<?xml version="1.0" encoding="utf-8" standalone="no"?>
<device schemaVersion="1.1">
  <name>STM32L152VBT6</name>
  <version>1.0</version>
  <description>STM32L152C6T6,STM32L152C6T6A,STM32L152C6U6,STM32L152C6U6A,STM32L152C8T6,STM32L152C8T6A,STM32L152C8U6,STM32L152C8U6A,STM32L152CBT6,STM32L152CBU6,STM32L152R6H6,STM32L152R6H6A,STM32L152R6T6,STM32L152R6T6A,STM32L152R8H6,STM32L152R8H6A,STM32L152R8T6,STM32L152R8T6A,STM32L152RBH6,STM32L152RBT6,STM32L152V8H6,STM32L152V8H6A,STM32L152V8T6,STM32L152V8T6A,STM32L152VBH6,STM32L152VBT6</description>
  <addressUnitBits>8</addressUnitBits>
  <width>32</width>
  <size>0x20</size>
  <resetValue>0</resetValue>
  <resetMask>0xFFFFFFFF</resetMask>
  <peripherals>
    <peripheral>
      <name>OB</name>
      <baseAddress>0x1ff80000</baseAddress>
      <registers>
        <register>
          <name>RDP</name>
          <addressOffset>0x0</addressOffset>
          <size>0x20</size>
        </register>
        <register>
          <name>USER</name>
          <addressOffset>0x4</addressOffset>
          <size>0x20</size>
        </register>
        <register>
          <name>WRP01</name>
          <addressOffset>0x8</addressOffset>
          <size>0x20</size>
        </register>
        <register>
          <name>WRP23</name>
          <addressOffset>0xc</addressOffset>
          <size>0x20</size>
        </register>
      </registers>
    </peripheral>
    <peripheral>
      <name>TIM2</name>
      <baseAddress>0x40000000</baseAddress>
      <registers>
        <register>
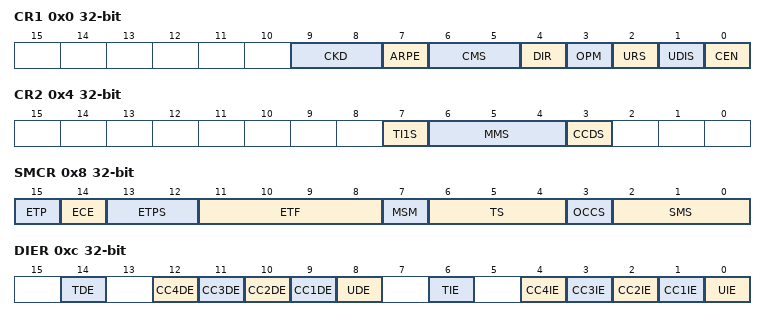
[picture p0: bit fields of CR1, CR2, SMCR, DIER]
          <name>CR1</name>
          <addressOffset>0x0</addressOffset>
          <size>0x20</size>
          <fields>
            <field>
              <name>CEN</name>
              <bitOffset>0</bitOffset>
              <bitWidth>1</bitWidth>
            </field>
            <field>
              <name>UDIS</name>
              <bitOffset>1</bitOffset>
              <bitWidth>1</bitWidth>
            </field>
            <field>
              <name>URS</name>
              <bitOffset>2</bitOffset>
              <bitWidth>1</bitWidth>
            </field>
            <field>
              <name>OPM</name>
              <bitOffset>3</bitOffset>
              <bitWidth>1</bitWidth>
            </field>
            <field>
              <name>DIR</name>
              <bitOffset>4</bitOffset>
              <bitWidth>1</bitWidth>
            </field>
            <field>
              <name>CMS</name>
              <bitOffset>5</bitOffset>
              <bitWidth>2</bitWidth>
            </field>
            <field>
              <name>ARPE</name>
              <bitOffset>7</bitOffset>
              <bitWidth>1</bitWidth>
            </field>
            <field>
              <name>CKD</name>
              <bitOffset>8</bitOffset>
              <bitWidth>2</bitWidth>
            </field>
          </fields>
        </register>
        <register>
          <name>CR2</name>
          <addressOffset>0x4</addressOffset>
          <size>0x20</size>
          <fields>
            <field>
              <name>CCDS</name>
              <bitOffset>3</bitOffset>
              <bitWidth>1</bitWidth>
            </field>
            <field>
              <name>MMS</name>
              <bitOffset>4</bitOffset>
              <bitWidth>3</bitWidth>
            </field>
            <field>
              <name>TI1S</name>
              <bitOffset>7</bitOffset>
              <bitWidth>1</bitWidth>
            </field>
          </fields>
        </register>
        <register>
          <name>SMCR</name>
          <addressOffset>0x8</addressOffset>
          <size>0x20</size>
          <fields>
            <field>
              <name>SMS</name>
              <bitOffset>0</bitOffset>
              <bitWidth>3</bitWidth>
            </field>
            <field>
              <name>OCCS</name>
              <bitOffset>3</bitOffset>
              <bitWidth>1</bitWidth>
            </field>
            <field>
              <name>TS</name>
              <bitOffset>4</bitOffset>
              <bitWidth>3</bitWidth>
            </field>
            <field>
              <name>MSM</name>
              <bitOffset>7</bitOffset>
              <bitWidth>1</bitWidth>
            </field>
            <field>
              <name>ETF</name>
              <bitOffset>8</bitOffset>
              <bitWidth>4</bitWidth>
            </field>
            <field>
              <name>ETPS</name>
              <bitOffset>12</bitOffset>
              <bitWidth>2</bitWidth>
            </field>
            <field>
              <name>ECE</name>
              <bitOffset>14</bitOffset>
              <bitWidth>1</bitWidth>
            </field>
            <field>
              <name>ETP</name>
              <bitOffset>15</bitOffset>
              <bitWidth>1</bitWidth>
            </field>
          </fields>
        </register>
        <register>
          <name>DIER</name>
          <addressOffset>0xc</addressOffset>
          <size>0x20</size>
          <fields>
            <field>
              <name>UIE</name>
              <bitOffset>0</bitOffset>
              <bitWidth>1</bitWidth>
            </field>
            <field>
              <name>CC1IE</name>
              <bitOffset>1</bitOffset>
              <bitWidth>1</bitWidth>
            </field>
            <field>
              <name>CC2IE</name>
              <bitOffset>2</bitOffset>
              <bitWidth>1</bitWidth>
            </field>
            <field>
              <name>CC3IE</name>
              <bitOffset>3</bitOffset>
              <bitWidth>1</bitWidth>
            </field>
            <field>
              <name>CC4IE</name>
              <bitOffset>4</bitOffset>
              <bitWidth>1</bitWidth>
            </field>
            <field>
              <name>TIE</name>
              <bitOffset>6</bitOffset>
              <bitWidth>1</bitWidth>
            </field>
            <field>
              <name>UDE</name>
              <bitOffset>8</bitOffset>
              <bitWidth>1</bitWidth>
            </field>
            <field>
              <name>CC1DE</name>
              <bitOffset>9</bitOffset>
              <bitWidth>1</bitWidth>
            </field>
            <field>
              <name>CC2DE</name>
              <bitOffset>10</bitOffset>
              <bitWidth>1</bitWidth>
            </field>
            <field>
              <name>CC3DE</name>
              <bitOffset>11</bitOffset>
              <bitWidth>1</bitWidth>
            </field>
            <field>
              <name>CC4DE</name>
              <bitOffset>12</bitOffset>
              <bitWidth>1</bitWidth>
            </field>
            <field>
              <name>TDE</name>
              <bitOffset>14</bitOffset>
              <bitWidth>1</bitWidth>
            </field>
          </fields>
        </register>
        <register>
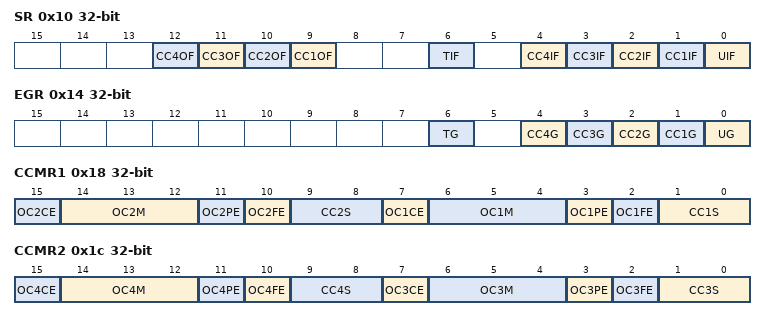
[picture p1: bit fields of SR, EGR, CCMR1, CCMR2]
          <name>SR</name>
          <addressOffset>0x10</addressOffset>
          <size>0x20</size>
          <fields>
            <field>
              <name>UIF</name>
              <bitOffset>0</bitOffset>
              <bitWidth>1</bitWidth>
            </field>
            <field>
              <name>CC1IF</name>
              <bitOffset>1</bitOffset>
              <bitWidth>1</bitWidth>
            </field>
            <field>
              <name>CC2IF</name>
              <bitOffset>2</bitOffset>
              <bitWidth>1</bitWidth>
            </field>
            <field>
              <name>CC3IF</name>
              <bitOffset>3</bitOffset>
              <bitWidth>1</bitWidth>
            </field>
            <field>
              <name>CC4IF</name>
              <bitOffset>4</bitOffset>
              <bitWidth>1</bitWidth>
            </field>
            <field>
              <name>TIF</name>
              <bitOffset>6</bitOffset>
              <bitWidth>1</bitWidth>
            </field>
            <field>
              <name>CC1OF</name>
              <bitOffset>9</bitOffset>
              <bitWidth>1</bitWidth>
            </field>
            <field>
              <name>CC2OF</name>
              <bitOffset>10</bitOffset>
              <bitWidth>1</bitWidth>
            </field>
            <field>
              <name>CC3OF</name>
              <bitOffset>11</bitOffset>
              <bitWidth>1</bitWidth>
            </field>
            <field>
              <name>CC4OF</name>
              <bitOffset>12</bitOffset>
              <bitWidth>1</bitWidth>
            </field>
          </fields>
        </register>
        <register>
          <name>EGR</name>
          <addressOffset>0x14</addressOffset>
          <size>0x20</size>
          <fields>
            <field>
              <name>UG</name>
              <bitOffset>0</bitOffset>
              <bitWidth>1</bitWidth>
            </field>
            <field>
              <name>CC1G</name>
              <bitOffset>1</bitOffset>
              <bitWidth>1</bitWidth>
            </field>
            <field>
              <name>CC2G</name>
              <bitOffset>2</bitOffset>
              <bitWidth>1</bitWidth>
            </field>
            <field>
              <name>CC3G</name>
              <bitOffset>3</bitOffset>
              <bitWidth>1</bitWidth>
            </field>
            <field>
              <name>CC4G</name>
              <bitOffset>4</bitOffset>
              <bitWidth>1</bitWidth>
            </field>
            <field>
              <name>TG</name>
              <bitOffset>6</bitOffset>
              <bitWidth>1</bitWidth>
            </field>
          </fields>
        </register>
        <register>
          <name>CCMR1</name>
          <addressOffset>0x18</addressOffset>
          <size>0x20</size>
          <fields>
            <field>
              <name>CC1S</name>
              <bitOffset>0</bitOffset>
              <bitWidth>2</bitWidth>
            </field>
            <field>
              <name>OC1FE</name>
              <bitOffset>2</bitOffset>
              <bitWidth>1</bitWidth>
            </field>
            <field>
              <name>OC1PE</name>
              <bitOffset>3</bitOffset>
              <bitWidth>1</bitWidth>
            </field>
            <field>
              <name>OC1M</name>
              <bitOffset>4</bitOffset>
              <bitWidth>3</bitWidth>
            </field>
            <field>
              <name>OC1CE</name>
              <bitOffset>7</bitOffset>
              <bitWidth>1</bitWidth>
            </field>
            <field>
              <name>CC2S</name>
              <bitOffset>8</bitOffset>
              <bitWidth>2</bitWidth>
            </field>
            <field>
              <name>OC2FE</name>
              <bitOffset>10</bitOffset>
              <bitWidth>1</bitWidth>
            </field>
            <field>
              <name>OC2PE</name>
              <bitOffset>11</bitOffset>
              <bitWidth>1</bitWidth>
            </field>
            <field>
              <name>OC2M</name>
              <bitOffset>12</bitOffset>
              <bitWidth>3</bitWidth>
            </field>
            <field>
              <name>OC2CE</name>
              <bitOffset>15</bitOffset>
              <bitWidth>1</bitWidth>
            </field>
          </fields>
        </register>
        <register>
          <name>CCMR2</name>
          <addressOffset>0x1c</addressOffset>
          <size>0x20</size>
          <fields>
            <field>
              <name>CC3S</name>
              <bitOffset>0</bitOffset>
              <bitWidth>2</bitWidth>
            </field>
            <field>
              <name>OC3FE</name>
              <bitOffset>2</bitOffset>
              <bitWidth>1</bitWidth>
            </field>
            <field>
              <name>OC3PE</name>
              <bitOffset>3</bitOffset>
              <bitWidth>1</bitWidth>
            </field>
            <field>
              <name>OC3M</name>
              <bitOffset>4</bitOffset>
              <bitWidth>3</bitWidth>
            </field>
            <field>
              <name>OC3CE</name>
              <bitOffset>7</bitOffset>
              <bitWidth>1</bitWidth>
            </field>
            <field>
              <name>CC4S</name>
              <bitOffset>8</bitOffset>
              <bitWidth>2</bitWidth>
            </field>
            <field>
              <name>OC4FE</name>
              <bitOffset>10</bitOffset>
              <bitWidth>1</bitWidth>
            </field>
            <field>
              <name>OC4PE</name>
              <bitOffset>11</bitOffset>
              <bitWidth>1</bitWidth>
            </field>
            <field>
              <name>OC4M</name>
              <bitOffset>12</bitOffset>
              <bitWidth>3</bitWidth>
            </field>
            <field>
              <name>OC4CE</name>
              <bitOffset>15</bitOffset>
              <bitWidth>1</bitWidth>
            </field>
          </fields>
        </register>
        <register>
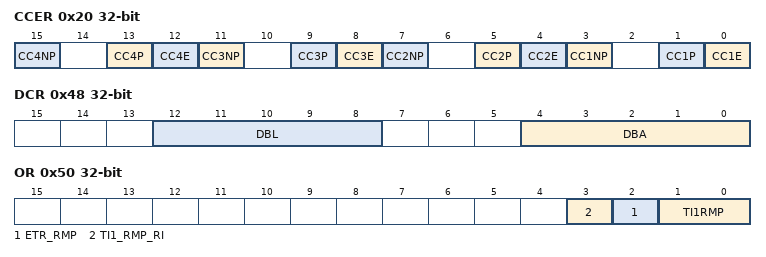
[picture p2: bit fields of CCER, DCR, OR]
          <name>CCER</name>
          <addressOffset>0x20</addressOffset>
          <size>0x20</size>
          <fields>
            <field>
              <name>CC1E</name>
              <bitOffset>0</bitOffset>
              <bitWidth>1</bitWidth>
            </field>
            <field>
              <name>CC1P</name>
              <bitOffset>1</bitOffset>
              <bitWidth>1</bitWidth>
            </field>
            <field>
              <name>CC1NP</name>
              <bitOffset>3</bitOffset>
              <bitWidth>1</bitWidth>
            </field>
            <field>
              <name>CC2E</name>
              <bitOffset>4</bitOffset>
              <bitWidth>1</bitWidth>
            </field>
            <field>
              <name>CC2P</name>
              <bitOffset>5</bitOffset>
              <bitWidth>1</bitWidth>
            </field>
            <field>
              <name>CC2NP</name>
              <bitOffset>7</bitOffset>
              <bitWidth>1</bitWidth>
            </field>
            <field>
              <name>CC3E</name>
              <bitOffset>8</bitOffset>
              <bitWidth>1</bitWidth>
            </field>
            <field>
              <name>CC3P</name>
              <bitOffset>9</bitOffset>
              <bitWidth>1</bitWidth>
            </field>
            <field>
              <name>CC3NP</name>
              <bitOffset>11</bitOffset>
              <bitWidth>1</bitWidth>
            </field>
            <field>
              <name>CC4E</name>
              <bitOffset>12</bitOffset>
              <bitWidth>1</bitWidth>
            </field>
            <field>
              <name>CC4P</name>
              <bitOffset>13</bitOffset>
              <bitWidth>1</bitWidth>
            </field>
            <field>
              <name>CC4NP</name>
              <bitOffset>15</bitOffset>
              <bitWidth>1</bitWidth>
            </field>
          </fields>
        </register>
        <register>
          <name>CNT</name>
          <addressOffset>0x24</addressOffset>
          <size>0x20</size>
          <fields>
            <field>
              <name>CNT</name>
              <bitOffset>0</bitOffset>
              <bitWidth>32</bitWidth>
            </field>
          </fields>
        </register>
        <register>
          <name>PSC</name>
          <addressOffset>0x28</addressOffset>
          <size>0x20</size>
          <fields>
            <field>
              <name>PSC</name>
              <bitOffset>0</bitOffset>
              <bitWidth>16</bitWidth>
            </field>
          </fields>
        </register>
        <register>
          <name>ARR</name>
          <addressOffset>0x2c</addressOffset>
          <size>0x20</size>
          <fields>
            <field>
              <name>ARR</name>
              <bitOffset>0</bitOffset>
              <bitWidth>32</bitWidth>
            </field>
          </fields>
        </register>
        <register>
          <name>CCR1</name>
          <addressOffset>0x34</addressOffset>
          <size>0x20</size>
          <fields>
            <field>
              <name>CCR1</name>
              <bitOffset>0</bitOffset>
              <bitWidth>16</bitWidth>
            </field>
          </fields>
        </register>
        <register>
          <name>CCR2</name>
          <addressOffset>0x38</addressOffset>
          <size>0x20</size>
          <fields>
            <field>
              <name>CCR2</name>
              <bitOffset>0</bitOffset>
              <bitWidth>16</bitWidth>
            </field>
          </fields>
        </register>
        <register>
          <name>CCR3</name>
          <addressOffset>0x3c</addressOffset>
          <size>0x20</size>
          <fields>
            <field>
              <name>CCR3</name>
              <bitOffset>0</bitOffset>
              <bitWidth>16</bitWidth>
            </field>
          </fields>
        </register>
        <register>
          <name>CCR4</name>
          <addressOffset>0x40</addressOffset>
          <size>0x20</size>
          <fields>
            <field>
              <name>CCR4</name>
              <bitOffset>0</bitOffset>
              <bitWidth>16</bitWidth>
            </field>
          </fields>
        </register>
        <register>
          <name>DCR</name>
          <addressOffset>0x48</addressOffset>
          <size>0x20</size>
          <fields>
            <field>
              <name>DBA</name>
              <bitOffset>0</bitOffset>
              <bitWidth>5</bitWidth>
            </field>
            <field>
              <name>DBL</name>
              <bitOffset>8</bitOffset>
              <bitWidth>5</bitWidth>
            </field>
          </fields>
        </register>
        <register>
          <name>DMAR</name>
          <addressOffset>0x4c</addressOffset>
          <size>0x20</size>
          <fields>
            <field>
              <name>DMAB</name>
              <bitOffset>0</bitOffset>
              <bitWidth>16</bitWidth>
            </field>
          </fields>
        </register>
        <register>
          <name>OR</name>
          <addressOffset>0x50</addressOffset>
          <size>0x20</size>
          <fields>
            <field>
              <name>TI1RMP</name>
              <bitOffset>0</bitOffset>
              <bitWidth>2</bitWidth>
            </field>
            <field>
              <name>ETR_RMP</name>
              <bitOffset>2</bitOffset>
              <bitWidth>1</bitWidth>
            </field>
            <field>
              <name>TI1_RMP_RI</name>
              <bitOffset>3</bitOffset>
              <bitWidth>1</bitWidth>
            </field>
          </fields>
        </register>
      </registers>
    </peripheral>
    <peripheral>
      <name>TIM3</name>
      <baseAddress>0x40000400</baseAddress>
      <registers>
        <register>
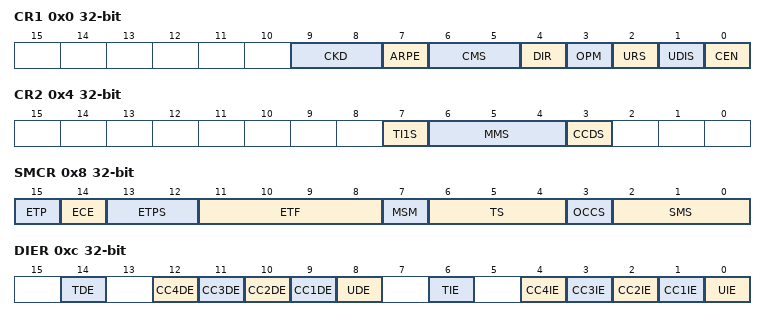
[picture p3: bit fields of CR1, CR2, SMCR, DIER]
          <name>CR1</name>
          <addressOffset>0x0</addressOffset>
          <size>0x20</size>
          <fields>
            <field>
              <name>CEN</name>
              <bitOffset>0</bitOffset>
              <bitWidth>1</bitWidth>
            </field>
            <field>
              <name>UDIS</name>
              <bitOffset>1</bitOffset>
              <bitWidth>1</bitWidth>
            </field>
            <field>
              <name>URS</name>
              <bitOffset>2</bitOffset>
              <bitWidth>1</bitWidth>
            </field>
            <field>
              <name>OPM</name>
              <bitOffset>3</bitOffset>
              <bitWidth>1</bitWidth>
            </field>
            <field>
              <name>DIR</name>
              <bitOffset>4</bitOffset>
              <bitWidth>1</bitWidth>
            </field>
            <field>
              <name>CMS</name>
              <bitOffset>5</bitOffset>
              <bitWidth>2</bitWidth>
            </field>
            <field>
              <name>ARPE</name>
              <bitOffset>7</bitOffset>
              <bitWidth>1</bitWidth>
            </field>
            <field>
              <name>CKD</name>
              <bitOffset>8</bitOffset>
              <bitWidth>2</bitWidth>
            </field>
          </fields>
        </register>
        <register>
          <name>CR2</name>
          <addressOffset>0x4</addressOffset>
          <size>0x20</size>
          <fields>
            <field>
              <name>CCDS</name>
              <bitOffset>3</bitOffset>
              <bitWidth>1</bitWidth>
            </field>
            <field>
              <name>MMS</name>
              <bitOffset>4</bitOffset>
              <bitWidth>3</bitWidth>
            </field>
            <field>
              <name>TI1S</name>
              <bitOffset>7</bitOffset>
              <bitWidth>1</bitWidth>
            </field>
          </fields>
        </register>
        <register>
          <name>SMCR</name>
          <addressOffset>0x8</addressOffset>
          <size>0x20</size>
          <fields>
            <field>
              <name>SMS</name>
              <bitOffset>0</bitOffset>
              <bitWidth>3</bitWidth>
            </field>
            <field>
              <name>OCCS</name>
              <bitOffset>3</bitOffset>
              <bitWidth>1</bitWidth>
            </field>
            <field>
              <name>TS</name>
              <bitOffset>4</bitOffset>
              <bitWidth>3</bitWidth>
            </field>
            <field>
              <name>MSM</name>
              <bitOffset>7</bitOffset>
              <bitWidth>1</bitWidth>
            </field>
            <field>
              <name>ETF</name>
              <bitOffset>8</bitOffset>
              <bitWidth>4</bitWidth>
            </field>
            <field>
              <name>ETPS</name>
              <bitOffset>12</bitOffset>
              <bitWidth>2</bitWidth>
            </field>
            <field>
              <name>ECE</name>
              <bitOffset>14</bitOffset>
              <bitWidth>1</bitWidth>
            </field>
            <field>
              <name>ETP</name>
              <bitOffset>15</bitOffset>
              <bitWidth>1</bitWidth>
            </field>
          </fields>
        </register>
        <register>
          <name>DIER</name>
          <addressOffset>0xc</addressOffset>
          <size>0x20</size>
          <fields>
            <field>
              <name>UIE</name>
              <bitOffset>0</bitOffset>
              <bitWidth>1</bitWidth>
            </field>
            <field>
              <name>CC1IE</name>
              <bitOffset>1</bitOffset>
              <bitWidth>1</bitWidth>
            </field>
            <field>
              <name>CC2IE</name>
              <bitOffset>2</bitOffset>
              <bitWidth>1</bitWidth>
            </field>
            <field>
              <name>CC3IE</name>
              <bitOffset>3</bitOffset>
              <bitWidth>1</bitWidth>
            </field>
            <field>
              <name>CC4IE</name>
              <bitOffset>4</bitOffset>
              <bitWidth>1</bitWidth>
            </field>
            <field>
              <name>TIE</name>
              <bitOffset>6</bitOffset>
              <bitWidth>1</bitWidth>
            </field>
            <field>
              <name>UDE</name>
              <bitOffset>8</bitOffset>
              <bitWidth>1</bitWidth>
            </field>
            <field>
              <name>CC1DE</name>
              <bitOffset>9</bitOffset>
              <bitWidth>1</bitWidth>
            </field>
            <field>
              <name>CC2DE</name>
              <bitOffset>10</bitOffset>
              <bitWidth>1</bitWidth>
            </field>
            <field>
              <name>CC3DE</name>
              <bitOffset>11</bitOffset>
              <bitWidth>1</bitWidth>
            </field>
            <field>
              <name>CC4DE</name>
              <bitOffset>12</bitOffset>
              <bitWidth>1</bitWidth>
            </field>
            <field>
              <name>TDE</name>
              <bitOffset>14</bitOffset>
              <bitWidth>1</bitWidth>
            </field>
          </fields>
        </register>
        <register>
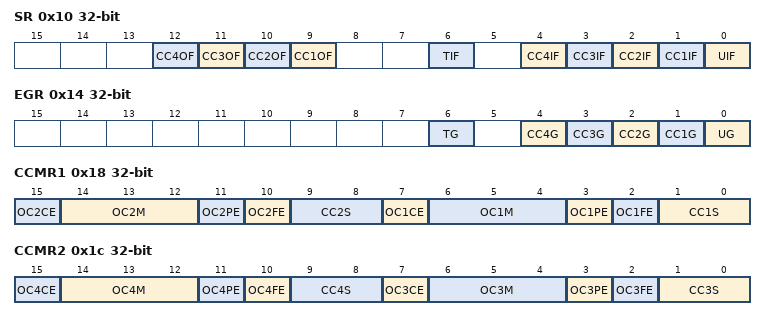
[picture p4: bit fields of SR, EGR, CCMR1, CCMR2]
          <name>SR</name>
          <addressOffset>0x10</addressOffset>
          <size>0x20</size>
          <fields>
            <field>
              <name>UIF</name>
              <bitOffset>0</bitOffset>
              <bitWidth>1</bitWidth>
            </field>
            <field>
              <name>CC1IF</name>
              <bitOffset>1</bitOffset>
              <bitWidth>1</bitWidth>
            </field>
            <field>
              <name>CC2IF</name>
              <bitOffset>2</bitOffset>
              <bitWidth>1</bitWidth>
            </field>
            <field>
              <name>CC3IF</name>
              <bitOffset>3</bitOffset>
              <bitWidth>1</bitWidth>
            </field>
            <field>
              <name>CC4IF</name>
              <bitOffset>4</bitOffset>
              <bitWidth>1</bitWidth>
            </field>
            <field>
              <name>TIF</name>
              <bitOffset>6</bitOffset>
              <bitWidth>1</bitWidth>
            </field>
            <field>
              <name>CC1OF</name>
              <bitOffset>9</bitOffset>
              <bitWidth>1</bitWidth>
            </field>
            <field>
              <name>CC2OF</name>
              <bitOffset>10</bitOffset>
              <bitWidth>1</bitWidth>
            </field>
            <field>
              <name>CC3OF</name>
              <bitOffset>11</bitOffset>
              <bitWidth>1</bitWidth>
            </field>
            <field>
              <name>CC4OF</name>
              <bitOffset>12</bitOffset>
              <bitWidth>1</bitWidth>
            </field>
          </fields>
        </register>
        <register>
          <name>EGR</name>
          <addressOffset>0x14</addressOffset>
          <size>0x20</size>
          <fields>
            <field>
              <name>UG</name>
              <bitOffset>0</bitOffset>
              <bitWidth>1</bitWidth>
            </field>
            <field>
              <name>CC1G</name>
              <bitOffset>1</bitOffset>
              <bitWidth>1</bitWidth>
            </field>
            <field>
              <name>CC2G</name>
              <bitOffset>2</bitOffset>
              <bitWidth>1</bitWidth>
            </field>
            <field>
              <name>CC3G</name>
              <bitOffset>3</bitOffset>
              <bitWidth>1</bitWidth>
            </field>
            <field>
              <name>CC4G</name>
              <bitOffset>4</bitOffset>
              <bitWidth>1</bitWidth>
            </field>
            <field>
              <name>TG</name>
              <bitOffset>6</bitOffset>
              <bitWidth>1</bitWidth>
            </field>
          </fields>
        </register>
        <register>
          <name>CCMR1</name>
          <addressOffset>0x18</addressOffset>
          <size>0x20</size>
          <fields>
            <field>
              <name>CC1S</name>
              <bitOffset>0</bitOffset>
              <bitWidth>2</bitWidth>
            </field>
            <field>
              <name>OC1FE</name>
              <bitOffset>2</bitOffset>
              <bitWidth>1</bitWidth>
            </field>
            <field>
              <name>OC1PE</name>
              <bitOffset>3</bitOffset>
              <bitWidth>1</bitWidth>
            </field>
            <field>
              <name>OC1M</name>
              <bitOffset>4</bitOffset>
              <bitWidth>3</bitWidth>
            </field>
            <field>
              <name>OC1CE</name>
              <bitOffset>7</bitOffset>
              <bitWidth>1</bitWidth>
            </field>
            <field>
              <name>CC2S</name>
              <bitOffset>8</bitOffset>
              <bitWidth>2</bitWidth>
            </field>
            <field>
              <name>OC2FE</name>
              <bitOffset>10</bitOffset>
              <bitWidth>1</bitWidth>
            </field>
            <field>
              <name>OC2PE</name>
              <bitOffset>11</bitOffset>
              <bitWidth>1</bitWidth>
            </field>
            <field>
              <name>OC2M</name>
              <bitOffset>12</bitOffset>
              <bitWidth>3</bitWidth>
            </field>
            <field>
              <name>OC2CE</name>
              <bitOffset>15</bitOffset>
              <bitWidth>1</bitWidth>
            </field>
          </fields>
        </register>
        <register>
          <name>CCMR2</name>
          <addressOffset>0x1c</addressOffset>
          <size>0x20</size>
          <fields>
            <field>
              <name>CC3S</name>
              <bitOffset>0</bitOffset>
              <bitWidth>2</bitWidth>
            </field>
            <field>
              <name>OC3FE</name>
              <bitOffset>2</bitOffset>
              <bitWidth>1</bitWidth>
            </field>
            <field>
              <name>OC3PE</name>
              <bitOffset>3</bitOffset>
              <bitWidth>1</bitWidth>
            </field>
            <field>
              <name>OC3M</name>
              <bitOffset>4</bitOffset>
              <bitWidth>3</bitWidth>
            </field>
            <field>
              <name>OC3CE</name>
              <bitOffset>7</bitOffset>
              <bitWidth>1</bitWidth>
            </field>
            <field>
              <name>CC4S</name>
              <bitOffset>8</bitOffset>
              <bitWidth>2</bitWidth>
            </field>
            <field>
              <name>OC4FE</name>
              <bitOffset>10</bitOffset>
              <bitWidth>1</bitWidth>
            </field>
            <field>
              <name>OC4PE</name>
              <bitOffset>11</bitOffset>
              <bitWidth>1</bitWidth>
            </field>
            <field>
              <name>OC4M</name>
              <bitOffset>12</bitOffset>
              <bitWidth>3</bitWidth>
            </field>
            <field>
              <name>OC4CE</name>
              <bitOffset>15</bitOffset>
              <bitWidth>1</bitWidth>
            </field>
          </fields>
        </register>
        <register>
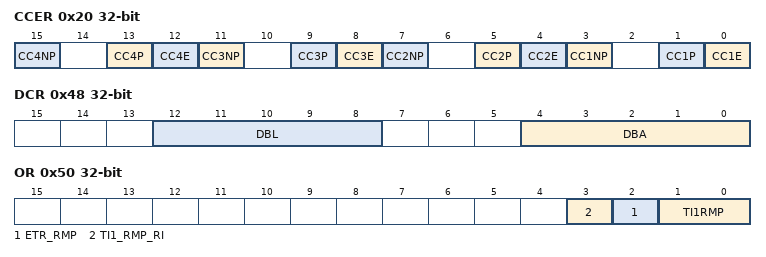
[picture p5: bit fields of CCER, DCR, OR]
          <name>CCER</name>
          <addressOffset>0x20</addressOffset>
          <size>0x20</size>
          <fields>
            <field>
              <name>CC1E</name>
              <bitOffset>0</bitOffset>
              <bitWidth>1</bitWidth>
            </field>
            <field>
              <name>CC1P</name>
              <bitOffset>1</bitOffset>
              <bitWidth>1</bitWidth>
            </field>
            <field>
              <name>CC1NP</name>
              <bitOffset>3</bitOffset>
              <bitWidth>1</bitWidth>
            </field>
            <field>
              <name>CC2E</name>
              <bitOffset>4</bitOffset>
              <bitWidth>1</bitWidth>
            </field>
            <field>
              <name>CC2P</name>
              <bitOffset>5</bitOffset>
              <bitWidth>1</bitWidth>
            </field>
            <field>
              <name>CC2NP</name>
              <bitOffset>7</bitOffset>
              <bitWidth>1</bitWidth>
            </field>
            <field>
              <name>CC3E</name>
              <bitOffset>8</bitOffset>
              <bitWidth>1</bitWidth>
            </field>
            <field>
              <name>CC3P</name>
              <bitOffset>9</bitOffset>
              <bitWidth>1</bitWidth>
            </field>
            <field>
              <name>CC3NP</name>
              <bitOffset>11</bitOffset>
              <bitWidth>1</bitWidth>
            </field>
            <field>
              <name>CC4E</name>
              <bitOffset>12</bitOffset>
              <bitWidth>1</bitWidth>
            </field>
            <field>
              <name>CC4P</name>
              <bitOffset>13</bitOffset>
              <bitWidth>1</bitWidth>
            </field>
            <field>
              <name>CC4NP</name>
              <bitOffset>15</bitOffset>
              <bitWidth>1</bitWidth>
            </field>
          </fields>
        </register>
        <register>
          <name>CNT</name>
          <addressOffset>0x24</addressOffset>
          <size>0x20</size>
          <fields>
            <field>
              <name>CNT</name>
              <bitOffset>0</bitOffset>
              <bitWidth>32</bitWidth>
            </field>
          </fields>
        </register>
        <register>
          <name>PSC</name>
          <addressOffset>0x28</addressOffset>
          <size>0x20</size>
          <fields>
            <field>
              <name>PSC</name>
              <bitOffset>0</bitOffset>
              <bitWidth>16</bitWidth>
            </field>
          </fields>
        </register>
        <register>
          <name>ARR</name>
          <addressOffset>0x2c</addressOffset>
          <size>0x20</size>
          <fields>
            <field>
              <name>ARR</name>
              <bitOffset>0</bitOffset>
              <bitWidth>32</bitWidth>
            </field>
          </fields>
        </register>
        <register>
          <name>CCR1</name>
          <addressOffset>0x34</addressOffset>
          <size>0x20</size>
          <fields>
            <field>
              <name>CCR1</name>
              <bitOffset>0</bitOffset>
              <bitWidth>16</bitWidth>
            </field>
          </fields>
        </register>
        <register>
          <name>CCR2</name>
          <addressOffset>0x38</addressOffset>
          <size>0x20</size>
          <fields>
            <field>
              <name>CCR2</name>
              <bitOffset>0</bitOffset>
              <bitWidth>16</bitWidth>
            </field>
          </fields>
        </register>
        <register>
          <name>CCR3</name>
          <addressOffset>0x3c</addressOffset>
          <size>0x20</size>
          <fields>
            <field>
              <name>CCR3</name>
              <bitOffset>0</bitOffset>
              <bitWidth>16</bitWidth>
            </field>
          </fields>
        </register>
        <register>
          <name>CCR4</name>
          <addressOffset>0x40</addressOffset>
          <size>0x20</size>
          <fields>
            <field>
              <name>CCR4</name>
              <bitOffset>0</bitOffset>
              <bitWidth>16</bitWidth>
            </field>
          </fields>
        </register>
        <register>
          <name>DCR</name>
          <addressOffset>0x48</addressOffset>
          <size>0x20</size>
          <fields>
            <field>
              <name>DBA</name>
              <bitOffset>0</bitOffset>
              <bitWidth>5</bitWidth>
            </field>
            <field>
              <name>DBL</name>
              <bitOffset>8</bitOffset>
              <bitWidth>5</bitWidth>
            </field>
          </fields>
        </register>
        <register>
          <name>DMAR</name>
          <addressOffset>0x4c</addressOffset>
          <size>0x20</size>
          <fields>
            <field>
              <name>DMAB</name>
              <bitOffset>0</bitOffset>
              <bitWidth>16</bitWidth>
            </field>
          </fields>
        </register>
        <register>
          <name>OR</name>
          <addressOffset>0x50</addressOffset>
          <size>0x20</size>
          <fields>
            <field>
              <name>TI1RMP</name>
              <bitOffset>0</bitOffset>
              <bitWidth>2</bitWidth>
            </field>
            <field>
              <name>ETR_RMP</name>
              <bitOffset>2</bitOffset>
              <bitWidth>1</bitWidth>
            </field>
            <field>
              <name>TI1_RMP_RI</name>
              <bitOffset>3</bitOffset>
              <bitWidth>1</bitWidth>
            </field>
          </fields>
        </register>
      </registers>
    </peripheral>
    <peripheral>
      <name>TIM4</name>
      <baseAddress>0x40000800</baseAddress>
      <registers>
        <register>
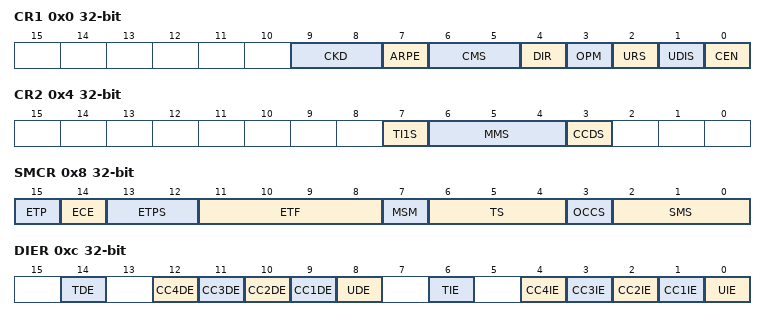
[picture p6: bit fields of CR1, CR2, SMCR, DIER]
          <name>CR1</name>
          <addressOffset>0x0</addressOffset>
          <size>0x20</size>
          <fields>
            <field>
              <name>CEN</name>
              <bitOffset>0</bitOffset>
              <bitWidth>1</bitWidth>
            </field>
            <field>
              <name>UDIS</name>
              <bitOffset>1</bitOffset>
              <bitWidth>1</bitWidth>
            </field>
            <field>
              <name>URS</name>
              <bitOffset>2</bitOffset>
              <bitWidth>1</bitWidth>
            </field>
            <field>
              <name>OPM</name>
              <bitOffset>3</bitOffset>
              <bitWidth>1</bitWidth>
            </field>
            <field>
              <name>DIR</name>
              <bitOffset>4</bitOffset>
              <bitWidth>1</bitWidth>
            </field>
            <field>
              <name>CMS</name>
              <bitOffset>5</bitOffset>
              <bitWidth>2</bitWidth>
            </field>
            <field>
              <name>ARPE</name>
              <bitOffset>7</bitOffset>
              <bitWidth>1</bitWidth>
            </field>
            <field>
              <name>CKD</name>
              <bitOffset>8</bitOffset>
              <bitWidth>2</bitWidth>
            </field>
          </fields>
        </register>
        <register>
          <name>CR2</name>
          <addressOffset>0x4</addressOffset>
          <size>0x20</size>
          <fields>
            <field>
              <name>CCDS</name>
              <bitOffset>3</bitOffset>
              <bitWidth>1</bitWidth>
            </field>
            <field>
              <name>MMS</name>
              <bitOffset>4</bitOffset>
              <bitWidth>3</bitWidth>
            </field>
            <field>
              <name>TI1S</name>
              <bitOffset>7</bitOffset>
              <bitWidth>1</bitWidth>
            </field>
          </fields>
        </register>
        <register>
          <name>SMCR</name>
          <addressOffset>0x8</addressOffset>
          <size>0x20</size>
          <fields>
            <field>
              <name>SMS</name>
              <bitOffset>0</bitOffset>
              <bitWidth>3</bitWidth>
            </field>
            <field>
              <name>OCCS</name>
              <bitOffset>3</bitOffset>
              <bitWidth>1</bitWidth>
            </field>
            <field>
              <name>TS</name>
              <bitOffset>4</bitOffset>
              <bitWidth>3</bitWidth>
            </field>
            <field>
              <name>MSM</name>
              <bitOffset>7</bitOffset>
              <bitWidth>1</bitWidth>
            </field>
            <field>
              <name>ETF</name>
              <bitOffset>8</bitOffset>
              <bitWidth>4</bitWidth>
            </field>
            <field>
              <name>ETPS</name>
              <bitOffset>12</bitOffset>
              <bitWidth>2</bitWidth>
            </field>
            <field>
              <name>ECE</name>
              <bitOffset>14</bitOffset>
              <bitWidth>1</bitWidth>
            </field>
            <field>
              <name>ETP</name>
              <bitOffset>15</bitOffset>
              <bitWidth>1</bitWidth>
            </field>
          </fields>
        </register>
        <register>
          <name>DIER</name>
          <addressOffset>0xc</addressOffset>
          <size>0x20</size>
          <fields>
            <field>
              <name>UIE</name>
              <bitOffset>0</bitOffset>
              <bitWidth>1</bitWidth>
            </field>
            <field>
              <name>CC1IE</name>
              <bitOffset>1</bitOffset>
              <bitWidth>1</bitWidth>
            </field>
            <field>
              <name>CC2IE</name>
              <bitOffset>2</bitOffset>
              <bitWidth>1</bitWidth>
            </field>
            <field>
              <name>CC3IE</name>
              <bitOffset>3</bitOffset>
              <bitWidth>1</bitWidth>
            </field>
            <field>
              <name>CC4IE</name>
              <bitOffset>4</bitOffset>
              <bitWidth>1</bitWidth>
            </field>
            <field>
              <name>TIE</name>
              <bitOffset>6</bitOffset>
              <bitWidth>1</bitWidth>
            </field>
            <field>
              <name>UDE</name>
              <bitOffset>8</bitOffset>
              <bitWidth>1</bitWidth>
            </field>
            <field>
              <name>CC1DE</name>
              <bitOffset>9</bitOffset>
              <bitWidth>1</bitWidth>
            </field>
            <field>
              <name>CC2DE</name>
              <bitOffset>10</bitOffset>
              <bitWidth>1</bitWidth>
            </field>
            <field>
              <name>CC3DE</name>
              <bitOffset>11</bitOffset>
              <bitWidth>1</bitWidth>
            </field>
            <field>
              <name>CC4DE</name>
              <bitOffset>12</bitOffset>
              <bitWidth>1</bitWidth>
            </field>
            <field>
              <name>TDE</name>
              <bitOffset>14</bitOffset>
              <bitWidth>1</bitWidth>
            </field>
          </fields>
        </register>
        <register>
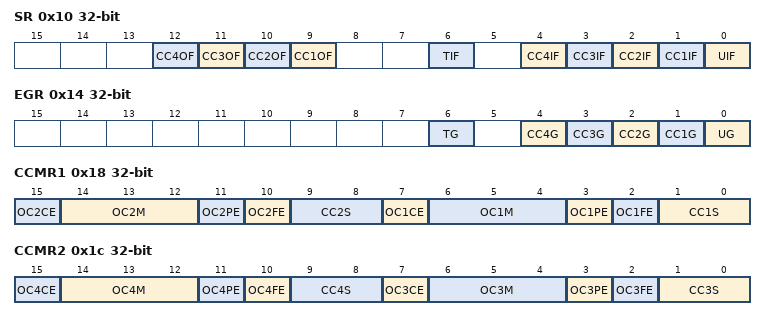
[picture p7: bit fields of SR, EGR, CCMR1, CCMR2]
          <name>SR</name>
          <addressOffset>0x10</addressOffset>
          <size>0x20</size>
          <fields>
            <field>
              <name>UIF</name>
              <bitOffset>0</bitOffset>
              <bitWidth>1</bitWidth>
            </field>
            <field>
              <name>CC1IF</name>
              <bitOffset>1</bitOffset>
              <bitWidth>1</bitWidth>
            </field>
            <field>
              <name>CC2IF</name>
              <bitOffset>2</bitOffset>
              <bitWidth>1</bitWidth>
            </field>
            <field>
              <name>CC3IF</name>
              <bitOffset>3</bitOffset>
              <bitWidth>1</bitWidth>
            </field>
            <field>
              <name>CC4IF</name>
              <bitOffset>4</bitOffset>
              <bitWidth>1</bitWidth>
            </field>
            <field>
              <name>TIF</name>
              <bitOffset>6</bitOffset>
              <bitWidth>1</bitWidth>
            </field>
            <field>
              <name>CC1OF</name>
              <bitOffset>9</bitOffset>
              <bitWidth>1</bitWidth>
            </field>
            <field>
              <name>CC2OF</name>
              <bitOffset>10</bitOffset>
              <bitWidth>1</bitWidth>
            </field>
            <field>
              <name>CC3OF</name>
              <bitOffset>11</bitOffset>
              <bitWidth>1</bitWidth>
            </field>
            <field>
              <name>CC4OF</name>
              <bitOffset>12</bitOffset>
              <bitWidth>1</bitWidth>
            </field>
          </fields>
        </register>
        <register>
          <name>EGR</name>
          <addressOffset>0x14</addressOffset>
          <size>0x20</size>
          <fields>
            <field>
              <name>UG</name>
              <bitOffset>0</bitOffset>
              <bitWidth>1</bitWidth>
            </field>
            <field>
              <name>CC1G</name>
              <bitOffset>1</bitOffset>
              <bitWidth>1</bitWidth>
            </field>
            <field>
              <name>CC2G</name>
              <bitOffset>2</bitOffset>
              <bitWidth>1</bitWidth>
            </field>
            <field>
              <name>CC3G</name>
              <bitOffset>3</bitOffset>
              <bitWidth>1</bitWidth>
            </field>
            <field>
              <name>CC4G</name>
              <bitOffset>4</bitOffset>
              <bitWidth>1</bitWidth>
            </field>
            <field>
              <name>TG</name>
              <bitOffset>6</bitOffset>
              <bitWidth>1</bitWidth>
            </field>
          </fields>
        </register>
        <register>
          <name>CCMR1</name>
          <addressOffset>0x18</addressOffset>
          <size>0x20</size>
          <fields>
            <field>
              <name>CC1S</name>
              <bitOffset>0</bitOffset>
              <bitWidth>2</bitWidth>
            </field>
            <field>
              <name>OC1FE</name>
              <bitOffset>2</bitOffset>
              <bitWidth>1</bitWidth>
            </field>
            <field>
              <name>OC1PE</name>
              <bitOffset>3</bitOffset>
              <bitWidth>1</bitWidth>
            </field>
            <field>
              <name>OC1M</name>
              <bitOffset>4</bitOffset>
              <bitWidth>3</bitWidth>
            </field>
            <field>
              <name>OC1CE</name>
              <bitOffset>7</bitOffset>
              <bitWidth>1</bitWidth>
            </field>
            <field>
              <name>CC2S</name>
              <bitOffset>8</bitOffset>
              <bitWidth>2</bitWidth>
            </field>
            <field>
              <name>OC2FE</name>
              <bitOffset>10</bitOffset>
              <bitWidth>1</bitWidth>
            </field>
            <field>
              <name>OC2PE</name>
              <bitOffset>11</bitOffset>
              <bitWidth>1</bitWidth>
            </field>
            <field>
              <name>OC2M</name>
              <bitOffset>12</bitOffset>
              <bitWidth>3</bitWidth>
            </field>
            <field>
              <name>OC2CE</name>
              <bitOffset>15</bitOffset>
              <bitWidth>1</bitWidth>
            </field>
          </fields>
        </register>
        <register>
          <name>CCMR2</name>
          <addressOffset>0x1c</addressOffset>
          <size>0x20</size>
          <fields>
            <field>
              <name>CC3S</name>
              <bitOffset>0</bitOffset>
              <bitWidth>2</bitWidth>
            </field>
            <field>
              <name>OC3FE</name>
              <bitOffset>2</bitOffset>
              <bitWidth>1</bitWidth>
            </field>
            <field>
              <name>OC3PE</name>
              <bitOffset>3</bitOffset>
              <bitWidth>1</bitWidth>
            </field>
            <field>
              <name>OC3M</name>
              <bitOffset>4</bitOffset>
              <bitWidth>3</bitWidth>
            </field>
            <field>
              <name>OC3CE</name>
              <bitOffset>7</bitOffset>
              <bitWidth>1</bitWidth>
            </field>
            <field>
              <name>CC4S</name>
              <bitOffset>8</bitOffset>
              <bitWidth>2</bitWidth>
            </field>
            <field>
              <name>OC4FE</name>
              <bitOffset>10</bitOffset>
              <bitWidth>1</bitWidth>
            </field>
            <field>
              <name>OC4PE</name>
              <bitOffset>11</bitOffset>
              <bitWidth>1</bitWidth>
            </field>
            <field>
              <name>OC4M</name>
              <bitOffset>12</bitOffset>
              <bitWidth>3</bitWidth>
            </field>
            <field>
              <name>OC4CE</name>
              <bitOffset>15</bitOffset>
              <bitWidth>1</bitWidth>
            </field>
          </fields>
        </register>
        <register>
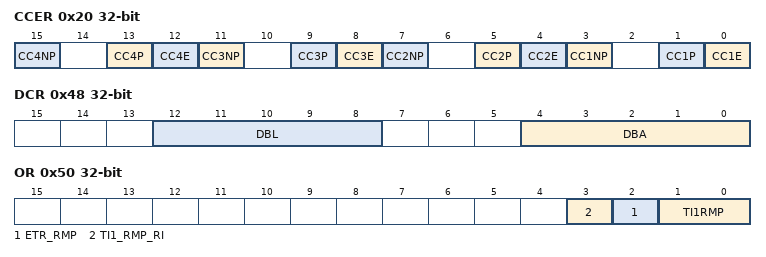
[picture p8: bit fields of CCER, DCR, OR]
          <name>CCER</name>
          <addressOffset>0x20</addressOffset>
          <size>0x20</size>
          <fields>
            <field>
              <name>CC1E</name>
              <bitOffset>0</bitOffset>
              <bitWidth>1</bitWidth>
            </field>
            <field>
              <name>CC1P</name>
              <bitOffset>1</bitOffset>
              <bitWidth>1</bitWidth>
            </field>
            <field>
              <name>CC1NP</name>
              <bitOffset>3</bitOffset>
              <bitWidth>1</bitWidth>
            </field>
            <field>
              <name>CC2E</name>
              <bitOffset>4</bitOffset>
              <bitWidth>1</bitWidth>
            </field>
            <field>
              <name>CC2P</name>
              <bitOffset>5</bitOffset>
              <bitWidth>1</bitWidth>
            </field>
            <field>
              <name>CC2NP</name>
              <bitOffset>7</bitOffset>
              <bitWidth>1</bitWidth>
            </field>
            <field>
              <name>CC3E</name>
              <bitOffset>8</bitOffset>
              <bitWidth>1</bitWidth>
            </field>
            <field>
              <name>CC3P</name>
              <bitOffset>9</bitOffset>
              <bitWidth>1</bitWidth>
            </field>
            <field>
              <name>CC3NP</name>
              <bitOffset>11</bitOffset>
              <bitWidth>1</bitWidth>
            </field>
            <field>
              <name>CC4E</name>
              <bitOffset>12</bitOffset>
              <bitWidth>1</bitWidth>
            </field>
            <field>
              <name>CC4P</name>
              <bitOffset>13</bitOffset>
              <bitWidth>1</bitWidth>
            </field>
            <field>
              <name>CC4NP</name>
              <bitOffset>15</bitOffset>
              <bitWidth>1</bitWidth>
            </field>
          </fields>
        </register>
        <register>
          <name>CNT</name>
          <addressOffset>0x24</addressOffset>
          <size>0x20</size>
          <fields>
            <field>
              <name>CNT</name>
              <bitOffset>0</bitOffset>
              <bitWidth>32</bitWidth>
            </field>
          </fields>
        </register>
        <register>
          <name>PSC</name>
          <addressOffset>0x28</addressOffset>
          <size>0x20</size>
          <fields>
            <field>
              <name>PSC</name>
              <bitOffset>0</bitOffset>
              <bitWidth>16</bitWidth>
            </field>
          </fields>
        </register>
        <register>
          <name>ARR</name>
          <addressOffset>0x2c</addressOffset>
          <size>0x20</size>
          <fields>
            <field>
              <name>ARR</name>
              <bitOffset>0</bitOffset>
              <bitWidth>32</bitWidth>
            </field>
          </fields>
        </register>
        <register>
          <name>CCR1</name>
          <addressOffset>0x34</addressOffset>
          <size>0x20</size>
          <fields>
            <field>
              <name>CCR1</name>
              <bitOffset>0</bitOffset>
              <bitWidth>16</bitWidth>
            </field>
          </fields>
        </register>
        <register>
          <name>CCR2</name>
          <addressOffset>0x38</addressOffset>
          <size>0x20</size>
          <fields>
            <field>
              <name>CCR2</name>
              <bitOffset>0</bitOffset>
              <bitWidth>16</bitWidth>
            </field>
          </fields>
        </register>
        <register>
          <name>CCR3</name>
          <addressOffset>0x3c</addressOffset>
          <size>0x20</size>
          <fields>
            <field>
              <name>CCR3</name>
              <bitOffset>0</bitOffset>
              <bitWidth>16</bitWidth>
            </field>
          </fields>
        </register>
        <register>
          <name>CCR4</name>
          <addressOffset>0x40</addressOffset>
          <size>0x20</size>
          <fields>
            <field>
              <name>CCR4</name>
              <bitOffset>0</bitOffset>
              <bitWidth>16</bitWidth>
            </field>
          </fields>
        </register>
        <register>
          <name>DCR</name>
          <addressOffset>0x48</addressOffset>
          <size>0x20</size>
          <fields>
            <field>
              <name>DBA</name>
              <bitOffset>0</bitOffset>
              <bitWidth>5</bitWidth>
            </field>
            <field>
              <name>DBL</name>
              <bitOffset>8</bitOffset>
              <bitWidth>5</bitWidth>
            </field>
          </fields>
        </register>
        <register>
          <name>DMAR</name>
          <addressOffset>0x4c</addressOffset>
          <size>0x20</size>
          <fields>
            <field>
              <name>DMAB</name>
              <bitOffset>0</bitOffset>
              <bitWidth>16</bitWidth>
            </field>
          </fields>
        </register>
        <register>
          <name>OR</name>
          <addressOffset>0x50</addressOffset>
          <size>0x20</size>
          <fields>
            <field>
              <name>TI1RMP</name>
              <bitOffset>0</bitOffset>
              <bitWidth>2</bitWidth>
            </field>
            <field>
              <name>ETR_RMP</name>
              <bitOffset>2</bitOffset>
              <bitWidth>1</bitWidth>
            </field>
            <field>
              <name>TI1_RMP_RI</name>
              <bitOffset>3</bitOffset>
              <bitWidth>1</bitWidth>
            </field>
          </fields>
        </register>
      </registers>
    </peripheral>
    <peripheral>
      <name>TIM6</name>
      <baseAddress>0x40001000</baseAddress>
      <registers>
        <register>
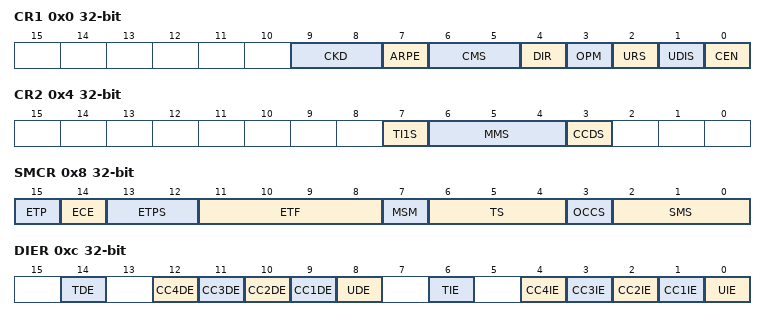
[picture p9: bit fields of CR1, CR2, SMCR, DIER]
          <name>CR1</name>
          <addressOffset>0x0</addressOffset>
          <size>0x20</size>
          <fields>
            <field>
              <name>CEN</name>
              <bitOffset>0</bitOffset>
              <bitWidth>1</bitWidth>
            </field>
            <field>
              <name>UDIS</name>
              <bitOffset>1</bitOffset>
              <bitWidth>1</bitWidth>
            </field>
            <field>
              <name>URS</name>
              <bitOffset>2</bitOffset>
              <bitWidth>1</bitWidth>
            </field>
            <field>
              <name>OPM</name>
              <bitOffset>3</bitOffset>
              <bitWidth>1</bitWidth>
            </field>
            <field>
              <name>DIR</name>
              <bitOffset>4</bitOffset>
              <bitWidth>1</bitWidth>
            </field>
            <field>
              <name>CMS</name>
              <bitOffset>5</bitOffset>
              <bitWidth>2</bitWidth>
            </field>
            <field>
              <name>ARPE</name>
              <bitOffset>7</bitOffset>
              <bitWidth>1</bitWidth>
            </field>
            <field>
              <name>CKD</name>
              <bitOffset>8</bitOffset>
              <bitWidth>2</bitWidth>
            </field>
          </fields>
        </register>
        <register>
          <name>CR2</name>
          <addressOffset>0x4</addressOffset>
          <size>0x20</size>
          <fields>
            <field>
              <name>CCDS</name>
              <bitOffset>3</bitOffset>
              <bitWidth>1</bitWidth>
            </field>
            <field>
              <name>MMS</name>
              <bitOffset>4</bitOffset>
              <bitWidth>3</bitWidth>
            </field>
            <field>
              <name>TI1S</name>
              <bitOffset>7</bitOffset>
              <bitWidth>1</bitWidth>
            </field>
          </fields>
        </register>
        <register>
          <name>SMCR</name>
          <addressOffset>0x8</addressOffset>
          <size>0x20</size>
          <fields>
            <field>
              <name>SMS</name>
              <bitOffset>0</bitOffset>
              <bitWidth>3</bitWidth>
            </field>
            <field>
              <name>OCCS</name>
              <bitOffset>3</bitOffset>
              <bitWidth>1</bitWidth>
            </field>
            <field>
              <name>TS</name>
              <bitOffset>4</bitOffset>
              <bitWidth>3</bitWidth>
            </field>
            <field>
              <name>MSM</name>
              <bitOffset>7</bitOffset>
              <bitWidth>1</bitWidth>
            </field>
            <field>
              <name>ETF</name>
              <bitOffset>8</bitOffset>
              <bitWidth>4</bitWidth>
            </field>
            <field>
              <name>ETPS</name>
              <bitOffset>12</bitOffset>
              <bitWidth>2</bitWidth>
            </field>
            <field>
              <name>ECE</name>
              <bitOffset>14</bitOffset>
              <bitWidth>1</bitWidth>
            </field>
            <field>
              <name>ETP</name>
              <bitOffset>15</bitOffset>
              <bitWidth>1</bitWidth>
            </field>
          </fields>
        </register>
        <register>
          <name>DIER</name>
          <addressOffset>0xc</addressOffset>
          <size>0x20</size>
          <fields>
            <field>
              <name>UIE</name>
              <bitOffset>0</bitOffset>
              <bitWidth>1</bitWidth>
            </field>
            <field>
              <name>CC1IE</name>
              <bitOffset>1</bitOffset>
              <bitWidth>1</bitWidth>
            </field>
            <field>
              <name>CC2IE</name>
              <bitOffset>2</bitOffset>
              <bitWidth>1</bitWidth>
            </field>
            <field>
              <name>CC3IE</name>
              <bitOffset>3</bitOffset>
              <bitWidth>1</bitWidth>
            </field>
            <field>
              <name>CC4IE</name>
              <bitOffset>4</bitOffset>
              <bitWidth>1</bitWidth>
            </field>
            <field>
              <name>TIE</name>
              <bitOffset>6</bitOffset>
              <bitWidth>1</bitWidth>
            </field>
            <field>
              <name>UDE</name>
              <bitOffset>8</bitOffset>
              <bitWidth>1</bitWidth>
            </field>
            <field>
              <name>CC1DE</name>
              <bitOffset>9</bitOffset>
              <bitWidth>1</bitWidth>
            </field>
            <field>
              <name>CC2DE</name>
              <bitOffset>10</bitOffset>
              <bitWidth>1</bitWidth>
            </field>
            <field>
              <name>CC3DE</name>
              <bitOffset>11</bitOffset>
              <bitWidth>1</bitWidth>
            </field>
            <field>
              <name>CC4DE</name>
              <bitOffset>12</bitOffset>
              <bitWidth>1</bitWidth>
            </field>
            <field>
              <name>TDE</name>
              <bitOffset>14</bitOffset>
              <bitWidth>1</bitWidth>
            </field>
          </fields>
        </register>
        <register>
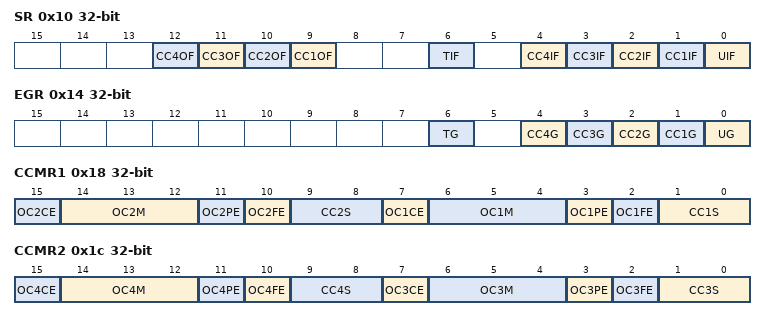
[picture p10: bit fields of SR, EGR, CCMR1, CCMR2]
          <name>SR</name>
          <addressOffset>0x10</addressOffset>
          <size>0x20</size>
          <fields>
            <field>
              <name>UIF</name>
              <bitOffset>0</bitOffset>
              <bitWidth>1</bitWidth>
            </field>
            <field>
              <name>CC1IF</name>
              <bitOffset>1</bitOffset>
              <bitWidth>1</bitWidth>
            </field>
            <field>
              <name>CC2IF</name>
              <bitOffset>2</bitOffset>
              <bitWidth>1</bitWidth>
            </field>
            <field>
              <name>CC3IF</name>
              <bitOffset>3</bitOffset>
              <bitWidth>1</bitWidth>
            </field>
            <field>
              <name>CC4IF</name>
              <bitOffset>4</bitOffset>
              <bitWidth>1</bitWidth>
            </field>
            <field>
              <name>TIF</name>
              <bitOffset>6</bitOffset>
              <bitWidth>1</bitWidth>
            </field>
            <field>
              <name>CC1OF</name>
              <bitOffset>9</bitOffset>
              <bitWidth>1</bitWidth>
            </field>
            <field>
              <name>CC2OF</name>
              <bitOffset>10</bitOffset>
              <bitWidth>1</bitWidth>
            </field>
            <field>
              <name>CC3OF</name>
              <bitOffset>11</bitOffset>
              <bitWidth>1</bitWidth>
            </field>
            <field>
              <name>CC4OF</name>
              <bitOffset>12</bitOffset>
              <bitWidth>1</bitWidth>
            </field>
          </fields>
        </register>
        <register>
          <name>EGR</name>
          <addressOffset>0x14</addressOffset>
          <size>0x20</size>
          <fields>
            <field>
              <name>UG</name>
              <bitOffset>0</bitOffset>
              <bitWidth>1</bitWidth>
            </field>
            <field>
              <name>CC1G</name>
              <bitOffset>1</bitOffset>
              <bitWidth>1</bitWidth>
            </field>
            <field>
              <name>CC2G</name>
              <bitOffset>2</bitOffset>
              <bitWidth>1</bitWidth>
            </field>
            <field>
              <name>CC3G</name>
              <bitOffset>3</bitOffset>
              <bitWidth>1</bitWidth>
            </field>
            <field>
              <name>CC4G</name>
              <bitOffset>4</bitOffset>
              <bitWidth>1</bitWidth>
            </field>
            <field>
              <name>TG</name>
              <bitOffset>6</bitOffset>
              <bitWidth>1</bitWidth>
            </field>
          </fields>
        </register>
        <register>
          <name>CCMR1</name>
          <addressOffset>0x18</addressOffset>
          <size>0x20</size>
          <fields>
            <field>
              <name>CC1S</name>
              <bitOffset>0</bitOffset>
              <bitWidth>2</bitWidth>
            </field>
            <field>
              <name>OC1FE</name>
              <bitOffset>2</bitOffset>
              <bitWidth>1</bitWidth>
            </field>
            <field>
              <name>OC1PE</name>
              <bitOffset>3</bitOffset>
              <bitWidth>1</bitWidth>
            </field>
            <field>
              <name>OC1M</name>
              <bitOffset>4</bitOffset>
              <bitWidth>3</bitWidth>
            </field>
            <field>
              <name>OC1CE</name>
              <bitOffset>7</bitOffset>
              <bitWidth>1</bitWidth>
            </field>
            <field>
              <name>CC2S</name>
              <bitOffset>8</bitOffset>
              <bitWidth>2</bitWidth>
            </field>
            <field>
              <name>OC2FE</name>
              <bitOffset>10</bitOffset>
              <bitWidth>1</bitWidth>
            </field>
            <field>
              <name>OC2PE</name>
              <bitOffset>11</bitOffset>
              <bitWidth>1</bitWidth>
            </field>
            <field>
              <name>OC2M</name>
              <bitOffset>12</bitOffset>
              <bitWidth>3</bitWidth>
            </field>
            <field>
              <name>OC2CE</name>
              <bitOffset>15</bitOffset>
              <bitWidth>1</bitWidth>
            </field>
          </fields>
        </register>
        <register>
          <name>CCMR2</name>
          <addressOffset>0x1c</addressOffset>
          <size>0x20</size>
          <fields>
            <field>
              <name>CC3S</name>
              <bitOffset>0</bitOffset>
              <bitWidth>2</bitWidth>
            </field>
            <field>
              <name>OC3FE</name>
              <bitOffset>2</bitOffset>
              <bitWidth>1</bitWidth>
            </field>
            <field>
              <name>OC3PE</name>
              <bitOffset>3</bitOffset>
              <bitWidth>1</bitWidth>
            </field>
            <field>
              <name>OC3M</name>
              <bitOffset>4</bitOffset>
              <bitWidth>3</bitWidth>
            </field>
            <field>
              <name>OC3CE</name>
              <bitOffset>7</bitOffset>
              <bitWidth>1</bitWidth>
            </field>
            <field>
              <name>CC4S</name>
              <bitOffset>8</bitOffset>
              <bitWidth>2</bitWidth>
            </field>
            <field>
              <name>OC4FE</name>
              <bitOffset>10</bitOffset>
              <bitWidth>1</bitWidth>
            </field>
            <field>
              <name>OC4PE</name>
              <bitOffset>11</bitOffset>
              <bitWidth>1</bitWidth>
            </field>
            <field>
              <name>OC4M</name>
              <bitOffset>12</bitOffset>
              <bitWidth>3</bitWidth>
            </field>
            <field>
              <name>OC4CE</name>
              <bitOffset>15</bitOffset>
              <bitWidth>1</bitWidth>
            </field>
          </fields>
        </register>
        <register>
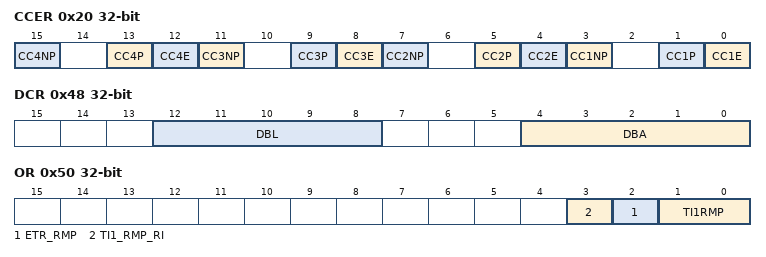
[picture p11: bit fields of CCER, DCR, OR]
          <name>CCER</name>
          <addressOffset>0x20</addressOffset>
          <size>0x20</size>
          <fields>
            <field>
              <name>CC1E</name>
              <bitOffset>0</bitOffset>
              <bitWidth>1</bitWidth>
            </field>
            <field>
              <name>CC1P</name>
              <bitOffset>1</bitOffset>
              <bitWidth>1</bitWidth>
            </field>
            <field>
              <name>CC1NP</name>
              <bitOffset>3</bitOffset>
              <bitWidth>1</bitWidth>
            </field>
            <field>
              <name>CC2E</name>
              <bitOffset>4</bitOffset>
              <bitWidth>1</bitWidth>
            </field>
            <field>
              <name>CC2P</name>
              <bitOffset>5</bitOffset>
              <bitWidth>1</bitWidth>
            </field>
            <field>
              <name>CC2NP</name>
              <bitOffset>7</bitOffset>
              <bitWidth>1</bitWidth>
            </field>
            <field>
              <name>CC3E</name>
              <bitOffset>8</bitOffset>
              <bitWidth>1</bitWidth>
            </field>
            <field>
              <name>CC3P</name>
              <bitOffset>9</bitOffset>
              <bitWidth>1</bitWidth>
            </field>
            <field>
              <name>CC3NP</name>
              <bitOffset>11</bitOffset>
              <bitWidth>1</bitWidth>
            </field>
            <field>
              <name>CC4E</name>
              <bitOffset>12</bitOffset>
              <bitWidth>1</bitWidth>
            </field>
            <field>
              <name>CC4P</name>
              <bitOffset>13</bitOffset>
              <bitWidth>1</bitWidth>
            </field>
            <field>
              <name>CC4NP</name>
              <bitOffset>15</bitOffset>
              <bitWidth>1</bitWidth>
            </field>
          </fields>
        </register>
        <register>
          <name>CNT</name>
          <addressOffset>0x24</addressOffset>
          <size>0x20</size>
          <fields>
            <field>
              <name>CNT</name>
              <bitOffset>0</bitOffset>
              <bitWidth>32</bitWidth>
            </field>
          </fields>
        </register>
        <register>
          <name>PSC</name>
          <addressOffset>0x28</addressOffset>
          <size>0x20</size>
          <fields>
            <field>
              <name>PSC</name>
              <bitOffset>0</bitOffset>
              <bitWidth>16</bitWidth>
            </field>
          </fields>
        </register>
        <register>
          <name>ARR</name>
          <addressOffset>0x2c</addressOffset>
          <size>0x20</size>
          <fields>
            <field>
              <name>ARR</name>
              <bitOffset>0</bitOffset>
              <bitWidth>32</bitWidth>
            </field>
          </fields>
        </register>
        <register>
          <name>CCR1</name>
          <addressOffset>0x34</addressOffset>
          <size>0x20</size>
          <fields>
            <field>
              <name>CCR1</name>
              <bitOffset>0</bitOffset>
              <bitWidth>16</bitWidth>
            </field>
          </fields>
        </register>
        <register>
          <name>CCR2</name>
          <addressOffset>0x38</addressOffset>
          <size>0x20</size>
          <fields>
            <field>
              <name>CCR2</name>
              <bitOffset>0</bitOffset>
              <bitWidth>16</bitWidth>
            </field>
          </fields>
        </register>
        <register>
          <name>CCR3</name>
          <addressOffset>0x3c</addressOffset>
          <size>0x20</size>
          <fields>
            <field>
              <name>CCR3</name>
              <bitOffset>0</bitOffset>
              <bitWidth>16</bitWidth>
            </field>
          </fields>
        </register>
        <register>
          <name>CCR4</name>
          <addressOffset>0x40</addressOffset>
          <size>0x20</size>
          <fields>
            <field>
              <name>CCR4</name>
              <bitOffset>0</bitOffset>
              <bitWidth>16</bitWidth>
            </field>
          </fields>
        </register>
        <register>
          <name>DCR</name>
          <addressOffset>0x48</addressOffset>
          <size>0x20</size>
          <fields>
            <field>
              <name>DBA</name>
              <bitOffset>0</bitOffset>
              <bitWidth>5</bitWidth>
            </field>
            <field>
              <name>DBL</name>
              <bitOffset>8</bitOffset>
              <bitWidth>5</bitWidth>
            </field>
          </fields>
        </register>
        <register>
          <name>DMAR</name>
          <addressOffset>0x4c</addressOffset>
          <size>0x20</size>
          <fields>
            <field>
              <name>DMAB</name>
              <bitOffset>0</bitOffset>
              <bitWidth>16</bitWidth>
            </field>
          </fields>
        </register>
        <register>
          <name>OR</name>
          <addressOffset>0x50</addressOffset>
          <size>0x20</size>
          <fields>
            <field>
              <name>TI1RMP</name>
              <bitOffset>0</bitOffset>
              <bitWidth>2</bitWidth>
            </field>
            <field>
              <name>ETR_RMP</name>
              <bitOffset>2</bitOffset>
              <bitWidth>1</bitWidth>
            </field>
            <field>
              <name>TI1_RMP_RI</name>
              <bitOffset>3</bitOffset>
              <bitWidth>1</bitWidth>
            </field>
          </fields>
        </register>
      </registers>
    </peripheral>
    <peripheral>
      <name>TIM7</name>
      <baseAddress>0x40001400</baseAddress>
      <registers>
        <register>
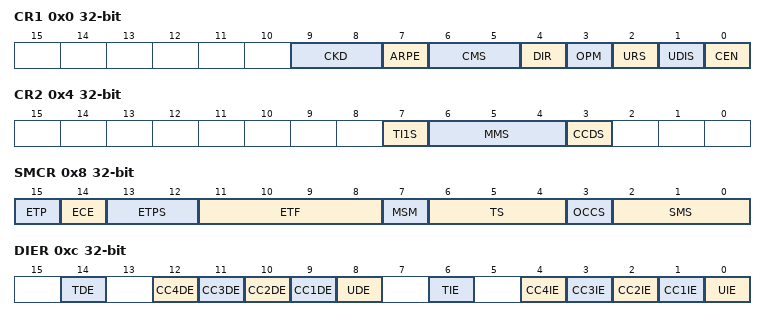
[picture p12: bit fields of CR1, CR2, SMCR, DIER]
          <name>CR1</name>
          <addressOffset>0x0</addressOffset>
          <size>0x20</size>
          <fields>
            <field>
              <name>CEN</name>
              <bitOffset>0</bitOffset>
              <bitWidth>1</bitWidth>
            </field>
            <field>
              <name>UDIS</name>
              <bitOffset>1</bitOffset>
              <bitWidth>1</bitWidth>
            </field>
            <field>
              <name>URS</name>
              <bitOffset>2</bitOffset>
              <bitWidth>1</bitWidth>
            </field>
            <field>
              <name>OPM</name>
              <bitOffset>3</bitOffset>
              <bitWidth>1</bitWidth>
            </field>
            <field>
              <name>DIR</name>
              <bitOffset>4</bitOffset>
              <bitWidth>1</bitWidth>
            </field>
            <field>
              <name>CMS</name>
              <bitOffset>5</bitOffset>
              <bitWidth>2</bitWidth>
            </field>
            <field>
              <name>ARPE</name>
              <bitOffset>7</bitOffset>
              <bitWidth>1</bitWidth>
            </field>
            <field>
              <name>CKD</name>
              <bitOffset>8</bitOffset>
              <bitWidth>2</bitWidth>
            </field>
          </fields>
        </register>
        <register>
          <name>CR2</name>
          <addressOffset>0x4</addressOffset>
          <size>0x20</size>
          <fields>
            <field>
              <name>CCDS</name>
              <bitOffset>3</bitOffset>
              <bitWidth>1</bitWidth>
            </field>
            <field>
              <name>MMS</name>
              <bitOffset>4</bitOffset>
              <bitWidth>3</bitWidth>
            </field>
            <field>
              <name>TI1S</name>
              <bitOffset>7</bitOffset>
              <bitWidth>1</bitWidth>
            </field>
          </fields>
        </register>
        <register>
          <name>SMCR</name>
          <addressOffset>0x8</addressOffset>
          <size>0x20</size>
          <fields>
            <field>
              <name>SMS</name>
              <bitOffset>0</bitOffset>
              <bitWidth>3</bitWidth>
            </field>
            <field>
              <name>OCCS</name>
              <bitOffset>3</bitOffset>
              <bitWidth>1</bitWidth>
            </field>
            <field>
              <name>TS</name>
              <bitOffset>4</bitOffset>
              <bitWidth>3</bitWidth>
            </field>
            <field>
              <name>MSM</name>
              <bitOffset>7</bitOffset>
              <bitWidth>1</bitWidth>
            </field>
            <field>
              <name>ETF</name>
              <bitOffset>8</bitOffset>
              <bitWidth>4</bitWidth>
            </field>
            <field>
              <name>ETPS</name>
              <bitOffset>12</bitOffset>
              <bitWidth>2</bitWidth>
            </field>
            <field>
              <name>ECE</name>
              <bitOffset>14</bitOffset>
              <bitWidth>1</bitWidth>
            </field>
            <field>
              <name>ETP</name>
              <bitOffset>15</bitOffset>
              <bitWidth>1</bitWidth>
            </field>
          </fields>
        </register>
        <register>
          <name>DIER</name>
          <addressOffset>0xc</addressOffset>
          <size>0x20</size>
          <fields>
            <field>
              <name>UIE</name>
              <bitOffset>0</bitOffset>
              <bitWidth>1</bitWidth>
            </field>
            <field>
              <name>CC1IE</name>
              <bitOffset>1</bitOffset>
              <bitWidth>1</bitWidth>
            </field>
            <field>
              <name>CC2IE</name>
              <bitOffset>2</bitOffset>
              <bitWidth>1</bitWidth>
            </field>
            <field>
              <name>CC3IE</name>
              <bitOffset>3</bitOffset>
              <bitWidth>1</bitWidth>
            </field>
            <field>
              <name>CC4IE</name>
              <bitOffset>4</bitOffset>
              <bitWidth>1</bitWidth>
            </field>
            <field>
              <name>TIE</name>
              <bitOffset>6</bitOffset>
              <bitWidth>1</bitWidth>
            </field>
            <field>
              <name>UDE</name>
              <bitOffset>8</bitOffset>
              <bitWidth>1</bitWidth>
            </field>
            <field>
              <name>CC1DE</name>
              <bitOffset>9</bitOffset>
              <bitWidth>1</bitWidth>
            </field>
            <field>
              <name>CC2DE</name>
              <bitOffset>10</bitOffset>
              <bitWidth>1</bitWidth>
            </field>
            <field>
              <name>CC3DE</name>
              <bitOffset>11</bitOffset>
              <bitWidth>1</bitWidth>
            </field>
            <field>
              <name>CC4DE</name>
              <bitOffset>12</bitOffset>
              <bitWidth>1</bitWidth>
            </field>
            <field>
              <name>TDE</name>
              <bitOffset>14</bitOffset>
              <bitWidth>1</bitWidth>
            </field>
          </fields>
        </register>
        <register>
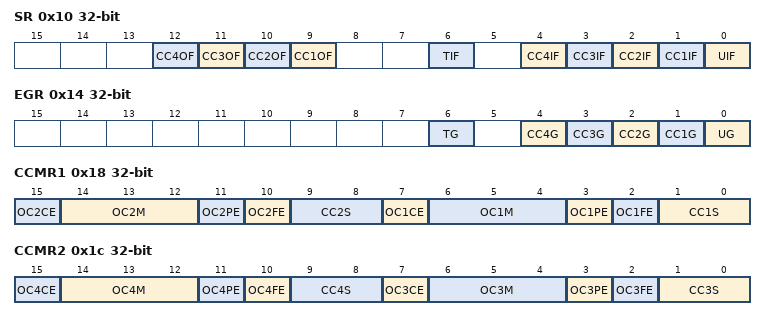
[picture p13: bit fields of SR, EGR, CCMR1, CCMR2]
          <name>SR</name>
          <addressOffset>0x10</addressOffset>
          <size>0x20</size>
          <fields>
            <field>
              <name>UIF</name>
              <bitOffset>0</bitOffset>
              <bitWidth>1</bitWidth>
            </field>
            <field>
              <name>CC1IF</name>
              <bitOffset>1</bitOffset>
              <bitWidth>1</bitWidth>
            </field>
            <field>
              <name>CC2IF</name>
              <bitOffset>2</bitOffset>
              <bitWidth>1</bitWidth>
            </field>
            <field>
              <name>CC3IF</name>
              <bitOffset>3</bitOffset>
              <bitWidth>1</bitWidth>
            </field>
            <field>
              <name>CC4IF</name>
              <bitOffset>4</bitOffset>
              <bitWidth>1</bitWidth>
            </field>
            <field>
              <name>TIF</name>
              <bitOffset>6</bitOffset>
              <bitWidth>1</bitWidth>
            </field>
            <field>
              <name>CC1OF</name>
              <bitOffset>9</bitOffset>
              <bitWidth>1</bitWidth>
            </field>
            <field>
              <name>CC2OF</name>
              <bitOffset>10</bitOffset>
              <bitWidth>1</bitWidth>
            </field>
            <field>
              <name>CC3OF</name>
              <bitOffset>11</bitOffset>
              <bitWidth>1</bitWidth>
            </field>
            <field>
              <name>CC4OF</name>
              <bitOffset>12</bitOffset>
              <bitWidth>1</bitWidth>
            </field>
          </fields>
        </register>
        <register>
          <name>EGR</name>
          <addressOffset>0x14</addressOffset>
          <size>0x20</size>
          <fields>
            <field>
              <name>UG</name>
              <bitOffset>0</bitOffset>
              <bitWidth>1</bitWidth>
            </field>
            <field>
              <name>CC1G</name>
              <bitOffset>1</bitOffset>
              <bitWidth>1</bitWidth>
            </field>
            <field>
              <name>CC2G</name>
              <bitOffset>2</bitOffset>
              <bitWidth>1</bitWidth>
            </field>
            <field>
              <name>CC3G</name>
              <bitOffset>3</bitOffset>
              <bitWidth>1</bitWidth>
            </field>
            <field>
              <name>CC4G</name>
              <bitOffset>4</bitOffset>
              <bitWidth>1</bitWidth>
            </field>
            <field>
              <name>TG</name>
              <bitOffset>6</bitOffset>
              <bitWidth>1</bitWidth>
            </field>
          </fields>
        </register>
        <register>
          <name>CCMR1</name>
          <addressOffset>0x18</addressOffset>
          <size>0x20</size>
          <fields>
            <field>
              <name>CC1S</name>
              <bitOffset>0</bitOffset>
              <bitWidth>2</bitWidth>
            </field>
            <field>
              <name>OC1FE</name>
              <bitOffset>2</bitOffset>
              <bitWidth>1</bitWidth>
            </field>
            <field>
              <name>OC1PE</name>
              <bitOffset>3</bitOffset>
              <bitWidth>1</bitWidth>
            </field>
            <field>
              <name>OC1M</name>
              <bitOffset>4</bitOffset>
              <bitWidth>3</bitWidth>
            </field>
            <field>
              <name>OC1CE</name>
              <bitOffset>7</bitOffset>
              <bitWidth>1</bitWidth>
            </field>
            <field>
              <name>CC2S</name>
              <bitOffset>8</bitOffset>
              <bitWidth>2</bitWidth>
            </field>
            <field>
              <name>OC2FE</name>
              <bitOffset>10</bitOffset>
              <bitWidth>1</bitWidth>
            </field>
            <field>
              <name>OC2PE</name>
              <bitOffset>11</bitOffset>
              <bitWidth>1</bitWidth>
            </field>
            <field>
              <name>OC2M</name>
              <bitOffset>12</bitOffset>
              <bitWidth>3</bitWidth>
            </field>
            <field>
              <name>OC2CE</name>
              <bitOffset>15</bitOffset>
              <bitWidth>1</bitWidth>
            </field>
          </fields>
        </register>
        <register>
          <name>CCMR2</name>
          <addressOffset>0x1c</addressOffset>
          <size>0x20</size>
          <fields>
            <field>
              <name>CC3S</name>
              <bitOffset>0</bitOffset>
              <bitWidth>2</bitWidth>
            </field>
            <field>
              <name>OC3FE</name>
              <bitOffset>2</bitOffset>
              <bitWidth>1</bitWidth>
            </field>
            <field>
              <name>OC3PE</name>
              <bitOffset>3</bitOffset>
              <bitWidth>1</bitWidth>
            </field>
            <field>
              <name>OC3M</name>
              <bitOffset>4</bitOffset>
              <bitWidth>3</bitWidth>
            </field>
            <field>
              <name>OC3CE</name>
              <bitOffset>7</bitOffset>
              <bitWidth>1</bitWidth>
            </field>
            <field>
              <name>CC4S</name>
              <bitOffset>8</bitOffset>
              <bitWidth>2</bitWidth>
            </field>
            <field>
              <name>OC4FE</name>
              <bitOffset>10</bitOffset>
              <bitWidth>1</bitWidth>
            </field>
            <field>
              <name>OC4PE</name>
              <bitOffset>11</bitOffset>
              <bitWidth>1</bitWidth>
            </field>
            <field>
              <name>OC4M</name>
              <bitOffset>12</bitOffset>
              <bitWidth>3</bitWidth>
            </field>
            <field>
              <name>OC4CE</name>
              <bitOffset>15</bitOffset>
              <bitWidth>1</bitWidth>
            </field>
          </fields>
        </register>
        <register>
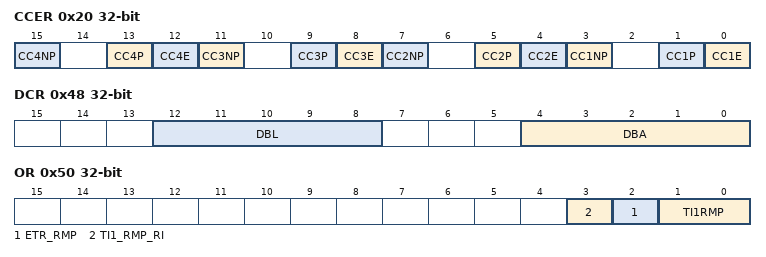
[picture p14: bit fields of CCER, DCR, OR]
          <name>CCER</name>
          <addressOffset>0x20</addressOffset>
          <size>0x20</size>
          <fields>
            <field>
              <name>CC1E</name>
              <bitOffset>0</bitOffset>
              <bitWidth>1</bitWidth>
            </field>
            <field>
              <name>CC1P</name>
              <bitOffset>1</bitOffset>
              <bitWidth>1</bitWidth>
            </field>
            <field>
              <name>CC1NP</name>
              <bitOffset>3</bitOffset>
              <bitWidth>1</bitWidth>
            </field>
            <field>
              <name>CC2E</name>
              <bitOffset>4</bitOffset>
              <bitWidth>1</bitWidth>
            </field>
            <field>
              <name>CC2P</name>
              <bitOffset>5</bitOffset>
              <bitWidth>1</bitWidth>
            </field>
            <field>
              <name>CC2NP</name>
              <bitOffset>7</bitOffset>
              <bitWidth>1</bitWidth>
            </field>
            <field>
              <name>CC3E</name>
              <bitOffset>8</bitOffset>
              <bitWidth>1</bitWidth>
            </field>
            <field>
              <name>CC3P</name>
              <bitOffset>9</bitOffset>
              <bitWidth>1</bitWidth>
            </field>
            <field>
              <name>CC3NP</name>
              <bitOffset>11</bitOffset>
              <bitWidth>1</bitWidth>
            </field>
            <field>
              <name>CC4E</name>
              <bitOffset>12</bitOffset>
              <bitWidth>1</bitWidth>
            </field>
            <field>
              <name>CC4P</name>
              <bitOffset>13</bitOffset>
              <bitWidth>1</bitWidth>
            </field>
            <field>
              <name>CC4NP</name>
              <bitOffset>15</bitOffset>
              <bitWidth>1</bitWidth>
            </field>
          </fields>
        </register>
        <register>
          <name>CNT</name>
          <addressOffset>0x24</addressOffset>
          <size>0x20</size>
          <fields>
            <field>
              <name>CNT</name>
              <bitOffset>0</bitOffset>
              <bitWidth>32</bitWidth>
            </field>
          </fields>
        </register>
        <register>
          <name>PSC</name>
          <addressOffset>0x28</addressOffset>
          <size>0x20</size>
          <fields>
            <field>
              <name>PSC</name>
              <bitOffset>0</bitOffset>
              <bitWidth>16</bitWidth>
            </field>
          </fields>
        </register>
        <register>
          <name>ARR</name>
          <addressOffset>0x2c</addressOffset>
          <size>0x20</size>
          <fields>
            <field>
              <name>ARR</name>
              <bitOffset>0</bitOffset>
              <bitWidth>32</bitWidth>
            </field>
          </fields>
        </register>
        <register>
          <name>CCR1</name>
          <addressOffset>0x34</addressOffset>
          <size>0x20</size>
          <fields>
            <field>
              <name>CCR1</name>
              <bitOffset>0</bitOffset>
              <bitWidth>16</bitWidth>
            </field>
          </fields>
        </register>
        <register>
          <name>CCR2</name>
          <addressOffset>0x38</addressOffset>
          <size>0x20</size>
          <fields>
            <field>
              <name>CCR2</name>
              <bitOffset>0</bitOffset>
              <bitWidth>16</bitWidth>
            </field>
          </fields>
        </register>
        <register>
          <name>CCR3</name>
          <addressOffset>0x3c</addressOffset>
          <size>0x20</size>
          <fields>
            <field>
              <name>CCR3</name>
              <bitOffset>0</bitOffset>
              <bitWidth>16</bitWidth>
            </field>
          </fields>
        </register>
        <register>
          <name>CCR4</name>
          <addressOffset>0x40</addressOffset>
          <size>0x20</size>
          <fields>
            <field>
              <name>CCR4</name>
              <bitOffset>0</bitOffset>
              <bitWidth>16</bitWidth>
            </field>
          </fields>
        </register>
        <register>
          <name>DCR</name>
          <addressOffset>0x48</addressOffset>
          <size>0x20</size>
          <fields>
            <field>
              <name>DBA</name>
              <bitOffset>0</bitOffset>
              <bitWidth>5</bitWidth>
            </field>
            <field>
              <name>DBL</name>
              <bitOffset>8</bitOffset>
              <bitWidth>5</bitWidth>
            </field>
          </fields>
        </register>
        <register>
          <name>DMAR</name>
          <addressOffset>0x4c</addressOffset>
          <size>0x20</size>
          <fields>
            <field>
              <name>DMAB</name>
              <bitOffset>0</bitOffset>
              <bitWidth>16</bitWidth>
            </field>
          </fields>
        </register>
        <register>
          <name>OR</name>
          <addressOffset>0x50</addressOffset>
          <size>0x20</size>
          <fields>
            <field>
              <name>TI1RMP</name>
              <bitOffset>0</bitOffset>
              <bitWidth>2</bitWidth>
            </field>
            <field>
              <name>ETR_RMP</name>
              <bitOffset>2</bitOffset>
              <bitWidth>1</bitWidth>
            </field>
            <field>
              <name>TI1_RMP_RI</name>
              <bitOffset>3</bitOffset>
              <bitWidth>1</bitWidth>
            </field>
          </fields>
        </register>
      </registers>
    </peripheral>
    <peripheral>
      <name>LCD</name>
      <baseAddress>0x40002400</baseAddress>
      <registers>
        <register>
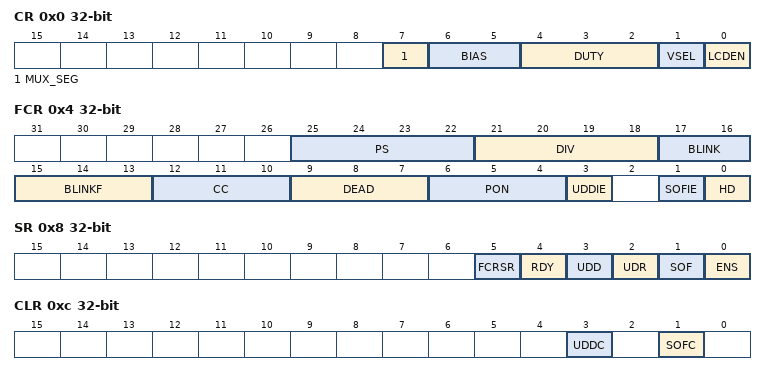
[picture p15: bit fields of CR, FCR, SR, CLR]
          <name>CR</name>
          <addressOffset>0x0</addressOffset>
          <size>0x20</size>
          <fields>
            <field>
              <name>LCDEN</name>
              <bitOffset>0</bitOffset>
              <bitWidth>1</bitWidth>
            </field>
            <field>
              <name>VSEL</name>
              <bitOffset>1</bitOffset>
              <bitWidth>1</bitWidth>
            </field>
            <field>
              <name>DUTY</name>
              <bitOffset>2</bitOffset>
              <bitWidth>3</bitWidth>
            </field>
            <field>
              <name>BIAS</name>
              <bitOffset>5</bitOffset>
              <bitWidth>2</bitWidth>
            </field>
            <field>
              <name>MUX_SEG</name>
              <bitOffset>7</bitOffset>
              <bitWidth>1</bitWidth>
            </field>
          </fields>
        </register>
        <register>
          <name>FCR</name>
          <addressOffset>0x4</addressOffset>
          <size>0x20</size>
          <fields>
            <field>
              <name>HD</name>
              <bitOffset>0</bitOffset>
              <bitWidth>1</bitWidth>
            </field>
            <field>
              <name>SOFIE</name>
              <bitOffset>1</bitOffset>
              <bitWidth>1</bitWidth>
            </field>
            <field>
              <name>UDDIE</name>
              <bitOffset>3</bitOffset>
              <bitWidth>1</bitWidth>
            </field>
            <field>
              <name>PON</name>
              <bitOffset>4</bitOffset>
              <bitWidth>3</bitWidth>
            </field>
            <field>
              <name>DEAD</name>
              <bitOffset>7</bitOffset>
              <bitWidth>3</bitWidth>
            </field>
            <field>
              <name>CC</name>
              <bitOffset>10</bitOffset>
              <bitWidth>3</bitWidth>
            </field>
            <field>
              <name>BLINKF</name>
              <bitOffset>13</bitOffset>
              <bitWidth>3</bitWidth>
            </field>
            <field>
              <name>BLINK</name>
              <bitOffset>16</bitOffset>
              <bitWidth>2</bitWidth>
            </field>
            <field>
              <name>DIV</name>
              <bitOffset>18</bitOffset>
              <bitWidth>4</bitWidth>
            </field>
            <field>
              <name>PS</name>
              <bitOffset>22</bitOffset>
              <bitWidth>4</bitWidth>
            </field>
          </fields>
        </register>
        <register>
          <name>SR</name>
          <addressOffset>0x8</addressOffset>
          <size>0x20</size>
          <fields>
            <field>
              <name>ENS</name>
              <bitOffset>0</bitOffset>
              <bitWidth>1</bitWidth>
            </field>
            <field>
              <name>SOF</name>
              <bitOffset>1</bitOffset>
              <bitWidth>1</bitWidth>
            </field>
            <field>
              <name>UDR</name>
              <bitOffset>2</bitOffset>
              <bitWidth>1</bitWidth>
            </field>
            <field>
              <name>UDD</name>
              <bitOffset>3</bitOffset>
              <bitWidth>1</bitWidth>
            </field>
            <field>
              <name>RDY</name>
              <bitOffset>4</bitOffset>
              <bitWidth>1</bitWidth>
            </field>
            <field>
              <name>FCRSR</name>
              <bitOffset>5</bitOffset>
              <bitWidth>1</bitWidth>
            </field>
          </fields>
        </register>
        <register>
          <name>CLR</name>
          <addressOffset>0xc</addressOffset>
          <size>0x20</size>
          <fields>
            <field>
              <name>SOFC</name>
              <bitOffset>1</bitOffset>
              <bitWidth>1</bitWidth>
            </field>
            <field>
              <name>UDDC</name>
              <bitOffset>3</bitOffset>
              <bitWidth>1</bitWidth>
            </field>
          </fields>
        </register>
        <register>
          <name>RAM.0</name>
          <addressOffset>0x14</addressOffset>
          <size>0x20</size>
          <fields>
            <field>
              <name>SEGMENT_DATA</name>
              <bitOffset>0</bitOffset>
              <bitWidth>32</bitWidth>
            </field>
          </fields>
        </register>
        <register>
          <name>RAM.1</name>
          <addressOffset>0x18</addressOffset>
          <size>0x20</size>
          <fields>
            <field>
              <name>SEGMENT_DATA</name>
              <bitOffset>0</bitOffset>
              <bitWidth>32</bitWidth>
            </field>
          </fields>
        </register>
        <register>
          <name>RAM.2</name>
          <addressOffset>0x1c</addressOffset>
          <size>0x20</size>
          <fields>
            <field>
              <name>SEGMENT_DATA</name>
              <bitOffset>0</bitOffset>
              <bitWidth>32</bitWidth>
            </field>
          </fields>
        </register>
        <register>
          <name>RAM.3</name>
          <addressOffset>0x20</addressOffset>
          <size>0x20</size>
          <fields>
            <field>
              <name>SEGMENT_DATA</name>
              <bitOffset>0</bitOffset>
              <bitWidth>32</bitWidth>
            </field>
          </fields>
        </register>
        <register>
          <name>RAM.4</name>
          <addressOffset>0x24</addressOffset>
          <size>0x20</size>
          <fields>
            <field>
              <name>SEGMENT_DATA</name>
              <bitOffset>0</bitOffset>
              <bitWidth>32</bitWidth>
            </field>
          </fields>
        </register>
        <register>
          <name>RAM.5</name>
          <addressOffset>0x28</addressOffset>
          <size>0x20</size>
          <fields>
            <field>
              <name>SEGMENT_DATA</name>
              <bitOffset>0</bitOffset>
              <bitWidth>32</bitWidth>
            </field>
          </fields>
        </register>
        <register>
          <name>RAM.6</name>
          <addressOffset>0x2c</addressOffset>
          <size>0x20</size>
          <fields>
            <field>
              <name>SEGMENT_DATA</name>
              <bitOffset>0</bitOffset>
              <bitWidth>32</bitWidth>
            </field>
          </fields>
        </register>
        <register>
          <name>RAM.7</name>
          <addressOffset>0x30</addressOffset>
          <size>0x20</size>
          <fields>
            <field>
              <name>SEGMENT_DATA</name>
              <bitOffset>0</bitOffset>
              <bitWidth>32</bitWidth>
            </field>
          </fields>
        </register>
        <register>
          <name>RAM.8</name>
          <addressOffset>0x34</addressOffset>
          <size>0x20</size>
          <fields>
            <field>
              <name>SEGMENT_DATA</name>
              <bitOffset>0</bitOffset>
              <bitWidth>32</bitWidth>
            </field>
          </fields>
        </register>
        <register>
          <name>RAM.9</name>
          <addressOffset>0x38</addressOffset>
          <size>0x20</size>
          <fields>
            <field>
              <name>SEGMENT_DATA</name>
              <bitOffset>0</bitOffset>
              <bitWidth>32</bitWidth>
            </field>
          </fields>
        </register>
        <register>
          <name>RAM.10</name>
          <addressOffset>0x3c</addressOffset>
          <size>0x20</size>
          <fields>
            <field>
              <name>SEGMENT_DATA</name>
              <bitOffset>0</bitOffset>
              <bitWidth>32</bitWidth>
            </field>
          </fields>
        </register>
        <register>
          <name>RAM.11</name>
          <addressOffset>0x40</addressOffset>
          <size>0x20</size>
          <fields>
            <field>
              <name>SEGMENT_DATA</name>
              <bitOffset>0</bitOffset>
              <bitWidth>32</bitWidth>
            </field>
          </fields>
        </register>
        <register>
          <name>RAM.12</name>
          <addressOffset>0x44</addressOffset>
          <size>0x20</size>
          <fields>
            <field>
              <name>SEGMENT_DATA</name>
              <bitOffset>0</bitOffset>
              <bitWidth>32</bitWidth>
            </field>
          </fields>
        </register>
        <register>
          <name>RAM.13</name>
          <addressOffset>0x48</addressOffset>
          <size>0x20</size>
          <fields>
            <field>
              <name>SEGMENT_DATA</name>
              <bitOffset>0</bitOffset>
              <bitWidth>32</bitWidth>
            </field>
          </fields>
        </register>
        <register>
          <name>RAM.14</name>
          <addressOffset>0x4c</addressOffset>
          <size>0x20</size>
          <fields>
            <field>
              <name>SEGMENT_DATA</name>
              <bitOffset>0</bitOffset>
              <bitWidth>32</bitWidth>
            </field>
          </fields>
        </register>
        <register>
          <name>RAM.15</name>
          <addressOffset>0x50</addressOffset>
          <size>0x20</size>
          <fields>
            <field>
              <name>SEGMENT_DATA</name>
              <bitOffset>0</bitOffset>
              <bitWidth>32</bitWidth>
            </field>
          </fields>
        </register>
      </registers>
    </peripheral>
    <peripheral>
      <name>RTC</name>
      <baseAddress>0x40002800</baseAddress>
      <registers>
        <register>
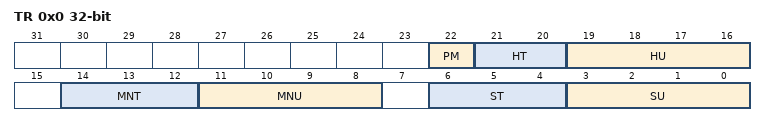
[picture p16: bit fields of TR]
          <name>TR</name>
          <addressOffset>0x0</addressOffset>
          <size>0x20</size>
          <fields>
            <field>
              <name>SU</name>
              <bitOffset>0</bitOffset>
              <bitWidth>4</bitWidth>
            </field>
            <field>
              <name>ST</name>
              <bitOffset>4</bitOffset>
              <bitWidth>3</bitWidth>
            </field>
            <field>
              <name>MNU</name>
              <bitOffset>8</bitOffset>
              <bitWidth>4</bitWidth>
            </field>
            <field>
              <name>MNT</name>
              <bitOffset>12</bitOffset>
              <bitWidth>3</bitWidth>
            </field>
            <field>
              <name>HU</name>
              <bitOffset>16</bitOffset>
              <bitWidth>4</bitWidth>
            </field>
            <field>
              <name>HT</name>
              <bitOffset>20</bitOffset>
              <bitWidth>2</bitWidth>
            </field>
            <field>
              <name>PM</name>
              <bitOffset>22</bitOffset>
              <bitWidth>1</bitWidth>
            </field>
          </fields>
        </register>
        <register>
          <name>DR</name>
          <addressOffset>0x4</addressOffset>
          <size>0x20</size>
          <fields>
            <field>
              <name>DU</name>
              <bitOffset>0</bitOffset>
              <bitWidth>4</bitWidth>
            </field>
            <field>
              <name>DT</name>
              <bitOffset>4</bitOffset>
              <bitWidth>2</bitWidth>
            </field>
            <field>
              <name>MU</name>
              <bitOffset>8</bitOffset>
              <bitWidth>4</bitWidth>
            </field>
            <field>
              <name>MT</name>
              <bitOffset>12</bitOffset>
              <bitWidth>1</bitWidth>
            </field>
            <field>
              <name>WDU</name>
              <bitOffset>13</bitOffset>
              <bitWidth>3</bitWidth>
            </field>
            <field>
              <name>YU</name>
              <bitOffset>16</bitOffset>
              <bitWidth>4</bitWidth>
            </field>
            <field>
              <name>YT</name>
              <bitOffset>20</bitOffset>
              <bitWidth>4</bitWidth>
            </field>
          </fields>
        </register>
        <register>
          <name>CR</name>
          <addressOffset>0x8</addressOffset>
          <size>0x20</size>
          <fields>
            <field>
              <name>WUCKSEL</name>
              <bitOffset>0</bitOffset>
              <bitWidth>3</bitWidth>
            </field>
            <field>
              <name>TSEDGE</name>
              <bitOffset>3</bitOffset>
              <bitWidth>1</bitWidth>
            </field>
            <field>
              <name>REFCKON</name>
              <bitOffset>4</bitOffset>
              <bitWidth>1</bitWidth>
            </field>
            <field>
              <name>FMT</name>
              <bitOffset>6</bitOffset>
              <bitWidth>1</bitWidth>
            </field>
            <field>
              <name>DCE</name>
              <bitOffset>7</bitOffset>
              <bitWidth>1</bitWidth>
            </field>
            <field>
              <name>ALRAE</name>
              <bitOffset>8</bitOffset>
              <bitWidth>1</bitWidth>
            </field>
            <field>
              <name>ALRBE</name>
              <bitOffset>9</bitOffset>
              <bitWidth>1</bitWidth>
            </field>
            <field>
              <name>WUTE</name>
              <bitOffset>10</bitOffset>
              <bitWidth>1</bitWidth>
            </field>
            <field>
              <name>TSE</name>
              <bitOffset>11</bitOffset>
              <bitWidth>1</bitWidth>
            </field>
            <field>
              <name>ALRAIE</name>
              <bitOffset>12</bitOffset>
              <bitWidth>1</bitWidth>
            </field>
            <field>
              <name>ALRBIE</name>
              <bitOffset>13</bitOffset>
              <bitWidth>1</bitWidth>
            </field>
            <field>
              <name>WUTIE</name>
              <bitOffset>14</bitOffset>
              <bitWidth>1</bitWidth>
            </field>
            <field>
              <name>TSIE</name>
              <bitOffset>15</bitOffset>
              <bitWidth>1</bitWidth>
            </field>
            <field>
              <name>ADD1H</name>
              <bitOffset>16</bitOffset>
              <bitWidth>1</bitWidth>
            </field>
            <field>
              <name>SUB1H</name>
              <bitOffset>17</bitOffset>
              <bitWidth>1</bitWidth>
            </field>
            <field>
              <name>BKP</name>
              <bitOffset>18</bitOffset>
              <bitWidth>1</bitWidth>
            </field>
            <field>
              <name>POL</name>
              <bitOffset>20</bitOffset>
              <bitWidth>1</bitWidth>
            </field>
            <field>
              <name>OSEL</name>
              <bitOffset>21</bitOffset>
              <bitWidth>2</bitWidth>
            </field>
            <field>
              <name>COE</name>
              <bitOffset>23</bitOffset>
              <bitWidth>1</bitWidth>
            </field>
          </fields>
        </register>
        <register>
          <name>ISR</name>
          <addressOffset>0xc</addressOffset>
          <size>0x20</size>
          <fields>
            <field>
              <name>ALRAWF</name>
              <bitOffset>0</bitOffset>
              <bitWidth>1</bitWidth>
            </field>
            <field>
              <name>ALRBWF</name>
              <bitOffset>1</bitOffset>
              <bitWidth>1</bitWidth>
            </field>
            <field>
              <name>WUTWF</name>
              <bitOffset>2</bitOffset>
              <bitWidth>1</bitWidth>
            </field>
            <field>
              <name>INITS</name>
              <bitOffset>4</bitOffset>
              <bitWidth>1</bitWidth>
            </field>
            <field>
              <name>RSF</name>
              <bitOffset>5</bitOffset>
              <bitWidth>1</bitWidth>
            </field>
            <field>
              <name>INITF</name>
              <bitOffset>6</bitOffset>
              <bitWidth>1</bitWidth>
            </field>
            <field>
              <name>INIT</name>
              <bitOffset>7</bitOffset>
              <bitWidth>1</bitWidth>
            </field>
            <field>
              <name>ALRAF</name>
              <bitOffset>8</bitOffset>
              <bitWidth>1</bitWidth>
            </field>
            <field>
              <name>ALRBF</name>
              <bitOffset>9</bitOffset>
              <bitWidth>1</bitWidth>
            </field>
            <field>
              <name>WUTF</name>
              <bitOffset>10</bitOffset>
              <bitWidth>1</bitWidth>
            </field>
            <field>
              <name>TSF</name>
              <bitOffset>11</bitOffset>
              <bitWidth>1</bitWidth>
            </field>
            <field>
              <name>TSOVF</name>
              <bitOffset>12</bitOffset>
              <bitWidth>1</bitWidth>
            </field>
            <field>
              <name>TAMP1F</name>
              <bitOffset>13</bitOffset>
              <bitWidth>1</bitWidth>
            </field>
          </fields>
        </register>
        <register>
          <name>PRER</name>
          <addressOffset>0x10</addressOffset>
          <size>0x20</size>
          <fields>
            <field>
              <name>PREDIV_S</name>
              <bitOffset>0</bitOffset>
              <bitWidth>13</bitWidth>
            </field>
            <field>
              <name>PREDIV_A</name>
              <bitOffset>16</bitOffset>
              <bitWidth>7</bitWidth>
            </field>
          </fields>
        </register>
        <register>
          <name>WUTR</name>
          <addressOffset>0x14</addressOffset>
          <size>0x20</size>
          <fields>
            <field>
              <name>WUT</name>
              <bitOffset>0</bitOffset>
              <bitWidth>16</bitWidth>
            </field>
          </fields>
        </register>
        <register>
          <name>CALIBR</name>
          <addressOffset>0x18</addressOffset>
          <size>0x20</size>
          <fields>
            <field>
              <name>DC</name>
              <bitOffset>0</bitOffset>
              <bitWidth>5</bitWidth>
            </field>
            <field>
              <name>DCS</name>
              <bitOffset>7</bitOffset>
              <bitWidth>1</bitWidth>
            </field>
          </fields>
        </register>
        <register>
          <name>ALRMAR</name>
          <addressOffset>0x1c</addressOffset>
          <size>0x20</size>
          <fields>
            <field>
              <name>SU</name>
              <bitOffset>0</bitOffset>
              <bitWidth>4</bitWidth>
            </field>
            <field>
              <name>ST</name>
              <bitOffset>4</bitOffset>
              <bitWidth>3</bitWidth>
            </field>
            <field>
              <name>MSK1</name>
              <bitOffset>7</bitOffset>
              <bitWidth>1</bitWidth>
            </field>
            <field>
              <name>MNU</name>
              <bitOffset>8</bitOffset>
              <bitWidth>4</bitWidth>
            </field>
            <field>
              <name>MNT</name>
              <bitOffset>12</bitOffset>
              <bitWidth>3</bitWidth>
            </field>
            <field>
              <name>MSK2</name>
              <bitOffset>15</bitOffset>
              <bitWidth>1</bitWidth>
            </field>
            <field>
              <name>HU</name>
              <bitOffset>16</bitOffset>
              <bitWidth>4</bitWidth>
            </field>
            <field>
              <name>HT</name>
              <bitOffset>20</bitOffset>
              <bitWidth>2</bitWidth>
            </field>
            <field>
              <name>PM</name>
              <bitOffset>22</bitOffset>
              <bitWidth>1</bitWidth>
            </field>
            <field>
              <name>MSK3</name>
              <bitOffset>23</bitOffset>
              <bitWidth>1</bitWidth>
            </field>
            <field>
              <name>DU</name>
              <bitOffset>24</bitOffset>
              <bitWidth>4</bitWidth>
            </field>
            <field>
              <name>DT</name>
              <bitOffset>28</bitOffset>
              <bitWidth>2</bitWidth>
            </field>
            <field>
              <name>WDSEL</name>
              <bitOffset>30</bitOffset>
              <bitWidth>1</bitWidth>
            </field>
            <field>
              <name>MSK4</name>
              <bitOffset>31</bitOffset>
              <bitWidth>1</bitWidth>
            </field>
          </fields>
        </register>
        <register>
          <name>ALRMBR</name>
          <addressOffset>0x20</addressOffset>
          <size>0x20</size>
          <fields>
            <field>
              <name>SU</name>
              <bitOffset>0</bitOffset>
              <bitWidth>4</bitWidth>
            </field>
            <field>
              <name>ST</name>
              <bitOffset>4</bitOffset>
              <bitWidth>3</bitWidth>
            </field>
            <field>
              <name>MSK1</name>
              <bitOffset>7</bitOffset>
              <bitWidth>1</bitWidth>
            </field>
            <field>
              <name>MNU</name>
              <bitOffset>8</bitOffset>
              <bitWidth>4</bitWidth>
            </field>
            <field>
              <name>MNT</name>
              <bitOffset>12</bitOffset>
              <bitWidth>3</bitWidth>
            </field>
            <field>
              <name>MSK2</name>
              <bitOffset>15</bitOffset>
              <bitWidth>1</bitWidth>
            </field>
            <field>
              <name>HU</name>
              <bitOffset>16</bitOffset>
              <bitWidth>4</bitWidth>
            </field>
            <field>
              <name>HT</name>
              <bitOffset>20</bitOffset>
              <bitWidth>2</bitWidth>
            </field>
            <field>
              <name>PM</name>
              <bitOffset>22</bitOffset>
              <bitWidth>1</bitWidth>
            </field>
            <field>
              <name>MSK3</name>
              <bitOffset>23</bitOffset>
              <bitWidth>1</bitWidth>
            </field>
            <field>
              <name>DU</name>
              <bitOffset>24</bitOffset>
              <bitWidth>4</bitWidth>
            </field>
            <field>
              <name>DT</name>
              <bitOffset>28</bitOffset>
              <bitWidth>2</bitWidth>
            </field>
            <field>
              <name>WDSEL</name>
              <bitOffset>30</bitOffset>
              <bitWidth>1</bitWidth>
            </field>
            <field>
              <name>MSK4</name>
              <bitOffset>31</bitOffset>
              <bitWidth>1</bitWidth>
            </field>
          </fields>
        </register>
        <register>
          <name>WPR</name>
          <addressOffset>0x24</addressOffset>
          <size>0x20</size>
          <fields>
            <field>
              <name>KEY</name>
              <bitOffset>0</bitOffset>
              <bitWidth>8</bitWidth>
            </field>
          </fields>
        </register>
        <register>
          <name>TSTR</name>
          <addressOffset>0x30</addressOffset>
          <size>0x20</size>
          <fields>
            <field>
              <name>SU</name>
              <bitOffset>0</bitOffset>
              <bitWidth>4</bitWidth>
            </field>
            <field>
              <name>ST</name>
              <bitOffset>4</bitOffset>
              <bitWidth>3</bitWidth>
            </field>
            <field>
              <name>MNU</name>
              <bitOffset>8</bitOffset>
              <bitWidth>4</bitWidth>
            </field>
            <field>
              <name>MNT</name>
              <bitOffset>12</bitOffset>
              <bitWidth>3</bitWidth>
            </field>
            <field>
              <name>HU</name>
              <bitOffset>16</bitOffset>
              <bitWidth>4</bitWidth>
            </field>
            <field>
              <name>HT</name>
              <bitOffset>20</bitOffset>
              <bitWidth>2</bitWidth>
            </field>
            <field>
              <name>PM</name>
              <bitOffset>22</bitOffset>
              <bitWidth>1</bitWidth>
            </field>
          </fields>
        </register>
        <register>
          <name>TSDR</name>
          <addressOffset>0x34</addressOffset>
          <size>0x20</size>
          <fields>
            <field>
              <name>DU</name>
              <bitOffset>0</bitOffset>
              <bitWidth>4</bitWidth>
            </field>
            <field>
              <name>DT</name>
              <bitOffset>4</bitOffset>
              <bitWidth>2</bitWidth>
            </field>
            <field>
              <name>MU</name>
              <bitOffset>8</bitOffset>
              <bitWidth>4</bitWidth>
            </field>
            <field>
              <name>MT</name>
              <bitOffset>12</bitOffset>
              <bitWidth>1</bitWidth>
            </field>
            <field>
              <name>WDU</name>
              <bitOffset>13</bitOffset>
              <bitWidth>3</bitWidth>
            </field>
          </fields>
        </register>
        <register>
          <name>TAFCR</name>
          <addressOffset>0x40</addressOffset>
          <size>0x20</size>
          <fields>
            <field>
              <name>TAMP1E</name>
              <bitOffset>0</bitOffset>
              <bitWidth>1</bitWidth>
            </field>
            <field>
              <name>TAMP1TRG</name>
              <bitOffset>1</bitOffset>
              <bitWidth>1</bitWidth>
            </field>
            <field>
              <name>TAMPIE</name>
              <bitOffset>2</bitOffset>
              <bitWidth>1</bitWidth>
            </field>
            <field>
              <name>ALARMOUTTYPE</name>
              <bitOffset>18</bitOffset>
              <bitWidth>1</bitWidth>
            </field>
          </fields>
        </register>
        <register>
          <name>BKP0R</name>
          <addressOffset>0x50</addressOffset>
          <size>0x20</size>
        </register>
        <register>
          <name>BKP1R</name>
          <addressOffset>0x54</addressOffset>
          <size>0x20</size>
        </register>
        <register>
          <name>BKP2R</name>
          <addressOffset>0x58</addressOffset>
          <size>0x20</size>
        </register>
        <register>
          <name>BKP3R</name>
          <addressOffset>0x5c</addressOffset>
          <size>0x20</size>
        </register>
        <register>
          <name>BKP4R</name>
          <addressOffset>0x60</addressOffset>
          <size>0x20</size>
        </register>
        <register>
          <name>BKP5R</name>
          <addressOffset>0x64</addressOffset>
          <size>0x20</size>
        </register>
        <register>
          <name>BKP6R</name>
          <addressOffset>0x68</addressOffset>
          <size>0x20</size>
        </register>
        <register>
          <name>BKP7R</name>
          <addressOffset>0x6c</addressOffset>
          <size>0x20</size>
        </register>
        <register>
          <name>BKP8R</name>
          <addressOffset>0x70</addressOffset>
          <size>0x20</size>
        </register>
        <register>
          <name>BKP9R</name>
          <addressOffset>0x74</addressOffset>
          <size>0x20</size>
        </register>
        <register>
          <name>BKP10R</name>
          <addressOffset>0x78</addressOffset>
          <size>0x20</size>
        </register>
        <register>
          <name>BKP11R</name>
          <addressOffset>0x7c</addressOffset>
          <size>0x20</size>
        </register>
        <register>
          <name>BKP12R</name>
          <addressOffset>0x80</addressOffset>
          <size>0x20</size>
        </register>
        <register>
          <name>BKP13R</name>
          <addressOffset>0x84</addressOffset>
          <size>0x20</size>
        </register>
        <register>
          <name>BKP14R</name>
          <addressOffset>0x88</addressOffset>
          <size>0x20</size>
        </register>
        <register>
          <name>BKP15R</name>
          <addressOffset>0x8c</addressOffset>
          <size>0x20</size>
        </register>
        <register>
          <name>BKP16R</name>
          <addressOffset>0x90</addressOffset>
          <size>0x20</size>
        </register>
        <register>
          <name>BKP17R</name>
          <addressOffset>0x94</addressOffset>
          <size>0x20</size>
        </register>
        <register>
          <name>BKP18R</name>
          <addressOffset>0x98</addressOffset>
          <size>0x20</size>
        </register>
        <register>
          <name>BKP19R</name>
          <addressOffset>0x9c</addressOffset>
          <size>0x20</size>
        </register>
      </registers>
    </peripheral>
    <peripheral>
      <name>WWDG</name>
      <baseAddress>0x40002c00</baseAddress>
      <registers>
        <register>
          <name>CR</name>
          <addressOffset>0x0</addressOffset>
          <size>0x20</size>
          <fields>
            <field>
              <name>T</name>
              <bitOffset>0</bitOffset>
              <bitWidth>7</bitWidth>
            </field>
            <field>
              <name>WDGA</name>
              <bitOffset>7</bitOffset>
              <bitWidth>1</bitWidth>
            </field>
          </fields>
        </register>
        <register>
          <name>CFR</name>
          <addressOffset>0x4</addressOffset>
          <size>0x20</size>
          <fields>
            <field>
              <name>W</name>
              <bitOffset>0</bitOffset>
              <bitWidth>7</bitWidth>
            </field>
            <field>
              <name>WDGTB</name>
              <bitOffset>7</bitOffset>
              <bitWidth>2</bitWidth>
            </field>
            <field>
              <name>EWI</name>
              <bitOffset>9</bitOffset>
              <bitWidth>1</bitWidth>
            </field>
          </fields>
        </register>
        <register>
          <name>SR</name>
          <addressOffset>0x8</addressOffset>
          <size>0x20</size>
          <fields>
            <field>
              <name>EWIF</name>
              <bitOffset>0</bitOffset>
              <bitWidth>1</bitWidth>
            </field>
          </fields>
        </register>
      </registers>
    </peripheral>
    <peripheral>
      <name>IWDG</name>
      <baseAddress>0x40003000</baseAddress>
      <registers>
        <register>
          <name>KR</name>
          <addressOffset>0x0</addressOffset>
          <size>0x20</size>
          <fields>
            <field>
              <name>KEY</name>
              <bitOffset>0</bitOffset>
              <bitWidth>16</bitWidth>
            </field>
          </fields>
        </register>
        <register>
          <name>PR</name>
          <addressOffset>0x4</addressOffset>
          <size>0x20</size>
          <fields>
            <field>
              <name>PR</name>
              <bitOffset>0</bitOffset>
              <bitWidth>3</bitWidth>
            </field>
          </fields>
        </register>
        <register>
          <name>RLR</name>
          <addressOffset>0x8</addressOffset>
          <size>0x20</size>
          <fields>
            <field>
              <name>RL</name>
              <bitOffset>0</bitOffset>
              <bitWidth>12</bitWidth>
            </field>
          </fields>
        </register>
        <register>
          <name>SR</name>
          <addressOffset>0xc</addressOffset>
          <size>0x20</size>
          <fields>
            <field>
              <name>PVU</name>
              <bitOffset>0</bitOffset>
              <bitWidth>1</bitWidth>
            </field>
            <field>
              <name>RVU</name>
              <bitOffset>1</bitOffset>
              <bitWidth>1</bitWidth>
            </field>
          </fields>
        </register>
      </registers>
    </peripheral>
    <peripheral>
      <name>SPI2</name>
      <baseAddress>0x40003800</baseAddress>
      <registers>
        <register>
          <name>CR1</name>
          <addressOffset>0x0</addressOffset>
          <size>0x20</size>
          <fields>
            <field>
              <name>CPHA</name>
              <bitOffset>0</bitOffset>
              <bitWidth>1</bitWidth>
            </field>
            <field>
              <name>CPOL</name>
              <bitOffset>1</bitOffset>
              <bitWidth>1</bitWidth>
            </field>
            <field>
              <name>MSTR</name>
              <bitOffset>2</bitOffset>
              <bitWidth>1</bitWidth>
            </field>
            <field>
              <name>BR</name>
              <bitOffset>3</bitOffset>
              <bitWidth>3</bitWidth>
            </field>
            <field>
              <name>SPE</name>
              <bitOffset>6</bitOffset>
              <bitWidth>1</bitWidth>
            </field>
            <field>
              <name>LSBFIRST</name>
              <bitOffset>7</bitOffset>
              <bitWidth>1</bitWidth>
            </field>
            <field>
              <name>SSI</name>
              <bitOffset>8</bitOffset>
              <bitWidth>1</bitWidth>
            </field>
            <field>
              <name>SSM</name>
              <bitOffset>9</bitOffset>
              <bitWidth>1</bitWidth>
            </field>
            <field>
              <name>RXONLY</name>
              <bitOffset>10</bitOffset>
              <bitWidth>1</bitWidth>
            </field>
            <field>
              <name>DFF</name>
              <bitOffset>11</bitOffset>
              <bitWidth>1</bitWidth>
            </field>
            <field>
              <name>CRCNEXT</name>
              <bitOffset>12</bitOffset>
              <bitWidth>1</bitWidth>
            </field>
            <field>
              <name>CRCEN</name>
              <bitOffset>13</bitOffset>
              <bitWidth>1</bitWidth>
            </field>
            <field>
              <name>BIDIOE</name>
              <bitOffset>14</bitOffset>
              <bitWidth>1</bitWidth>
            </field>
            <field>
              <name>BIDIMODE</name>
              <bitOffset>15</bitOffset>
              <bitWidth>1</bitWidth>
            </field>
          </fields>
        </register>
        <register>
          <name>CR2</name>
          <addressOffset>0x4</addressOffset>
          <size>0x20</size>
          <fields>
            <field>
              <name>RXDMAEN</name>
              <bitOffset>0</bitOffset>
              <bitWidth>1</bitWidth>
            </field>
            <field>
              <name>TXDMAEN</name>
              <bitOffset>1</bitOffset>
              <bitWidth>1</bitWidth>
            </field>
            <field>
              <name>SSOE</name>
              <bitOffset>2</bitOffset>
              <bitWidth>1</bitWidth>
            </field>
            <field>
              <name>ERRIE</name>
              <bitOffset>5</bitOffset>
              <bitWidth>1</bitWidth>
            </field>
            <field>
              <name>RXNEIE</name>
              <bitOffset>6</bitOffset>
              <bitWidth>1</bitWidth>
            </field>
            <field>
              <name>TXEIE</name>
              <bitOffset>7</bitOffset>
              <bitWidth>1</bitWidth>
            </field>
          </fields>
        </register>
        <register>
          <name>SR</name>
          <addressOffset>0x8</addressOffset>
          <size>0x20</size>
          <fields>
            <field>
              <name>RXNE</name>
              <bitOffset>0</bitOffset>
              <bitWidth>1</bitWidth>
            </field>
            <field>
              <name>TXE</name>
              <bitOffset>1</bitOffset>
              <bitWidth>1</bitWidth>
            </field>
            <field>
              <name>CHSIDE</name>
              <bitOffset>2</bitOffset>
              <bitWidth>1</bitWidth>
            </field>
            <field>
              <name>UDR</name>
              <bitOffset>3</bitOffset>
              <bitWidth>1</bitWidth>
            </field>
            <field>
              <name>CRCERR</name>
              <bitOffset>4</bitOffset>
              <bitWidth>1</bitWidth>
            </field>
            <field>
              <name>MODF</name>
              <bitOffset>5</bitOffset>
              <bitWidth>1</bitWidth>
            </field>
            <field>
              <name>OVR</name>
              <bitOffset>6</bitOffset>
              <bitWidth>1</bitWidth>
            </field>
            <field>
              <name>BSY</name>
              <bitOffset>7</bitOffset>
              <bitWidth>1</bitWidth>
            </field>
            <field>
              <name>FRE</name>
              <bitOffset>8</bitOffset>
              <bitWidth>1</bitWidth>
            </field>
          </fields>
        </register>
        <register>
          <name>DR</name>
          <addressOffset>0xc</addressOffset>
          <size>0x20</size>
          <fields>
            <field>
              <name>DR</name>
              <bitOffset>0</bitOffset>
              <bitWidth>16</bitWidth>
            </field>
          </fields>
        </register>
        <register>
          <name>CRCPR</name>
          <addressOffset>0x10</addressOffset>
          <size>0x20</size>
          <fields>
            <field>
              <name>CRCPOLY</name>
              <bitOffset>0</bitOffset>
              <bitWidth>16</bitWidth>
            </field>
          </fields>
        </register>
        <register>
          <name>RXCRCR</name>
          <addressOffset>0x14</addressOffset>
          <size>0x20</size>
          <fields>
            <field>
              <name>RXCRC</name>
              <bitOffset>0</bitOffset>
              <bitWidth>16</bitWidth>
            </field>
          </fields>
        </register>
        <register>
          <name>TXCRCR</name>
          <addressOffset>0x18</addressOffset>
          <size>0x20</size>
          <fields>
            <field>
              <name>TXCRC</name>
              <bitOffset>0</bitOffset>
              <bitWidth>16</bitWidth>
            </field>
          </fields>
        </register>
      </registers>
    </peripheral>
    <peripheral>
      <name>USART2</name>
      <baseAddress>0x40004400</baseAddress>
      <registers>
        <register>
          <name>SR</name>
          <addressOffset>0x0</addressOffset>
          <size>0x20</size>
          <fields>
            <field>
              <name>PE</name>
              <bitOffset>0</bitOffset>
              <bitWidth>1</bitWidth>
            </field>
            <field>
              <name>FE</name>
              <bitOffset>1</bitOffset>
              <bitWidth>1</bitWidth>
            </field>
            <field>
              <name>NE</name>
              <bitOffset>2</bitOffset>
              <bitWidth>1</bitWidth>
            </field>
            <field>
              <name>ORE</name>
              <bitOffset>3</bitOffset>
              <bitWidth>1</bitWidth>
            </field>
            <field>
              <name>IDLE</name>
              <bitOffset>4</bitOffset>
              <bitWidth>1</bitWidth>
            </field>
            <field>
              <name>RXNE</name>
              <bitOffset>5</bitOffset>
              <bitWidth>1</bitWidth>
            </field>
            <field>
              <name>TC</name>
              <bitOffset>6</bitOffset>
              <bitWidth>1</bitWidth>
            </field>
            <field>
              <name>TXE</name>
              <bitOffset>7</bitOffset>
              <bitWidth>1</bitWidth>
            </field>
            <field>
              <name>LBD</name>
              <bitOffset>8</bitOffset>
              <bitWidth>1</bitWidth>
            </field>
            <field>
              <name>CTS</name>
              <bitOffset>9</bitOffset>
              <bitWidth>1</bitWidth>
            </field>
          </fields>
        </register>
        <register>
          <name>DR</name>
          <addressOffset>0x4</addressOffset>
          <size>0x20</size>
          <fields>
            <field>
              <name>DR</name>
              <bitOffset>0</bitOffset>
              <bitWidth>9</bitWidth>
            </field>
          </fields>
        </register>
        <register>
          <name>BRR</name>
          <addressOffset>0x8</addressOffset>
          <size>0x20</size>
          <fields>
            <field>
              <name>DIV_FRACTION</name>
              <bitOffset>0</bitOffset>
              <bitWidth>4</bitWidth>
            </field>
            <field>
              <name>DIV_MANTISSA</name>
              <bitOffset>4</bitOffset>
              <bitWidth>12</bitWidth>
            </field>
          </fields>
        </register>
        <register>
          <name>CR1</name>
          <addressOffset>0xc</addressOffset>
          <size>0x20</size>
          <fields>
            <field>
              <name>SBK</name>
              <bitOffset>0</bitOffset>
              <bitWidth>1</bitWidth>
            </field>
            <field>
              <name>RWU</name>
              <bitOffset>1</bitOffset>
              <bitWidth>1</bitWidth>
            </field>
            <field>
              <name>RE</name>
              <bitOffset>2</bitOffset>
              <bitWidth>1</bitWidth>
            </field>
            <field>
              <name>TE</name>
              <bitOffset>3</bitOffset>
              <bitWidth>1</bitWidth>
            </field>
            <field>
              <name>IDLEIE</name>
              <bitOffset>4</bitOffset>
              <bitWidth>1</bitWidth>
            </field>
            <field>
              <name>RXNEIE</name>
              <bitOffset>5</bitOffset>
              <bitWidth>1</bitWidth>
            </field>
            <field>
              <name>TCIE</name>
              <bitOffset>6</bitOffset>
              <bitWidth>1</bitWidth>
            </field>
            <field>
              <name>TXEIE</name>
              <bitOffset>7</bitOffset>
              <bitWidth>1</bitWidth>
            </field>
            <field>
              <name>PEIE</name>
              <bitOffset>8</bitOffset>
              <bitWidth>1</bitWidth>
            </field>
            <field>
              <name>PS</name>
              <bitOffset>9</bitOffset>
              <bitWidth>1</bitWidth>
            </field>
            <field>
              <name>PCE</name>
              <bitOffset>10</bitOffset>
              <bitWidth>1</bitWidth>
            </field>
            <field>
              <name>WAKE</name>
              <bitOffset>11</bitOffset>
              <bitWidth>1</bitWidth>
            </field>
            <field>
              <name>M</name>
              <bitOffset>12</bitOffset>
              <bitWidth>1</bitWidth>
            </field>
            <field>
              <name>UE</name>
              <bitOffset>13</bitOffset>
              <bitWidth>1</bitWidth>
            </field>
            <field>
              <name>OVER8</name>
              <bitOffset>15</bitOffset>
              <bitWidth>1</bitWidth>
            </field>
          </fields>
        </register>
        <register>
          <name>CR2</name>
          <addressOffset>0x10</addressOffset>
          <size>0x20</size>
          <fields>
            <field>
              <name>ADD</name>
              <bitOffset>0</bitOffset>
              <bitWidth>4</bitWidth>
            </field>
            <field>
              <name>LBDL</name>
              <bitOffset>5</bitOffset>
              <bitWidth>1</bitWidth>
            </field>
            <field>
              <name>LBDIE</name>
              <bitOffset>6</bitOffset>
              <bitWidth>1</bitWidth>
            </field>
            <field>
              <name>LBCL</name>
              <bitOffset>8</bitOffset>
              <bitWidth>1</bitWidth>
            </field>
            <field>
              <name>CPHA</name>
              <bitOffset>9</bitOffset>
              <bitWidth>1</bitWidth>
            </field>
            <field>
              <name>CPOL</name>
              <bitOffset>10</bitOffset>
              <bitWidth>1</bitWidth>
            </field>
            <field>
              <name>CLKEN</name>
              <bitOffset>11</bitOffset>
              <bitWidth>1</bitWidth>
            </field>
            <field>
              <name>STOP</name>
              <bitOffset>12</bitOffset>
              <bitWidth>2</bitWidth>
            </field>
            <field>
              <name>LINEN</name>
              <bitOffset>14</bitOffset>
              <bitWidth>1</bitWidth>
            </field>
          </fields>
        </register>
        <register>
          <name>CR3</name>
          <addressOffset>0x14</addressOffset>
          <size>0x20</size>
          <fields>
            <field>
              <name>EIE</name>
              <bitOffset>0</bitOffset>
              <bitWidth>1</bitWidth>
            </field>
            <field>
              <name>IREN</name>
              <bitOffset>1</bitOffset>
              <bitWidth>1</bitWidth>
            </field>
            <field>
              <name>IRLP</name>
              <bitOffset>2</bitOffset>
              <bitWidth>1</bitWidth>
            </field>
            <field>
              <name>HDSEL</name>
              <bitOffset>3</bitOffset>
              <bitWidth>1</bitWidth>
            </field>
            <field>
              <name>NACK</name>
              <bitOffset>4</bitOffset>
              <bitWidth>1</bitWidth>
            </field>
            <field>
              <name>SCEN</name>
              <bitOffset>5</bitOffset>
              <bitWidth>1</bitWidth>
            </field>
            <field>
              <name>DMAR</name>
              <bitOffset>6</bitOffset>
              <bitWidth>1</bitWidth>
            </field>
            <field>
              <name>DMAT</name>
              <bitOffset>7</bitOffset>
              <bitWidth>1</bitWidth>
            </field>
            <field>
              <name>RTSE</name>
              <bitOffset>8</bitOffset>
              <bitWidth>1</bitWidth>
            </field>
            <field>
              <name>CTSE</name>
              <bitOffset>9</bitOffset>
              <bitWidth>1</bitWidth>
            </field>
            <field>
              <name>CTSIE</name>
              <bitOffset>10</bitOffset>
              <bitWidth>1</bitWidth>
            </field>
            <field>
              <name>ONEBIT</name>
              <bitOffset>11</bitOffset>
              <bitWidth>1</bitWidth>
            </field>
          </fields>
        </register>
        <register>
          <name>GTPR</name>
          <addressOffset>0x18</addressOffset>
          <size>0x20</size>
          <fields>
            <field>
              <name>PSC</name>
              <bitOffset>0</bitOffset>
              <bitWidth>8</bitWidth>
            </field>
            <field>
              <name>GT</name>
              <bitOffset>8</bitOffset>
              <bitWidth>8</bitWidth>
            </field>
          </fields>
        </register>
      </registers>
    </peripheral>
    <peripheral>
      <name>USART3</name>
      <baseAddress>0x40004800</baseAddress>
      <registers>
        <register>
          <name>SR</name>
          <addressOffset>0x0</addressOffset>
          <size>0x20</size>
          <fields>
            <field>
              <name>PE</name>
              <bitOffset>0</bitOffset>
              <bitWidth>1</bitWidth>
            </field>
            <field>
              <name>FE</name>
              <bitOffset>1</bitOffset>
              <bitWidth>1</bitWidth>
            </field>
            <field>
              <name>NE</name>
              <bitOffset>2</bitOffset>
              <bitWidth>1</bitWidth>
            </field>
            <field>
              <name>ORE</name>
              <bitOffset>3</bitOffset>
              <bitWidth>1</bitWidth>
            </field>
            <field>
              <name>IDLE</name>
              <bitOffset>4</bitOffset>
              <bitWidth>1</bitWidth>
            </field>
            <field>
              <name>RXNE</name>
              <bitOffset>5</bitOffset>
              <bitWidth>1</bitWidth>
            </field>
            <field>
              <name>TC</name>
              <bitOffset>6</bitOffset>
              <bitWidth>1</bitWidth>
            </field>
            <field>
              <name>TXE</name>
              <bitOffset>7</bitOffset>
              <bitWidth>1</bitWidth>
            </field>
            <field>
              <name>LBD</name>
              <bitOffset>8</bitOffset>
              <bitWidth>1</bitWidth>
            </field>
            <field>
              <name>CTS</name>
              <bitOffset>9</bitOffset>
              <bitWidth>1</bitWidth>
            </field>
          </fields>
        </register>
        <register>
          <name>DR</name>
          <addressOffset>0x4</addressOffset>
          <size>0x20</size>
          <fields>
            <field>
              <name>DR</name>
              <bitOffset>0</bitOffset>
              <bitWidth>9</bitWidth>
            </field>
          </fields>
        </register>
        <register>
          <name>BRR</name>
          <addressOffset>0x8</addressOffset>
          <size>0x20</size>
          <fields>
            <field>
              <name>DIV_FRACTION</name>
              <bitOffset>0</bitOffset>
              <bitWidth>4</bitWidth>
            </field>
            <field>
              <name>DIV_MANTISSA</name>
              <bitOffset>4</bitOffset>
              <bitWidth>12</bitWidth>
            </field>
          </fields>
        </register>
        <register>
          <name>CR1</name>
          <addressOffset>0xc</addressOffset>
          <size>0x20</size>
          <fields>
            <field>
              <name>SBK</name>
              <bitOffset>0</bitOffset>
              <bitWidth>1</bitWidth>
            </field>
            <field>
              <name>RWU</name>
              <bitOffset>1</bitOffset>
              <bitWidth>1</bitWidth>
            </field>
            <field>
              <name>RE</name>
              <bitOffset>2</bitOffset>
              <bitWidth>1</bitWidth>
            </field>
            <field>
              <name>TE</name>
              <bitOffset>3</bitOffset>
              <bitWidth>1</bitWidth>
            </field>
            <field>
              <name>IDLEIE</name>
              <bitOffset>4</bitOffset>
              <bitWidth>1</bitWidth>
            </field>
            <field>
              <name>RXNEIE</name>
              <bitOffset>5</bitOffset>
              <bitWidth>1</bitWidth>
            </field>
            <field>
              <name>TCIE</name>
              <bitOffset>6</bitOffset>
              <bitWidth>1</bitWidth>
            </field>
            <field>
              <name>TXEIE</name>
              <bitOffset>7</bitOffset>
              <bitWidth>1</bitWidth>
            </field>
            <field>
              <name>PEIE</name>
              <bitOffset>8</bitOffset>
              <bitWidth>1</bitWidth>
            </field>
            <field>
              <name>PS</name>
              <bitOffset>9</bitOffset>
              <bitWidth>1</bitWidth>
            </field>
            <field>
              <name>PCE</name>
              <bitOffset>10</bitOffset>
              <bitWidth>1</bitWidth>
            </field>
            <field>
              <name>WAKE</name>
              <bitOffset>11</bitOffset>
              <bitWidth>1</bitWidth>
            </field>
            <field>
              <name>M</name>
              <bitOffset>12</bitOffset>
              <bitWidth>1</bitWidth>
            </field>
            <field>
              <name>UE</name>
              <bitOffset>13</bitOffset>
              <bitWidth>1</bitWidth>
            </field>
            <field>
              <name>OVER8</name>
              <bitOffset>15</bitOffset>
              <bitWidth>1</bitWidth>
            </field>
          </fields>
        </register>
        <register>
          <name>CR2</name>
          <addressOffset>0x10</addressOffset>
          <size>0x20</size>
          <fields>
            <field>
              <name>ADD</name>
              <bitOffset>0</bitOffset>
              <bitWidth>4</bitWidth>
            </field>
            <field>
              <name>LBDL</name>
              <bitOffset>5</bitOffset>
              <bitWidth>1</bitWidth>
            </field>
            <field>
              <name>LBDIE</name>
              <bitOffset>6</bitOffset>
              <bitWidth>1</bitWidth>
            </field>
            <field>
              <name>LBCL</name>
              <bitOffset>8</bitOffset>
              <bitWidth>1</bitWidth>
            </field>
            <field>
              <name>CPHA</name>
              <bitOffset>9</bitOffset>
              <bitWidth>1</bitWidth>
            </field>
            <field>
              <name>CPOL</name>
              <bitOffset>10</bitOffset>
              <bitWidth>1</bitWidth>
            </field>
            <field>
              <name>CLKEN</name>
              <bitOffset>11</bitOffset>
              <bitWidth>1</bitWidth>
            </field>
            <field>
              <name>STOP</name>
              <bitOffset>12</bitOffset>
              <bitWidth>2</bitWidth>
            </field>
            <field>
              <name>LINEN</name>
              <bitOffset>14</bitOffset>
              <bitWidth>1</bitWidth>
            </field>
          </fields>
        </register>
        <register>
          <name>CR3</name>
          <addressOffset>0x14</addressOffset>
          <size>0x20</size>
          <fields>
            <field>
              <name>EIE</name>
              <bitOffset>0</bitOffset>
              <bitWidth>1</bitWidth>
            </field>
            <field>
              <name>IREN</name>
              <bitOffset>1</bitOffset>
              <bitWidth>1</bitWidth>
            </field>
            <field>
              <name>IRLP</name>
              <bitOffset>2</bitOffset>
              <bitWidth>1</bitWidth>
            </field>
            <field>
              <name>HDSEL</name>
              <bitOffset>3</bitOffset>
              <bitWidth>1</bitWidth>
            </field>
            <field>
              <name>NACK</name>
              <bitOffset>4</bitOffset>
              <bitWidth>1</bitWidth>
            </field>
            <field>
              <name>SCEN</name>
              <bitOffset>5</bitOffset>
              <bitWidth>1</bitWidth>
            </field>
            <field>
              <name>DMAR</name>
              <bitOffset>6</bitOffset>
              <bitWidth>1</bitWidth>
            </field>
            <field>
              <name>DMAT</name>
              <bitOffset>7</bitOffset>
              <bitWidth>1</bitWidth>
            </field>
            <field>
              <name>RTSE</name>
              <bitOffset>8</bitOffset>
              <bitWidth>1</bitWidth>
            </field>
            <field>
              <name>CTSE</name>
              <bitOffset>9</bitOffset>
              <bitWidth>1</bitWidth>
            </field>
            <field>
              <name>CTSIE</name>
              <bitOffset>10</bitOffset>
              <bitWidth>1</bitWidth>
            </field>
            <field>
              <name>ONEBIT</name>
              <bitOffset>11</bitOffset>
              <bitWidth>1</bitWidth>
            </field>
          </fields>
        </register>
        <register>
          <name>GTPR</name>
          <addressOffset>0x18</addressOffset>
          <size>0x20</size>
          <fields>
            <field>
              <name>PSC</name>
              <bitOffset>0</bitOffset>
              <bitWidth>8</bitWidth>
            </field>
            <field>
              <name>GT</name>
              <bitOffset>8</bitOffset>
              <bitWidth>8</bitWidth>
            </field>
          </fields>
        </register>
      </registers>
    </peripheral>
    <peripheral>
      <name>I2C1</name>
      <baseAddress>0x40005400</baseAddress>
      <registers>
        <register>
          <name>CR1</name>
          <addressOffset>0x0</addressOffset>
          <size>0x20</size>
          <fields>
            <field>
              <name>PE</name>
              <bitOffset>0</bitOffset>
              <bitWidth>1</bitWidth>
            </field>
            <field>
              <name>SMBUS</name>
              <bitOffset>1</bitOffset>
              <bitWidth>1</bitWidth>
            </field>
            <field>
              <name>SMBTYPE</name>
              <bitOffset>3</bitOffset>
              <bitWidth>1</bitWidth>
            </field>
            <field>
              <name>ENARP</name>
              <bitOffset>4</bitOffset>
              <bitWidth>1</bitWidth>
            </field>
            <field>
              <name>ENPEC</name>
              <bitOffset>5</bitOffset>
              <bitWidth>1</bitWidth>
            </field>
            <field>
              <name>ENGC</name>
              <bitOffset>6</bitOffset>
              <bitWidth>1</bitWidth>
            </field>
            <field>
              <name>NOSTRETCH</name>
              <bitOffset>7</bitOffset>
              <bitWidth>1</bitWidth>
            </field>
            <field>
              <name>START</name>
              <bitOffset>8</bitOffset>
              <bitWidth>1</bitWidth>
            </field>
            <field>
              <name>STOP</name>
              <bitOffset>9</bitOffset>
              <bitWidth>1</bitWidth>
            </field>
            <field>
              <name>ACK</name>
              <bitOffset>10</bitOffset>
              <bitWidth>1</bitWidth>
            </field>
            <field>
              <name>POS</name>
              <bitOffset>11</bitOffset>
              <bitWidth>1</bitWidth>
            </field>
            <field>
              <name>PEC</name>
              <bitOffset>12</bitOffset>
              <bitWidth>1</bitWidth>
            </field>
            <field>
              <name>ALERT</name>
              <bitOffset>13</bitOffset>
              <bitWidth>1</bitWidth>
            </field>
            <field>
              <name>SWRST</name>
              <bitOffset>15</bitOffset>
              <bitWidth>1</bitWidth>
            </field>
          </fields>
        </register>
        <register>
          <name>CR2</name>
          <addressOffset>0x4</addressOffset>
          <size>0x20</size>
          <fields>
            <field>
              <name>FREQ</name>
              <bitOffset>0</bitOffset>
              <bitWidth>6</bitWidth>
            </field>
            <field>
              <name>ITERREN</name>
              <bitOffset>8</bitOffset>
              <bitWidth>1</bitWidth>
            </field>
            <field>
              <name>ITEVTEN</name>
              <bitOffset>9</bitOffset>
              <bitWidth>1</bitWidth>
            </field>
            <field>
              <name>ITBUFEN</name>
              <bitOffset>10</bitOffset>
              <bitWidth>1</bitWidth>
            </field>
            <field>
              <name>DMAEN</name>
              <bitOffset>11</bitOffset>
              <bitWidth>1</bitWidth>
            </field>
            <field>
              <name>LAST</name>
              <bitOffset>12</bitOffset>
              <bitWidth>1</bitWidth>
            </field>
          </fields>
        </register>
        <register>
          <name>OAR1</name>
          <addressOffset>0x8</addressOffset>
          <size>0x20</size>
          <fields>
            <field>
              <name>ADD0</name>
              <bitOffset>0</bitOffset>
              <bitWidth>1</bitWidth>
            </field>
            <field>
              <name>ADD1</name>
              <bitOffset>1</bitOffset>
              <bitWidth>1</bitWidth>
            </field>
            <field>
              <name>ADD2</name>
              <bitOffset>2</bitOffset>
              <bitWidth>1</bitWidth>
            </field>
            <field>
              <name>ADD3</name>
              <bitOffset>3</bitOffset>
              <bitWidth>1</bitWidth>
            </field>
            <field>
              <name>ADD4</name>
              <bitOffset>4</bitOffset>
              <bitWidth>1</bitWidth>
            </field>
            <field>
              <name>ADD5</name>
              <bitOffset>5</bitOffset>
              <bitWidth>1</bitWidth>
            </field>
            <field>
              <name>ADD6</name>
              <bitOffset>6</bitOffset>
              <bitWidth>1</bitWidth>
            </field>
            <field>
              <name>ADD7</name>
              <bitOffset>7</bitOffset>
              <bitWidth>1</bitWidth>
            </field>
            <field>
              <name>ADD8</name>
              <bitOffset>8</bitOffset>
              <bitWidth>1</bitWidth>
            </field>
            <field>
              <name>ADD9</name>
              <bitOffset>9</bitOffset>
              <bitWidth>1</bitWidth>
            </field>
            <field>
              <name>ADDMODE</name>
              <bitOffset>15</bitOffset>
              <bitWidth>1</bitWidth>
            </field>
          </fields>
        </register>
        <register>
          <name>OAR2</name>
          <addressOffset>0xc</addressOffset>
          <size>0x20</size>
          <fields>
            <field>
              <name>ENDUAL</name>
              <bitOffset>0</bitOffset>
              <bitWidth>1</bitWidth>
            </field>
            <field>
              <name>ADD2</name>
              <bitOffset>1</bitOffset>
              <bitWidth>7</bitWidth>
            </field>
          </fields>
        </register>
        <register>
          <name>DR</name>
          <addressOffset>0x10</addressOffset>
          <size>0x20</size>
          <fields>
            <field>
              <name>DR</name>
              <bitOffset>0</bitOffset>
              <bitWidth>8</bitWidth>
            </field>
          </fields>
        </register>
        <register>
          <name>SR1</name>
          <addressOffset>0x14</addressOffset>
          <size>0x20</size>
          <fields>
            <field>
              <name>SB</name>
              <bitOffset>0</bitOffset>
              <bitWidth>1</bitWidth>
            </field>
            <field>
              <name>ADDR</name>
              <bitOffset>1</bitOffset>
              <bitWidth>1</bitWidth>
            </field>
            <field>
              <name>BTF</name>
              <bitOffset>2</bitOffset>
              <bitWidth>1</bitWidth>
            </field>
            <field>
              <name>ADD10</name>
              <bitOffset>3</bitOffset>
              <bitWidth>1</bitWidth>
            </field>
            <field>
              <name>STOPF</name>
              <bitOffset>4</bitOffset>
              <bitWidth>1</bitWidth>
            </field>
            <field>
              <name>RXNE</name>
              <bitOffset>6</bitOffset>
              <bitWidth>1</bitWidth>
            </field>
            <field>
              <name>TXE</name>
              <bitOffset>7</bitOffset>
              <bitWidth>1</bitWidth>
            </field>
            <field>
              <name>BERR</name>
              <bitOffset>8</bitOffset>
              <bitWidth>1</bitWidth>
            </field>
            <field>
              <name>ARLO</name>
              <bitOffset>9</bitOffset>
              <bitWidth>1</bitWidth>
            </field>
            <field>
              <name>AF</name>
              <bitOffset>10</bitOffset>
              <bitWidth>1</bitWidth>
            </field>
            <field>
              <name>OVR</name>
              <bitOffset>11</bitOffset>
              <bitWidth>1</bitWidth>
            </field>
            <field>
              <name>PECERR</name>
              <bitOffset>12</bitOffset>
              <bitWidth>1</bitWidth>
            </field>
            <field>
              <name>TIMEOUT</name>
              <bitOffset>14</bitOffset>
              <bitWidth>1</bitWidth>
            </field>
            <field>
              <name>SMBALERT</name>
              <bitOffset>15</bitOffset>
              <bitWidth>1</bitWidth>
            </field>
          </fields>
        </register>
        <register>
          <name>SR2</name>
          <addressOffset>0x18</addressOffset>
          <size>0x20</size>
          <fields>
            <field>
              <name>MSL</name>
              <bitOffset>0</bitOffset>
              <bitWidth>1</bitWidth>
            </field>
            <field>
              <name>BUSY</name>
              <bitOffset>1</bitOffset>
              <bitWidth>1</bitWidth>
            </field>
            <field>
              <name>TRA</name>
              <bitOffset>2</bitOffset>
              <bitWidth>1</bitWidth>
            </field>
            <field>
              <name>GENCALL</name>
              <bitOffset>4</bitOffset>
              <bitWidth>1</bitWidth>
            </field>
            <field>
              <name>SMBDEFAULT</name>
              <bitOffset>5</bitOffset>
              <bitWidth>1</bitWidth>
            </field>
            <field>
              <name>SMBHOST</name>
              <bitOffset>6</bitOffset>
              <bitWidth>1</bitWidth>
            </field>
            <field>
              <name>DUALF</name>
              <bitOffset>7</bitOffset>
              <bitWidth>1</bitWidth>
            </field>
            <field>
              <name>PEC</name>
              <bitOffset>8</bitOffset>
              <bitWidth>8</bitWidth>
            </field>
          </fields>
        </register>
        <register>
          <name>CCR</name>
          <addressOffset>0x1c</addressOffset>
          <size>0x20</size>
          <fields>
            <field>
              <name>CCR</name>
              <bitOffset>0</bitOffset>
              <bitWidth>12</bitWidth>
            </field>
            <field>
              <name>DUTY</name>
              <bitOffset>14</bitOffset>
              <bitWidth>1</bitWidth>
            </field>
            <field>
              <name>FS</name>
              <bitOffset>15</bitOffset>
              <bitWidth>1</bitWidth>
            </field>
          </fields>
        </register>
        <register>
          <name>TRISE</name>
          <addressOffset>0x20</addressOffset>
          <size>0x20</size>
          <fields>
            <field>
              <name>TRISE</name>
              <bitOffset>0</bitOffset>
              <bitWidth>6</bitWidth>
            </field>
          </fields>
        </register>
      </registers>
    </peripheral>
    <peripheral>
      <name>I2C2</name>
      <baseAddress>0x40005800</baseAddress>
      <registers>
        <register>
          <name>CR1</name>
          <addressOffset>0x0</addressOffset>
          <size>0x20</size>
          <fields>
            <field>
              <name>PE</name>
              <bitOffset>0</bitOffset>
              <bitWidth>1</bitWidth>
            </field>
            <field>
              <name>SMBUS</name>
              <bitOffset>1</bitOffset>
              <bitWidth>1</bitWidth>
            </field>
            <field>
              <name>SMBTYPE</name>
              <bitOffset>3</bitOffset>
              <bitWidth>1</bitWidth>
            </field>
            <field>
              <name>ENARP</name>
              <bitOffset>4</bitOffset>
              <bitWidth>1</bitWidth>
            </field>
            <field>
              <name>ENPEC</name>
              <bitOffset>5</bitOffset>
              <bitWidth>1</bitWidth>
            </field>
            <field>
              <name>ENGC</name>
              <bitOffset>6</bitOffset>
              <bitWidth>1</bitWidth>
            </field>
            <field>
              <name>NOSTRETCH</name>
              <bitOffset>7</bitOffset>
              <bitWidth>1</bitWidth>
            </field>
            <field>
              <name>START</name>
              <bitOffset>8</bitOffset>
              <bitWidth>1</bitWidth>
            </field>
            <field>
              <name>STOP</name>
              <bitOffset>9</bitOffset>
              <bitWidth>1</bitWidth>
            </field>
            <field>
              <name>ACK</name>
              <bitOffset>10</bitOffset>
              <bitWidth>1</bitWidth>
            </field>
            <field>
              <name>POS</name>
              <bitOffset>11</bitOffset>
              <bitWidth>1</bitWidth>
            </field>
            <field>
              <name>PEC</name>
              <bitOffset>12</bitOffset>
              <bitWidth>1</bitWidth>
            </field>
            <field>
              <name>ALERT</name>
              <bitOffset>13</bitOffset>
              <bitWidth>1</bitWidth>
            </field>
            <field>
              <name>SWRST</name>
              <bitOffset>15</bitOffset>
              <bitWidth>1</bitWidth>
            </field>
          </fields>
        </register>
        <register>
          <name>CR2</name>
          <addressOffset>0x4</addressOffset>
          <size>0x20</size>
          <fields>
            <field>
              <name>FREQ</name>
              <bitOffset>0</bitOffset>
              <bitWidth>6</bitWidth>
            </field>
            <field>
              <name>ITERREN</name>
              <bitOffset>8</bitOffset>
              <bitWidth>1</bitWidth>
            </field>
            <field>
              <name>ITEVTEN</name>
              <bitOffset>9</bitOffset>
              <bitWidth>1</bitWidth>
            </field>
            <field>
              <name>ITBUFEN</name>
              <bitOffset>10</bitOffset>
              <bitWidth>1</bitWidth>
            </field>
            <field>
              <name>DMAEN</name>
              <bitOffset>11</bitOffset>
              <bitWidth>1</bitWidth>
            </field>
            <field>
              <name>LAST</name>
              <bitOffset>12</bitOffset>
              <bitWidth>1</bitWidth>
            </field>
          </fields>
        </register>
        <register>
          <name>OAR1</name>
          <addressOffset>0x8</addressOffset>
          <size>0x20</size>
          <fields>
            <field>
              <name>ADD0</name>
              <bitOffset>0</bitOffset>
              <bitWidth>1</bitWidth>
            </field>
            <field>
              <name>ADD1</name>
              <bitOffset>1</bitOffset>
              <bitWidth>1</bitWidth>
            </field>
            <field>
              <name>ADD2</name>
              <bitOffset>2</bitOffset>
              <bitWidth>1</bitWidth>
            </field>
            <field>
              <name>ADD3</name>
              <bitOffset>3</bitOffset>
              <bitWidth>1</bitWidth>
            </field>
            <field>
              <name>ADD4</name>
              <bitOffset>4</bitOffset>
              <bitWidth>1</bitWidth>
            </field>
            <field>
              <name>ADD5</name>
              <bitOffset>5</bitOffset>
              <bitWidth>1</bitWidth>
            </field>
            <field>
              <name>ADD6</name>
              <bitOffset>6</bitOffset>
              <bitWidth>1</bitWidth>
            </field>
            <field>
              <name>ADD7</name>
              <bitOffset>7</bitOffset>
              <bitWidth>1</bitWidth>
            </field>
            <field>
              <name>ADD8</name>
              <bitOffset>8</bitOffset>
              <bitWidth>1</bitWidth>
            </field>
            <field>
              <name>ADD9</name>
              <bitOffset>9</bitOffset>
              <bitWidth>1</bitWidth>
            </field>
            <field>
              <name>ADDMODE</name>
              <bitOffset>15</bitOffset>
              <bitWidth>1</bitWidth>
            </field>
          </fields>
        </register>
        <register>
          <name>OAR2</name>
          <addressOffset>0xc</addressOffset>
          <size>0x20</size>
          <fields>
            <field>
              <name>ENDUAL</name>
              <bitOffset>0</bitOffset>
              <bitWidth>1</bitWidth>
            </field>
            <field>
              <name>ADD2</name>
              <bitOffset>1</bitOffset>
              <bitWidth>7</bitWidth>
            </field>
          </fields>
        </register>
        <register>
          <name>DR</name>
          <addressOffset>0x10</addressOffset>
          <size>0x20</size>
          <fields>
            <field>
              <name>DR</name>
              <bitOffset>0</bitOffset>
              <bitWidth>8</bitWidth>
            </field>
          </fields>
        </register>
        <register>
          <name>SR1</name>
          <addressOffset>0x14</addressOffset>
          <size>0x20</size>
          <fields>
            <field>
              <name>SB</name>
              <bitOffset>0</bitOffset>
              <bitWidth>1</bitWidth>
            </field>
            <field>
              <name>ADDR</name>
              <bitOffset>1</bitOffset>
              <bitWidth>1</bitWidth>
            </field>
            <field>
              <name>BTF</name>
              <bitOffset>2</bitOffset>
              <bitWidth>1</bitWidth>
            </field>
            <field>
              <name>ADD10</name>
              <bitOffset>3</bitOffset>
              <bitWidth>1</bitWidth>
            </field>
            <field>
              <name>STOPF</name>
              <bitOffset>4</bitOffset>
              <bitWidth>1</bitWidth>
            </field>
            <field>
              <name>RXNE</name>
              <bitOffset>6</bitOffset>
              <bitWidth>1</bitWidth>
            </field>
            <field>
              <name>TXE</name>
              <bitOffset>7</bitOffset>
              <bitWidth>1</bitWidth>
            </field>
            <field>
              <name>BERR</name>
              <bitOffset>8</bitOffset>
              <bitWidth>1</bitWidth>
            </field>
            <field>
              <name>ARLO</name>
              <bitOffset>9</bitOffset>
              <bitWidth>1</bitWidth>
            </field>
            <field>
              <name>AF</name>
              <bitOffset>10</bitOffset>
              <bitWidth>1</bitWidth>
            </field>
            <field>
              <name>OVR</name>
              <bitOffset>11</bitOffset>
              <bitWidth>1</bitWidth>
            </field>
            <field>
              <name>PECERR</name>
              <bitOffset>12</bitOffset>
              <bitWidth>1</bitWidth>
            </field>
            <field>
              <name>TIMEOUT</name>
              <bitOffset>14</bitOffset>
              <bitWidth>1</bitWidth>
            </field>
            <field>
              <name>SMBALERT</name>
              <bitOffset>15</bitOffset>
              <bitWidth>1</bitWidth>
            </field>
          </fields>
        </register>
        <register>
          <name>SR2</name>
          <addressOffset>0x18</addressOffset>
          <size>0x20</size>
          <fields>
            <field>
              <name>MSL</name>
              <bitOffset>0</bitOffset>
              <bitWidth>1</bitWidth>
            </field>
            <field>
              <name>BUSY</name>
              <bitOffset>1</bitOffset>
              <bitWidth>1</bitWidth>
            </field>
            <field>
              <name>TRA</name>
              <bitOffset>2</bitOffset>
              <bitWidth>1</bitWidth>
            </field>
            <field>
              <name>GENCALL</name>
              <bitOffset>4</bitOffset>
              <bitWidth>1</bitWidth>
            </field>
            <field>
              <name>SMBDEFAULT</name>
              <bitOffset>5</bitOffset>
              <bitWidth>1</bitWidth>
            </field>
            <field>
              <name>SMBHOST</name>
              <bitOffset>6</bitOffset>
              <bitWidth>1</bitWidth>
            </field>
            <field>
              <name>DUALF</name>
              <bitOffset>7</bitOffset>
              <bitWidth>1</bitWidth>
            </field>
            <field>
              <name>PEC</name>
              <bitOffset>8</bitOffset>
              <bitWidth>8</bitWidth>
            </field>
          </fields>
        </register>
        <register>
          <name>CCR</name>
          <addressOffset>0x1c</addressOffset>
          <size>0x20</size>
          <fields>
            <field>
              <name>CCR</name>
              <bitOffset>0</bitOffset>
              <bitWidth>12</bitWidth>
            </field>
            <field>
              <name>DUTY</name>
              <bitOffset>14</bitOffset>
              <bitWidth>1</bitWidth>
            </field>
            <field>
              <name>FS</name>
              <bitOffset>15</bitOffset>
              <bitWidth>1</bitWidth>
            </field>
          </fields>
        </register>
        <register>
          <name>TRISE</name>
          <addressOffset>0x20</addressOffset>
          <size>0x20</size>
          <fields>
            <field>
              <name>TRISE</name>
              <bitOffset>0</bitOffset>
              <bitWidth>6</bitWidth>
            </field>
          </fields>
        </register>
      </registers>
    </peripheral>
    <peripheral>
      <name>USB</name>
      <baseAddress>0x40005c00</baseAddress>
      <registers>
        <register>
          <name>EP0R</name>
          <addressOffset>0x0</addressOffset>
          <size>0x10</size>
          <fields>
            <field>
              <name>EA</name>
              <bitOffset>0</bitOffset>
              <bitWidth>4</bitWidth>
            </field>
            <field>
              <name>STAT_TX</name>
              <bitOffset>4</bitOffset>
              <bitWidth>2</bitWidth>
            </field>
            <field>
              <name>DTOG_TX</name>
              <bitOffset>6</bitOffset>
              <bitWidth>1</bitWidth>
            </field>
            <field>
              <name>CTR_TX</name>
              <bitOffset>7</bitOffset>
              <bitWidth>1</bitWidth>
            </field>
            <field>
              <name>EP_KIND</name>
              <bitOffset>8</bitOffset>
              <bitWidth>1</bitWidth>
            </field>
            <field>
              <name>EP_TYPE</name>
              <bitOffset>9</bitOffset>
              <bitWidth>2</bitWidth>
            </field>
            <field>
              <name>SETUP</name>
              <bitOffset>11</bitOffset>
              <bitWidth>1</bitWidth>
            </field>
            <field>
              <name>STAT_RX</name>
              <bitOffset>12</bitOffset>
              <bitWidth>2</bitWidth>
            </field>
            <field>
              <name>DTOG_RX</name>
              <bitOffset>14</bitOffset>
              <bitWidth>1</bitWidth>
            </field>
            <field>
              <name>CTR_RX</name>
              <bitOffset>15</bitOffset>
              <bitWidth>1</bitWidth>
            </field>
          </fields>
        </register>
        <register>
          <name>EP1R</name>
          <addressOffset>0x4</addressOffset>
          <size>0x10</size>
          <fields>
            <field>
              <name>EA</name>
              <bitOffset>0</bitOffset>
              <bitWidth>4</bitWidth>
            </field>
            <field>
              <name>STAT_TX</name>
              <bitOffset>4</bitOffset>
              <bitWidth>2</bitWidth>
            </field>
            <field>
              <name>DTOG_TX</name>
              <bitOffset>6</bitOffset>
              <bitWidth>1</bitWidth>
            </field>
            <field>
              <name>CTR_TX</name>
              <bitOffset>7</bitOffset>
              <bitWidth>1</bitWidth>
            </field>
            <field>
              <name>EP_KIND</name>
              <bitOffset>8</bitOffset>
              <bitWidth>1</bitWidth>
            </field>
            <field>
              <name>EP_TYPE</name>
              <bitOffset>9</bitOffset>
              <bitWidth>2</bitWidth>
            </field>
            <field>
              <name>SETUP</name>
              <bitOffset>11</bitOffset>
              <bitWidth>1</bitWidth>
            </field>
            <field>
              <name>STAT_RX</name>
              <bitOffset>12</bitOffset>
              <bitWidth>2</bitWidth>
            </field>
            <field>
              <name>DTOG_RX</name>
              <bitOffset>14</bitOffset>
              <bitWidth>1</bitWidth>
            </field>
            <field>
              <name>CTR_RX</name>
              <bitOffset>15</bitOffset>
              <bitWidth>1</bitWidth>
            </field>
          </fields>
        </register>
        <register>
          <name>EP2R</name>
          <addressOffset>0x8</addressOffset>
          <size>0x10</size>
          <fields>
            <field>
              <name>EA</name>
              <bitOffset>0</bitOffset>
              <bitWidth>4</bitWidth>
            </field>
            <field>
              <name>STAT_TX</name>
              <bitOffset>4</bitOffset>
              <bitWidth>2</bitWidth>
            </field>
            <field>
              <name>DTOG_TX</name>
              <bitOffset>6</bitOffset>
              <bitWidth>1</bitWidth>
            </field>
            <field>
              <name>CTR_TX</name>
              <bitOffset>7</bitOffset>
              <bitWidth>1</bitWidth>
            </field>
            <field>
              <name>EP_KIND</name>
              <bitOffset>8</bitOffset>
              <bitWidth>1</bitWidth>
            </field>
            <field>
              <name>EP_TYPE</name>
              <bitOffset>9</bitOffset>
              <bitWidth>2</bitWidth>
            </field>
            <field>
              <name>SETUP</name>
              <bitOffset>11</bitOffset>
              <bitWidth>1</bitWidth>
            </field>
            <field>
              <name>STAT_RX</name>
              <bitOffset>12</bitOffset>
              <bitWidth>2</bitWidth>
            </field>
            <field>
              <name>DTOG_RX</name>
              <bitOffset>14</bitOffset>
              <bitWidth>1</bitWidth>
            </field>
            <field>
              <name>CTR_RX</name>
              <bitOffset>15</bitOffset>
              <bitWidth>1</bitWidth>
            </field>
          </fields>
        </register>
        <register>
          <name>EP3R</name>
          <addressOffset>0xc</addressOffset>
          <size>0x10</size>
          <fields>
            <field>
              <name>EA</name>
              <bitOffset>0</bitOffset>
              <bitWidth>4</bitWidth>
            </field>
            <field>
              <name>STAT_TX</name>
              <bitOffset>4</bitOffset>
              <bitWidth>2</bitWidth>
            </field>
            <field>
              <name>DTOG_TX</name>
              <bitOffset>6</bitOffset>
              <bitWidth>1</bitWidth>
            </field>
            <field>
              <name>CTR_TX</name>
              <bitOffset>7</bitOffset>
              <bitWidth>1</bitWidth>
            </field>
            <field>
              <name>EP_KIND</name>
              <bitOffset>8</bitOffset>
              <bitWidth>1</bitWidth>
            </field>
            <field>
              <name>EP_TYPE</name>
              <bitOffset>9</bitOffset>
              <bitWidth>2</bitWidth>
            </field>
            <field>
              <name>SETUP</name>
              <bitOffset>11</bitOffset>
              <bitWidth>1</bitWidth>
            </field>
            <field>
              <name>STAT_RX</name>
              <bitOffset>12</bitOffset>
              <bitWidth>2</bitWidth>
            </field>
            <field>
              <name>DTOG_RX</name>
              <bitOffset>14</bitOffset>
              <bitWidth>1</bitWidth>
            </field>
            <field>
              <name>CTR_RX</name>
              <bitOffset>15</bitOffset>
              <bitWidth>1</bitWidth>
            </field>
          </fields>
        </register>
        <register>
          <name>EP4R</name>
          <addressOffset>0x10</addressOffset>
          <size>0x10</size>
          <fields>
            <field>
              <name>EA</name>
              <bitOffset>0</bitOffset>
              <bitWidth>4</bitWidth>
            </field>
            <field>
              <name>STAT_TX</name>
              <bitOffset>4</bitOffset>
              <bitWidth>2</bitWidth>
            </field>
            <field>
              <name>DTOG_TX</name>
              <bitOffset>6</bitOffset>
              <bitWidth>1</bitWidth>
            </field>
            <field>
              <name>CTR_TX</name>
              <bitOffset>7</bitOffset>
              <bitWidth>1</bitWidth>
            </field>
            <field>
              <name>EP_KIND</name>
              <bitOffset>8</bitOffset>
              <bitWidth>1</bitWidth>
            </field>
            <field>
              <name>EP_TYPE</name>
              <bitOffset>9</bitOffset>
              <bitWidth>2</bitWidth>
            </field>
            <field>
              <name>SETUP</name>
              <bitOffset>11</bitOffset>
              <bitWidth>1</bitWidth>
            </field>
            <field>
              <name>STAT_RX</name>
              <bitOffset>12</bitOffset>
              <bitWidth>2</bitWidth>
            </field>
            <field>
              <name>DTOG_RX</name>
              <bitOffset>14</bitOffset>
              <bitWidth>1</bitWidth>
            </field>
            <field>
              <name>CTR_RX</name>
              <bitOffset>15</bitOffset>
              <bitWidth>1</bitWidth>
            </field>
          </fields>
        </register>
        <register>
          <name>EP5R</name>
          <addressOffset>0x14</addressOffset>
          <size>0x10</size>
          <fields>
            <field>
              <name>EA</name>
              <bitOffset>0</bitOffset>
              <bitWidth>4</bitWidth>
            </field>
            <field>
              <name>STAT_TX</name>
              <bitOffset>4</bitOffset>
              <bitWidth>2</bitWidth>
            </field>
            <field>
              <name>DTOG_TX</name>
              <bitOffset>6</bitOffset>
              <bitWidth>1</bitWidth>
            </field>
            <field>
              <name>CTR_TX</name>
              <bitOffset>7</bitOffset>
              <bitWidth>1</bitWidth>
            </field>
            <field>
              <name>EP_KIND</name>
              <bitOffset>8</bitOffset>
              <bitWidth>1</bitWidth>
            </field>
            <field>
              <name>EP_TYPE</name>
              <bitOffset>9</bitOffset>
              <bitWidth>2</bitWidth>
            </field>
            <field>
              <name>SETUP</name>
              <bitOffset>11</bitOffset>
              <bitWidth>1</bitWidth>
            </field>
            <field>
              <name>STAT_RX</name>
              <bitOffset>12</bitOffset>
              <bitWidth>2</bitWidth>
            </field>
            <field>
              <name>DTOG_RX</name>
              <bitOffset>14</bitOffset>
              <bitWidth>1</bitWidth>
            </field>
            <field>
              <name>CTR_RX</name>
              <bitOffset>15</bitOffset>
              <bitWidth>1</bitWidth>
            </field>
          </fields>
        </register>
        <register>
          <name>EP6R</name>
          <addressOffset>0x18</addressOffset>
          <size>0x10</size>
          <fields>
            <field>
              <name>EA</name>
              <bitOffset>0</bitOffset>
              <bitWidth>4</bitWidth>
            </field>
            <field>
              <name>STAT_TX</name>
              <bitOffset>4</bitOffset>
              <bitWidth>2</bitWidth>
            </field>
            <field>
              <name>DTOG_TX</name>
              <bitOffset>6</bitOffset>
              <bitWidth>1</bitWidth>
            </field>
            <field>
              <name>CTR_TX</name>
              <bitOffset>7</bitOffset>
              <bitWidth>1</bitWidth>
            </field>
            <field>
              <name>EP_KIND</name>
              <bitOffset>8</bitOffset>
              <bitWidth>1</bitWidth>
            </field>
            <field>
              <name>EP_TYPE</name>
              <bitOffset>9</bitOffset>
              <bitWidth>2</bitWidth>
            </field>
            <field>
              <name>SETUP</name>
              <bitOffset>11</bitOffset>
              <bitWidth>1</bitWidth>
            </field>
            <field>
              <name>STAT_RX</name>
              <bitOffset>12</bitOffset>
              <bitWidth>2</bitWidth>
            </field>
            <field>
              <name>DTOG_RX</name>
              <bitOffset>14</bitOffset>
              <bitWidth>1</bitWidth>
            </field>
            <field>
              <name>CTR_RX</name>
              <bitOffset>15</bitOffset>
              <bitWidth>1</bitWidth>
            </field>
          </fields>
        </register>
        <register>
          <name>EP7R</name>
          <addressOffset>0x1c</addressOffset>
          <size>0x10</size>
          <fields>
            <field>
              <name>EA</name>
              <bitOffset>0</bitOffset>
              <bitWidth>4</bitWidth>
            </field>
            <field>
              <name>STAT_TX</name>
              <bitOffset>4</bitOffset>
              <bitWidth>2</bitWidth>
            </field>
            <field>
              <name>DTOG_TX</name>
              <bitOffset>6</bitOffset>
              <bitWidth>1</bitWidth>
            </field>
            <field>
              <name>CTR_TX</name>
              <bitOffset>7</bitOffset>
              <bitWidth>1</bitWidth>
            </field>
            <field>
              <name>EP_KIND</name>
              <bitOffset>8</bitOffset>
              <bitWidth>1</bitWidth>
            </field>
            <field>
              <name>EP_TYPE</name>
              <bitOffset>9</bitOffset>
              <bitWidth>2</bitWidth>
            </field>
            <field>
              <name>SETUP</name>
              <bitOffset>11</bitOffset>
              <bitWidth>1</bitWidth>
            </field>
            <field>
              <name>STAT_RX</name>
              <bitOffset>12</bitOffset>
              <bitWidth>2</bitWidth>
            </field>
            <field>
              <name>DTOG_RX</name>
              <bitOffset>14</bitOffset>
              <bitWidth>1</bitWidth>
            </field>
            <field>
              <name>CTR_RX</name>
              <bitOffset>15</bitOffset>
              <bitWidth>1</bitWidth>
            </field>
          </fields>
        </register>
        <register>
          <name>CNTR</name>
          <addressOffset>0x40</addressOffset>
          <size>0x10</size>
          <fields>
            <field>
              <name>FRES</name>
              <bitOffset>0</bitOffset>
              <bitWidth>1</bitWidth>
            </field>
            <field>
              <name>PDWN</name>
              <bitOffset>1</bitOffset>
              <bitWidth>1</bitWidth>
            </field>
            <field>
              <name>LPMODE</name>
              <bitOffset>2</bitOffset>
              <bitWidth>1</bitWidth>
            </field>
            <field>
              <name>FSUSP</name>
              <bitOffset>3</bitOffset>
              <bitWidth>1</bitWidth>
            </field>
            <field>
              <name>RESUME</name>
              <bitOffset>4</bitOffset>
              <bitWidth>1</bitWidth>
            </field>
            <field>
              <name>ESOFM</name>
              <bitOffset>8</bitOffset>
              <bitWidth>1</bitWidth>
            </field>
            <field>
              <name>SOFM</name>
              <bitOffset>9</bitOffset>
              <bitWidth>1</bitWidth>
            </field>
            <field>
              <name>RESETM</name>
              <bitOffset>10</bitOffset>
              <bitWidth>1</bitWidth>
            </field>
            <field>
              <name>SUSPM</name>
              <bitOffset>11</bitOffset>
              <bitWidth>1</bitWidth>
            </field>
            <field>
              <name>WKUPM</name>
              <bitOffset>12</bitOffset>
              <bitWidth>1</bitWidth>
            </field>
            <field>
              <name>ERRM</name>
              <bitOffset>13</bitOffset>
              <bitWidth>1</bitWidth>
            </field>
            <field>
              <name>PMAOVRM</name>
              <bitOffset>14</bitOffset>
              <bitWidth>1</bitWidth>
            </field>
            <field>
              <name>CTRM</name>
              <bitOffset>15</bitOffset>
              <bitWidth>1</bitWidth>
            </field>
          </fields>
        </register>
        <register>
          <name>ISTR</name>
          <addressOffset>0x44</addressOffset>
          <size>0x10</size>
          <fields>
            <field>
              <name>EP_ID</name>
              <bitOffset>0</bitOffset>
              <bitWidth>4</bitWidth>
            </field>
            <field>
              <name>DIR</name>
              <bitOffset>4</bitOffset>
              <bitWidth>1</bitWidth>
            </field>
            <field>
              <name>ESOF</name>
              <bitOffset>8</bitOffset>
              <bitWidth>1</bitWidth>
            </field>
            <field>
              <name>SOF</name>
              <bitOffset>9</bitOffset>
              <bitWidth>1</bitWidth>
            </field>
            <field>
              <name>RESET</name>
              <bitOffset>10</bitOffset>
              <bitWidth>1</bitWidth>
            </field>
            <field>
              <name>SUSP</name>
              <bitOffset>11</bitOffset>
              <bitWidth>1</bitWidth>
            </field>
            <field>
              <name>WKUP</name>
              <bitOffset>12</bitOffset>
              <bitWidth>1</bitWidth>
            </field>
            <field>
              <name>ERR</name>
              <bitOffset>13</bitOffset>
              <bitWidth>1</bitWidth>
            </field>
            <field>
              <name>PMAOVR</name>
              <bitOffset>14</bitOffset>
              <bitWidth>1</bitWidth>
            </field>
            <field>
              <name>CTR</name>
              <bitOffset>15</bitOffset>
              <bitWidth>1</bitWidth>
            </field>
          </fields>
        </register>
        <register>
          <name>FNR</name>
          <addressOffset>0x48</addressOffset>
          <size>0x10</size>
          <fields>
            <field>
              <name>FN</name>
              <bitOffset>0</bitOffset>
              <bitWidth>11</bitWidth>
            </field>
            <field>
              <name>LSOF</name>
              <bitOffset>11</bitOffset>
              <bitWidth>2</bitWidth>
            </field>
            <field>
              <name>LCK</name>
              <bitOffset>13</bitOffset>
              <bitWidth>1</bitWidth>
            </field>
            <field>
              <name>RXDM</name>
              <bitOffset>14</bitOffset>
              <bitWidth>1</bitWidth>
            </field>
            <field>
              <name>RXDP</name>
              <bitOffset>15</bitOffset>
              <bitWidth>1</bitWidth>
            </field>
          </fields>
        </register>
        <register>
          <name>DADDR</name>
          <addressOffset>0x4c</addressOffset>
          <size>0x10</size>
          <fields>
            <field>
              <name>ADD0</name>
              <bitOffset>0</bitOffset>
              <bitWidth>1</bitWidth>
            </field>
            <field>
              <name>ADD1</name>
              <bitOffset>1</bitOffset>
              <bitWidth>1</bitWidth>
            </field>
            <field>
              <name>ADD2</name>
              <bitOffset>2</bitOffset>
              <bitWidth>1</bitWidth>
            </field>
            <field>
              <name>ADD3</name>
              <bitOffset>3</bitOffset>
              <bitWidth>1</bitWidth>
            </field>
            <field>
              <name>ADD4</name>
              <bitOffset>4</bitOffset>
              <bitWidth>1</bitWidth>
            </field>
            <field>
              <name>ADD5</name>
              <bitOffset>5</bitOffset>
              <bitWidth>1</bitWidth>
            </field>
            <field>
              <name>ADD6</name>
              <bitOffset>6</bitOffset>
              <bitWidth>1</bitWidth>
            </field>
            <field>
              <name>EF</name>
              <bitOffset>7</bitOffset>
              <bitWidth>1</bitWidth>
            </field>
          </fields>
        </register>
        <register>
          <name>BTABLE</name>
          <addressOffset>0x50</addressOffset>
          <size>0x10</size>
          <fields>
            <field>
              <name>BTABLE</name>
              <bitOffset>3</bitOffset>
              <bitWidth>13</bitWidth>
            </field>
          </fields>
        </register>
      </registers>
    </peripheral>
    <peripheral>
      <name>PWR</name>
      <baseAddress>0x40007000</baseAddress>
      <registers>
        <register>
          <name>CR</name>
          <addressOffset>0x0</addressOffset>
          <size>0x20</size>
          <fields>
            <field>
              <name>LPSDSR</name>
              <bitOffset>0</bitOffset>
              <bitWidth>1</bitWidth>
            </field>
            <field>
              <name>PDDS</name>
              <bitOffset>1</bitOffset>
              <bitWidth>1</bitWidth>
            </field>
            <field>
              <name>CWUF</name>
              <bitOffset>2</bitOffset>
              <bitWidth>1</bitWidth>
            </field>
            <field>
              <name>CSBF</name>
              <bitOffset>3</bitOffset>
              <bitWidth>1</bitWidth>
            </field>
            <field>
              <name>PVDE</name>
              <bitOffset>4</bitOffset>
              <bitWidth>1</bitWidth>
            </field>
            <field>
              <name>PLS</name>
              <bitOffset>5</bitOffset>
              <bitWidth>3</bitWidth>
            </field>
            <field>
              <name>DBP</name>
              <bitOffset>8</bitOffset>
              <bitWidth>1</bitWidth>
            </field>
            <field>
              <name>ULP</name>
              <bitOffset>9</bitOffset>
              <bitWidth>1</bitWidth>
            </field>
            <field>
              <name>FWU</name>
              <bitOffset>10</bitOffset>
              <bitWidth>1</bitWidth>
            </field>
            <field>
              <name>VOS</name>
              <bitOffset>11</bitOffset>
              <bitWidth>2</bitWidth>
            </field>
            <field>
              <name>LPRUN</name>
              <bitOffset>14</bitOffset>
              <bitWidth>1</bitWidth>
            </field>
          </fields>
        </register>
        <register>
          <name>CSR</name>
          <addressOffset>0x4</addressOffset>
          <size>0x20</size>
          <fields>
            <field>
              <name>WUF</name>
              <bitOffset>0</bitOffset>
              <bitWidth>1</bitWidth>
            </field>
            <field>
              <name>SBF</name>
              <bitOffset>1</bitOffset>
              <bitWidth>1</bitWidth>
            </field>
            <field>
              <name>PVDO</name>
              <bitOffset>2</bitOffset>
              <bitWidth>1</bitWidth>
            </field>
            <field>
              <name>VREFINTRDYF</name>
              <bitOffset>3</bitOffset>
              <bitWidth>1</bitWidth>
            </field>
            <field>
              <name>VOSF</name>
              <bitOffset>4</bitOffset>
              <bitWidth>1</bitWidth>
            </field>
            <field>
              <name>REGLPF</name>
              <bitOffset>5</bitOffset>
              <bitWidth>1</bitWidth>
            </field>
            <field>
              <name>EWUP1</name>
              <bitOffset>8</bitOffset>
              <bitWidth>1</bitWidth>
            </field>
            <field>
              <name>EWUP2</name>
              <bitOffset>9</bitOffset>
              <bitWidth>1</bitWidth>
            </field>
            <field>
              <name>EWUP3</name>
              <bitOffset>10</bitOffset>
              <bitWidth>1</bitWidth>
            </field>
          </fields>
        </register>
      </registers>
    </peripheral>
    <peripheral>
      <name>DAC1</name>
      <baseAddress>0x40007400</baseAddress>
      <registers>
        <register>
          <name>CR</name>
          <addressOffset>0x0</addressOffset>
          <size>0x20</size>
          <fields>
            <field>
              <name>EN1</name>
              <bitOffset>0</bitOffset>
              <bitWidth>1</bitWidth>
            </field>
            <field>
              <name>BOFF1</name>
              <bitOffset>1</bitOffset>
              <bitWidth>1</bitWidth>
            </field>
            <field>
              <name>TEN1</name>
              <bitOffset>2</bitOffset>
              <bitWidth>1</bitWidth>
            </field>
            <field>
              <name>TSEL1</name>
              <bitOffset>3</bitOffset>
              <bitWidth>3</bitWidth>
            </field>
            <field>
              <name>WAVE1</name>
              <bitOffset>6</bitOffset>
              <bitWidth>2</bitWidth>
            </field>
            <field>
              <name>MAMP1</name>
              <bitOffset>8</bitOffset>
              <bitWidth>4</bitWidth>
            </field>
            <field>
              <name>DMAEN1</name>
              <bitOffset>12</bitOffset>
              <bitWidth>1</bitWidth>
            </field>
            <field>
              <name>DMAUDRIE1</name>
              <bitOffset>13</bitOffset>
              <bitWidth>1</bitWidth>
            </field>
            <field>
              <name>EN2</name>
              <bitOffset>16</bitOffset>
              <bitWidth>1</bitWidth>
            </field>
            <field>
              <name>BOFF2</name>
              <bitOffset>17</bitOffset>
              <bitWidth>1</bitWidth>
            </field>
            <field>
              <name>TEN2</name>
              <bitOffset>18</bitOffset>
              <bitWidth>1</bitWidth>
            </field>
            <field>
              <name>TSEL2</name>
              <bitOffset>19</bitOffset>
              <bitWidth>3</bitWidth>
            </field>
            <field>
              <name>WAVE2</name>
              <bitOffset>22</bitOffset>
              <bitWidth>2</bitWidth>
            </field>
            <field>
              <name>MAMP2</name>
              <bitOffset>24</bitOffset>
              <bitWidth>4</bitWidth>
            </field>
            <field>
              <name>DMAEN2</name>
              <bitOffset>28</bitOffset>
              <bitWidth>1</bitWidth>
            </field>
            <field>
              <name>DMAUDRIE2</name>
              <bitOffset>29</bitOffset>
              <bitWidth>1</bitWidth>
            </field>
          </fields>
        </register>
        <register>
          <name>SWTRIGR</name>
          <addressOffset>0x4</addressOffset>
          <size>0x20</size>
          <fields>
            <field>
              <name>SWTRIG1</name>
              <bitOffset>0</bitOffset>
              <bitWidth>1</bitWidth>
            </field>
            <field>
              <name>SWTRIG2</name>
              <bitOffset>1</bitOffset>
              <bitWidth>1</bitWidth>
            </field>
          </fields>
        </register>
        <register>
          <name>DHR12R1</name>
          <addressOffset>0x8</addressOffset>
          <size>0x20</size>
          <fields>
            <field>
              <name>DACC1DHR</name>
              <bitOffset>0</bitOffset>
              <bitWidth>12</bitWidth>
            </field>
          </fields>
        </register>
        <register>
          <name>DHR12L1</name>
          <addressOffset>0xc</addressOffset>
          <size>0x20</size>
          <fields>
            <field>
              <name>DACC1DHR</name>
              <bitOffset>4</bitOffset>
              <bitWidth>12</bitWidth>
            </field>
          </fields>
        </register>
        <register>
          <name>DHR8R1</name>
          <addressOffset>0x10</addressOffset>
          <size>0x20</size>
          <fields>
            <field>
              <name>DACC1DHR</name>
              <bitOffset>0</bitOffset>
              <bitWidth>8</bitWidth>
            </field>
          </fields>
        </register>
        <register>
          <name>DHR12R2</name>
          <addressOffset>0x14</addressOffset>
          <size>0x20</size>
          <fields>
            <field>
              <name>DACC2DHR</name>
              <bitOffset>0</bitOffset>
              <bitWidth>12</bitWidth>
            </field>
          </fields>
        </register>
        <register>
          <name>DHR12L2</name>
          <addressOffset>0x18</addressOffset>
          <size>0x20</size>
          <fields>
            <field>
              <name>DACC2DHR</name>
              <bitOffset>4</bitOffset>
              <bitWidth>12</bitWidth>
            </field>
          </fields>
        </register>
        <register>
          <name>DHR8R2</name>
          <addressOffset>0x1c</addressOffset>
          <size>0x20</size>
          <fields>
            <field>
              <name>DACC2DHR</name>
              <bitOffset>0</bitOffset>
              <bitWidth>8</bitWidth>
            </field>
          </fields>
        </register>
        <register>
          <name>DHR12RD</name>
          <addressOffset>0x20</addressOffset>
          <size>0x20</size>
          <fields>
            <field>
              <name>DACC1DHR</name>
              <bitOffset>0</bitOffset>
              <bitWidth>12</bitWidth>
            </field>
            <field>
              <name>DACC2DHR</name>
              <bitOffset>16</bitOffset>
              <bitWidth>12</bitWidth>
            </field>
          </fields>
        </register>
        <register>
          <name>DHR12LD</name>
          <addressOffset>0x24</addressOffset>
          <size>0x20</size>
          <fields>
            <field>
              <name>DACC1DHR</name>
              <bitOffset>4</bitOffset>
              <bitWidth>12</bitWidth>
            </field>
            <field>
              <name>DACC2DHR</name>
              <bitOffset>20</bitOffset>
              <bitWidth>12</bitWidth>
            </field>
          </fields>
        </register>
        <register>
          <name>DHR8RD</name>
          <addressOffset>0x28</addressOffset>
          <size>0x20</size>
          <fields>
            <field>
              <name>DACC1DHR</name>
              <bitOffset>0</bitOffset>
              <bitWidth>8</bitWidth>
            </field>
            <field>
              <name>DACC2DHR</name>
              <bitOffset>8</bitOffset>
              <bitWidth>8</bitWidth>
            </field>
          </fields>
        </register>
        <register>
          <name>DOR1</name>
          <addressOffset>0x2c</addressOffset>
          <size>0x20</size>
          <fields>
            <field>
              <name>DACC1DOR</name>
              <bitOffset>0</bitOffset>
              <bitWidth>12</bitWidth>
            </field>
          </fields>
        </register>
        <register>
          <name>DOR2</name>
          <addressOffset>0x30</addressOffset>
          <size>0x20</size>
          <fields>
            <field>
              <name>DACC2DOR</name>
              <bitOffset>0</bitOffset>
              <bitWidth>12</bitWidth>
            </field>
          </fields>
        </register>
        <register>
          <name>SR</name>
          <addressOffset>0x34</addressOffset>
          <size>0x20</size>
          <fields>
            <field>
              <name>DMAUDR1</name>
              <bitOffset>13</bitOffset>
              <bitWidth>1</bitWidth>
            </field>
            <field>
              <name>DMAUDR2</name>
              <bitOffset>29</bitOffset>
              <bitWidth>1</bitWidth>
            </field>
          </fields>
        </register>
      </registers>
    </peripheral>
    <peripheral>
      <name>COMP</name>
      <baseAddress>0x40007c00</baseAddress>
      <registers>
        <register>
          <name>CSR</name>
          <addressOffset>0x0</addressOffset>
          <size>0x20</size>
          <fields>
            <field>
              <name>CMP1EN</name>
              <bitOffset>4</bitOffset>
              <bitWidth>1</bitWidth>
            </field>
            <field>
              <name>CMP1OUT</name>
              <bitOffset>7</bitOffset>
              <bitWidth>1</bitWidth>
            </field>
            <field>
              <name>SPEED</name>
              <bitOffset>12</bitOffset>
              <bitWidth>1</bitWidth>
            </field>
            <field>
              <name>CMP2OUT</name>
              <bitOffset>13</bitOffset>
              <bitWidth>1</bitWidth>
            </field>
            <field>
              <name>VREFOUTEN</name>
              <bitOffset>16</bitOffset>
              <bitWidth>1</bitWidth>
            </field>
            <field>
              <name>WNDWE</name>
              <bitOffset>17</bitOffset>
              <bitWidth>1</bitWidth>
            </field>
            <field>
              <name>INSEL</name>
              <bitOffset>18</bitOffset>
              <bitWidth>3</bitWidth>
            </field>
            <field>
              <name>OUTSEL</name>
              <bitOffset>21</bitOffset>
              <bitWidth>3</bitWidth>
            </field>
          </fields>
        </register>
      </registers>
    </peripheral>
    <peripheral>
      <name>COMP1</name>
      <baseAddress>0x40007c00</baseAddress>
      <registers>
        <register>
          <name>CSR</name>
          <addressOffset>0x0</addressOffset>
          <size>0x20</size>
          <fields>
            <field>
              <name>CMP1EN</name>
              <bitOffset>4</bitOffset>
              <bitWidth>1</bitWidth>
            </field>
            <field>
              <name>CMP1OUT</name>
              <bitOffset>7</bitOffset>
              <bitWidth>1</bitWidth>
            </field>
            <field>
              <name>SPEED</name>
              <bitOffset>12</bitOffset>
              <bitWidth>1</bitWidth>
            </field>
            <field>
              <name>CMP2OUT</name>
              <bitOffset>13</bitOffset>
              <bitWidth>1</bitWidth>
            </field>
            <field>
              <name>VREFOUTEN</name>
              <bitOffset>16</bitOffset>
              <bitWidth>1</bitWidth>
            </field>
            <field>
              <name>WNDWE</name>
              <bitOffset>17</bitOffset>
              <bitWidth>1</bitWidth>
            </field>
            <field>
              <name>INSEL</name>
              <bitOffset>18</bitOffset>
              <bitWidth>3</bitWidth>
            </field>
            <field>
              <name>OUTSEL</name>
              <bitOffset>21</bitOffset>
              <bitWidth>3</bitWidth>
            </field>
          </fields>
        </register>
      </registers>
    </peripheral>
    <peripheral>
      <name>COMP12_COMMON</name>
      <baseAddress>0x40007c00</baseAddress>
      <registers>
        <register>
          <name>CSR</name>
          <addressOffset>0x0</addressOffset>
          <size>0x20</size>
          <fields>
            <field>
              <name>CMP1EN</name>
              <bitOffset>4</bitOffset>
              <bitWidth>1</bitWidth>
            </field>
            <field>
              <name>CMP1OUT</name>
              <bitOffset>7</bitOffset>
              <bitWidth>1</bitWidth>
            </field>
            <field>
              <name>SPEED</name>
              <bitOffset>12</bitOffset>
              <bitWidth>1</bitWidth>
            </field>
            <field>
              <name>CMP2OUT</name>
              <bitOffset>13</bitOffset>
              <bitWidth>1</bitWidth>
            </field>
            <field>
              <name>VREFOUTEN</name>
              <bitOffset>16</bitOffset>
              <bitWidth>1</bitWidth>
            </field>
            <field>
              <name>WNDWE</name>
              <bitOffset>17</bitOffset>
              <bitWidth>1</bitWidth>
            </field>
            <field>
              <name>INSEL</name>
              <bitOffset>18</bitOffset>
              <bitWidth>3</bitWidth>
            </field>
            <field>
              <name>OUTSEL</name>
              <bitOffset>21</bitOffset>
              <bitWidth>3</bitWidth>
            </field>
          </fields>
        </register>
      </registers>
    </peripheral>
    <peripheral>
      <name>COMP2</name>
      <baseAddress>0x40007c01</baseAddress>
      <registers>
        <register>
          <name>CSR</name>
          <addressOffset>0x0</addressOffset>
          <size>0x20</size>
          <fields>
            <field>
              <name>CMP1EN</name>
              <bitOffset>4</bitOffset>
              <bitWidth>1</bitWidth>
            </field>
            <field>
              <name>CMP1OUT</name>
              <bitOffset>7</bitOffset>
              <bitWidth>1</bitWidth>
            </field>
            <field>
              <name>SPEED</name>
              <bitOffset>12</bitOffset>
              <bitWidth>1</bitWidth>
            </field>
            <field>
              <name>CMP2OUT</name>
              <bitOffset>13</bitOffset>
              <bitWidth>1</bitWidth>
            </field>
            <field>
              <name>VREFOUTEN</name>
              <bitOffset>16</bitOffset>
              <bitWidth>1</bitWidth>
            </field>
            <field>
              <name>WNDWE</name>
              <bitOffset>17</bitOffset>
              <bitWidth>1</bitWidth>
            </field>
            <field>
              <name>INSEL</name>
              <bitOffset>18</bitOffset>
              <bitWidth>3</bitWidth>
            </field>
            <field>
              <name>OUTSEL</name>
              <bitOffset>21</bitOffset>
              <bitWidth>3</bitWidth>
            </field>
          </fields>
        </register>
      </registers>
    </peripheral>
    <peripheral>
      <name>RI</name>
      <baseAddress>0x40007c04</baseAddress>
      <registers>
        <register>
          <name>ICR</name>
          <addressOffset>0x0</addressOffset>
          <size>0x20</size>
          <fields>
            <field>
              <name>IC1OS</name>
              <bitOffset>0</bitOffset>
              <bitWidth>4</bitWidth>
            </field>
            <field>
              <name>IC2OS</name>
              <bitOffset>4</bitOffset>
              <bitWidth>4</bitWidth>
            </field>
            <field>
              <name>IC3OS</name>
              <bitOffset>8</bitOffset>
              <bitWidth>4</bitWidth>
            </field>
            <field>
              <name>IC4OS</name>
              <bitOffset>12</bitOffset>
              <bitWidth>4</bitWidth>
            </field>
            <field>
              <name>TIM</name>
              <bitOffset>16</bitOffset>
              <bitWidth>2</bitWidth>
            </field>
            <field>
              <name>IC1</name>
              <bitOffset>18</bitOffset>
              <bitWidth>1</bitWidth>
            </field>
            <field>
              <name>IC2</name>
              <bitOffset>19</bitOffset>
              <bitWidth>1</bitWidth>
            </field>
            <field>
              <name>IC3</name>
              <bitOffset>20</bitOffset>
              <bitWidth>1</bitWidth>
            </field>
            <field>
              <name>IC4</name>
              <bitOffset>21</bitOffset>
              <bitWidth>1</bitWidth>
            </field>
          </fields>
        </register>
        <register>
          <name>ASCR1</name>
          <addressOffset>0x4</addressOffset>
          <size>0x20</size>
          <fields>
            <field>
              <name>CH</name>
              <bitOffset>0</bitOffset>
              <bitWidth>26</bitWidth>
            </field>
            <field>
              <name>VCOMP</name>
              <bitOffset>26</bitOffset>
              <bitWidth>1</bitWidth>
            </field>
            <field>
              <name>SCM</name>
              <bitOffset>31</bitOffset>
              <bitWidth>1</bitWidth>
            </field>
          </fields>
        </register>
        <register>
          <name>ASCR2</name>
          <addressOffset>0x8</addressOffset>
          <size>0x20</size>
          <fields>
            <field>
              <name>GR6</name>
              <bitOffset>4</bitOffset>
              <bitWidth>2</bitWidth>
            </field>
          </fields>
        </register>
        <register>
          <name>HYSCR1</name>
          <addressOffset>0xc</addressOffset>
          <size>0x20</size>
          <fields>
            <field>
              <name>PA</name>
              <bitOffset>0</bitOffset>
              <bitWidth>16</bitWidth>
            </field>
            <field>
              <name>PB</name>
              <bitOffset>16</bitOffset>
              <bitWidth>16</bitWidth>
            </field>
          </fields>
        </register>
        <register>
          <name>HYSCR2</name>
          <addressOffset>0x10</addressOffset>
          <size>0x20</size>
          <fields>
            <field>
              <name>PC</name>
              <bitOffset>0</bitOffset>
              <bitWidth>16</bitWidth>
            </field>
            <field>
              <name>PD</name>
              <bitOffset>16</bitOffset>
              <bitWidth>16</bitWidth>
            </field>
          </fields>
        </register>
        <register>
          <name>HYSCR3</name>
          <addressOffset>0x14</addressOffset>
          <size>0x20</size>
          <fields>
            <field>
              <name>PE</name>
              <bitOffset>0</bitOffset>
              <bitWidth>16</bitWidth>
            </field>
          </fields>
        </register>
      </registers>
    </peripheral>
    <peripheral>
      <name>SYSCFG</name>
      <baseAddress>0x40010000</baseAddress>
      <registers>
        <register>
          <name>MEMRMP</name>
          <addressOffset>0x0</addressOffset>
          <size>0x20</size>
          <fields>
            <field>
              <name>MEM_MODE</name>
              <bitOffset>0</bitOffset>
              <bitWidth>2</bitWidth>
            </field>
            <field>
              <name>BOOT_MODE</name>
              <bitOffset>8</bitOffset>
              <bitWidth>2</bitWidth>
            </field>
          </fields>
        </register>
        <register>
          <name>PMC</name>
          <addressOffset>0x4</addressOffset>
          <size>0x20</size>
          <fields>
            <field>
              <name>USB_PU</name>
              <bitOffset>0</bitOffset>
              <bitWidth>1</bitWidth>
            </field>
            <field>
              <name>LCD_CAPA</name>
              <bitOffset>1</bitOffset>
              <bitWidth>5</bitWidth>
            </field>
          </fields>
        </register>
        <register>
          <name>EXTICR.0</name>
          <addressOffset>0x8</addressOffset>
          <size>0x20</size>
          <fields>
            <field>
              <name>EXTI0</name>
              <bitOffset>0</bitOffset>
              <bitWidth>4</bitWidth>
            </field>
            <field>
              <name>EXTI1</name>
              <bitOffset>4</bitOffset>
              <bitWidth>4</bitWidth>
            </field>
            <field>
              <name>EXTI2</name>
              <bitOffset>8</bitOffset>
              <bitWidth>4</bitWidth>
            </field>
            <field>
              <name>EXTI3</name>
              <bitOffset>12</bitOffset>
              <bitWidth>4</bitWidth>
            </field>
          </fields>
        </register>
        <register>
          <name>EXTICR.1</name>
          <addressOffset>0xc</addressOffset>
          <size>0x20</size>
          <fields>
            <field>
              <name>EXTI4</name>
              <bitOffset>0</bitOffset>
              <bitWidth>4</bitWidth>
            </field>
            <field>
              <name>EXTI5</name>
              <bitOffset>4</bitOffset>
              <bitWidth>4</bitWidth>
            </field>
            <field>
              <name>EXTI6</name>
              <bitOffset>8</bitOffset>
              <bitWidth>4</bitWidth>
            </field>
            <field>
              <name>EXTI7</name>
              <bitOffset>12</bitOffset>
              <bitWidth>4</bitWidth>
            </field>
          </fields>
        </register>
        <register>
          <name>EXTICR.2</name>
          <addressOffset>0x10</addressOffset>
          <size>0x20</size>
          <fields>
            <field>
              <name>EXTI8</name>
              <bitOffset>0</bitOffset>
              <bitWidth>4</bitWidth>
            </field>
            <field>
              <name>EXTI9</name>
              <bitOffset>4</bitOffset>
              <bitWidth>4</bitWidth>
            </field>
            <field>
              <name>EXTI10</name>
              <bitOffset>8</bitOffset>
              <bitWidth>4</bitWidth>
            </field>
            <field>
              <name>EXTI11</name>
              <bitOffset>12</bitOffset>
              <bitWidth>4</bitWidth>
            </field>
          </fields>
        </register>
        <register>
          <name>EXTICR.3</name>
          <addressOffset>0x14</addressOffset>
          <size>0x20</size>
          <fields>
            <field>
              <name>EXTI12</name>
              <bitOffset>0</bitOffset>
              <bitWidth>4</bitWidth>
            </field>
            <field>
              <name>EXTI13</name>
              <bitOffset>4</bitOffset>
              <bitWidth>4</bitWidth>
            </field>
            <field>
              <name>EXTI14</name>
              <bitOffset>8</bitOffset>
              <bitWidth>4</bitWidth>
            </field>
            <field>
              <name>EXTI15</name>
              <bitOffset>12</bitOffset>
              <bitWidth>4</bitWidth>
            </field>
          </fields>
        </register>
      </registers>
    </peripheral>
    <peripheral>
      <name>EXTI</name>
      <baseAddress>0x40010400</baseAddress>
      <registers>
        <register>
          <name>IMR</name>
          <addressOffset>0x0</addressOffset>
          <size>0x20</size>
          <fields>
            <field>
              <name>MR0</name>
              <bitOffset>0</bitOffset>
              <bitWidth>1</bitWidth>
            </field>
            <field>
              <name>MR1</name>
              <bitOffset>1</bitOffset>
              <bitWidth>1</bitWidth>
            </field>
            <field>
              <name>MR2</name>
              <bitOffset>2</bitOffset>
              <bitWidth>1</bitWidth>
            </field>
            <field>
              <name>MR3</name>
              <bitOffset>3</bitOffset>
              <bitWidth>1</bitWidth>
            </field>
            <field>
              <name>MR4</name>
              <bitOffset>4</bitOffset>
              <bitWidth>1</bitWidth>
            </field>
            <field>
              <name>MR5</name>
              <bitOffset>5</bitOffset>
              <bitWidth>1</bitWidth>
            </field>
            <field>
              <name>MR6</name>
              <bitOffset>6</bitOffset>
              <bitWidth>1</bitWidth>
            </field>
            <field>
              <name>MR7</name>
              <bitOffset>7</bitOffset>
              <bitWidth>1</bitWidth>
            </field>
            <field>
              <name>MR8</name>
              <bitOffset>8</bitOffset>
              <bitWidth>1</bitWidth>
            </field>
            <field>
              <name>MR9</name>
              <bitOffset>9</bitOffset>
              <bitWidth>1</bitWidth>
            </field>
            <field>
              <name>MR10</name>
              <bitOffset>10</bitOffset>
              <bitWidth>1</bitWidth>
            </field>
            <field>
              <name>MR11</name>
              <bitOffset>11</bitOffset>
              <bitWidth>1</bitWidth>
            </field>
            <field>
              <name>MR12</name>
              <bitOffset>12</bitOffset>
              <bitWidth>1</bitWidth>
            </field>
            <field>
              <name>MR13</name>
              <bitOffset>13</bitOffset>
              <bitWidth>1</bitWidth>
            </field>
            <field>
              <name>MR14</name>
              <bitOffset>14</bitOffset>
              <bitWidth>1</bitWidth>
            </field>
            <field>
              <name>MR15</name>
              <bitOffset>15</bitOffset>
              <bitWidth>1</bitWidth>
            </field>
            <field>
              <name>MR16</name>
              <bitOffset>16</bitOffset>
              <bitWidth>1</bitWidth>
            </field>
            <field>
              <name>MR17</name>
              <bitOffset>17</bitOffset>
              <bitWidth>1</bitWidth>
            </field>
            <field>
              <name>MR18</name>
              <bitOffset>18</bitOffset>
              <bitWidth>1</bitWidth>
            </field>
            <field>
              <name>MR19</name>
              <bitOffset>19</bitOffset>
              <bitWidth>1</bitWidth>
            </field>
            <field>
              <name>MR20</name>
              <bitOffset>20</bitOffset>
              <bitWidth>1</bitWidth>
            </field>
            <field>
              <name>MR21</name>
              <bitOffset>21</bitOffset>
              <bitWidth>1</bitWidth>
            </field>
            <field>
              <name>MR22</name>
              <bitOffset>22</bitOffset>
              <bitWidth>1</bitWidth>
            </field>
          </fields>
        </register>
        <register>
          <name>EMR</name>
          <addressOffset>0x4</addressOffset>
          <size>0x20</size>
          <fields>
            <field>
              <name>MR0</name>
              <bitOffset>0</bitOffset>
              <bitWidth>1</bitWidth>
            </field>
            <field>
              <name>MR1</name>
              <bitOffset>1</bitOffset>
              <bitWidth>1</bitWidth>
            </field>
            <field>
              <name>MR2</name>
              <bitOffset>2</bitOffset>
              <bitWidth>1</bitWidth>
            </field>
            <field>
              <name>MR3</name>
              <bitOffset>3</bitOffset>
              <bitWidth>1</bitWidth>
            </field>
            <field>
              <name>MR4</name>
              <bitOffset>4</bitOffset>
              <bitWidth>1</bitWidth>
            </field>
            <field>
              <name>MR5</name>
              <bitOffset>5</bitOffset>
              <bitWidth>1</bitWidth>
            </field>
            <field>
              <name>MR6</name>
              <bitOffset>6</bitOffset>
              <bitWidth>1</bitWidth>
            </field>
            <field>
              <name>MR7</name>
              <bitOffset>7</bitOffset>
              <bitWidth>1</bitWidth>
            </field>
            <field>
              <name>MR8</name>
              <bitOffset>8</bitOffset>
              <bitWidth>1</bitWidth>
            </field>
            <field>
              <name>MR9</name>
              <bitOffset>9</bitOffset>
              <bitWidth>1</bitWidth>
            </field>
            <field>
              <name>MR10</name>
              <bitOffset>10</bitOffset>
              <bitWidth>1</bitWidth>
            </field>
            <field>
              <name>MR11</name>
              <bitOffset>11</bitOffset>
              <bitWidth>1</bitWidth>
            </field>
            <field>
              <name>MR12</name>
              <bitOffset>12</bitOffset>
              <bitWidth>1</bitWidth>
            </field>
            <field>
              <name>MR13</name>
              <bitOffset>13</bitOffset>
              <bitWidth>1</bitWidth>
            </field>
            <field>
              <name>MR14</name>
              <bitOffset>14</bitOffset>
              <bitWidth>1</bitWidth>
            </field>
            <field>
              <name>MR15</name>
              <bitOffset>15</bitOffset>
              <bitWidth>1</bitWidth>
            </field>
            <field>
              <name>MR16</name>
              <bitOffset>16</bitOffset>
              <bitWidth>1</bitWidth>
            </field>
            <field>
              <name>MR17</name>
              <bitOffset>17</bitOffset>
              <bitWidth>1</bitWidth>
            </field>
            <field>
              <name>MR18</name>
              <bitOffset>18</bitOffset>
              <bitWidth>1</bitWidth>
            </field>
            <field>
              <name>MR19</name>
              <bitOffset>19</bitOffset>
              <bitWidth>1</bitWidth>
            </field>
            <field>
              <name>MR20</name>
              <bitOffset>20</bitOffset>
              <bitWidth>1</bitWidth>
            </field>
            <field>
              <name>MR21</name>
              <bitOffset>21</bitOffset>
              <bitWidth>1</bitWidth>
            </field>
            <field>
              <name>MR22</name>
              <bitOffset>22</bitOffset>
              <bitWidth>1</bitWidth>
            </field>
          </fields>
        </register>
        <register>
          <name>RTSR</name>
          <addressOffset>0x8</addressOffset>
          <size>0x20</size>
          <fields>
            <field>
              <name>TR0</name>
              <bitOffset>0</bitOffset>
              <bitWidth>1</bitWidth>
            </field>
            <field>
              <name>TR1</name>
              <bitOffset>1</bitOffset>
              <bitWidth>1</bitWidth>
            </field>
            <field>
              <name>TR2</name>
              <bitOffset>2</bitOffset>
              <bitWidth>1</bitWidth>
            </field>
            <field>
              <name>TR3</name>
              <bitOffset>3</bitOffset>
              <bitWidth>1</bitWidth>
            </field>
            <field>
              <name>TR4</name>
              <bitOffset>4</bitOffset>
              <bitWidth>1</bitWidth>
            </field>
            <field>
              <name>TR5</name>
              <bitOffset>5</bitOffset>
              <bitWidth>1</bitWidth>
            </field>
            <field>
              <name>TR6</name>
              <bitOffset>6</bitOffset>
              <bitWidth>1</bitWidth>
            </field>
            <field>
              <name>TR7</name>
              <bitOffset>7</bitOffset>
              <bitWidth>1</bitWidth>
            </field>
            <field>
              <name>TR8</name>
              <bitOffset>8</bitOffset>
              <bitWidth>1</bitWidth>
            </field>
            <field>
              <name>TR9</name>
              <bitOffset>9</bitOffset>
              <bitWidth>1</bitWidth>
            </field>
            <field>
              <name>TR10</name>
              <bitOffset>10</bitOffset>
              <bitWidth>1</bitWidth>
            </field>
            <field>
              <name>TR11</name>
              <bitOffset>11</bitOffset>
              <bitWidth>1</bitWidth>
            </field>
            <field>
              <name>TR12</name>
              <bitOffset>12</bitOffset>
              <bitWidth>1</bitWidth>
            </field>
            <field>
              <name>TR13</name>
              <bitOffset>13</bitOffset>
              <bitWidth>1</bitWidth>
            </field>
            <field>
              <name>TR14</name>
              <bitOffset>14</bitOffset>
              <bitWidth>1</bitWidth>
            </field>
            <field>
              <name>TR15</name>
              <bitOffset>15</bitOffset>
              <bitWidth>1</bitWidth>
            </field>
            <field>
              <name>TR16</name>
              <bitOffset>16</bitOffset>
              <bitWidth>1</bitWidth>
            </field>
            <field>
              <name>TR17</name>
              <bitOffset>17</bitOffset>
              <bitWidth>1</bitWidth>
            </field>
            <field>
              <name>TR18</name>
              <bitOffset>18</bitOffset>
              <bitWidth>1</bitWidth>
            </field>
            <field>
              <name>TR19</name>
              <bitOffset>19</bitOffset>
              <bitWidth>1</bitWidth>
            </field>
            <field>
              <name>TR20</name>
              <bitOffset>20</bitOffset>
              <bitWidth>1</bitWidth>
            </field>
            <field>
              <name>TR21</name>
              <bitOffset>21</bitOffset>
              <bitWidth>1</bitWidth>
            </field>
            <field>
              <name>TR22</name>
              <bitOffset>22</bitOffset>
              <bitWidth>1</bitWidth>
            </field>
          </fields>
        </register>
        <register>
          <name>FTSR</name>
          <addressOffset>0xc</addressOffset>
          <size>0x20</size>
          <fields>
            <field>
              <name>TR0</name>
              <bitOffset>0</bitOffset>
              <bitWidth>1</bitWidth>
            </field>
            <field>
              <name>TR1</name>
              <bitOffset>1</bitOffset>
              <bitWidth>1</bitWidth>
            </field>
            <field>
              <name>TR2</name>
              <bitOffset>2</bitOffset>
              <bitWidth>1</bitWidth>
            </field>
            <field>
              <name>TR3</name>
              <bitOffset>3</bitOffset>
              <bitWidth>1</bitWidth>
            </field>
            <field>
              <name>TR4</name>
              <bitOffset>4</bitOffset>
              <bitWidth>1</bitWidth>
            </field>
            <field>
              <name>TR5</name>
              <bitOffset>5</bitOffset>
              <bitWidth>1</bitWidth>
            </field>
            <field>
              <name>TR6</name>
              <bitOffset>6</bitOffset>
              <bitWidth>1</bitWidth>
            </field>
            <field>
              <name>TR7</name>
              <bitOffset>7</bitOffset>
              <bitWidth>1</bitWidth>
            </field>
            <field>
              <name>TR8</name>
              <bitOffset>8</bitOffset>
              <bitWidth>1</bitWidth>
            </field>
            <field>
              <name>TR9</name>
              <bitOffset>9</bitOffset>
              <bitWidth>1</bitWidth>
            </field>
            <field>
              <name>TR10</name>
              <bitOffset>10</bitOffset>
              <bitWidth>1</bitWidth>
            </field>
            <field>
              <name>TR11</name>
              <bitOffset>11</bitOffset>
              <bitWidth>1</bitWidth>
            </field>
            <field>
              <name>TR12</name>
              <bitOffset>12</bitOffset>
              <bitWidth>1</bitWidth>
            </field>
            <field>
              <name>TR13</name>
              <bitOffset>13</bitOffset>
              <bitWidth>1</bitWidth>
            </field>
            <field>
              <name>TR14</name>
              <bitOffset>14</bitOffset>
              <bitWidth>1</bitWidth>
            </field>
            <field>
              <name>TR15</name>
              <bitOffset>15</bitOffset>
              <bitWidth>1</bitWidth>
            </field>
            <field>
              <name>TR16</name>
              <bitOffset>16</bitOffset>
              <bitWidth>1</bitWidth>
            </field>
            <field>
              <name>TR17</name>
              <bitOffset>17</bitOffset>
              <bitWidth>1</bitWidth>
            </field>
            <field>
              <name>TR18</name>
              <bitOffset>18</bitOffset>
              <bitWidth>1</bitWidth>
            </field>
            <field>
              <name>TR19</name>
              <bitOffset>19</bitOffset>
              <bitWidth>1</bitWidth>
            </field>
            <field>
              <name>TR20</name>
              <bitOffset>20</bitOffset>
              <bitWidth>1</bitWidth>
            </field>
            <field>
              <name>TR21</name>
              <bitOffset>21</bitOffset>
              <bitWidth>1</bitWidth>
            </field>
            <field>
              <name>TR22</name>
              <bitOffset>22</bitOffset>
              <bitWidth>1</bitWidth>
            </field>
          </fields>
        </register>
        <register>
          <name>SWIER</name>
          <addressOffset>0x10</addressOffset>
          <size>0x20</size>
          <fields>
            <field>
              <name>SWIER0</name>
              <bitOffset>0</bitOffset>
              <bitWidth>1</bitWidth>
            </field>
            <field>
              <name>SWIER1</name>
              <bitOffset>1</bitOffset>
              <bitWidth>1</bitWidth>
            </field>
            <field>
              <name>SWIER2</name>
              <bitOffset>2</bitOffset>
              <bitWidth>1</bitWidth>
            </field>
            <field>
              <name>SWIER3</name>
              <bitOffset>3</bitOffset>
              <bitWidth>1</bitWidth>
            </field>
            <field>
              <name>SWIER4</name>
              <bitOffset>4</bitOffset>
              <bitWidth>1</bitWidth>
            </field>
            <field>
              <name>SWIER5</name>
              <bitOffset>5</bitOffset>
              <bitWidth>1</bitWidth>
            </field>
            <field>
              <name>SWIER6</name>
              <bitOffset>6</bitOffset>
              <bitWidth>1</bitWidth>
            </field>
            <field>
              <name>SWIER7</name>
              <bitOffset>7</bitOffset>
              <bitWidth>1</bitWidth>
            </field>
            <field>
              <name>SWIER8</name>
              <bitOffset>8</bitOffset>
              <bitWidth>1</bitWidth>
            </field>
            <field>
              <name>SWIER9</name>
              <bitOffset>9</bitOffset>
              <bitWidth>1</bitWidth>
            </field>
            <field>
              <name>SWIER10</name>
              <bitOffset>10</bitOffset>
              <bitWidth>1</bitWidth>
            </field>
            <field>
              <name>SWIER11</name>
              <bitOffset>11</bitOffset>
              <bitWidth>1</bitWidth>
            </field>
            <field>
              <name>SWIER12</name>
              <bitOffset>12</bitOffset>
              <bitWidth>1</bitWidth>
            </field>
            <field>
              <name>SWIER13</name>
              <bitOffset>13</bitOffset>
              <bitWidth>1</bitWidth>
            </field>
            <field>
              <name>SWIER14</name>
              <bitOffset>14</bitOffset>
              <bitWidth>1</bitWidth>
            </field>
            <field>
              <name>SWIER15</name>
              <bitOffset>15</bitOffset>
              <bitWidth>1</bitWidth>
            </field>
            <field>
              <name>SWIER16</name>
              <bitOffset>16</bitOffset>
              <bitWidth>1</bitWidth>
            </field>
            <field>
              <name>SWIER17</name>
              <bitOffset>17</bitOffset>
              <bitWidth>1</bitWidth>
            </field>
            <field>
              <name>SWIER18</name>
              <bitOffset>18</bitOffset>
              <bitWidth>1</bitWidth>
            </field>
            <field>
              <name>SWIER19</name>
              <bitOffset>19</bitOffset>
              <bitWidth>1</bitWidth>
            </field>
            <field>
              <name>SWIER20</name>
              <bitOffset>20</bitOffset>
              <bitWidth>1</bitWidth>
            </field>
            <field>
              <name>SWIER21</name>
              <bitOffset>21</bitOffset>
              <bitWidth>1</bitWidth>
            </field>
            <field>
              <name>SWIER22</name>
              <bitOffset>22</bitOffset>
              <bitWidth>1</bitWidth>
            </field>
          </fields>
        </register>
        <register>
          <name>PR</name>
          <addressOffset>0x14</addressOffset>
          <size>0x20</size>
          <fields>
            <field>
              <name>PR0</name>
              <bitOffset>0</bitOffset>
              <bitWidth>1</bitWidth>
            </field>
            <field>
              <name>PR1</name>
              <bitOffset>1</bitOffset>
              <bitWidth>1</bitWidth>
            </field>
            <field>
              <name>PR2</name>
              <bitOffset>2</bitOffset>
              <bitWidth>1</bitWidth>
            </field>
            <field>
              <name>PR3</name>
              <bitOffset>3</bitOffset>
              <bitWidth>1</bitWidth>
            </field>
            <field>
              <name>PR4</name>
              <bitOffset>4</bitOffset>
              <bitWidth>1</bitWidth>
            </field>
            <field>
              <name>PR5</name>
              <bitOffset>5</bitOffset>
              <bitWidth>1</bitWidth>
            </field>
            <field>
              <name>PR6</name>
              <bitOffset>6</bitOffset>
              <bitWidth>1</bitWidth>
            </field>
            <field>
              <name>PR7</name>
              <bitOffset>7</bitOffset>
              <bitWidth>1</bitWidth>
            </field>
            <field>
              <name>PR8</name>
              <bitOffset>8</bitOffset>
              <bitWidth>1</bitWidth>
            </field>
            <field>
              <name>PR9</name>
              <bitOffset>9</bitOffset>
              <bitWidth>1</bitWidth>
            </field>
            <field>
              <name>PR10</name>
              <bitOffset>10</bitOffset>
              <bitWidth>1</bitWidth>
            </field>
            <field>
              <name>PR11</name>
              <bitOffset>11</bitOffset>
              <bitWidth>1</bitWidth>
            </field>
            <field>
              <name>PR12</name>
              <bitOffset>12</bitOffset>
              <bitWidth>1</bitWidth>
            </field>
            <field>
              <name>PR13</name>
              <bitOffset>13</bitOffset>
              <bitWidth>1</bitWidth>
            </field>
            <field>
              <name>PR14</name>
              <bitOffset>14</bitOffset>
              <bitWidth>1</bitWidth>
            </field>
            <field>
              <name>PR15</name>
              <bitOffset>15</bitOffset>
              <bitWidth>1</bitWidth>
            </field>
            <field>
              <name>PR16</name>
              <bitOffset>16</bitOffset>
              <bitWidth>1</bitWidth>
            </field>
            <field>
              <name>PR17</name>
              <bitOffset>17</bitOffset>
              <bitWidth>1</bitWidth>
            </field>
            <field>
              <name>PR18</name>
              <bitOffset>18</bitOffset>
              <bitWidth>1</bitWidth>
            </field>
            <field>
              <name>PR19</name>
              <bitOffset>19</bitOffset>
              <bitWidth>1</bitWidth>
            </field>
            <field>
              <name>PR20</name>
              <bitOffset>20</bitOffset>
              <bitWidth>1</bitWidth>
            </field>
            <field>
              <name>PR21</name>
              <bitOffset>21</bitOffset>
              <bitWidth>1</bitWidth>
            </field>
            <field>
              <name>PR22</name>
              <bitOffset>22</bitOffset>
              <bitWidth>1</bitWidth>
            </field>
          </fields>
        </register>
      </registers>
    </peripheral>
    <peripheral>
      <name>TIM9</name>
      <baseAddress>0x40010800</baseAddress>
      <registers>
        <register>
          <name>CR1</name>
          <addressOffset>0x0</addressOffset>
          <size>0x20</size>
          <fields>
            <field>
              <name>CEN</name>
              <bitOffset>0</bitOffset>
              <bitWidth>1</bitWidth>
            </field>
            <field>
              <name>UDIS</name>
              <bitOffset>1</bitOffset>
              <bitWidth>1</bitWidth>
            </field>
            <field>
              <name>URS</name>
              <bitOffset>2</bitOffset>
              <bitWidth>1</bitWidth>
            </field>
            <field>
              <name>OPM</name>
              <bitOffset>3</bitOffset>
              <bitWidth>1</bitWidth>
            </field>
            <field>
              <name>DIR</name>
              <bitOffset>4</bitOffset>
              <bitWidth>1</bitWidth>
            </field>
            <field>
              <name>CMS</name>
              <bitOffset>5</bitOffset>
              <bitWidth>2</bitWidth>
            </field>
            <field>
              <name>ARPE</name>
              <bitOffset>7</bitOffset>
              <bitWidth>1</bitWidth>
            </field>
            <field>
              <name>CKD</name>
              <bitOffset>8</bitOffset>
              <bitWidth>2</bitWidth>
            </field>
          </fields>
        </register>
        <register>
          <name>CR2</name>
          <addressOffset>0x4</addressOffset>
          <size>0x20</size>
          <fields>
            <field>
              <name>CCDS</name>
              <bitOffset>3</bitOffset>
              <bitWidth>1</bitWidth>
            </field>
            <field>
              <name>MMS</name>
              <bitOffset>4</bitOffset>
              <bitWidth>3</bitWidth>
            </field>
            <field>
              <name>TI1S</name>
              <bitOffset>7</bitOffset>
              <bitWidth>1</bitWidth>
            </field>
          </fields>
        </register>
        <register>
          <name>SMCR</name>
          <addressOffset>0x8</addressOffset>
          <size>0x20</size>
          <fields>
            <field>
              <name>SMS</name>
              <bitOffset>0</bitOffset>
              <bitWidth>3</bitWidth>
            </field>
            <field>
              <name>OCCS</name>
              <bitOffset>3</bitOffset>
              <bitWidth>1</bitWidth>
            </field>
            <field>
              <name>TS</name>
              <bitOffset>4</bitOffset>
              <bitWidth>3</bitWidth>
            </field>
            <field>
              <name>MSM</name>
              <bitOffset>7</bitOffset>
              <bitWidth>1</bitWidth>
            </field>
            <field>
              <name>ETF</name>
              <bitOffset>8</bitOffset>
              <bitWidth>4</bitWidth>
            </field>
            <field>
              <name>ETPS</name>
              <bitOffset>12</bitOffset>
              <bitWidth>2</bitWidth>
            </field>
            <field>
              <name>ECE</name>
              <bitOffset>14</bitOffset>
              <bitWidth>1</bitWidth>
            </field>
            <field>
              <name>ETP</name>
              <bitOffset>15</bitOffset>
              <bitWidth>1</bitWidth>
            </field>
          </fields>
        </register>
        <register>
          <name>DIER</name>
          <addressOffset>0xc</addressOffset>
          <size>0x20</size>
          <fields>
            <field>
              <name>UIE</name>
              <bitOffset>0</bitOffset>
              <bitWidth>1</bitWidth>
            </field>
            <field>
              <name>CC1IE</name>
              <bitOffset>1</bitOffset>
              <bitWidth>1</bitWidth>
            </field>
            <field>
              <name>CC2IE</name>
              <bitOffset>2</bitOffset>
              <bitWidth>1</bitWidth>
            </field>
            <field>
              <name>CC3IE</name>
              <bitOffset>3</bitOffset>
              <bitWidth>1</bitWidth>
            </field>
            <field>
              <name>CC4IE</name>
              <bitOffset>4</bitOffset>
              <bitWidth>1</bitWidth>
            </field>
            <field>
              <name>TIE</name>
              <bitOffset>6</bitOffset>
              <bitWidth>1</bitWidth>
            </field>
            <field>
              <name>UDE</name>
              <bitOffset>8</bitOffset>
              <bitWidth>1</bitWidth>
            </field>
            <field>
              <name>CC1DE</name>
              <bitOffset>9</bitOffset>
              <bitWidth>1</bitWidth>
            </field>
            <field>
              <name>CC2DE</name>
              <bitOffset>10</bitOffset>
              <bitWidth>1</bitWidth>
            </field>
            <field>
              <name>CC3DE</name>
              <bitOffset>11</bitOffset>
              <bitWidth>1</bitWidth>
            </field>
            <field>
              <name>CC4DE</name>
              <bitOffset>12</bitOffset>
              <bitWidth>1</bitWidth>
            </field>
            <field>
              <name>TDE</name>
              <bitOffset>14</bitOffset>
              <bitWidth>1</bitWidth>
            </field>
          </fields>
        </register>
        <register>
          <name>SR</name>
          <addressOffset>0x10</addressOffset>
          <size>0x20</size>
          <fields>
            <field>
              <name>UIF</name>
              <bitOffset>0</bitOffset>
              <bitWidth>1</bitWidth>
            </field>
            <field>
              <name>CC1IF</name>
              <bitOffset>1</bitOffset>
              <bitWidth>1</bitWidth>
            </field>
            <field>
              <name>CC2IF</name>
              <bitOffset>2</bitOffset>
              <bitWidth>1</bitWidth>
            </field>
            <field>
              <name>CC3IF</name>
              <bitOffset>3</bitOffset>
              <bitWidth>1</bitWidth>
            </field>
            <field>
              <name>CC4IF</name>
              <bitOffset>4</bitOffset>
              <bitWidth>1</bitWidth>
            </field>
            <field>
              <name>TIF</name>
              <bitOffset>6</bitOffset>
              <bitWidth>1</bitWidth>
            </field>
            <field>
              <name>CC1OF</name>
              <bitOffset>9</bitOffset>
              <bitWidth>1</bitWidth>
            </field>
            <field>
              <name>CC2OF</name>
              <bitOffset>10</bitOffset>
              <bitWidth>1</bitWidth>
            </field>
            <field>
              <name>CC3OF</name>
              <bitOffset>11</bitOffset>
              <bitWidth>1</bitWidth>
            </field>
            <field>
              <name>CC4OF</name>
              <bitOffset>12</bitOffset>
              <bitWidth>1</bitWidth>
            </field>
          </fields>
        </register>
        <register>
          <name>EGR</name>
          <addressOffset>0x14</addressOffset>
          <size>0x20</size>
          <fields>
            <field>
              <name>UG</name>
              <bitOffset>0</bitOffset>
              <bitWidth>1</bitWidth>
            </field>
            <field>
              <name>CC1G</name>
              <bitOffset>1</bitOffset>
              <bitWidth>1</bitWidth>
            </field>
            <field>
              <name>CC2G</name>
              <bitOffset>2</bitOffset>
              <bitWidth>1</bitWidth>
            </field>
            <field>
              <name>CC3G</name>
              <bitOffset>3</bitOffset>
              <bitWidth>1</bitWidth>
            </field>
            <field>
              <name>CC4G</name>
              <bitOffset>4</bitOffset>
              <bitWidth>1</bitWidth>
            </field>
            <field>
              <name>TG</name>
              <bitOffset>6</bitOffset>
              <bitWidth>1</bitWidth>
            </field>
          </fields>
        </register>
        <register>
          <name>CCMR1</name>
          <addressOffset>0x18</addressOffset>
          <size>0x20</size>
          <fields>
            <field>
              <name>CC1S</name>
              <bitOffset>0</bitOffset>
              <bitWidth>2</bitWidth>
            </field>
            <field>
              <name>OC1FE</name>
              <bitOffset>2</bitOffset>
              <bitWidth>1</bitWidth>
            </field>
            <field>
              <name>OC1PE</name>
              <bitOffset>3</bitOffset>
              <bitWidth>1</bitWidth>
            </field>
            <field>
              <name>OC1M</name>
              <bitOffset>4</bitOffset>
              <bitWidth>3</bitWidth>
            </field>
            <field>
              <name>OC1CE</name>
              <bitOffset>7</bitOffset>
              <bitWidth>1</bitWidth>
            </field>
            <field>
              <name>CC2S</name>
              <bitOffset>8</bitOffset>
              <bitWidth>2</bitWidth>
            </field>
            <field>
              <name>OC2FE</name>
              <bitOffset>10</bitOffset>
              <bitWidth>1</bitWidth>
            </field>
            <field>
              <name>OC2PE</name>
              <bitOffset>11</bitOffset>
              <bitWidth>1</bitWidth>
            </field>
            <field>
              <name>OC2M</name>
              <bitOffset>12</bitOffset>
              <bitWidth>3</bitWidth>
            </field>
            <field>
              <name>OC2CE</name>
              <bitOffset>15</bitOffset>
              <bitWidth>1</bitWidth>
            </field>
          </fields>
        </register>
        <register>
          <name>CCMR2</name>
          <addressOffset>0x1c</addressOffset>
          <size>0x20</size>
          <fields>
            <field>
              <name>CC3S</name>
              <bitOffset>0</bitOffset>
              <bitWidth>2</bitWidth>
            </field>
            <field>
              <name>OC3FE</name>
              <bitOffset>2</bitOffset>
              <bitWidth>1</bitWidth>
            </field>
            <field>
              <name>OC3PE</name>
              <bitOffset>3</bitOffset>
              <bitWidth>1</bitWidth>
            </field>
            <field>
              <name>OC3M</name>
              <bitOffset>4</bitOffset>
              <bitWidth>3</bitWidth>
            </field>
            <field>
              <name>OC3CE</name>
              <bitOffset>7</bitOffset>
              <bitWidth>1</bitWidth>
            </field>
            <field>
              <name>CC4S</name>
              <bitOffset>8</bitOffset>
              <bitWidth>2</bitWidth>
            </field>
            <field>
              <name>OC4FE</name>
              <bitOffset>10</bitOffset>
              <bitWidth>1</bitWidth>
            </field>
            <field>
              <name>OC4PE</name>
              <bitOffset>11</bitOffset>
              <bitWidth>1</bitWidth>
            </field>
            <field>
              <name>OC4M</name>
              <bitOffset>12</bitOffset>
              <bitWidth>3</bitWidth>
            </field>
            <field>
              <name>OC4CE</name>
              <bitOffset>15</bitOffset>
              <bitWidth>1</bitWidth>
            </field>
          </fields>
        </register>
        <register>
          <name>CCER</name>
          <addressOffset>0x20</addressOffset>
          <size>0x20</size>
          <fields>
            <field>
              <name>CC1E</name>
              <bitOffset>0</bitOffset>
              <bitWidth>1</bitWidth>
            </field>
            <field>
              <name>CC1P</name>
              <bitOffset>1</bitOffset>
              <bitWidth>1</bitWidth>
            </field>
            <field>
              <name>CC1NP</name>
              <bitOffset>3</bitOffset>
              <bitWidth>1</bitWidth>
            </field>
            <field>
              <name>CC2E</name>
              <bitOffset>4</bitOffset>
              <bitWidth>1</bitWidth>
            </field>
            <field>
              <name>CC2P</name>
              <bitOffset>5</bitOffset>
              <bitWidth>1</bitWidth>
            </field>
            <field>
              <name>CC2NP</name>
              <bitOffset>7</bitOffset>
              <bitWidth>1</bitWidth>
            </field>
            <field>
              <name>CC3E</name>
              <bitOffset>8</bitOffset>
              <bitWidth>1</bitWidth>
            </field>
            <field>
              <name>CC3P</name>
              <bitOffset>9</bitOffset>
              <bitWidth>1</bitWidth>
            </field>
            <field>
              <name>CC3NP</name>
              <bitOffset>11</bitOffset>
              <bitWidth>1</bitWidth>
            </field>
            <field>
              <name>CC4E</name>
              <bitOffset>12</bitOffset>
              <bitWidth>1</bitWidth>
            </field>
            <field>
              <name>CC4P</name>
              <bitOffset>13</bitOffset>
              <bitWidth>1</bitWidth>
            </field>
            <field>
              <name>CC4NP</name>
              <bitOffset>15</bitOffset>
              <bitWidth>1</bitWidth>
            </field>
          </fields>
        </register>
        <register>
          <name>CNT</name>
          <addressOffset>0x24</addressOffset>
          <size>0x20</size>
          <fields>
            <field>
              <name>CNT</name>
              <bitOffset>0</bitOffset>
              <bitWidth>32</bitWidth>
            </field>
          </fields>
        </register>
        <register>
          <name>PSC</name>
          <addressOffset>0x28</addressOffset>
          <size>0x20</size>
          <fields>
            <field>
              <name>PSC</name>
              <bitOffset>0</bitOffset>
              <bitWidth>16</bitWidth>
            </field>
          </fields>
        </register>
        <register>
          <name>ARR</name>
          <addressOffset>0x2c</addressOffset>
          <size>0x20</size>
          <fields>
            <field>
              <name>ARR</name>
              <bitOffset>0</bitOffset>
              <bitWidth>32</bitWidth>
            </field>
          </fields>
        </register>
        <register>
          <name>CCR1</name>
          <addressOffset>0x34</addressOffset>
          <size>0x20</size>
          <fields>
            <field>
              <name>CCR1</name>
              <bitOffset>0</bitOffset>
              <bitWidth>16</bitWidth>
            </field>
          </fields>
        </register>
        <register>
          <name>CCR2</name>
          <addressOffset>0x38</addressOffset>
          <size>0x20</size>
          <fields>
            <field>
              <name>CCR2</name>
              <bitOffset>0</bitOffset>
              <bitWidth>16</bitWidth>
            </field>
          </fields>
        </register>
        <register>
          <name>CCR3</name>
          <addressOffset>0x3c</addressOffset>
          <size>0x20</size>
          <fields>
            <field>
              <name>CCR3</name>
              <bitOffset>0</bitOffset>
              <bitWidth>16</bitWidth>
            </field>
          </fields>
        </register>
        <register>
          <name>CCR4</name>
          <addressOffset>0x40</addressOffset>
          <size>0x20</size>
          <fields>
            <field>
              <name>CCR4</name>
              <bitOffset>0</bitOffset>
              <bitWidth>16</bitWidth>
            </field>
          </fields>
        </register>
        <register>
          <name>DCR</name>
          <addressOffset>0x48</addressOffset>
          <size>0x20</size>
          <fields>
            <field>
              <name>DBA</name>
              <bitOffset>0</bitOffset>
              <bitWidth>5</bitWidth>
            </field>
            <field>
              <name>DBL</name>
              <bitOffset>8</bitOffset>
              <bitWidth>5</bitWidth>
            </field>
          </fields>
        </register>
        <register>
          <name>DMAR</name>
          <addressOffset>0x4c</addressOffset>
          <size>0x20</size>
          <fields>
            <field>
              <name>DMAB</name>
              <bitOffset>0</bitOffset>
              <bitWidth>16</bitWidth>
            </field>
          </fields>
        </register>
        <register>
          <name>OR</name>
          <addressOffset>0x50</addressOffset>
          <size>0x20</size>
          <fields>
            <field>
              <name>TI1RMP</name>
              <bitOffset>0</bitOffset>
              <bitWidth>2</bitWidth>
            </field>
            <field>
              <name>ETR_RMP</name>
              <bitOffset>2</bitOffset>
              <bitWidth>1</bitWidth>
            </field>
            <field>
              <name>TI1_RMP_RI</name>
              <bitOffset>3</bitOffset>
              <bitWidth>1</bitWidth>
            </field>
          </fields>
        </register>
      </registers>
    </peripheral>
    <peripheral>
      <name>TIM10</name>
      <baseAddress>0x40010c00</baseAddress>
      <registers>
        <register>
          <name>CR1</name>
          <addressOffset>0x0</addressOffset>
          <size>0x20</size>
          <fields>
            <field>
              <name>CEN</name>
              <bitOffset>0</bitOffset>
              <bitWidth>1</bitWidth>
            </field>
            <field>
              <name>UDIS</name>
              <bitOffset>1</bitOffset>
              <bitWidth>1</bitWidth>
            </field>
            <field>
              <name>URS</name>
              <bitOffset>2</bitOffset>
              <bitWidth>1</bitWidth>
            </field>
            <field>
              <name>OPM</name>
              <bitOffset>3</bitOffset>
              <bitWidth>1</bitWidth>
            </field>
            <field>
              <name>DIR</name>
              <bitOffset>4</bitOffset>
              <bitWidth>1</bitWidth>
            </field>
            <field>
              <name>CMS</name>
              <bitOffset>5</bitOffset>
              <bitWidth>2</bitWidth>
            </field>
            <field>
              <name>ARPE</name>
              <bitOffset>7</bitOffset>
              <bitWidth>1</bitWidth>
            </field>
            <field>
              <name>CKD</name>
              <bitOffset>8</bitOffset>
              <bitWidth>2</bitWidth>
            </field>
          </fields>
        </register>
        <register>
          <name>CR2</name>
          <addressOffset>0x4</addressOffset>
          <size>0x20</size>
          <fields>
            <field>
              <name>CCDS</name>
              <bitOffset>3</bitOffset>
              <bitWidth>1</bitWidth>
            </field>
            <field>
              <name>MMS</name>
              <bitOffset>4</bitOffset>
              <bitWidth>3</bitWidth>
            </field>
            <field>
              <name>TI1S</name>
              <bitOffset>7</bitOffset>
              <bitWidth>1</bitWidth>
            </field>
          </fields>
        </register>
        <register>
          <name>SMCR</name>
          <addressOffset>0x8</addressOffset>
          <size>0x20</size>
          <fields>
            <field>
              <name>SMS</name>
              <bitOffset>0</bitOffset>
              <bitWidth>3</bitWidth>
            </field>
            <field>
              <name>OCCS</name>
              <bitOffset>3</bitOffset>
              <bitWidth>1</bitWidth>
            </field>
            <field>
              <name>TS</name>
              <bitOffset>4</bitOffset>
              <bitWidth>3</bitWidth>
            </field>
            <field>
              <name>MSM</name>
              <bitOffset>7</bitOffset>
              <bitWidth>1</bitWidth>
            </field>
            <field>
              <name>ETF</name>
              <bitOffset>8</bitOffset>
              <bitWidth>4</bitWidth>
            </field>
            <field>
              <name>ETPS</name>
              <bitOffset>12</bitOffset>
              <bitWidth>2</bitWidth>
            </field>
            <field>
              <name>ECE</name>
              <bitOffset>14</bitOffset>
              <bitWidth>1</bitWidth>
            </field>
            <field>
              <name>ETP</name>
              <bitOffset>15</bitOffset>
              <bitWidth>1</bitWidth>
            </field>
          </fields>
        </register>
        <register>
          <name>DIER</name>
          <addressOffset>0xc</addressOffset>
          <size>0x20</size>
          <fields>
            <field>
              <name>UIE</name>
              <bitOffset>0</bitOffset>
              <bitWidth>1</bitWidth>
            </field>
            <field>
              <name>CC1IE</name>
              <bitOffset>1</bitOffset>
              <bitWidth>1</bitWidth>
            </field>
            <field>
              <name>CC2IE</name>
              <bitOffset>2</bitOffset>
              <bitWidth>1</bitWidth>
            </field>
            <field>
              <name>CC3IE</name>
              <bitOffset>3</bitOffset>
              <bitWidth>1</bitWidth>
            </field>
            <field>
              <name>CC4IE</name>
              <bitOffset>4</bitOffset>
              <bitWidth>1</bitWidth>
            </field>
            <field>
              <name>TIE</name>
              <bitOffset>6</bitOffset>
              <bitWidth>1</bitWidth>
            </field>
            <field>
              <name>UDE</name>
              <bitOffset>8</bitOffset>
              <bitWidth>1</bitWidth>
            </field>
            <field>
              <name>CC1DE</name>
              <bitOffset>9</bitOffset>
              <bitWidth>1</bitWidth>
            </field>
            <field>
              <name>CC2DE</name>
              <bitOffset>10</bitOffset>
              <bitWidth>1</bitWidth>
            </field>
            <field>
              <name>CC3DE</name>
              <bitOffset>11</bitOffset>
              <bitWidth>1</bitWidth>
            </field>
            <field>
              <name>CC4DE</name>
              <bitOffset>12</bitOffset>
              <bitWidth>1</bitWidth>
            </field>
            <field>
              <name>TDE</name>
              <bitOffset>14</bitOffset>
              <bitWidth>1</bitWidth>
            </field>
          </fields>
        </register>
        <register>
          <name>SR</name>
          <addressOffset>0x10</addressOffset>
          <size>0x20</size>
          <fields>
            <field>
              <name>UIF</name>
              <bitOffset>0</bitOffset>
              <bitWidth>1</bitWidth>
            </field>
            <field>
              <name>CC1IF</name>
              <bitOffset>1</bitOffset>
              <bitWidth>1</bitWidth>
            </field>
            <field>
              <name>CC2IF</name>
              <bitOffset>2</bitOffset>
              <bitWidth>1</bitWidth>
            </field>
            <field>
              <name>CC3IF</name>
              <bitOffset>3</bitOffset>
              <bitWidth>1</bitWidth>
            </field>
            <field>
              <name>CC4IF</name>
              <bitOffset>4</bitOffset>
              <bitWidth>1</bitWidth>
            </field>
            <field>
              <name>TIF</name>
              <bitOffset>6</bitOffset>
              <bitWidth>1</bitWidth>
            </field>
            <field>
              <name>CC1OF</name>
              <bitOffset>9</bitOffset>
              <bitWidth>1</bitWidth>
            </field>
            <field>
              <name>CC2OF</name>
              <bitOffset>10</bitOffset>
              <bitWidth>1</bitWidth>
            </field>
            <field>
              <name>CC3OF</name>
              <bitOffset>11</bitOffset>
              <bitWidth>1</bitWidth>
            </field>
            <field>
              <name>CC4OF</name>
              <bitOffset>12</bitOffset>
              <bitWidth>1</bitWidth>
            </field>
          </fields>
        </register>
        <register>
          <name>EGR</name>
          <addressOffset>0x14</addressOffset>
          <size>0x20</size>
          <fields>
            <field>
              <name>UG</name>
              <bitOffset>0</bitOffset>
              <bitWidth>1</bitWidth>
            </field>
            <field>
              <name>CC1G</name>
              <bitOffset>1</bitOffset>
              <bitWidth>1</bitWidth>
            </field>
            <field>
              <name>CC2G</name>
              <bitOffset>2</bitOffset>
              <bitWidth>1</bitWidth>
            </field>
            <field>
              <name>CC3G</name>
              <bitOffset>3</bitOffset>
              <bitWidth>1</bitWidth>
            </field>
            <field>
              <name>CC4G</name>
              <bitOffset>4</bitOffset>
              <bitWidth>1</bitWidth>
            </field>
            <field>
              <name>TG</name>
              <bitOffset>6</bitOffset>
              <bitWidth>1</bitWidth>
            </field>
          </fields>
        </register>
        <register>
          <name>CCMR1</name>
          <addressOffset>0x18</addressOffset>
          <size>0x20</size>
          <fields>
            <field>
              <name>CC1S</name>
              <bitOffset>0</bitOffset>
              <bitWidth>2</bitWidth>
            </field>
            <field>
              <name>OC1FE</name>
              <bitOffset>2</bitOffset>
              <bitWidth>1</bitWidth>
            </field>
            <field>
              <name>OC1PE</name>
              <bitOffset>3</bitOffset>
              <bitWidth>1</bitWidth>
            </field>
            <field>
              <name>OC1M</name>
              <bitOffset>4</bitOffset>
              <bitWidth>3</bitWidth>
            </field>
            <field>
              <name>OC1CE</name>
              <bitOffset>7</bitOffset>
              <bitWidth>1</bitWidth>
            </field>
            <field>
              <name>CC2S</name>
              <bitOffset>8</bitOffset>
              <bitWidth>2</bitWidth>
            </field>
            <field>
              <name>OC2FE</name>
              <bitOffset>10</bitOffset>
              <bitWidth>1</bitWidth>
            </field>
            <field>
              <name>OC2PE</name>
              <bitOffset>11</bitOffset>
              <bitWidth>1</bitWidth>
            </field>
            <field>
              <name>OC2M</name>
              <bitOffset>12</bitOffset>
              <bitWidth>3</bitWidth>
            </field>
            <field>
              <name>OC2CE</name>
              <bitOffset>15</bitOffset>
              <bitWidth>1</bitWidth>
            </field>
          </fields>
        </register>
        <register>
          <name>CCMR2</name>
          <addressOffset>0x1c</addressOffset>
          <size>0x20</size>
          <fields>
            <field>
              <name>CC3S</name>
              <bitOffset>0</bitOffset>
              <bitWidth>2</bitWidth>
            </field>
            <field>
              <name>OC3FE</name>
              <bitOffset>2</bitOffset>
              <bitWidth>1</bitWidth>
            </field>
            <field>
              <name>OC3PE</name>
              <bitOffset>3</bitOffset>
              <bitWidth>1</bitWidth>
            </field>
            <field>
              <name>OC3M</name>
              <bitOffset>4</bitOffset>
              <bitWidth>3</bitWidth>
            </field>
            <field>
              <name>OC3CE</name>
              <bitOffset>7</bitOffset>
              <bitWidth>1</bitWidth>
            </field>
            <field>
              <name>CC4S</name>
              <bitOffset>8</bitOffset>
              <bitWidth>2</bitWidth>
            </field>
            <field>
              <name>OC4FE</name>
              <bitOffset>10</bitOffset>
              <bitWidth>1</bitWidth>
            </field>
            <field>
              <name>OC4PE</name>
              <bitOffset>11</bitOffset>
              <bitWidth>1</bitWidth>
            </field>
            <field>
              <name>OC4M</name>
              <bitOffset>12</bitOffset>
              <bitWidth>3</bitWidth>
            </field>
            <field>
              <name>OC4CE</name>
              <bitOffset>15</bitOffset>
              <bitWidth>1</bitWidth>
            </field>
          </fields>
        </register>
        <register>
          <name>CCER</name>
          <addressOffset>0x20</addressOffset>
          <size>0x20</size>
          <fields>
            <field>
              <name>CC1E</name>
              <bitOffset>0</bitOffset>
              <bitWidth>1</bitWidth>
            </field>
            <field>
              <name>CC1P</name>
              <bitOffset>1</bitOffset>
              <bitWidth>1</bitWidth>
            </field>
            <field>
              <name>CC1NP</name>
              <bitOffset>3</bitOffset>
              <bitWidth>1</bitWidth>
            </field>
            <field>
              <name>CC2E</name>
              <bitOffset>4</bitOffset>
              <bitWidth>1</bitWidth>
            </field>
            <field>
              <name>CC2P</name>
              <bitOffset>5</bitOffset>
              <bitWidth>1</bitWidth>
            </field>
            <field>
              <name>CC2NP</name>
              <bitOffset>7</bitOffset>
              <bitWidth>1</bitWidth>
            </field>
            <field>
              <name>CC3E</name>
              <bitOffset>8</bitOffset>
              <bitWidth>1</bitWidth>
            </field>
            <field>
              <name>CC3P</name>
              <bitOffset>9</bitOffset>
              <bitWidth>1</bitWidth>
            </field>
            <field>
              <name>CC3NP</name>
              <bitOffset>11</bitOffset>
              <bitWidth>1</bitWidth>
            </field>
            <field>
              <name>CC4E</name>
              <bitOffset>12</bitOffset>
              <bitWidth>1</bitWidth>
            </field>
            <field>
              <name>CC4P</name>
              <bitOffset>13</bitOffset>
              <bitWidth>1</bitWidth>
            </field>
            <field>
              <name>CC4NP</name>
              <bitOffset>15</bitOffset>
              <bitWidth>1</bitWidth>
            </field>
          </fields>
        </register>
        <register>
          <name>CNT</name>
          <addressOffset>0x24</addressOffset>
          <size>0x20</size>
          <fields>
            <field>
              <name>CNT</name>
              <bitOffset>0</bitOffset>
              <bitWidth>32</bitWidth>
            </field>
          </fields>
        </register>
        <register>
          <name>PSC</name>
          <addressOffset>0x28</addressOffset>
          <size>0x20</size>
          <fields>
            <field>
              <name>PSC</name>
              <bitOffset>0</bitOffset>
              <bitWidth>16</bitWidth>
            </field>
          </fields>
        </register>
        <register>
          <name>ARR</name>
          <addressOffset>0x2c</addressOffset>
          <size>0x20</size>
          <fields>
            <field>
              <name>ARR</name>
              <bitOffset>0</bitOffset>
              <bitWidth>32</bitWidth>
            </field>
          </fields>
        </register>
        <register>
          <name>CCR1</name>
          <addressOffset>0x34</addressOffset>
          <size>0x20</size>
          <fields>
            <field>
              <name>CCR1</name>
              <bitOffset>0</bitOffset>
              <bitWidth>16</bitWidth>
            </field>
          </fields>
        </register>
        <register>
          <name>CCR2</name>
          <addressOffset>0x38</addressOffset>
          <size>0x20</size>
          <fields>
            <field>
              <name>CCR2</name>
              <bitOffset>0</bitOffset>
              <bitWidth>16</bitWidth>
            </field>
          </fields>
        </register>
        <register>
          <name>CCR3</name>
          <addressOffset>0x3c</addressOffset>
          <size>0x20</size>
          <fields>
            <field>
              <name>CCR3</name>
              <bitOffset>0</bitOffset>
              <bitWidth>16</bitWidth>
            </field>
          </fields>
        </register>
        <register>
          <name>CCR4</name>
          <addressOffset>0x40</addressOffset>
          <size>0x20</size>
          <fields>
            <field>
              <name>CCR4</name>
              <bitOffset>0</bitOffset>
              <bitWidth>16</bitWidth>
            </field>
          </fields>
        </register>
        <register>
          <name>DCR</name>
          <addressOffset>0x48</addressOffset>
          <size>0x20</size>
          <fields>
            <field>
              <name>DBA</name>
              <bitOffset>0</bitOffset>
              <bitWidth>5</bitWidth>
            </field>
            <field>
              <name>DBL</name>
              <bitOffset>8</bitOffset>
              <bitWidth>5</bitWidth>
            </field>
          </fields>
        </register>
        <register>
          <name>DMAR</name>
          <addressOffset>0x4c</addressOffset>
          <size>0x20</size>
          <fields>
            <field>
              <name>DMAB</name>
              <bitOffset>0</bitOffset>
              <bitWidth>16</bitWidth>
            </field>
          </fields>
        </register>
        <register>
          <name>OR</name>
          <addressOffset>0x50</addressOffset>
          <size>0x20</size>
          <fields>
            <field>
              <name>TI1RMP</name>
              <bitOffset>0</bitOffset>
              <bitWidth>2</bitWidth>
            </field>
            <field>
              <name>ETR_RMP</name>
              <bitOffset>2</bitOffset>
              <bitWidth>1</bitWidth>
            </field>
            <field>
              <name>TI1_RMP_RI</name>
              <bitOffset>3</bitOffset>
              <bitWidth>1</bitWidth>
            </field>
          </fields>
        </register>
      </registers>
    </peripheral>
    <peripheral>
      <name>TIM11</name>
      <baseAddress>0x40011000</baseAddress>
      <registers>
        <register>
          <name>CR1</name>
          <addressOffset>0x0</addressOffset>
          <size>0x20</size>
          <fields>
            <field>
              <name>CEN</name>
              <bitOffset>0</bitOffset>
              <bitWidth>1</bitWidth>
            </field>
            <field>
              <name>UDIS</name>
              <bitOffset>1</bitOffset>
              <bitWidth>1</bitWidth>
            </field>
            <field>
              <name>URS</name>
              <bitOffset>2</bitOffset>
              <bitWidth>1</bitWidth>
            </field>
            <field>
              <name>OPM</name>
              <bitOffset>3</bitOffset>
              <bitWidth>1</bitWidth>
            </field>
            <field>
              <name>DIR</name>
              <bitOffset>4</bitOffset>
              <bitWidth>1</bitWidth>
            </field>
            <field>
              <name>CMS</name>
              <bitOffset>5</bitOffset>
              <bitWidth>2</bitWidth>
            </field>
            <field>
              <name>ARPE</name>
              <bitOffset>7</bitOffset>
              <bitWidth>1</bitWidth>
            </field>
            <field>
              <name>CKD</name>
              <bitOffset>8</bitOffset>
              <bitWidth>2</bitWidth>
            </field>
          </fields>
        </register>
        <register>
          <name>CR2</name>
          <addressOffset>0x4</addressOffset>
          <size>0x20</size>
          <fields>
            <field>
              <name>CCDS</name>
              <bitOffset>3</bitOffset>
              <bitWidth>1</bitWidth>
            </field>
            <field>
              <name>MMS</name>
              <bitOffset>4</bitOffset>
              <bitWidth>3</bitWidth>
            </field>
            <field>
              <name>TI1S</name>
              <bitOffset>7</bitOffset>
              <bitWidth>1</bitWidth>
            </field>
          </fields>
        </register>
        <register>
          <name>SMCR</name>
          <addressOffset>0x8</addressOffset>
          <size>0x20</size>
          <fields>
            <field>
              <name>SMS</name>
              <bitOffset>0</bitOffset>
              <bitWidth>3</bitWidth>
            </field>
            <field>
              <name>OCCS</name>
              <bitOffset>3</bitOffset>
              <bitWidth>1</bitWidth>
            </field>
            <field>
              <name>TS</name>
              <bitOffset>4</bitOffset>
              <bitWidth>3</bitWidth>
            </field>
            <field>
              <name>MSM</name>
              <bitOffset>7</bitOffset>
              <bitWidth>1</bitWidth>
            </field>
            <field>
              <name>ETF</name>
              <bitOffset>8</bitOffset>
              <bitWidth>4</bitWidth>
            </field>
            <field>
              <name>ETPS</name>
              <bitOffset>12</bitOffset>
              <bitWidth>2</bitWidth>
            </field>
            <field>
              <name>ECE</name>
              <bitOffset>14</bitOffset>
              <bitWidth>1</bitWidth>
            </field>
            <field>
              <name>ETP</name>
              <bitOffset>15</bitOffset>
              <bitWidth>1</bitWidth>
            </field>
          </fields>
        </register>
        <register>
          <name>DIER</name>
          <addressOffset>0xc</addressOffset>
          <size>0x20</size>
          <fields>
            <field>
              <name>UIE</name>
              <bitOffset>0</bitOffset>
              <bitWidth>1</bitWidth>
            </field>
            <field>
              <name>CC1IE</name>
              <bitOffset>1</bitOffset>
              <bitWidth>1</bitWidth>
            </field>
            <field>
              <name>CC2IE</name>
              <bitOffset>2</bitOffset>
              <bitWidth>1</bitWidth>
            </field>
            <field>
              <name>CC3IE</name>
              <bitOffset>3</bitOffset>
              <bitWidth>1</bitWidth>
            </field>
            <field>
              <name>CC4IE</name>
              <bitOffset>4</bitOffset>
              <bitWidth>1</bitWidth>
            </field>
            <field>
              <name>TIE</name>
              <bitOffset>6</bitOffset>
              <bitWidth>1</bitWidth>
            </field>
            <field>
              <name>UDE</name>
              <bitOffset>8</bitOffset>
              <bitWidth>1</bitWidth>
            </field>
            <field>
              <name>CC1DE</name>
              <bitOffset>9</bitOffset>
              <bitWidth>1</bitWidth>
            </field>
            <field>
              <name>CC2DE</name>
              <bitOffset>10</bitOffset>
              <bitWidth>1</bitWidth>
            </field>
            <field>
              <name>CC3DE</name>
              <bitOffset>11</bitOffset>
              <bitWidth>1</bitWidth>
            </field>
            <field>
              <name>CC4DE</name>
              <bitOffset>12</bitOffset>
              <bitWidth>1</bitWidth>
            </field>
            <field>
              <name>TDE</name>
              <bitOffset>14</bitOffset>
              <bitWidth>1</bitWidth>
            </field>
          </fields>
        </register>
        <register>
          <name>SR</name>
          <addressOffset>0x10</addressOffset>
          <size>0x20</size>
          <fields>
            <field>
              <name>UIF</name>
              <bitOffset>0</bitOffset>
              <bitWidth>1</bitWidth>
            </field>
            <field>
              <name>CC1IF</name>
              <bitOffset>1</bitOffset>
              <bitWidth>1</bitWidth>
            </field>
            <field>
              <name>CC2IF</name>
              <bitOffset>2</bitOffset>
              <bitWidth>1</bitWidth>
            </field>
            <field>
              <name>CC3IF</name>
              <bitOffset>3</bitOffset>
              <bitWidth>1</bitWidth>
            </field>
            <field>
              <name>CC4IF</name>
              <bitOffset>4</bitOffset>
              <bitWidth>1</bitWidth>
            </field>
            <field>
              <name>TIF</name>
              <bitOffset>6</bitOffset>
              <bitWidth>1</bitWidth>
            </field>
            <field>
              <name>CC1OF</name>
              <bitOffset>9</bitOffset>
              <bitWidth>1</bitWidth>
            </field>
            <field>
              <name>CC2OF</name>
              <bitOffset>10</bitOffset>
              <bitWidth>1</bitWidth>
            </field>
            <field>
              <name>CC3OF</name>
              <bitOffset>11</bitOffset>
              <bitWidth>1</bitWidth>
            </field>
            <field>
              <name>CC4OF</name>
              <bitOffset>12</bitOffset>
              <bitWidth>1</bitWidth>
            </field>
          </fields>
        </register>
        <register>
          <name>EGR</name>
          <addressOffset>0x14</addressOffset>
          <size>0x20</size>
          <fields>
            <field>
              <name>UG</name>
              <bitOffset>0</bitOffset>
              <bitWidth>1</bitWidth>
            </field>
            <field>
              <name>CC1G</name>
              <bitOffset>1</bitOffset>
              <bitWidth>1</bitWidth>
            </field>
            <field>
              <name>CC2G</name>
              <bitOffset>2</bitOffset>
              <bitWidth>1</bitWidth>
            </field>
            <field>
              <name>CC3G</name>
              <bitOffset>3</bitOffset>
              <bitWidth>1</bitWidth>
            </field>
            <field>
              <name>CC4G</name>
              <bitOffset>4</bitOffset>
              <bitWidth>1</bitWidth>
            </field>
            <field>
              <name>TG</name>
              <bitOffset>6</bitOffset>
              <bitWidth>1</bitWidth>
            </field>
          </fields>
        </register>
        <register>
          <name>CCMR1</name>
          <addressOffset>0x18</addressOffset>
          <size>0x20</size>
          <fields>
            <field>
              <name>CC1S</name>
              <bitOffset>0</bitOffset>
              <bitWidth>2</bitWidth>
            </field>
            <field>
              <name>OC1FE</name>
              <bitOffset>2</bitOffset>
              <bitWidth>1</bitWidth>
            </field>
            <field>
              <name>OC1PE</name>
              <bitOffset>3</bitOffset>
              <bitWidth>1</bitWidth>
            </field>
            <field>
              <name>OC1M</name>
              <bitOffset>4</bitOffset>
              <bitWidth>3</bitWidth>
            </field>
            <field>
              <name>OC1CE</name>
              <bitOffset>7</bitOffset>
              <bitWidth>1</bitWidth>
            </field>
            <field>
              <name>CC2S</name>
              <bitOffset>8</bitOffset>
              <bitWidth>2</bitWidth>
            </field>
            <field>
              <name>OC2FE</name>
              <bitOffset>10</bitOffset>
              <bitWidth>1</bitWidth>
            </field>
            <field>
              <name>OC2PE</name>
              <bitOffset>11</bitOffset>
              <bitWidth>1</bitWidth>
            </field>
            <field>
              <name>OC2M</name>
              <bitOffset>12</bitOffset>
              <bitWidth>3</bitWidth>
            </field>
            <field>
              <name>OC2CE</name>
              <bitOffset>15</bitOffset>
              <bitWidth>1</bitWidth>
            </field>
          </fields>
        </register>
        <register>
          <name>CCMR2</name>
          <addressOffset>0x1c</addressOffset>
          <size>0x20</size>
          <fields>
            <field>
              <name>CC3S</name>
              <bitOffset>0</bitOffset>
              <bitWidth>2</bitWidth>
            </field>
            <field>
              <name>OC3FE</name>
              <bitOffset>2</bitOffset>
              <bitWidth>1</bitWidth>
            </field>
            <field>
              <name>OC3PE</name>
              <bitOffset>3</bitOffset>
              <bitWidth>1</bitWidth>
            </field>
            <field>
              <name>OC3M</name>
              <bitOffset>4</bitOffset>
              <bitWidth>3</bitWidth>
            </field>
            <field>
              <name>OC3CE</name>
              <bitOffset>7</bitOffset>
              <bitWidth>1</bitWidth>
            </field>
            <field>
              <name>CC4S</name>
              <bitOffset>8</bitOffset>
              <bitWidth>2</bitWidth>
            </field>
            <field>
              <name>OC4FE</name>
              <bitOffset>10</bitOffset>
              <bitWidth>1</bitWidth>
            </field>
            <field>
              <name>OC4PE</name>
              <bitOffset>11</bitOffset>
              <bitWidth>1</bitWidth>
            </field>
            <field>
              <name>OC4M</name>
              <bitOffset>12</bitOffset>
              <bitWidth>3</bitWidth>
            </field>
            <field>
              <name>OC4CE</name>
              <bitOffset>15</bitOffset>
              <bitWidth>1</bitWidth>
            </field>
          </fields>
        </register>
        <register>
          <name>CCER</name>
          <addressOffset>0x20</addressOffset>
          <size>0x20</size>
          <fields>
            <field>
              <name>CC1E</name>
              <bitOffset>0</bitOffset>
              <bitWidth>1</bitWidth>
            </field>
            <field>
              <name>CC1P</name>
              <bitOffset>1</bitOffset>
              <bitWidth>1</bitWidth>
            </field>
            <field>
              <name>CC1NP</name>
              <bitOffset>3</bitOffset>
              <bitWidth>1</bitWidth>
            </field>
            <field>
              <name>CC2E</name>
              <bitOffset>4</bitOffset>
              <bitWidth>1</bitWidth>
            </field>
            <field>
              <name>CC2P</name>
              <bitOffset>5</bitOffset>
              <bitWidth>1</bitWidth>
            </field>
            <field>
              <name>CC2NP</name>
              <bitOffset>7</bitOffset>
              <bitWidth>1</bitWidth>
            </field>
            <field>
              <name>CC3E</name>
              <bitOffset>8</bitOffset>
              <bitWidth>1</bitWidth>
            </field>
            <field>
              <name>CC3P</name>
              <bitOffset>9</bitOffset>
              <bitWidth>1</bitWidth>
            </field>
            <field>
              <name>CC3NP</name>
              <bitOffset>11</bitOffset>
              <bitWidth>1</bitWidth>
            </field>
            <field>
              <name>CC4E</name>
              <bitOffset>12</bitOffset>
              <bitWidth>1</bitWidth>
            </field>
            <field>
              <name>CC4P</name>
              <bitOffset>13</bitOffset>
              <bitWidth>1</bitWidth>
            </field>
            <field>
              <name>CC4NP</name>
              <bitOffset>15</bitOffset>
              <bitWidth>1</bitWidth>
            </field>
          </fields>
        </register>
        <register>
          <name>CNT</name>
          <addressOffset>0x24</addressOffset>
          <size>0x20</size>
          <fields>
            <field>
              <name>CNT</name>
              <bitOffset>0</bitOffset>
              <bitWidth>32</bitWidth>
            </field>
          </fields>
        </register>
        <register>
          <name>PSC</name>
          <addressOffset>0x28</addressOffset>
          <size>0x20</size>
          <fields>
            <field>
              <name>PSC</name>
              <bitOffset>0</bitOffset>
              <bitWidth>16</bitWidth>
            </field>
          </fields>
        </register>
        <register>
          <name>ARR</name>
          <addressOffset>0x2c</addressOffset>
          <size>0x20</size>
          <fields>
            <field>
              <name>ARR</name>
              <bitOffset>0</bitOffset>
              <bitWidth>32</bitWidth>
            </field>
          </fields>
        </register>
        <register>
          <name>CCR1</name>
          <addressOffset>0x34</addressOffset>
          <size>0x20</size>
          <fields>
            <field>
              <name>CCR1</name>
              <bitOffset>0</bitOffset>
              <bitWidth>16</bitWidth>
            </field>
          </fields>
        </register>
        <register>
          <name>CCR2</name>
          <addressOffset>0x38</addressOffset>
          <size>0x20</size>
          <fields>
            <field>
              <name>CCR2</name>
              <bitOffset>0</bitOffset>
              <bitWidth>16</bitWidth>
            </field>
          </fields>
        </register>
        <register>
          <name>CCR3</name>
          <addressOffset>0x3c</addressOffset>
          <size>0x20</size>
          <fields>
            <field>
              <name>CCR3</name>
              <bitOffset>0</bitOffset>
              <bitWidth>16</bitWidth>
            </field>
          </fields>
        </register>
        <register>
          <name>CCR4</name>
          <addressOffset>0x40</addressOffset>
          <size>0x20</size>
          <fields>
            <field>
              <name>CCR4</name>
              <bitOffset>0</bitOffset>
              <bitWidth>16</bitWidth>
            </field>
          </fields>
        </register>
        <register>
          <name>DCR</name>
          <addressOffset>0x48</addressOffset>
          <size>0x20</size>
          <fields>
            <field>
              <name>DBA</name>
              <bitOffset>0</bitOffset>
              <bitWidth>5</bitWidth>
            </field>
            <field>
              <name>DBL</name>
              <bitOffset>8</bitOffset>
              <bitWidth>5</bitWidth>
            </field>
          </fields>
        </register>
        <register>
          <name>DMAR</name>
          <addressOffset>0x4c</addressOffset>
          <size>0x20</size>
          <fields>
            <field>
              <name>DMAB</name>
              <bitOffset>0</bitOffset>
              <bitWidth>16</bitWidth>
            </field>
          </fields>
        </register>
        <register>
          <name>OR</name>
          <addressOffset>0x50</addressOffset>
          <size>0x20</size>
          <fields>
            <field>
              <name>TI1RMP</name>
              <bitOffset>0</bitOffset>
              <bitWidth>2</bitWidth>
            </field>
            <field>
              <name>ETR_RMP</name>
              <bitOffset>2</bitOffset>
              <bitWidth>1</bitWidth>
            </field>
            <field>
              <name>TI1_RMP_RI</name>
              <bitOffset>3</bitOffset>
              <bitWidth>1</bitWidth>
            </field>
          </fields>
        </register>
      </registers>
    </peripheral>
    <peripheral>
      <name>ADC1</name>
      <baseAddress>0x40012400</baseAddress>
      <registers>
        <register>
          <name>SR</name>
          <addressOffset>0x0</addressOffset>
          <size>0x20</size>
          <fields>
            <field>
              <name>AWD</name>
              <bitOffset>0</bitOffset>
              <bitWidth>1</bitWidth>
            </field>
            <field>
              <name>EOCS</name>
              <bitOffset>1</bitOffset>
              <bitWidth>1</bitWidth>
            </field>
            <field>
              <name>JEOS</name>
              <bitOffset>2</bitOffset>
              <bitWidth>1</bitWidth>
            </field>
            <field>
              <name>JSTRT</name>
              <bitOffset>3</bitOffset>
              <bitWidth>1</bitWidth>
            </field>
            <field>
              <name>STRT</name>
              <bitOffset>4</bitOffset>
              <bitWidth>1</bitWidth>
            </field>
            <field>
              <name>OVR</name>
              <bitOffset>5</bitOffset>
              <bitWidth>1</bitWidth>
            </field>
            <field>
              <name>ADONS</name>
              <bitOffset>6</bitOffset>
              <bitWidth>1</bitWidth>
            </field>
            <field>
              <name>RCNR</name>
              <bitOffset>8</bitOffset>
              <bitWidth>1</bitWidth>
            </field>
            <field>
              <name>JCNR</name>
              <bitOffset>9</bitOffset>
              <bitWidth>1</bitWidth>
            </field>
          </fields>
        </register>
        <register>
          <name>CR1</name>
          <addressOffset>0x4</addressOffset>
          <size>0x20</size>
          <fields>
            <field>
              <name>AWDCH</name>
              <bitOffset>0</bitOffset>
              <bitWidth>5</bitWidth>
            </field>
            <field>
              <name>EOCSIE</name>
              <bitOffset>5</bitOffset>
              <bitWidth>1</bitWidth>
            </field>
            <field>
              <name>AWDIE</name>
              <bitOffset>6</bitOffset>
              <bitWidth>1</bitWidth>
            </field>
            <field>
              <name>JEOSIE</name>
              <bitOffset>7</bitOffset>
              <bitWidth>1</bitWidth>
            </field>
            <field>
              <name>SCAN</name>
              <bitOffset>8</bitOffset>
              <bitWidth>1</bitWidth>
            </field>
            <field>
              <name>AWDSGL</name>
              <bitOffset>9</bitOffset>
              <bitWidth>1</bitWidth>
            </field>
            <field>
              <name>JAUTO</name>
              <bitOffset>10</bitOffset>
              <bitWidth>1</bitWidth>
            </field>
            <field>
              <name>DISCEN</name>
              <bitOffset>11</bitOffset>
              <bitWidth>1</bitWidth>
            </field>
            <field>
              <name>JDISCEN</name>
              <bitOffset>12</bitOffset>
              <bitWidth>1</bitWidth>
            </field>
            <field>
              <name>DISCNUM</name>
              <bitOffset>13</bitOffset>
              <bitWidth>3</bitWidth>
            </field>
            <field>
              <name>PDD</name>
              <bitOffset>16</bitOffset>
              <bitWidth>1</bitWidth>
            </field>
            <field>
              <name>PDI</name>
              <bitOffset>17</bitOffset>
              <bitWidth>1</bitWidth>
            </field>
            <field>
              <name>JAWDEN</name>
              <bitOffset>22</bitOffset>
              <bitWidth>1</bitWidth>
            </field>
            <field>
              <name>AWDEN</name>
              <bitOffset>23</bitOffset>
              <bitWidth>1</bitWidth>
            </field>
            <field>
              <name>RES</name>
              <bitOffset>24</bitOffset>
              <bitWidth>2</bitWidth>
            </field>
            <field>
              <name>OVRIE</name>
              <bitOffset>26</bitOffset>
              <bitWidth>1</bitWidth>
            </field>
          </fields>
        </register>
        <register>
          <name>CR2</name>
          <addressOffset>0x8</addressOffset>
          <size>0x20</size>
          <fields>
            <field>
              <name>ADON</name>
              <bitOffset>0</bitOffset>
              <bitWidth>1</bitWidth>
            </field>
            <field>
              <name>CONT</name>
              <bitOffset>1</bitOffset>
              <bitWidth>1</bitWidth>
            </field>
            <field>
              <name>DELS</name>
              <bitOffset>4</bitOffset>
              <bitWidth>3</bitWidth>
            </field>
            <field>
              <name>DMA</name>
              <bitOffset>8</bitOffset>
              <bitWidth>1</bitWidth>
            </field>
            <field>
              <name>DDS</name>
              <bitOffset>9</bitOffset>
              <bitWidth>1</bitWidth>
            </field>
            <field>
              <name>EOCS</name>
              <bitOffset>10</bitOffset>
              <bitWidth>1</bitWidth>
            </field>
            <field>
              <name>ALIGN</name>
              <bitOffset>11</bitOffset>
              <bitWidth>1</bitWidth>
            </field>
            <field>
              <name>JEXTSEL</name>
              <bitOffset>16</bitOffset>
              <bitWidth>4</bitWidth>
            </field>
            <field>
              <name>JEXTEN</name>
              <bitOffset>20</bitOffset>
              <bitWidth>2</bitWidth>
            </field>
            <field>
              <name>JSWSTART</name>
              <bitOffset>22</bitOffset>
              <bitWidth>1</bitWidth>
            </field>
            <field>
              <name>EXTSEL</name>
              <bitOffset>24</bitOffset>
              <bitWidth>4</bitWidth>
            </field>
            <field>
              <name>EXTEN</name>
              <bitOffset>28</bitOffset>
              <bitWidth>2</bitWidth>
            </field>
            <field>
              <name>SWSTART</name>
              <bitOffset>30</bitOffset>
              <bitWidth>1</bitWidth>
            </field>
          </fields>
        </register>
        <register>
          <name>SMPR1</name>
          <addressOffset>0xc</addressOffset>
          <size>0x20</size>
          <fields>
            <field>
              <name>SMP20</name>
              <bitOffset>0</bitOffset>
              <bitWidth>3</bitWidth>
            </field>
            <field>
              <name>SMP21</name>
              <bitOffset>3</bitOffset>
              <bitWidth>3</bitWidth>
            </field>
            <field>
              <name>SMP22</name>
              <bitOffset>6</bitOffset>
              <bitWidth>3</bitWidth>
            </field>
            <field>
              <name>SMP23</name>
              <bitOffset>9</bitOffset>
              <bitWidth>3</bitWidth>
            </field>
            <field>
              <name>SMP24</name>
              <bitOffset>12</bitOffset>
              <bitWidth>3</bitWidth>
            </field>
            <field>
              <name>SMP25</name>
              <bitOffset>15</bitOffset>
              <bitWidth>3</bitWidth>
            </field>
            <field>
              <name>SMP26</name>
              <bitOffset>18</bitOffset>
              <bitWidth>3</bitWidth>
            </field>
          </fields>
        </register>
        <register>
          <name>SMPR2</name>
          <addressOffset>0x10</addressOffset>
          <size>0x20</size>
          <fields>
            <field>
              <name>SMP10</name>
              <bitOffset>0</bitOffset>
              <bitWidth>3</bitWidth>
            </field>
            <field>
              <name>SMP11</name>
              <bitOffset>3</bitOffset>
              <bitWidth>3</bitWidth>
            </field>
            <field>
              <name>SMP12</name>
              <bitOffset>6</bitOffset>
              <bitWidth>3</bitWidth>
            </field>
            <field>
              <name>SMP13</name>
              <bitOffset>9</bitOffset>
              <bitWidth>3</bitWidth>
            </field>
            <field>
              <name>SMP14</name>
              <bitOffset>12</bitOffset>
              <bitWidth>3</bitWidth>
            </field>
            <field>
              <name>SMP15</name>
              <bitOffset>15</bitOffset>
              <bitWidth>3</bitWidth>
            </field>
            <field>
              <name>SMP16</name>
              <bitOffset>18</bitOffset>
              <bitWidth>3</bitWidth>
            </field>
            <field>
              <name>SMP17</name>
              <bitOffset>21</bitOffset>
              <bitWidth>3</bitWidth>
            </field>
            <field>
              <name>SMP18</name>
              <bitOffset>24</bitOffset>
              <bitWidth>3</bitWidth>
            </field>
            <field>
              <name>SMP19</name>
              <bitOffset>27</bitOffset>
              <bitWidth>3</bitWidth>
            </field>
          </fields>
        </register>
        <register>
          <name>SMPR3</name>
          <addressOffset>0x14</addressOffset>
          <size>0x20</size>
          <fields>
            <field>
              <name>SMP0</name>
              <bitOffset>0</bitOffset>
              <bitWidth>3</bitWidth>
            </field>
            <field>
              <name>SMP1</name>
              <bitOffset>3</bitOffset>
              <bitWidth>3</bitWidth>
            </field>
            <field>
              <name>SMP2</name>
              <bitOffset>6</bitOffset>
              <bitWidth>3</bitWidth>
            </field>
            <field>
              <name>SMP3</name>
              <bitOffset>9</bitOffset>
              <bitWidth>3</bitWidth>
            </field>
            <field>
              <name>SMP4</name>
              <bitOffset>12</bitOffset>
              <bitWidth>3</bitWidth>
            </field>
            <field>
              <name>SMP5</name>
              <bitOffset>15</bitOffset>
              <bitWidth>3</bitWidth>
            </field>
            <field>
              <name>SMP6</name>
              <bitOffset>18</bitOffset>
              <bitWidth>3</bitWidth>
            </field>
            <field>
              <name>SMP7</name>
              <bitOffset>21</bitOffset>
              <bitWidth>3</bitWidth>
            </field>
            <field>
              <name>SMP8</name>
              <bitOffset>24</bitOffset>
              <bitWidth>3</bitWidth>
            </field>
            <field>
              <name>SMP9</name>
              <bitOffset>27</bitOffset>
              <bitWidth>3</bitWidth>
            </field>
          </fields>
        </register>
        <register>
          <name>JOFR1</name>
          <addressOffset>0x18</addressOffset>
          <size>0x20</size>
          <fields>
            <field>
              <name>JOFFSET1</name>
              <bitOffset>0</bitOffset>
              <bitWidth>12</bitWidth>
            </field>
          </fields>
        </register>
        <register>
          <name>JOFR2</name>
          <addressOffset>0x1c</addressOffset>
          <size>0x20</size>
          <fields>
            <field>
              <name>JOFFSET2</name>
              <bitOffset>0</bitOffset>
              <bitWidth>12</bitWidth>
            </field>
          </fields>
        </register>
        <register>
          <name>JOFR3</name>
          <addressOffset>0x20</addressOffset>
          <size>0x20</size>
          <fields>
            <field>
              <name>JOFFSET3</name>
              <bitOffset>0</bitOffset>
              <bitWidth>12</bitWidth>
            </field>
          </fields>
        </register>
        <register>
          <name>JOFR4</name>
          <addressOffset>0x24</addressOffset>
          <size>0x20</size>
          <fields>
            <field>
              <name>JOFFSET4</name>
              <bitOffset>0</bitOffset>
              <bitWidth>12</bitWidth>
            </field>
          </fields>
        </register>
        <register>
          <name>HTR</name>
          <addressOffset>0x28</addressOffset>
          <size>0x20</size>
          <fields>
            <field>
              <name>HT</name>
              <bitOffset>0</bitOffset>
              <bitWidth>12</bitWidth>
            </field>
          </fields>
        </register>
        <register>
          <name>LTR</name>
          <addressOffset>0x2c</addressOffset>
          <size>0x20</size>
          <fields>
            <field>
              <name>LT</name>
              <bitOffset>0</bitOffset>
              <bitWidth>12</bitWidth>
            </field>
          </fields>
        </register>
        <register>
          <name>SQR1</name>
          <addressOffset>0x30</addressOffset>
          <size>0x20</size>
          <fields>
            <field>
              <name>SQ25</name>
              <bitOffset>0</bitOffset>
              <bitWidth>5</bitWidth>
            </field>
            <field>
              <name>SQ26</name>
              <bitOffset>5</bitOffset>
              <bitWidth>5</bitWidth>
            </field>
            <field>
              <name>SQ27</name>
              <bitOffset>10</bitOffset>
              <bitWidth>5</bitWidth>
            </field>
            <field>
              <name>L</name>
              <bitOffset>20</bitOffset>
              <bitWidth>5</bitWidth>
            </field>
          </fields>
        </register>
        <register>
          <name>SQR2</name>
          <addressOffset>0x34</addressOffset>
          <size>0x20</size>
          <fields>
            <field>
              <name>SQ19</name>
              <bitOffset>0</bitOffset>
              <bitWidth>5</bitWidth>
            </field>
            <field>
              <name>SQ20</name>
              <bitOffset>5</bitOffset>
              <bitWidth>5</bitWidth>
            </field>
            <field>
              <name>SQ21</name>
              <bitOffset>10</bitOffset>
              <bitWidth>5</bitWidth>
            </field>
            <field>
              <name>SQ22</name>
              <bitOffset>15</bitOffset>
              <bitWidth>5</bitWidth>
            </field>
            <field>
              <name>SQ23</name>
              <bitOffset>20</bitOffset>
              <bitWidth>5</bitWidth>
            </field>
            <field>
              <name>SQ24</name>
              <bitOffset>25</bitOffset>
              <bitWidth>5</bitWidth>
            </field>
          </fields>
        </register>
        <register>
          <name>SQR3</name>
          <addressOffset>0x38</addressOffset>
          <size>0x20</size>
          <fields>
            <field>
              <name>SQ13</name>
              <bitOffset>0</bitOffset>
              <bitWidth>5</bitWidth>
            </field>
            <field>
              <name>SQ14</name>
              <bitOffset>5</bitOffset>
              <bitWidth>5</bitWidth>
            </field>
            <field>
              <name>SQ15</name>
              <bitOffset>10</bitOffset>
              <bitWidth>5</bitWidth>
            </field>
            <field>
              <name>SQ16</name>
              <bitOffset>15</bitOffset>
              <bitWidth>5</bitWidth>
            </field>
            <field>
              <name>SQ17</name>
              <bitOffset>20</bitOffset>
              <bitWidth>5</bitWidth>
            </field>
            <field>
              <name>SQ18</name>
              <bitOffset>25</bitOffset>
              <bitWidth>5</bitWidth>
            </field>
          </fields>
        </register>
        <register>
          <name>SQR4</name>
          <addressOffset>0x3c</addressOffset>
          <size>0x20</size>
          <fields>
            <field>
              <name>SQ7</name>
              <bitOffset>0</bitOffset>
              <bitWidth>5</bitWidth>
            </field>
            <field>
              <name>SQ8</name>
              <bitOffset>5</bitOffset>
              <bitWidth>5</bitWidth>
            </field>
            <field>
              <name>SQ9</name>
              <bitOffset>10</bitOffset>
              <bitWidth>5</bitWidth>
            </field>
            <field>
              <name>SQ10</name>
              <bitOffset>15</bitOffset>
              <bitWidth>5</bitWidth>
            </field>
            <field>
              <name>SQ11</name>
              <bitOffset>20</bitOffset>
              <bitWidth>5</bitWidth>
            </field>
            <field>
              <name>SQ12</name>
              <bitOffset>25</bitOffset>
              <bitWidth>5</bitWidth>
            </field>
          </fields>
        </register>
        <register>
          <name>SQR5</name>
          <addressOffset>0x40</addressOffset>
          <size>0x20</size>
          <fields>
            <field>
              <name>SQ1</name>
              <bitOffset>0</bitOffset>
              <bitWidth>5</bitWidth>
            </field>
            <field>
              <name>SQ2</name>
              <bitOffset>5</bitOffset>
              <bitWidth>5</bitWidth>
            </field>
            <field>
              <name>SQ3</name>
              <bitOffset>10</bitOffset>
              <bitWidth>5</bitWidth>
            </field>
            <field>
              <name>SQ4</name>
              <bitOffset>15</bitOffset>
              <bitWidth>5</bitWidth>
            </field>
            <field>
              <name>SQ5</name>
              <bitOffset>20</bitOffset>
              <bitWidth>5</bitWidth>
            </field>
            <field>
              <name>SQ6</name>
              <bitOffset>25</bitOffset>
              <bitWidth>5</bitWidth>
            </field>
          </fields>
        </register>
        <register>
          <name>JSQR</name>
          <addressOffset>0x44</addressOffset>
          <size>0x20</size>
          <fields>
            <field>
              <name>JSQ1</name>
              <bitOffset>0</bitOffset>
              <bitWidth>5</bitWidth>
            </field>
            <field>
              <name>JSQ2</name>
              <bitOffset>5</bitOffset>
              <bitWidth>5</bitWidth>
            </field>
            <field>
              <name>JSQ3</name>
              <bitOffset>10</bitOffset>
              <bitWidth>5</bitWidth>
            </field>
            <field>
              <name>JSQ4</name>
              <bitOffset>15</bitOffset>
              <bitWidth>5</bitWidth>
            </field>
            <field>
              <name>JL</name>
              <bitOffset>20</bitOffset>
              <bitWidth>2</bitWidth>
            </field>
          </fields>
        </register>
        <register>
          <name>JDR1</name>
          <addressOffset>0x48</addressOffset>
          <size>0x20</size>
          <fields>
            <field>
              <name>JDATA</name>
              <bitOffset>0</bitOffset>
              <bitWidth>16</bitWidth>
            </field>
          </fields>
        </register>
        <register>
          <name>JDR2</name>
          <addressOffset>0x4c</addressOffset>
          <size>0x20</size>
          <fields>
            <field>
              <name>JDATA</name>
              <bitOffset>0</bitOffset>
              <bitWidth>16</bitWidth>
            </field>
          </fields>
        </register>
        <register>
          <name>JDR3</name>
          <addressOffset>0x50</addressOffset>
          <size>0x20</size>
          <fields>
            <field>
              <name>JDATA</name>
              <bitOffset>0</bitOffset>
              <bitWidth>16</bitWidth>
            </field>
          </fields>
        </register>
        <register>
          <name>JDR4</name>
          <addressOffset>0x54</addressOffset>
          <size>0x20</size>
          <fields>
            <field>
              <name>JDATA</name>
              <bitOffset>0</bitOffset>
              <bitWidth>16</bitWidth>
            </field>
          </fields>
        </register>
        <register>
          <name>DR</name>
          <addressOffset>0x58</addressOffset>
          <size>0x20</size>
          <fields>
            <field>
              <name>DATA</name>
              <bitOffset>0</bitOffset>
              <bitWidth>16</bitWidth>
            </field>
          </fields>
        </register>
        <register>
          <name>CSR</name>
          <addressOffset>0x300</addressOffset>
          <size>0x20</size>
          <fields>
            <field>
              <name>AWD1</name>
              <bitOffset>0</bitOffset>
              <bitWidth>1</bitWidth>
            </field>
            <field>
              <name>EOCS1</name>
              <bitOffset>1</bitOffset>
              <bitWidth>1</bitWidth>
            </field>
            <field>
              <name>JEOS1</name>
              <bitOffset>2</bitOffset>
              <bitWidth>1</bitWidth>
            </field>
            <field>
              <name>JSTRT1</name>
              <bitOffset>3</bitOffset>
              <bitWidth>1</bitWidth>
            </field>
            <field>
              <name>STRT1</name>
              <bitOffset>4</bitOffset>
              <bitWidth>1</bitWidth>
            </field>
            <field>
              <name>OVR1</name>
              <bitOffset>5</bitOffset>
              <bitWidth>1</bitWidth>
            </field>
            <field>
              <name>ADONS1</name>
              <bitOffset>6</bitOffset>
              <bitWidth>1</bitWidth>
            </field>
          </fields>
        </register>
        <register>
          <name>CCR</name>
          <addressOffset>0x304</addressOffset>
          <size>0x20</size>
          <fields>
            <field>
              <name>ADCPRE</name>
              <bitOffset>16</bitOffset>
              <bitWidth>2</bitWidth>
            </field>
            <field>
              <name>TSVREFE</name>
              <bitOffset>23</bitOffset>
              <bitWidth>1</bitWidth>
            </field>
          </fields>
        </register>
      </registers>
    </peripheral>
    <peripheral>
      <name>SPI1</name>
      <baseAddress>0x40013000</baseAddress>
      <registers>
        <register>
          <name>CR1</name>
          <addressOffset>0x0</addressOffset>
          <size>0x20</size>
          <fields>
            <field>
              <name>CPHA</name>
              <bitOffset>0</bitOffset>
              <bitWidth>1</bitWidth>
            </field>
            <field>
              <name>CPOL</name>
              <bitOffset>1</bitOffset>
              <bitWidth>1</bitWidth>
            </field>
            <field>
              <name>MSTR</name>
              <bitOffset>2</bitOffset>
              <bitWidth>1</bitWidth>
            </field>
            <field>
              <name>BR</name>
              <bitOffset>3</bitOffset>
              <bitWidth>3</bitWidth>
            </field>
            <field>
              <name>SPE</name>
              <bitOffset>6</bitOffset>
              <bitWidth>1</bitWidth>
            </field>
            <field>
              <name>LSBFIRST</name>
              <bitOffset>7</bitOffset>
              <bitWidth>1</bitWidth>
            </field>
            <field>
              <name>SSI</name>
              <bitOffset>8</bitOffset>
              <bitWidth>1</bitWidth>
            </field>
            <field>
              <name>SSM</name>
              <bitOffset>9</bitOffset>
              <bitWidth>1</bitWidth>
            </field>
            <field>
              <name>RXONLY</name>
              <bitOffset>10</bitOffset>
              <bitWidth>1</bitWidth>
            </field>
            <field>
              <name>DFF</name>
              <bitOffset>11</bitOffset>
              <bitWidth>1</bitWidth>
            </field>
            <field>
              <name>CRCNEXT</name>
              <bitOffset>12</bitOffset>
              <bitWidth>1</bitWidth>
            </field>
            <field>
              <name>CRCEN</name>
              <bitOffset>13</bitOffset>
              <bitWidth>1</bitWidth>
            </field>
            <field>
              <name>BIDIOE</name>
              <bitOffset>14</bitOffset>
              <bitWidth>1</bitWidth>
            </field>
            <field>
              <name>BIDIMODE</name>
              <bitOffset>15</bitOffset>
              <bitWidth>1</bitWidth>
            </field>
          </fields>
        </register>
        <register>
          <name>CR2</name>
          <addressOffset>0x4</addressOffset>
          <size>0x20</size>
          <fields>
            <field>
              <name>RXDMAEN</name>
              <bitOffset>0</bitOffset>
              <bitWidth>1</bitWidth>
            </field>
            <field>
              <name>TXDMAEN</name>
              <bitOffset>1</bitOffset>
              <bitWidth>1</bitWidth>
            </field>
            <field>
              <name>SSOE</name>
              <bitOffset>2</bitOffset>
              <bitWidth>1</bitWidth>
            </field>
            <field>
              <name>ERRIE</name>
              <bitOffset>5</bitOffset>
              <bitWidth>1</bitWidth>
            </field>
            <field>
              <name>RXNEIE</name>
              <bitOffset>6</bitOffset>
              <bitWidth>1</bitWidth>
            </field>
            <field>
              <name>TXEIE</name>
              <bitOffset>7</bitOffset>
              <bitWidth>1</bitWidth>
            </field>
          </fields>
        </register>
        <register>
          <name>SR</name>
          <addressOffset>0x8</addressOffset>
          <size>0x20</size>
          <fields>
            <field>
              <name>RXNE</name>
              <bitOffset>0</bitOffset>
              <bitWidth>1</bitWidth>
            </field>
            <field>
              <name>TXE</name>
              <bitOffset>1</bitOffset>
              <bitWidth>1</bitWidth>
            </field>
            <field>
              <name>CHSIDE</name>
              <bitOffset>2</bitOffset>
              <bitWidth>1</bitWidth>
            </field>
            <field>
              <name>UDR</name>
              <bitOffset>3</bitOffset>
              <bitWidth>1</bitWidth>
            </field>
            <field>
              <name>CRCERR</name>
              <bitOffset>4</bitOffset>
              <bitWidth>1</bitWidth>
            </field>
            <field>
              <name>MODF</name>
              <bitOffset>5</bitOffset>
              <bitWidth>1</bitWidth>
            </field>
            <field>
              <name>OVR</name>
              <bitOffset>6</bitOffset>
              <bitWidth>1</bitWidth>
            </field>
            <field>
              <name>BSY</name>
              <bitOffset>7</bitOffset>
              <bitWidth>1</bitWidth>
            </field>
            <field>
              <name>FRE</name>
              <bitOffset>8</bitOffset>
              <bitWidth>1</bitWidth>
            </field>
          </fields>
        </register>
        <register>
          <name>DR</name>
          <addressOffset>0xc</addressOffset>
          <size>0x20</size>
          <fields>
            <field>
              <name>DR</name>
              <bitOffset>0</bitOffset>
              <bitWidth>16</bitWidth>
            </field>
          </fields>
        </register>
        <register>
          <name>CRCPR</name>
          <addressOffset>0x10</addressOffset>
          <size>0x20</size>
          <fields>
            <field>
              <name>CRCPOLY</name>
              <bitOffset>0</bitOffset>
              <bitWidth>16</bitWidth>
            </field>
          </fields>
        </register>
        <register>
          <name>RXCRCR</name>
          <addressOffset>0x14</addressOffset>
          <size>0x20</size>
          <fields>
            <field>
              <name>RXCRC</name>
              <bitOffset>0</bitOffset>
              <bitWidth>16</bitWidth>
            </field>
          </fields>
        </register>
        <register>
          <name>TXCRCR</name>
          <addressOffset>0x18</addressOffset>
          <size>0x20</size>
          <fields>
            <field>
              <name>TXCRC</name>
              <bitOffset>0</bitOffset>
              <bitWidth>16</bitWidth>
            </field>
          </fields>
        </register>
      </registers>
    </peripheral>
    <peripheral>
      <name>USART1</name>
      <baseAddress>0x40013800</baseAddress>
      <registers>
        <register>
          <name>SR</name>
          <addressOffset>0x0</addressOffset>
          <size>0x20</size>
          <fields>
            <field>
              <name>PE</name>
              <bitOffset>0</bitOffset>
              <bitWidth>1</bitWidth>
            </field>
            <field>
              <name>FE</name>
              <bitOffset>1</bitOffset>
              <bitWidth>1</bitWidth>
            </field>
            <field>
              <name>NE</name>
              <bitOffset>2</bitOffset>
              <bitWidth>1</bitWidth>
            </field>
            <field>
              <name>ORE</name>
              <bitOffset>3</bitOffset>
              <bitWidth>1</bitWidth>
            </field>
            <field>
              <name>IDLE</name>
              <bitOffset>4</bitOffset>
              <bitWidth>1</bitWidth>
            </field>
            <field>
              <name>RXNE</name>
              <bitOffset>5</bitOffset>
              <bitWidth>1</bitWidth>
            </field>
            <field>
              <name>TC</name>
              <bitOffset>6</bitOffset>
              <bitWidth>1</bitWidth>
            </field>
            <field>
              <name>TXE</name>
              <bitOffset>7</bitOffset>
              <bitWidth>1</bitWidth>
            </field>
            <field>
              <name>LBD</name>
              <bitOffset>8</bitOffset>
              <bitWidth>1</bitWidth>
            </field>
            <field>
              <name>CTS</name>
              <bitOffset>9</bitOffset>
              <bitWidth>1</bitWidth>
            </field>
          </fields>
        </register>
        <register>
          <name>DR</name>
          <addressOffset>0x4</addressOffset>
          <size>0x20</size>
          <fields>
            <field>
              <name>DR</name>
              <bitOffset>0</bitOffset>
              <bitWidth>9</bitWidth>
            </field>
          </fields>
        </register>
        <register>
          <name>BRR</name>
          <addressOffset>0x8</addressOffset>
          <size>0x20</size>
          <fields>
            <field>
              <name>DIV_FRACTION</name>
              <bitOffset>0</bitOffset>
              <bitWidth>4</bitWidth>
            </field>
            <field>
              <name>DIV_MANTISSA</name>
              <bitOffset>4</bitOffset>
              <bitWidth>12</bitWidth>
            </field>
          </fields>
        </register>
        <register>
          <name>CR1</name>
          <addressOffset>0xc</addressOffset>
          <size>0x20</size>
          <fields>
            <field>
              <name>SBK</name>
              <bitOffset>0</bitOffset>
              <bitWidth>1</bitWidth>
            </field>
            <field>
              <name>RWU</name>
              <bitOffset>1</bitOffset>
              <bitWidth>1</bitWidth>
            </field>
            <field>
              <name>RE</name>
              <bitOffset>2</bitOffset>
              <bitWidth>1</bitWidth>
            </field>
            <field>
              <name>TE</name>
              <bitOffset>3</bitOffset>
              <bitWidth>1</bitWidth>
            </field>
            <field>
              <name>IDLEIE</name>
              <bitOffset>4</bitOffset>
              <bitWidth>1</bitWidth>
            </field>
            <field>
              <name>RXNEIE</name>
              <bitOffset>5</bitOffset>
              <bitWidth>1</bitWidth>
            </field>
            <field>
              <name>TCIE</name>
              <bitOffset>6</bitOffset>
              <bitWidth>1</bitWidth>
            </field>
            <field>
              <name>TXEIE</name>
              <bitOffset>7</bitOffset>
              <bitWidth>1</bitWidth>
            </field>
            <field>
              <name>PEIE</name>
              <bitOffset>8</bitOffset>
              <bitWidth>1</bitWidth>
            </field>
            <field>
              <name>PS</name>
              <bitOffset>9</bitOffset>
              <bitWidth>1</bitWidth>
            </field>
            <field>
              <name>PCE</name>
              <bitOffset>10</bitOffset>
              <bitWidth>1</bitWidth>
            </field>
            <field>
              <name>WAKE</name>
              <bitOffset>11</bitOffset>
              <bitWidth>1</bitWidth>
            </field>
            <field>
              <name>M</name>
              <bitOffset>12</bitOffset>
              <bitWidth>1</bitWidth>
            </field>
            <field>
              <name>UE</name>
              <bitOffset>13</bitOffset>
              <bitWidth>1</bitWidth>
            </field>
            <field>
              <name>OVER8</name>
              <bitOffset>15</bitOffset>
              <bitWidth>1</bitWidth>
            </field>
          </fields>
        </register>
        <register>
          <name>CR2</name>
          <addressOffset>0x10</addressOffset>
          <size>0x20</size>
          <fields>
            <field>
              <name>ADD</name>
              <bitOffset>0</bitOffset>
              <bitWidth>4</bitWidth>
            </field>
            <field>
              <name>LBDL</name>
              <bitOffset>5</bitOffset>
              <bitWidth>1</bitWidth>
            </field>
            <field>
              <name>LBDIE</name>
              <bitOffset>6</bitOffset>
              <bitWidth>1</bitWidth>
            </field>
            <field>
              <name>LBCL</name>
              <bitOffset>8</bitOffset>
              <bitWidth>1</bitWidth>
            </field>
            <field>
              <name>CPHA</name>
              <bitOffset>9</bitOffset>
              <bitWidth>1</bitWidth>
            </field>
            <field>
              <name>CPOL</name>
              <bitOffset>10</bitOffset>
              <bitWidth>1</bitWidth>
            </field>
            <field>
              <name>CLKEN</name>
              <bitOffset>11</bitOffset>
              <bitWidth>1</bitWidth>
            </field>
            <field>
              <name>STOP</name>
              <bitOffset>12</bitOffset>
              <bitWidth>2</bitWidth>
            </field>
            <field>
              <name>LINEN</name>
              <bitOffset>14</bitOffset>
              <bitWidth>1</bitWidth>
            </field>
          </fields>
        </register>
        <register>
          <name>CR3</name>
          <addressOffset>0x14</addressOffset>
          <size>0x20</size>
          <fields>
            <field>
              <name>EIE</name>
              <bitOffset>0</bitOffset>
              <bitWidth>1</bitWidth>
            </field>
            <field>
              <name>IREN</name>
              <bitOffset>1</bitOffset>
              <bitWidth>1</bitWidth>
            </field>
            <field>
              <name>IRLP</name>
              <bitOffset>2</bitOffset>
              <bitWidth>1</bitWidth>
            </field>
            <field>
              <name>HDSEL</name>
              <bitOffset>3</bitOffset>
              <bitWidth>1</bitWidth>
            </field>
            <field>
              <name>NACK</name>
              <bitOffset>4</bitOffset>
              <bitWidth>1</bitWidth>
            </field>
            <field>
              <name>SCEN</name>
              <bitOffset>5</bitOffset>
              <bitWidth>1</bitWidth>
            </field>
            <field>
              <name>DMAR</name>
              <bitOffset>6</bitOffset>
              <bitWidth>1</bitWidth>
            </field>
            <field>
              <name>DMAT</name>
              <bitOffset>7</bitOffset>
              <bitWidth>1</bitWidth>
            </field>
            <field>
              <name>RTSE</name>
              <bitOffset>8</bitOffset>
              <bitWidth>1</bitWidth>
            </field>
            <field>
              <name>CTSE</name>
              <bitOffset>9</bitOffset>
              <bitWidth>1</bitWidth>
            </field>
            <field>
              <name>CTSIE</name>
              <bitOffset>10</bitOffset>
              <bitWidth>1</bitWidth>
            </field>
            <field>
              <name>ONEBIT</name>
              <bitOffset>11</bitOffset>
              <bitWidth>1</bitWidth>
            </field>
          </fields>
        </register>
        <register>
          <name>GTPR</name>
          <addressOffset>0x18</addressOffset>
          <size>0x20</size>
          <fields>
            <field>
              <name>PSC</name>
              <bitOffset>0</bitOffset>
              <bitWidth>8</bitWidth>
            </field>
            <field>
              <name>GT</name>
              <bitOffset>8</bitOffset>
              <bitWidth>8</bitWidth>
            </field>
          </fields>
        </register>
      </registers>
    </peripheral>
    <peripheral>
      <name>GPIOA</name>
      <baseAddress>0x40020000</baseAddress>
      <registers>
        <register>
          <name>MODER</name>
          <addressOffset>0x0</addressOffset>
          <size>0x20</size>
          <fields>
            <field>
              <name>MODER0</name>
              <bitOffset>0</bitOffset>
              <bitWidth>2</bitWidth>
            </field>
            <field>
              <name>MODER1</name>
              <bitOffset>2</bitOffset>
              <bitWidth>2</bitWidth>
            </field>
            <field>
              <name>MODER2</name>
              <bitOffset>4</bitOffset>
              <bitWidth>2</bitWidth>
            </field>
            <field>
              <name>MODER3</name>
              <bitOffset>6</bitOffset>
              <bitWidth>2</bitWidth>
            </field>
            <field>
              <name>MODER4</name>
              <bitOffset>8</bitOffset>
              <bitWidth>2</bitWidth>
            </field>
            <field>
              <name>MODER5</name>
              <bitOffset>10</bitOffset>
              <bitWidth>2</bitWidth>
            </field>
            <field>
              <name>MODER6</name>
              <bitOffset>12</bitOffset>
              <bitWidth>2</bitWidth>
            </field>
            <field>
              <name>MODER7</name>
              <bitOffset>14</bitOffset>
              <bitWidth>2</bitWidth>
            </field>
            <field>
              <name>MODER8</name>
              <bitOffset>16</bitOffset>
              <bitWidth>2</bitWidth>
            </field>
            <field>
              <name>MODER9</name>
              <bitOffset>18</bitOffset>
              <bitWidth>2</bitWidth>
            </field>
            <field>
              <name>MODER10</name>
              <bitOffset>20</bitOffset>
              <bitWidth>2</bitWidth>
            </field>
            <field>
              <name>MODER11</name>
              <bitOffset>22</bitOffset>
              <bitWidth>2</bitWidth>
            </field>
            <field>
              <name>MODER12</name>
              <bitOffset>24</bitOffset>
              <bitWidth>2</bitWidth>
            </field>
            <field>
              <name>MODER13</name>
              <bitOffset>26</bitOffset>
              <bitWidth>2</bitWidth>
            </field>
            <field>
              <name>MODER14</name>
              <bitOffset>28</bitOffset>
              <bitWidth>2</bitWidth>
            </field>
            <field>
              <name>MODER15</name>
              <bitOffset>30</bitOffset>
              <bitWidth>2</bitWidth>
            </field>
          </fields>
        </register>
        <register>
          <name>OTYPER</name>
          <addressOffset>0x4</addressOffset>
          <size>0x20</size>
        </register>
        <register>
          <name>OSPEEDR</name>
          <addressOffset>0x8</addressOffset>
          <size>0x20</size>
        </register>
        <register>
          <name>PUPDR</name>
          <addressOffset>0xc</addressOffset>
          <size>0x20</size>
          <fields>
            <field>
              <name>PUPDR0</name>
              <bitOffset>0</bitOffset>
              <bitWidth>2</bitWidth>
            </field>
            <field>
              <name>PUPDR1</name>
              <bitOffset>2</bitOffset>
              <bitWidth>2</bitWidth>
            </field>
            <field>
              <name>PUPDR2</name>
              <bitOffset>4</bitOffset>
              <bitWidth>2</bitWidth>
            </field>
            <field>
              <name>PUPDR3</name>
              <bitOffset>6</bitOffset>
              <bitWidth>2</bitWidth>
            </field>
            <field>
              <name>PUPDR4</name>
              <bitOffset>8</bitOffset>
              <bitWidth>2</bitWidth>
            </field>
            <field>
              <name>PUPDR5</name>
              <bitOffset>10</bitOffset>
              <bitWidth>2</bitWidth>
            </field>
            <field>
              <name>PUPDR6</name>
              <bitOffset>12</bitOffset>
              <bitWidth>2</bitWidth>
            </field>
            <field>
              <name>PUPDR7</name>
              <bitOffset>14</bitOffset>
              <bitWidth>2</bitWidth>
            </field>
            <field>
              <name>PUPDR8</name>
              <bitOffset>16</bitOffset>
              <bitWidth>2</bitWidth>
            </field>
            <field>
              <name>PUPDR9</name>
              <bitOffset>18</bitOffset>
              <bitWidth>2</bitWidth>
            </field>
            <field>
              <name>PUPDR10</name>
              <bitOffset>20</bitOffset>
              <bitWidth>2</bitWidth>
            </field>
            <field>
              <name>PUPDR11</name>
              <bitOffset>22</bitOffset>
              <bitWidth>2</bitWidth>
            </field>
            <field>
              <name>PUPDR12</name>
              <bitOffset>24</bitOffset>
              <bitWidth>2</bitWidth>
            </field>
            <field>
              <name>PUPDR13</name>
              <bitOffset>26</bitOffset>
              <bitWidth>2</bitWidth>
            </field>
            <field>
              <name>PUPDR14</name>
              <bitOffset>28</bitOffset>
              <bitWidth>2</bitWidth>
            </field>
            <field>
              <name>PUPDR15</name>
              <bitOffset>30</bitOffset>
              <bitWidth>2</bitWidth>
            </field>
          </fields>
        </register>
        <register>
          <name>IDR</name>
          <addressOffset>0x10</addressOffset>
          <size>0x20</size>
        </register>
        <register>
          <name>ODR</name>
          <addressOffset>0x14</addressOffset>
          <size>0x20</size>
        </register>
        <register>
          <name>BSRR</name>
          <addressOffset>0x18</addressOffset>
          <size>0x20</size>
        </register>
        <register>
          <name>LCKR</name>
          <addressOffset>0x1c</addressOffset>
          <size>0x20</size>
          <fields>
            <field>
              <name>LCK0</name>
              <bitOffset>0</bitOffset>
              <bitWidth>1</bitWidth>
            </field>
            <field>
              <name>LCK1</name>
              <bitOffset>1</bitOffset>
              <bitWidth>1</bitWidth>
            </field>
            <field>
              <name>LCK2</name>
              <bitOffset>2</bitOffset>
              <bitWidth>1</bitWidth>
            </field>
            <field>
              <name>LCK3</name>
              <bitOffset>3</bitOffset>
              <bitWidth>1</bitWidth>
            </field>
            <field>
              <name>LCK4</name>
              <bitOffset>4</bitOffset>
              <bitWidth>1</bitWidth>
            </field>
            <field>
              <name>LCK5</name>
              <bitOffset>5</bitOffset>
              <bitWidth>1</bitWidth>
            </field>
            <field>
              <name>LCK6</name>
              <bitOffset>6</bitOffset>
              <bitWidth>1</bitWidth>
            </field>
            <field>
              <name>LCK7</name>
              <bitOffset>7</bitOffset>
              <bitWidth>1</bitWidth>
            </field>
            <field>
              <name>LCK8</name>
              <bitOffset>8</bitOffset>
              <bitWidth>1</bitWidth>
            </field>
            <field>
              <name>LCK9</name>
              <bitOffset>9</bitOffset>
              <bitWidth>1</bitWidth>
            </field>
            <field>
              <name>LCK10</name>
              <bitOffset>10</bitOffset>
              <bitWidth>1</bitWidth>
            </field>
            <field>
              <name>LCK11</name>
              <bitOffset>11</bitOffset>
              <bitWidth>1</bitWidth>
            </field>
            <field>
              <name>LCK12</name>
              <bitOffset>12</bitOffset>
              <bitWidth>1</bitWidth>
            </field>
            <field>
              <name>LCK13</name>
              <bitOffset>13</bitOffset>
              <bitWidth>1</bitWidth>
            </field>
            <field>
              <name>LCK14</name>
              <bitOffset>14</bitOffset>
              <bitWidth>1</bitWidth>
            </field>
            <field>
              <name>LCK15</name>
              <bitOffset>15</bitOffset>
              <bitWidth>1</bitWidth>
            </field>
            <field>
              <name>LCKK</name>
              <bitOffset>16</bitOffset>
              <bitWidth>1</bitWidth>
            </field>
          </fields>
        </register>
        <register>
          <name>AFR.0</name>
          <addressOffset>0x20</addressOffset>
          <size>0x20</size>
          <fields>
            <field>
              <name>AFSEL0</name>
              <bitOffset>0</bitOffset>
              <bitWidth>4</bitWidth>
            </field>
            <field>
              <name>AFSEL1</name>
              <bitOffset>4</bitOffset>
              <bitWidth>4</bitWidth>
            </field>
            <field>
              <name>AFSEL2</name>
              <bitOffset>8</bitOffset>
              <bitWidth>4</bitWidth>
            </field>
            <field>
              <name>AFSEL3</name>
              <bitOffset>12</bitOffset>
              <bitWidth>4</bitWidth>
            </field>
            <field>
              <name>AFSEL4</name>
              <bitOffset>16</bitOffset>
              <bitWidth>4</bitWidth>
            </field>
            <field>
              <name>AFSEL5</name>
              <bitOffset>20</bitOffset>
              <bitWidth>4</bitWidth>
            </field>
            <field>
              <name>AFSEL6</name>
              <bitOffset>24</bitOffset>
              <bitWidth>4</bitWidth>
            </field>
            <field>
              <name>AFSEL7</name>
              <bitOffset>28</bitOffset>
              <bitWidth>4</bitWidth>
            </field>
          </fields>
        </register>
        <register>
          <name>AFR.1</name>
          <addressOffset>0x24</addressOffset>
          <size>0x20</size>
          <fields>
            <field>
              <name>AFSEL8</name>
              <bitOffset>0</bitOffset>
              <bitWidth>4</bitWidth>
            </field>
            <field>
              <name>AFSEL9</name>
              <bitOffset>4</bitOffset>
              <bitWidth>4</bitWidth>
            </field>
            <field>
              <name>AFSEL10</name>
              <bitOffset>8</bitOffset>
              <bitWidth>4</bitWidth>
            </field>
            <field>
              <name>AFSEL11</name>
              <bitOffset>12</bitOffset>
              <bitWidth>4</bitWidth>
            </field>
            <field>
              <name>AFSEL12</name>
              <bitOffset>16</bitOffset>
              <bitWidth>4</bitWidth>
            </field>
            <field>
              <name>AFSEL13</name>
              <bitOffset>20</bitOffset>
              <bitWidth>4</bitWidth>
            </field>
            <field>
              <name>AFSEL14</name>
              <bitOffset>24</bitOffset>
              <bitWidth>4</bitWidth>
            </field>
            <field>
              <name>AFSEL15</name>
              <bitOffset>28</bitOffset>
              <bitWidth>4</bitWidth>
            </field>
          </fields>
        </register>
      </registers>
    </peripheral>
    <peripheral>
      <name>GPIOB</name>
      <baseAddress>0x40020400</baseAddress>
      <registers>
        <register>
          <name>MODER</name>
          <addressOffset>0x0</addressOffset>
          <size>0x20</size>
          <fields>
            <field>
              <name>MODER0</name>
              <bitOffset>0</bitOffset>
              <bitWidth>2</bitWidth>
            </field>
            <field>
              <name>MODER1</name>
              <bitOffset>2</bitOffset>
              <bitWidth>2</bitWidth>
            </field>
            <field>
              <name>MODER2</name>
              <bitOffset>4</bitOffset>
              <bitWidth>2</bitWidth>
            </field>
            <field>
              <name>MODER3</name>
              <bitOffset>6</bitOffset>
              <bitWidth>2</bitWidth>
            </field>
            <field>
              <name>MODER4</name>
              <bitOffset>8</bitOffset>
              <bitWidth>2</bitWidth>
            </field>
            <field>
              <name>MODER5</name>
              <bitOffset>10</bitOffset>
              <bitWidth>2</bitWidth>
            </field>
            <field>
              <name>MODER6</name>
              <bitOffset>12</bitOffset>
              <bitWidth>2</bitWidth>
            </field>
            <field>
              <name>MODER7</name>
              <bitOffset>14</bitOffset>
              <bitWidth>2</bitWidth>
            </field>
            <field>
              <name>MODER8</name>
              <bitOffset>16</bitOffset>
              <bitWidth>2</bitWidth>
            </field>
            <field>
              <name>MODER9</name>
              <bitOffset>18</bitOffset>
              <bitWidth>2</bitWidth>
            </field>
            <field>
              <name>MODER10</name>
              <bitOffset>20</bitOffset>
              <bitWidth>2</bitWidth>
            </field>
            <field>
              <name>MODER11</name>
              <bitOffset>22</bitOffset>
              <bitWidth>2</bitWidth>
            </field>
            <field>
              <name>MODER12</name>
              <bitOffset>24</bitOffset>
              <bitWidth>2</bitWidth>
            </field>
            <field>
              <name>MODER13</name>
              <bitOffset>26</bitOffset>
              <bitWidth>2</bitWidth>
            </field>
            <field>
              <name>MODER14</name>
              <bitOffset>28</bitOffset>
              <bitWidth>2</bitWidth>
            </field>
            <field>
              <name>MODER15</name>
              <bitOffset>30</bitOffset>
              <bitWidth>2</bitWidth>
            </field>
          </fields>
        </register>
        <register>
          <name>OTYPER</name>
          <addressOffset>0x4</addressOffset>
          <size>0x20</size>
        </register>
        <register>
          <name>OSPEEDR</name>
          <addressOffset>0x8</addressOffset>
          <size>0x20</size>
        </register>
        <register>
          <name>PUPDR</name>
          <addressOffset>0xc</addressOffset>
          <size>0x20</size>
          <fields>
            <field>
              <name>PUPDR0</name>
              <bitOffset>0</bitOffset>
              <bitWidth>2</bitWidth>
            </field>
            <field>
              <name>PUPDR1</name>
              <bitOffset>2</bitOffset>
              <bitWidth>2</bitWidth>
            </field>
            <field>
              <name>PUPDR2</name>
              <bitOffset>4</bitOffset>
              <bitWidth>2</bitWidth>
            </field>
            <field>
              <name>PUPDR3</name>
              <bitOffset>6</bitOffset>
              <bitWidth>2</bitWidth>
            </field>
            <field>
              <name>PUPDR4</name>
              <bitOffset>8</bitOffset>
              <bitWidth>2</bitWidth>
            </field>
            <field>
              <name>PUPDR5</name>
              <bitOffset>10</bitOffset>
              <bitWidth>2</bitWidth>
            </field>
            <field>
              <name>PUPDR6</name>
              <bitOffset>12</bitOffset>
              <bitWidth>2</bitWidth>
            </field>
            <field>
              <name>PUPDR7</name>
              <bitOffset>14</bitOffset>
              <bitWidth>2</bitWidth>
            </field>
            <field>
              <name>PUPDR8</name>
              <bitOffset>16</bitOffset>
              <bitWidth>2</bitWidth>
            </field>
            <field>
              <name>PUPDR9</name>
              <bitOffset>18</bitOffset>
              <bitWidth>2</bitWidth>
            </field>
            <field>
              <name>PUPDR10</name>
              <bitOffset>20</bitOffset>
              <bitWidth>2</bitWidth>
            </field>
            <field>
              <name>PUPDR11</name>
              <bitOffset>22</bitOffset>
              <bitWidth>2</bitWidth>
            </field>
            <field>
              <name>PUPDR12</name>
              <bitOffset>24</bitOffset>
              <bitWidth>2</bitWidth>
            </field>
            <field>
              <name>PUPDR13</name>
              <bitOffset>26</bitOffset>
              <bitWidth>2</bitWidth>
            </field>
            <field>
              <name>PUPDR14</name>
              <bitOffset>28</bitOffset>
              <bitWidth>2</bitWidth>
            </field>
            <field>
              <name>PUPDR15</name>
              <bitOffset>30</bitOffset>
              <bitWidth>2</bitWidth>
            </field>
          </fields>
        </register>
        <register>
          <name>IDR</name>
          <addressOffset>0x10</addressOffset>
          <size>0x20</size>
        </register>
        <register>
          <name>ODR</name>
          <addressOffset>0x14</addressOffset>
          <size>0x20</size>
        </register>
        <register>
          <name>BSRR</name>
          <addressOffset>0x18</addressOffset>
          <size>0x20</size>
        </register>
        <register>
          <name>LCKR</name>
          <addressOffset>0x1c</addressOffset>
          <size>0x20</size>
          <fields>
            <field>
              <name>LCK0</name>
              <bitOffset>0</bitOffset>
              <bitWidth>1</bitWidth>
            </field>
            <field>
              <name>LCK1</name>
              <bitOffset>1</bitOffset>
              <bitWidth>1</bitWidth>
            </field>
            <field>
              <name>LCK2</name>
              <bitOffset>2</bitOffset>
              <bitWidth>1</bitWidth>
            </field>
            <field>
              <name>LCK3</name>
              <bitOffset>3</bitOffset>
              <bitWidth>1</bitWidth>
            </field>
            <field>
              <name>LCK4</name>
              <bitOffset>4</bitOffset>
              <bitWidth>1</bitWidth>
            </field>
            <field>
              <name>LCK5</name>
              <bitOffset>5</bitOffset>
              <bitWidth>1</bitWidth>
            </field>
            <field>
              <name>LCK6</name>
              <bitOffset>6</bitOffset>
              <bitWidth>1</bitWidth>
            </field>
            <field>
              <name>LCK7</name>
              <bitOffset>7</bitOffset>
              <bitWidth>1</bitWidth>
            </field>
            <field>
              <name>LCK8</name>
              <bitOffset>8</bitOffset>
              <bitWidth>1</bitWidth>
            </field>
            <field>
              <name>LCK9</name>
              <bitOffset>9</bitOffset>
              <bitWidth>1</bitWidth>
            </field>
            <field>
              <name>LCK10</name>
              <bitOffset>10</bitOffset>
              <bitWidth>1</bitWidth>
            </field>
            <field>
              <name>LCK11</name>
              <bitOffset>11</bitOffset>
              <bitWidth>1</bitWidth>
            </field>
            <field>
              <name>LCK12</name>
              <bitOffset>12</bitOffset>
              <bitWidth>1</bitWidth>
            </field>
            <field>
              <name>LCK13</name>
              <bitOffset>13</bitOffset>
              <bitWidth>1</bitWidth>
            </field>
            <field>
              <name>LCK14</name>
              <bitOffset>14</bitOffset>
              <bitWidth>1</bitWidth>
            </field>
            <field>
              <name>LCK15</name>
              <bitOffset>15</bitOffset>
              <bitWidth>1</bitWidth>
            </field>
            <field>
              <name>LCKK</name>
              <bitOffset>16</bitOffset>
              <bitWidth>1</bitWidth>
            </field>
          </fields>
        </register>
        <register>
          <name>AFR.0</name>
          <addressOffset>0x20</addressOffset>
          <size>0x20</size>
          <fields>
            <field>
              <name>AFSEL0</name>
              <bitOffset>0</bitOffset>
              <bitWidth>4</bitWidth>
            </field>
            <field>
              <name>AFSEL1</name>
              <bitOffset>4</bitOffset>
              <bitWidth>4</bitWidth>
            </field>
            <field>
              <name>AFSEL2</name>
              <bitOffset>8</bitOffset>
              <bitWidth>4</bitWidth>
            </field>
            <field>
              <name>AFSEL3</name>
              <bitOffset>12</bitOffset>
              <bitWidth>4</bitWidth>
            </field>
            <field>
              <name>AFSEL4</name>
              <bitOffset>16</bitOffset>
              <bitWidth>4</bitWidth>
            </field>
            <field>
              <name>AFSEL5</name>
              <bitOffset>20</bitOffset>
              <bitWidth>4</bitWidth>
            </field>
            <field>
              <name>AFSEL6</name>
              <bitOffset>24</bitOffset>
              <bitWidth>4</bitWidth>
            </field>
            <field>
              <name>AFSEL7</name>
              <bitOffset>28</bitOffset>
              <bitWidth>4</bitWidth>
            </field>
          </fields>
        </register>
        <register>
          <name>AFR.1</name>
          <addressOffset>0x24</addressOffset>
          <size>0x20</size>
          <fields>
            <field>
              <name>AFSEL8</name>
              <bitOffset>0</bitOffset>
              <bitWidth>4</bitWidth>
            </field>
            <field>
              <name>AFSEL9</name>
              <bitOffset>4</bitOffset>
              <bitWidth>4</bitWidth>
            </field>
            <field>
              <name>AFSEL10</name>
              <bitOffset>8</bitOffset>
              <bitWidth>4</bitWidth>
            </field>
            <field>
              <name>AFSEL11</name>
              <bitOffset>12</bitOffset>
              <bitWidth>4</bitWidth>
            </field>
            <field>
              <name>AFSEL12</name>
              <bitOffset>16</bitOffset>
              <bitWidth>4</bitWidth>
            </field>
            <field>
              <name>AFSEL13</name>
              <bitOffset>20</bitOffset>
              <bitWidth>4</bitWidth>
            </field>
            <field>
              <name>AFSEL14</name>
              <bitOffset>24</bitOffset>
              <bitWidth>4</bitWidth>
            </field>
            <field>
              <name>AFSEL15</name>
              <bitOffset>28</bitOffset>
              <bitWidth>4</bitWidth>
            </field>
          </fields>
        </register>
      </registers>
    </peripheral>
    <peripheral>
      <name>GPIOC</name>
      <baseAddress>0x40020800</baseAddress>
      <registers>
        <register>
          <name>MODER</name>
          <addressOffset>0x0</addressOffset>
          <size>0x20</size>
          <fields>
            <field>
              <name>MODER0</name>
              <bitOffset>0</bitOffset>
              <bitWidth>2</bitWidth>
            </field>
            <field>
              <name>MODER1</name>
              <bitOffset>2</bitOffset>
              <bitWidth>2</bitWidth>
            </field>
            <field>
              <name>MODER2</name>
              <bitOffset>4</bitOffset>
              <bitWidth>2</bitWidth>
            </field>
            <field>
              <name>MODER3</name>
              <bitOffset>6</bitOffset>
              <bitWidth>2</bitWidth>
            </field>
            <field>
              <name>MODER4</name>
              <bitOffset>8</bitOffset>
              <bitWidth>2</bitWidth>
            </field>
            <field>
              <name>MODER5</name>
              <bitOffset>10</bitOffset>
              <bitWidth>2</bitWidth>
            </field>
            <field>
              <name>MODER6</name>
              <bitOffset>12</bitOffset>
              <bitWidth>2</bitWidth>
            </field>
            <field>
              <name>MODER7</name>
              <bitOffset>14</bitOffset>
              <bitWidth>2</bitWidth>
            </field>
            <field>
              <name>MODER8</name>
              <bitOffset>16</bitOffset>
              <bitWidth>2</bitWidth>
            </field>
            <field>
              <name>MODER9</name>
              <bitOffset>18</bitOffset>
              <bitWidth>2</bitWidth>
            </field>
            <field>
              <name>MODER10</name>
              <bitOffset>20</bitOffset>
              <bitWidth>2</bitWidth>
            </field>
            <field>
              <name>MODER11</name>
              <bitOffset>22</bitOffset>
              <bitWidth>2</bitWidth>
            </field>
            <field>
              <name>MODER12</name>
              <bitOffset>24</bitOffset>
              <bitWidth>2</bitWidth>
            </field>
            <field>
              <name>MODER13</name>
              <bitOffset>26</bitOffset>
              <bitWidth>2</bitWidth>
            </field>
            <field>
              <name>MODER14</name>
              <bitOffset>28</bitOffset>
              <bitWidth>2</bitWidth>
            </field>
            <field>
              <name>MODER15</name>
              <bitOffset>30</bitOffset>
              <bitWidth>2</bitWidth>
            </field>
          </fields>
        </register>
        <register>
          <name>OTYPER</name>
          <addressOffset>0x4</addressOffset>
          <size>0x20</size>
        </register>
        <register>
          <name>OSPEEDR</name>
          <addressOffset>0x8</addressOffset>
          <size>0x20</size>
        </register>
        <register>
          <name>PUPDR</name>
          <addressOffset>0xc</addressOffset>
          <size>0x20</size>
          <fields>
            <field>
              <name>PUPDR0</name>
              <bitOffset>0</bitOffset>
              <bitWidth>2</bitWidth>
            </field>
            <field>
              <name>PUPDR1</name>
              <bitOffset>2</bitOffset>
              <bitWidth>2</bitWidth>
            </field>
            <field>
              <name>PUPDR2</name>
              <bitOffset>4</bitOffset>
              <bitWidth>2</bitWidth>
            </field>
            <field>
              <name>PUPDR3</name>
              <bitOffset>6</bitOffset>
              <bitWidth>2</bitWidth>
            </field>
            <field>
              <name>PUPDR4</name>
              <bitOffset>8</bitOffset>
              <bitWidth>2</bitWidth>
            </field>
            <field>
              <name>PUPDR5</name>
              <bitOffset>10</bitOffset>
              <bitWidth>2</bitWidth>
            </field>
            <field>
              <name>PUPDR6</name>
              <bitOffset>12</bitOffset>
              <bitWidth>2</bitWidth>
            </field>
            <field>
              <name>PUPDR7</name>
              <bitOffset>14</bitOffset>
              <bitWidth>2</bitWidth>
            </field>
            <field>
              <name>PUPDR8</name>
              <bitOffset>16</bitOffset>
              <bitWidth>2</bitWidth>
            </field>
            <field>
              <name>PUPDR9</name>
              <bitOffset>18</bitOffset>
              <bitWidth>2</bitWidth>
            </field>
            <field>
              <name>PUPDR10</name>
              <bitOffset>20</bitOffset>
              <bitWidth>2</bitWidth>
            </field>
            <field>
              <name>PUPDR11</name>
              <bitOffset>22</bitOffset>
              <bitWidth>2</bitWidth>
            </field>
            <field>
              <name>PUPDR12</name>
              <bitOffset>24</bitOffset>
              <bitWidth>2</bitWidth>
            </field>
            <field>
              <name>PUPDR13</name>
              <bitOffset>26</bitOffset>
              <bitWidth>2</bitWidth>
            </field>
            <field>
              <name>PUPDR14</name>
              <bitOffset>28</bitOffset>
              <bitWidth>2</bitWidth>
            </field>
            <field>
              <name>PUPDR15</name>
              <bitOffset>30</bitOffset>
              <bitWidth>2</bitWidth>
            </field>
          </fields>
        </register>
        <register>
          <name>IDR</name>
          <addressOffset>0x10</addressOffset>
          <size>0x20</size>
        </register>
        <register>
          <name>ODR</name>
          <addressOffset>0x14</addressOffset>
          <size>0x20</size>
        </register>
        <register>
          <name>BSRR</name>
          <addressOffset>0x18</addressOffset>
          <size>0x20</size>
        </register>
        <register>
          <name>LCKR</name>
          <addressOffset>0x1c</addressOffset>
          <size>0x20</size>
          <fields>
            <field>
              <name>LCK0</name>
              <bitOffset>0</bitOffset>
              <bitWidth>1</bitWidth>
            </field>
            <field>
              <name>LCK1</name>
              <bitOffset>1</bitOffset>
              <bitWidth>1</bitWidth>
            </field>
            <field>
              <name>LCK2</name>
              <bitOffset>2</bitOffset>
              <bitWidth>1</bitWidth>
            </field>
            <field>
              <name>LCK3</name>
              <bitOffset>3</bitOffset>
              <bitWidth>1</bitWidth>
            </field>
            <field>
              <name>LCK4</name>
              <bitOffset>4</bitOffset>
              <bitWidth>1</bitWidth>
            </field>
            <field>
              <name>LCK5</name>
              <bitOffset>5</bitOffset>
              <bitWidth>1</bitWidth>
            </field>
            <field>
              <name>LCK6</name>
              <bitOffset>6</bitOffset>
              <bitWidth>1</bitWidth>
            </field>
            <field>
              <name>LCK7</name>
              <bitOffset>7</bitOffset>
              <bitWidth>1</bitWidth>
            </field>
            <field>
              <name>LCK8</name>
              <bitOffset>8</bitOffset>
              <bitWidth>1</bitWidth>
            </field>
            <field>
              <name>LCK9</name>
              <bitOffset>9</bitOffset>
              <bitWidth>1</bitWidth>
            </field>
            <field>
              <name>LCK10</name>
              <bitOffset>10</bitOffset>
              <bitWidth>1</bitWidth>
            </field>
            <field>
              <name>LCK11</name>
              <bitOffset>11</bitOffset>
              <bitWidth>1</bitWidth>
            </field>
            <field>
              <name>LCK12</name>
              <bitOffset>12</bitOffset>
              <bitWidth>1</bitWidth>
            </field>
            <field>
              <name>LCK13</name>
              <bitOffset>13</bitOffset>
              <bitWidth>1</bitWidth>
            </field>
            <field>
              <name>LCK14</name>
              <bitOffset>14</bitOffset>
              <bitWidth>1</bitWidth>
            </field>
            <field>
              <name>LCK15</name>
              <bitOffset>15</bitOffset>
              <bitWidth>1</bitWidth>
            </field>
            <field>
              <name>LCKK</name>
              <bitOffset>16</bitOffset>
              <bitWidth>1</bitWidth>
            </field>
          </fields>
        </register>
        <register>
          <name>AFR.0</name>
          <addressOffset>0x20</addressOffset>
          <size>0x20</size>
          <fields>
            <field>
              <name>AFSEL0</name>
              <bitOffset>0</bitOffset>
              <bitWidth>4</bitWidth>
            </field>
            <field>
              <name>AFSEL1</name>
              <bitOffset>4</bitOffset>
              <bitWidth>4</bitWidth>
            </field>
            <field>
              <name>AFSEL2</name>
              <bitOffset>8</bitOffset>
              <bitWidth>4</bitWidth>
            </field>
            <field>
              <name>AFSEL3</name>
              <bitOffset>12</bitOffset>
              <bitWidth>4</bitWidth>
            </field>
            <field>
              <name>AFSEL4</name>
              <bitOffset>16</bitOffset>
              <bitWidth>4</bitWidth>
            </field>
            <field>
              <name>AFSEL5</name>
              <bitOffset>20</bitOffset>
              <bitWidth>4</bitWidth>
            </field>
            <field>
              <name>AFSEL6</name>
              <bitOffset>24</bitOffset>
              <bitWidth>4</bitWidth>
            </field>
            <field>
              <name>AFSEL7</name>
              <bitOffset>28</bitOffset>
              <bitWidth>4</bitWidth>
            </field>
          </fields>
        </register>
        <register>
          <name>AFR.1</name>
          <addressOffset>0x24</addressOffset>
          <size>0x20</size>
          <fields>
            <field>
              <name>AFSEL8</name>
              <bitOffset>0</bitOffset>
              <bitWidth>4</bitWidth>
            </field>
            <field>
              <name>AFSEL9</name>
              <bitOffset>4</bitOffset>
              <bitWidth>4</bitWidth>
            </field>
            <field>
              <name>AFSEL10</name>
              <bitOffset>8</bitOffset>
              <bitWidth>4</bitWidth>
            </field>
            <field>
              <name>AFSEL11</name>
              <bitOffset>12</bitOffset>
              <bitWidth>4</bitWidth>
            </field>
            <field>
              <name>AFSEL12</name>
              <bitOffset>16</bitOffset>
              <bitWidth>4</bitWidth>
            </field>
            <field>
              <name>AFSEL13</name>
              <bitOffset>20</bitOffset>
              <bitWidth>4</bitWidth>
            </field>
            <field>
              <name>AFSEL14</name>
              <bitOffset>24</bitOffset>
              <bitWidth>4</bitWidth>
            </field>
            <field>
              <name>AFSEL15</name>
              <bitOffset>28</bitOffset>
              <bitWidth>4</bitWidth>
            </field>
          </fields>
        </register>
      </registers>
    </peripheral>
    <peripheral>
      <name>GPIOD</name>
      <baseAddress>0x40020c00</baseAddress>
      <registers>
        <register>
          <name>MODER</name>
          <addressOffset>0x0</addressOffset>
          <size>0x20</size>
          <fields>
            <field>
              <name>MODER0</name>
              <bitOffset>0</bitOffset>
              <bitWidth>2</bitWidth>
            </field>
            <field>
              <name>MODER1</name>
              <bitOffset>2</bitOffset>
              <bitWidth>2</bitWidth>
            </field>
            <field>
              <name>MODER2</name>
              <bitOffset>4</bitOffset>
              <bitWidth>2</bitWidth>
            </field>
            <field>
              <name>MODER3</name>
              <bitOffset>6</bitOffset>
              <bitWidth>2</bitWidth>
            </field>
            <field>
              <name>MODER4</name>
              <bitOffset>8</bitOffset>
              <bitWidth>2</bitWidth>
            </field>
            <field>
              <name>MODER5</name>
              <bitOffset>10</bitOffset>
              <bitWidth>2</bitWidth>
            </field>
            <field>
              <name>MODER6</name>
              <bitOffset>12</bitOffset>
              <bitWidth>2</bitWidth>
            </field>
            <field>
              <name>MODER7</name>
              <bitOffset>14</bitOffset>
              <bitWidth>2</bitWidth>
            </field>
            <field>
              <name>MODER8</name>
              <bitOffset>16</bitOffset>
              <bitWidth>2</bitWidth>
            </field>
            <field>
              <name>MODER9</name>
              <bitOffset>18</bitOffset>
              <bitWidth>2</bitWidth>
            </field>
            <field>
              <name>MODER10</name>
              <bitOffset>20</bitOffset>
              <bitWidth>2</bitWidth>
            </field>
            <field>
              <name>MODER11</name>
              <bitOffset>22</bitOffset>
              <bitWidth>2</bitWidth>
            </field>
            <field>
              <name>MODER12</name>
              <bitOffset>24</bitOffset>
              <bitWidth>2</bitWidth>
            </field>
            <field>
              <name>MODER13</name>
              <bitOffset>26</bitOffset>
              <bitWidth>2</bitWidth>
            </field>
            <field>
              <name>MODER14</name>
              <bitOffset>28</bitOffset>
              <bitWidth>2</bitWidth>
            </field>
            <field>
              <name>MODER15</name>
              <bitOffset>30</bitOffset>
              <bitWidth>2</bitWidth>
            </field>
          </fields>
        </register>
        <register>
          <name>OTYPER</name>
          <addressOffset>0x4</addressOffset>
          <size>0x20</size>
        </register>
        <register>
          <name>OSPEEDR</name>
          <addressOffset>0x8</addressOffset>
          <size>0x20</size>
        </register>
        <register>
          <name>PUPDR</name>
          <addressOffset>0xc</addressOffset>
          <size>0x20</size>
          <fields>
            <field>
              <name>PUPDR0</name>
              <bitOffset>0</bitOffset>
              <bitWidth>2</bitWidth>
            </field>
            <field>
              <name>PUPDR1</name>
              <bitOffset>2</bitOffset>
              <bitWidth>2</bitWidth>
            </field>
            <field>
              <name>PUPDR2</name>
              <bitOffset>4</bitOffset>
              <bitWidth>2</bitWidth>
            </field>
            <field>
              <name>PUPDR3</name>
              <bitOffset>6</bitOffset>
              <bitWidth>2</bitWidth>
            </field>
            <field>
              <name>PUPDR4</name>
              <bitOffset>8</bitOffset>
              <bitWidth>2</bitWidth>
            </field>
            <field>
              <name>PUPDR5</name>
              <bitOffset>10</bitOffset>
              <bitWidth>2</bitWidth>
            </field>
            <field>
              <name>PUPDR6</name>
              <bitOffset>12</bitOffset>
              <bitWidth>2</bitWidth>
            </field>
            <field>
              <name>PUPDR7</name>
              <bitOffset>14</bitOffset>
              <bitWidth>2</bitWidth>
            </field>
            <field>
              <name>PUPDR8</name>
              <bitOffset>16</bitOffset>
              <bitWidth>2</bitWidth>
            </field>
            <field>
              <name>PUPDR9</name>
              <bitOffset>18</bitOffset>
              <bitWidth>2</bitWidth>
            </field>
            <field>
              <name>PUPDR10</name>
              <bitOffset>20</bitOffset>
              <bitWidth>2</bitWidth>
            </field>
            <field>
              <name>PUPDR11</name>
              <bitOffset>22</bitOffset>
              <bitWidth>2</bitWidth>
            </field>
            <field>
              <name>PUPDR12</name>
              <bitOffset>24</bitOffset>
              <bitWidth>2</bitWidth>
            </field>
            <field>
              <name>PUPDR13</name>
              <bitOffset>26</bitOffset>
              <bitWidth>2</bitWidth>
            </field>
            <field>
              <name>PUPDR14</name>
              <bitOffset>28</bitOffset>
              <bitWidth>2</bitWidth>
            </field>
            <field>
              <name>PUPDR15</name>
              <bitOffset>30</bitOffset>
              <bitWidth>2</bitWidth>
            </field>
          </fields>
        </register>
        <register>
          <name>IDR</name>
          <addressOffset>0x10</addressOffset>
          <size>0x20</size>
        </register>
        <register>
          <name>ODR</name>
          <addressOffset>0x14</addressOffset>
          <size>0x20</size>
        </register>
        <register>
          <name>BSRR</name>
          <addressOffset>0x18</addressOffset>
          <size>0x20</size>
        </register>
        <register>
          <name>LCKR</name>
          <addressOffset>0x1c</addressOffset>
          <size>0x20</size>
          <fields>
            <field>
              <name>LCK0</name>
              <bitOffset>0</bitOffset>
              <bitWidth>1</bitWidth>
            </field>
            <field>
              <name>LCK1</name>
              <bitOffset>1</bitOffset>
              <bitWidth>1</bitWidth>
            </field>
            <field>
              <name>LCK2</name>
              <bitOffset>2</bitOffset>
              <bitWidth>1</bitWidth>
            </field>
            <field>
              <name>LCK3</name>
              <bitOffset>3</bitOffset>
              <bitWidth>1</bitWidth>
            </field>
            <field>
              <name>LCK4</name>
              <bitOffset>4</bitOffset>
              <bitWidth>1</bitWidth>
            </field>
            <field>
              <name>LCK5</name>
              <bitOffset>5</bitOffset>
              <bitWidth>1</bitWidth>
            </field>
            <field>
              <name>LCK6</name>
              <bitOffset>6</bitOffset>
              <bitWidth>1</bitWidth>
            </field>
            <field>
              <name>LCK7</name>
              <bitOffset>7</bitOffset>
              <bitWidth>1</bitWidth>
            </field>
            <field>
              <name>LCK8</name>
              <bitOffset>8</bitOffset>
              <bitWidth>1</bitWidth>
            </field>
            <field>
              <name>LCK9</name>
              <bitOffset>9</bitOffset>
              <bitWidth>1</bitWidth>
            </field>
            <field>
              <name>LCK10</name>
              <bitOffset>10</bitOffset>
              <bitWidth>1</bitWidth>
            </field>
            <field>
              <name>LCK11</name>
              <bitOffset>11</bitOffset>
              <bitWidth>1</bitWidth>
            </field>
            <field>
              <name>LCK12</name>
              <bitOffset>12</bitOffset>
              <bitWidth>1</bitWidth>
            </field>
            <field>
              <name>LCK13</name>
              <bitOffset>13</bitOffset>
              <bitWidth>1</bitWidth>
            </field>
            <field>
              <name>LCK14</name>
              <bitOffset>14</bitOffset>
              <bitWidth>1</bitWidth>
            </field>
            <field>
              <name>LCK15</name>
              <bitOffset>15</bitOffset>
              <bitWidth>1</bitWidth>
            </field>
            <field>
              <name>LCKK</name>
              <bitOffset>16</bitOffset>
              <bitWidth>1</bitWidth>
            </field>
          </fields>
        </register>
        <register>
          <name>AFR.0</name>
          <addressOffset>0x20</addressOffset>
          <size>0x20</size>
          <fields>
            <field>
              <name>AFSEL0</name>
              <bitOffset>0</bitOffset>
              <bitWidth>4</bitWidth>
            </field>
            <field>
              <name>AFSEL1</name>
              <bitOffset>4</bitOffset>
              <bitWidth>4</bitWidth>
            </field>
            <field>
              <name>AFSEL2</name>
              <bitOffset>8</bitOffset>
              <bitWidth>4</bitWidth>
            </field>
            <field>
              <name>AFSEL3</name>
              <bitOffset>12</bitOffset>
              <bitWidth>4</bitWidth>
            </field>
            <field>
              <name>AFSEL4</name>
              <bitOffset>16</bitOffset>
              <bitWidth>4</bitWidth>
            </field>
            <field>
              <name>AFSEL5</name>
              <bitOffset>20</bitOffset>
              <bitWidth>4</bitWidth>
            </field>
            <field>
              <name>AFSEL6</name>
              <bitOffset>24</bitOffset>
              <bitWidth>4</bitWidth>
            </field>
            <field>
              <name>AFSEL7</name>
              <bitOffset>28</bitOffset>
              <bitWidth>4</bitWidth>
            </field>
          </fields>
        </register>
        <register>
          <name>AFR.1</name>
          <addressOffset>0x24</addressOffset>
          <size>0x20</size>
          <fields>
            <field>
              <name>AFSEL8</name>
              <bitOffset>0</bitOffset>
              <bitWidth>4</bitWidth>
            </field>
            <field>
              <name>AFSEL9</name>
              <bitOffset>4</bitOffset>
              <bitWidth>4</bitWidth>
            </field>
            <field>
              <name>AFSEL10</name>
              <bitOffset>8</bitOffset>
              <bitWidth>4</bitWidth>
            </field>
            <field>
              <name>AFSEL11</name>
              <bitOffset>12</bitOffset>
              <bitWidth>4</bitWidth>
            </field>
            <field>
              <name>AFSEL12</name>
              <bitOffset>16</bitOffset>
              <bitWidth>4</bitWidth>
            </field>
            <field>
              <name>AFSEL13</name>
              <bitOffset>20</bitOffset>
              <bitWidth>4</bitWidth>
            </field>
            <field>
              <name>AFSEL14</name>
              <bitOffset>24</bitOffset>
              <bitWidth>4</bitWidth>
            </field>
            <field>
              <name>AFSEL15</name>
              <bitOffset>28</bitOffset>
              <bitWidth>4</bitWidth>
            </field>
          </fields>
        </register>
      </registers>
    </peripheral>
    <peripheral>
      <name>GPIOE</name>
      <baseAddress>0x40021000</baseAddress>
      <registers>
        <register>
          <name>MODER</name>
          <addressOffset>0x0</addressOffset>
          <size>0x20</size>
          <fields>
            <field>
              <name>MODER0</name>
              <bitOffset>0</bitOffset>
              <bitWidth>2</bitWidth>
            </field>
            <field>
              <name>MODER1</name>
              <bitOffset>2</bitOffset>
              <bitWidth>2</bitWidth>
            </field>
            <field>
              <name>MODER2</name>
              <bitOffset>4</bitOffset>
              <bitWidth>2</bitWidth>
            </field>
            <field>
              <name>MODER3</name>
              <bitOffset>6</bitOffset>
              <bitWidth>2</bitWidth>
            </field>
            <field>
              <name>MODER4</name>
              <bitOffset>8</bitOffset>
              <bitWidth>2</bitWidth>
            </field>
            <field>
              <name>MODER5</name>
              <bitOffset>10</bitOffset>
              <bitWidth>2</bitWidth>
            </field>
            <field>
              <name>MODER6</name>
              <bitOffset>12</bitOffset>
              <bitWidth>2</bitWidth>
            </field>
            <field>
              <name>MODER7</name>
              <bitOffset>14</bitOffset>
              <bitWidth>2</bitWidth>
            </field>
            <field>
              <name>MODER8</name>
              <bitOffset>16</bitOffset>
              <bitWidth>2</bitWidth>
            </field>
            <field>
              <name>MODER9</name>
              <bitOffset>18</bitOffset>
              <bitWidth>2</bitWidth>
            </field>
            <field>
              <name>MODER10</name>
              <bitOffset>20</bitOffset>
              <bitWidth>2</bitWidth>
            </field>
            <field>
              <name>MODER11</name>
              <bitOffset>22</bitOffset>
              <bitWidth>2</bitWidth>
            </field>
            <field>
              <name>MODER12</name>
              <bitOffset>24</bitOffset>
              <bitWidth>2</bitWidth>
            </field>
            <field>
              <name>MODER13</name>
              <bitOffset>26</bitOffset>
              <bitWidth>2</bitWidth>
            </field>
            <field>
              <name>MODER14</name>
              <bitOffset>28</bitOffset>
              <bitWidth>2</bitWidth>
            </field>
            <field>
              <name>MODER15</name>
              <bitOffset>30</bitOffset>
              <bitWidth>2</bitWidth>
            </field>
          </fields>
        </register>
        <register>
          <name>OTYPER</name>
          <addressOffset>0x4</addressOffset>
          <size>0x20</size>
        </register>
        <register>
          <name>OSPEEDR</name>
          <addressOffset>0x8</addressOffset>
          <size>0x20</size>
        </register>
        <register>
          <name>PUPDR</name>
          <addressOffset>0xc</addressOffset>
          <size>0x20</size>
          <fields>
            <field>
              <name>PUPDR0</name>
              <bitOffset>0</bitOffset>
              <bitWidth>2</bitWidth>
            </field>
            <field>
              <name>PUPDR1</name>
              <bitOffset>2</bitOffset>
              <bitWidth>2</bitWidth>
            </field>
            <field>
              <name>PUPDR2</name>
              <bitOffset>4</bitOffset>
              <bitWidth>2</bitWidth>
            </field>
            <field>
              <name>PUPDR3</name>
              <bitOffset>6</bitOffset>
              <bitWidth>2</bitWidth>
            </field>
            <field>
              <name>PUPDR4</name>
              <bitOffset>8</bitOffset>
              <bitWidth>2</bitWidth>
            </field>
            <field>
              <name>PUPDR5</name>
              <bitOffset>10</bitOffset>
              <bitWidth>2</bitWidth>
            </field>
            <field>
              <name>PUPDR6</name>
              <bitOffset>12</bitOffset>
              <bitWidth>2</bitWidth>
            </field>
            <field>
              <name>PUPDR7</name>
              <bitOffset>14</bitOffset>
              <bitWidth>2</bitWidth>
            </field>
            <field>
              <name>PUPDR8</name>
              <bitOffset>16</bitOffset>
              <bitWidth>2</bitWidth>
            </field>
            <field>
              <name>PUPDR9</name>
              <bitOffset>18</bitOffset>
              <bitWidth>2</bitWidth>
            </field>
            <field>
              <name>PUPDR10</name>
              <bitOffset>20</bitOffset>
              <bitWidth>2</bitWidth>
            </field>
            <field>
              <name>PUPDR11</name>
              <bitOffset>22</bitOffset>
              <bitWidth>2</bitWidth>
            </field>
            <field>
              <name>PUPDR12</name>
              <bitOffset>24</bitOffset>
              <bitWidth>2</bitWidth>
            </field>
            <field>
              <name>PUPDR13</name>
              <bitOffset>26</bitOffset>
              <bitWidth>2</bitWidth>
            </field>
            <field>
              <name>PUPDR14</name>
              <bitOffset>28</bitOffset>
              <bitWidth>2</bitWidth>
            </field>
            <field>
              <name>PUPDR15</name>
              <bitOffset>30</bitOffset>
              <bitWidth>2</bitWidth>
            </field>
          </fields>
        </register>
        <register>
          <name>IDR</name>
          <addressOffset>0x10</addressOffset>
          <size>0x20</size>
        </register>
        <register>
          <name>ODR</name>
          <addressOffset>0x14</addressOffset>
          <size>0x20</size>
        </register>
        <register>
          <name>BSRR</name>
          <addressOffset>0x18</addressOffset>
          <size>0x20</size>
        </register>
        <register>
          <name>LCKR</name>
          <addressOffset>0x1c</addressOffset>
          <size>0x20</size>
          <fields>
            <field>
              <name>LCK0</name>
              <bitOffset>0</bitOffset>
              <bitWidth>1</bitWidth>
            </field>
            <field>
              <name>LCK1</name>
              <bitOffset>1</bitOffset>
              <bitWidth>1</bitWidth>
            </field>
            <field>
              <name>LCK2</name>
              <bitOffset>2</bitOffset>
              <bitWidth>1</bitWidth>
            </field>
            <field>
              <name>LCK3</name>
              <bitOffset>3</bitOffset>
              <bitWidth>1</bitWidth>
            </field>
            <field>
              <name>LCK4</name>
              <bitOffset>4</bitOffset>
              <bitWidth>1</bitWidth>
            </field>
            <field>
              <name>LCK5</name>
              <bitOffset>5</bitOffset>
              <bitWidth>1</bitWidth>
            </field>
            <field>
              <name>LCK6</name>
              <bitOffset>6</bitOffset>
              <bitWidth>1</bitWidth>
            </field>
            <field>
              <name>LCK7</name>
              <bitOffset>7</bitOffset>
              <bitWidth>1</bitWidth>
            </field>
            <field>
              <name>LCK8</name>
              <bitOffset>8</bitOffset>
              <bitWidth>1</bitWidth>
            </field>
            <field>
              <name>LCK9</name>
              <bitOffset>9</bitOffset>
              <bitWidth>1</bitWidth>
            </field>
            <field>
              <name>LCK10</name>
              <bitOffset>10</bitOffset>
              <bitWidth>1</bitWidth>
            </field>
            <field>
              <name>LCK11</name>
              <bitOffset>11</bitOffset>
              <bitWidth>1</bitWidth>
            </field>
            <field>
              <name>LCK12</name>
              <bitOffset>12</bitOffset>
              <bitWidth>1</bitWidth>
            </field>
            <field>
              <name>LCK13</name>
              <bitOffset>13</bitOffset>
              <bitWidth>1</bitWidth>
            </field>
            <field>
              <name>LCK14</name>
              <bitOffset>14</bitOffset>
              <bitWidth>1</bitWidth>
            </field>
            <field>
              <name>LCK15</name>
              <bitOffset>15</bitOffset>
              <bitWidth>1</bitWidth>
            </field>
            <field>
              <name>LCKK</name>
              <bitOffset>16</bitOffset>
              <bitWidth>1</bitWidth>
            </field>
          </fields>
        </register>
        <register>
          <name>AFR.0</name>
          <addressOffset>0x20</addressOffset>
          <size>0x20</size>
          <fields>
            <field>
              <name>AFSEL0</name>
              <bitOffset>0</bitOffset>
              <bitWidth>4</bitWidth>
            </field>
            <field>
              <name>AFSEL1</name>
              <bitOffset>4</bitOffset>
              <bitWidth>4</bitWidth>
            </field>
            <field>
              <name>AFSEL2</name>
              <bitOffset>8</bitOffset>
              <bitWidth>4</bitWidth>
            </field>
            <field>
              <name>AFSEL3</name>
              <bitOffset>12</bitOffset>
              <bitWidth>4</bitWidth>
            </field>
            <field>
              <name>AFSEL4</name>
              <bitOffset>16</bitOffset>
              <bitWidth>4</bitWidth>
            </field>
            <field>
              <name>AFSEL5</name>
              <bitOffset>20</bitOffset>
              <bitWidth>4</bitWidth>
            </field>
            <field>
              <name>AFSEL6</name>
              <bitOffset>24</bitOffset>
              <bitWidth>4</bitWidth>
            </field>
            <field>
              <name>AFSEL7</name>
              <bitOffset>28</bitOffset>
              <bitWidth>4</bitWidth>
            </field>
          </fields>
        </register>
        <register>
          <name>AFR.1</name>
          <addressOffset>0x24</addressOffset>
          <size>0x20</size>
          <fields>
            <field>
              <name>AFSEL8</name>
              <bitOffset>0</bitOffset>
              <bitWidth>4</bitWidth>
            </field>
            <field>
              <name>AFSEL9</name>
              <bitOffset>4</bitOffset>
              <bitWidth>4</bitWidth>
            </field>
            <field>
              <name>AFSEL10</name>
              <bitOffset>8</bitOffset>
              <bitWidth>4</bitWidth>
            </field>
            <field>
              <name>AFSEL11</name>
              <bitOffset>12</bitOffset>
              <bitWidth>4</bitWidth>
            </field>
            <field>
              <name>AFSEL12</name>
              <bitOffset>16</bitOffset>
              <bitWidth>4</bitWidth>
            </field>
            <field>
              <name>AFSEL13</name>
              <bitOffset>20</bitOffset>
              <bitWidth>4</bitWidth>
            </field>
            <field>
              <name>AFSEL14</name>
              <bitOffset>24</bitOffset>
              <bitWidth>4</bitWidth>
            </field>
            <field>
              <name>AFSEL15</name>
              <bitOffset>28</bitOffset>
              <bitWidth>4</bitWidth>
            </field>
          </fields>
        </register>
      </registers>
    </peripheral>
    <peripheral>
      <name>GPIOH</name>
      <baseAddress>0x40021400</baseAddress>
      <registers>
        <register>
          <name>MODER</name>
          <addressOffset>0x0</addressOffset>
          <size>0x20</size>
          <fields>
            <field>
              <name>MODER0</name>
              <bitOffset>0</bitOffset>
              <bitWidth>2</bitWidth>
            </field>
            <field>
              <name>MODER1</name>
              <bitOffset>2</bitOffset>
              <bitWidth>2</bitWidth>
            </field>
            <field>
              <name>MODER2</name>
              <bitOffset>4</bitOffset>
              <bitWidth>2</bitWidth>
            </field>
            <field>
              <name>MODER3</name>
              <bitOffset>6</bitOffset>
              <bitWidth>2</bitWidth>
            </field>
            <field>
              <name>MODER4</name>
              <bitOffset>8</bitOffset>
              <bitWidth>2</bitWidth>
            </field>
            <field>
              <name>MODER5</name>
              <bitOffset>10</bitOffset>
              <bitWidth>2</bitWidth>
            </field>
            <field>
              <name>MODER6</name>
              <bitOffset>12</bitOffset>
              <bitWidth>2</bitWidth>
            </field>
            <field>
              <name>MODER7</name>
              <bitOffset>14</bitOffset>
              <bitWidth>2</bitWidth>
            </field>
            <field>
              <name>MODER8</name>
              <bitOffset>16</bitOffset>
              <bitWidth>2</bitWidth>
            </field>
            <field>
              <name>MODER9</name>
              <bitOffset>18</bitOffset>
              <bitWidth>2</bitWidth>
            </field>
            <field>
              <name>MODER10</name>
              <bitOffset>20</bitOffset>
              <bitWidth>2</bitWidth>
            </field>
            <field>
              <name>MODER11</name>
              <bitOffset>22</bitOffset>
              <bitWidth>2</bitWidth>
            </field>
            <field>
              <name>MODER12</name>
              <bitOffset>24</bitOffset>
              <bitWidth>2</bitWidth>
            </field>
            <field>
              <name>MODER13</name>
              <bitOffset>26</bitOffset>
              <bitWidth>2</bitWidth>
            </field>
            <field>
              <name>MODER14</name>
              <bitOffset>28</bitOffset>
              <bitWidth>2</bitWidth>
            </field>
            <field>
              <name>MODER15</name>
              <bitOffset>30</bitOffset>
              <bitWidth>2</bitWidth>
            </field>
          </fields>
        </register>
        <register>
          <name>OTYPER</name>
          <addressOffset>0x4</addressOffset>
          <size>0x20</size>
        </register>
        <register>
          <name>OSPEEDR</name>
          <addressOffset>0x8</addressOffset>
          <size>0x20</size>
        </register>
        <register>
          <name>PUPDR</name>
          <addressOffset>0xc</addressOffset>
          <size>0x20</size>
          <fields>
            <field>
              <name>PUPDR0</name>
              <bitOffset>0</bitOffset>
              <bitWidth>2</bitWidth>
            </field>
            <field>
              <name>PUPDR1</name>
              <bitOffset>2</bitOffset>
              <bitWidth>2</bitWidth>
            </field>
            <field>
              <name>PUPDR2</name>
              <bitOffset>4</bitOffset>
              <bitWidth>2</bitWidth>
            </field>
            <field>
              <name>PUPDR3</name>
              <bitOffset>6</bitOffset>
              <bitWidth>2</bitWidth>
            </field>
            <field>
              <name>PUPDR4</name>
              <bitOffset>8</bitOffset>
              <bitWidth>2</bitWidth>
            </field>
            <field>
              <name>PUPDR5</name>
              <bitOffset>10</bitOffset>
              <bitWidth>2</bitWidth>
            </field>
            <field>
              <name>PUPDR6</name>
              <bitOffset>12</bitOffset>
              <bitWidth>2</bitWidth>
            </field>
            <field>
              <name>PUPDR7</name>
              <bitOffset>14</bitOffset>
              <bitWidth>2</bitWidth>
            </field>
            <field>
              <name>PUPDR8</name>
              <bitOffset>16</bitOffset>
              <bitWidth>2</bitWidth>
            </field>
            <field>
              <name>PUPDR9</name>
              <bitOffset>18</bitOffset>
              <bitWidth>2</bitWidth>
            </field>
            <field>
              <name>PUPDR10</name>
              <bitOffset>20</bitOffset>
              <bitWidth>2</bitWidth>
            </field>
            <field>
              <name>PUPDR11</name>
              <bitOffset>22</bitOffset>
              <bitWidth>2</bitWidth>
            </field>
            <field>
              <name>PUPDR12</name>
              <bitOffset>24</bitOffset>
              <bitWidth>2</bitWidth>
            </field>
            <field>
              <name>PUPDR13</name>
              <bitOffset>26</bitOffset>
              <bitWidth>2</bitWidth>
            </field>
            <field>
              <name>PUPDR14</name>
              <bitOffset>28</bitOffset>
              <bitWidth>2</bitWidth>
            </field>
            <field>
              <name>PUPDR15</name>
              <bitOffset>30</bitOffset>
              <bitWidth>2</bitWidth>
            </field>
          </fields>
        </register>
        <register>
          <name>IDR</name>
          <addressOffset>0x10</addressOffset>
          <size>0x20</size>
        </register>
        <register>
          <name>ODR</name>
          <addressOffset>0x14</addressOffset>
          <size>0x20</size>
        </register>
        <register>
          <name>BSRR</name>
          <addressOffset>0x18</addressOffset>
          <size>0x20</size>
        </register>
        <register>
          <name>LCKR</name>
          <addressOffset>0x1c</addressOffset>
          <size>0x20</size>
          <fields>
            <field>
              <name>LCK0</name>
              <bitOffset>0</bitOffset>
              <bitWidth>1</bitWidth>
            </field>
            <field>
              <name>LCK1</name>
              <bitOffset>1</bitOffset>
              <bitWidth>1</bitWidth>
            </field>
            <field>
              <name>LCK2</name>
              <bitOffset>2</bitOffset>
              <bitWidth>1</bitWidth>
            </field>
            <field>
              <name>LCK3</name>
              <bitOffset>3</bitOffset>
              <bitWidth>1</bitWidth>
            </field>
            <field>
              <name>LCK4</name>
              <bitOffset>4</bitOffset>
              <bitWidth>1</bitWidth>
            </field>
            <field>
              <name>LCK5</name>
              <bitOffset>5</bitOffset>
              <bitWidth>1</bitWidth>
            </field>
            <field>
              <name>LCK6</name>
              <bitOffset>6</bitOffset>
              <bitWidth>1</bitWidth>
            </field>
            <field>
              <name>LCK7</name>
              <bitOffset>7</bitOffset>
              <bitWidth>1</bitWidth>
            </field>
            <field>
              <name>LCK8</name>
              <bitOffset>8</bitOffset>
              <bitWidth>1</bitWidth>
            </field>
            <field>
              <name>LCK9</name>
              <bitOffset>9</bitOffset>
              <bitWidth>1</bitWidth>
            </field>
            <field>
              <name>LCK10</name>
              <bitOffset>10</bitOffset>
              <bitWidth>1</bitWidth>
            </field>
            <field>
              <name>LCK11</name>
              <bitOffset>11</bitOffset>
              <bitWidth>1</bitWidth>
            </field>
            <field>
              <name>LCK12</name>
              <bitOffset>12</bitOffset>
              <bitWidth>1</bitWidth>
            </field>
            <field>
              <name>LCK13</name>
              <bitOffset>13</bitOffset>
              <bitWidth>1</bitWidth>
            </field>
            <field>
              <name>LCK14</name>
              <bitOffset>14</bitOffset>
              <bitWidth>1</bitWidth>
            </field>
            <field>
              <name>LCK15</name>
              <bitOffset>15</bitOffset>
              <bitWidth>1</bitWidth>
            </field>
            <field>
              <name>LCKK</name>
              <bitOffset>16</bitOffset>
              <bitWidth>1</bitWidth>
            </field>
          </fields>
        </register>
        <register>
          <name>AFR.0</name>
          <addressOffset>0x20</addressOffset>
          <size>0x20</size>
          <fields>
            <field>
              <name>AFSEL0</name>
              <bitOffset>0</bitOffset>
              <bitWidth>4</bitWidth>
            </field>
            <field>
              <name>AFSEL1</name>
              <bitOffset>4</bitOffset>
              <bitWidth>4</bitWidth>
            </field>
            <field>
              <name>AFSEL2</name>
              <bitOffset>8</bitOffset>
              <bitWidth>4</bitWidth>
            </field>
            <field>
              <name>AFSEL3</name>
              <bitOffset>12</bitOffset>
              <bitWidth>4</bitWidth>
            </field>
            <field>
              <name>AFSEL4</name>
              <bitOffset>16</bitOffset>
              <bitWidth>4</bitWidth>
            </field>
            <field>
              <name>AFSEL5</name>
              <bitOffset>20</bitOffset>
              <bitWidth>4</bitWidth>
            </field>
            <field>
              <name>AFSEL6</name>
              <bitOffset>24</bitOffset>
              <bitWidth>4</bitWidth>
            </field>
            <field>
              <name>AFSEL7</name>
              <bitOffset>28</bitOffset>
              <bitWidth>4</bitWidth>
            </field>
          </fields>
        </register>
        <register>
          <name>AFR.1</name>
          <addressOffset>0x24</addressOffset>
          <size>0x20</size>
          <fields>
            <field>
              <name>AFSEL8</name>
              <bitOffset>0</bitOffset>
              <bitWidth>4</bitWidth>
            </field>
            <field>
              <name>AFSEL9</name>
              <bitOffset>4</bitOffset>
              <bitWidth>4</bitWidth>
            </field>
            <field>
              <name>AFSEL10</name>
              <bitOffset>8</bitOffset>
              <bitWidth>4</bitWidth>
            </field>
            <field>
              <name>AFSEL11</name>
              <bitOffset>12</bitOffset>
              <bitWidth>4</bitWidth>
            </field>
            <field>
              <name>AFSEL12</name>
              <bitOffset>16</bitOffset>
              <bitWidth>4</bitWidth>
            </field>
            <field>
              <name>AFSEL13</name>
              <bitOffset>20</bitOffset>
              <bitWidth>4</bitWidth>
            </field>
            <field>
              <name>AFSEL14</name>
              <bitOffset>24</bitOffset>
              <bitWidth>4</bitWidth>
            </field>
            <field>
              <name>AFSEL15</name>
              <bitOffset>28</bitOffset>
              <bitWidth>4</bitWidth>
            </field>
          </fields>
        </register>
      </registers>
    </peripheral>
    <peripheral>
      <name>CRC</name>
      <baseAddress>0x40023000</baseAddress>
      <registers>
        <register>
          <name>DR</name>
          <addressOffset>0x0</addressOffset>
          <size>0x20</size>
          <fields>
            <field>
              <name>DR</name>
              <bitOffset>0</bitOffset>
              <bitWidth>32</bitWidth>
            </field>
          </fields>
        </register>
        <register>
          <name>IDR</name>
          <addressOffset>0x4</addressOffset>
          <size>0x8</size>
          <fields>
            <field>
              <name>IDR</name>
              <bitOffset>0</bitOffset>
              <bitWidth>8</bitWidth>
            </field>
          </fields>
        </register>
        <register>
          <name>CR</name>
          <addressOffset>0x8</addressOffset>
          <size>0x20</size>
          <fields>
            <field>
              <name>RESET</name>
              <bitOffset>0</bitOffset>
              <bitWidth>1</bitWidth>
            </field>
          </fields>
        </register>
      </registers>
    </peripheral>
    <peripheral>
      <name>RCC</name>
      <baseAddress>0x40023800</baseAddress>
      <registers>
        <register>
          <name>CR</name>
          <addressOffset>0x0</addressOffset>
          <size>0x20</size>
          <fields>
            <field>
              <name>HSION</name>
              <bitOffset>0</bitOffset>
              <bitWidth>1</bitWidth>
            </field>
            <field>
              <name>HSIRDY</name>
              <bitOffset>1</bitOffset>
              <bitWidth>1</bitWidth>
            </field>
            <field>
              <name>MSION</name>
              <bitOffset>8</bitOffset>
              <bitWidth>1</bitWidth>
            </field>
            <field>
              <name>MSIRDY</name>
              <bitOffset>9</bitOffset>
              <bitWidth>1</bitWidth>
            </field>
            <field>
              <name>HSEON</name>
              <bitOffset>16</bitOffset>
              <bitWidth>1</bitWidth>
            </field>
            <field>
              <name>HSERDY</name>
              <bitOffset>17</bitOffset>
              <bitWidth>1</bitWidth>
            </field>
            <field>
              <name>HSEBYP</name>
              <bitOffset>18</bitOffset>
              <bitWidth>1</bitWidth>
            </field>
            <field>
              <name>PLLON</name>
              <bitOffset>24</bitOffset>
              <bitWidth>1</bitWidth>
            </field>
            <field>
              <name>PLLRDY</name>
              <bitOffset>25</bitOffset>
              <bitWidth>1</bitWidth>
            </field>
            <field>
              <name>CSSON</name>
              <bitOffset>28</bitOffset>
              <bitWidth>1</bitWidth>
            </field>
            <field>
              <name>RTCPRE</name>
              <bitOffset>29</bitOffset>
              <bitWidth>2</bitWidth>
            </field>
          </fields>
        </register>
        <register>
          <name>ICSCR</name>
          <addressOffset>0x4</addressOffset>
          <size>0x20</size>
          <fields>
            <field>
              <name>HSICAL</name>
              <bitOffset>0</bitOffset>
              <bitWidth>8</bitWidth>
            </field>
            <field>
              <name>HSITRIM</name>
              <bitOffset>8</bitOffset>
              <bitWidth>5</bitWidth>
            </field>
            <field>
              <name>MSIRANGE</name>
              <bitOffset>13</bitOffset>
              <bitWidth>3</bitWidth>
            </field>
            <field>
              <name>MSICAL</name>
              <bitOffset>16</bitOffset>
              <bitWidth>8</bitWidth>
            </field>
            <field>
              <name>MSITRIM</name>
              <bitOffset>24</bitOffset>
              <bitWidth>8</bitWidth>
            </field>
          </fields>
        </register>
        <register>
          <name>CFGR</name>
          <addressOffset>0x8</addressOffset>
          <size>0x20</size>
          <fields>
            <field>
              <name>SW</name>
              <bitOffset>0</bitOffset>
              <bitWidth>2</bitWidth>
            </field>
            <field>
              <name>SWS</name>
              <bitOffset>2</bitOffset>
              <bitWidth>2</bitWidth>
            </field>
            <field>
              <name>HPRE</name>
              <bitOffset>4</bitOffset>
              <bitWidth>4</bitWidth>
            </field>
            <field>
              <name>PPRE1</name>
              <bitOffset>8</bitOffset>
              <bitWidth>3</bitWidth>
            </field>
            <field>
              <name>PPRE2</name>
              <bitOffset>11</bitOffset>
              <bitWidth>3</bitWidth>
            </field>
            <field>
              <name>PLLSRC</name>
              <bitOffset>16</bitOffset>
              <bitWidth>1</bitWidth>
            </field>
            <field>
              <name>PLLMUL</name>
              <bitOffset>18</bitOffset>
              <bitWidth>4</bitWidth>
            </field>
            <field>
              <name>PLLDIV4</name>
              <bitOffset>22</bitOffset>
              <bitWidth>2</bitWidth>
            </field>
            <field>
              <name>PLLDIV3</name>
              <bitOffset>23</bitOffset>
              <bitWidth>1</bitWidth>
            </field>
            <field>
              <name>MCOSEL_SYSCLK</name>
              <bitOffset>24</bitOffset>
              <bitWidth>1</bitWidth>
            </field>
            <field>
              <name>MCOSEL_LSI</name>
              <bitOffset>25</bitOffset>
              <bitWidth>2</bitWidth>
            </field>
            <field>
              <name>MCOSEL_HSE</name>
              <bitOffset>26</bitOffset>
              <bitWidth>1</bitWidth>
            </field>
            <field>
              <name>MCOPRE</name>
              <bitOffset>28</bitOffset>
              <bitWidth>3</bitWidth>
            </field>
          </fields>
        </register>
        <register>
          <name>CIR</name>
          <addressOffset>0xc</addressOffset>
          <size>0x20</size>
          <fields>
            <field>
              <name>LSIRDYF</name>
              <bitOffset>0</bitOffset>
              <bitWidth>1</bitWidth>
            </field>
            <field>
              <name>LSERDYF</name>
              <bitOffset>1</bitOffset>
              <bitWidth>1</bitWidth>
            </field>
            <field>
              <name>HSIRDYF</name>
              <bitOffset>2</bitOffset>
              <bitWidth>1</bitWidth>
            </field>
            <field>
              <name>HSERDYF</name>
              <bitOffset>3</bitOffset>
              <bitWidth>1</bitWidth>
            </field>
            <field>
              <name>PLLRDYF</name>
              <bitOffset>4</bitOffset>
              <bitWidth>1</bitWidth>
            </field>
            <field>
              <name>MSIRDYF</name>
              <bitOffset>5</bitOffset>
              <bitWidth>1</bitWidth>
            </field>
            <field>
              <name>CSSF</name>
              <bitOffset>7</bitOffset>
              <bitWidth>1</bitWidth>
            </field>
            <field>
              <name>LSIRDYIE</name>
              <bitOffset>8</bitOffset>
              <bitWidth>1</bitWidth>
            </field>
            <field>
              <name>LSERDYIE</name>
              <bitOffset>9</bitOffset>
              <bitWidth>1</bitWidth>
            </field>
            <field>
              <name>HSIRDYIE</name>
              <bitOffset>10</bitOffset>
              <bitWidth>1</bitWidth>
            </field>
            <field>
              <name>HSERDYIE</name>
              <bitOffset>11</bitOffset>
              <bitWidth>1</bitWidth>
            </field>
            <field>
              <name>PLLRDYIE</name>
              <bitOffset>12</bitOffset>
              <bitWidth>1</bitWidth>
            </field>
            <field>
              <name>MSIRDYIE</name>
              <bitOffset>13</bitOffset>
              <bitWidth>1</bitWidth>
            </field>
            <field>
              <name>LSIRDYC</name>
              <bitOffset>16</bitOffset>
              <bitWidth>1</bitWidth>
            </field>
            <field>
              <name>LSERDYC</name>
              <bitOffset>17</bitOffset>
              <bitWidth>1</bitWidth>
            </field>
            <field>
              <name>HSIRDYC</name>
              <bitOffset>18</bitOffset>
              <bitWidth>1</bitWidth>
            </field>
            <field>
              <name>HSERDYC</name>
              <bitOffset>19</bitOffset>
              <bitWidth>1</bitWidth>
            </field>
            <field>
              <name>PLLRDYC</name>
              <bitOffset>20</bitOffset>
              <bitWidth>1</bitWidth>
            </field>
            <field>
              <name>MSIRDYC</name>
              <bitOffset>21</bitOffset>
              <bitWidth>1</bitWidth>
            </field>
            <field>
              <name>CSSC</name>
              <bitOffset>23</bitOffset>
              <bitWidth>1</bitWidth>
            </field>
          </fields>
        </register>
        <register>
          <name>AHBRSTR</name>
          <addressOffset>0x10</addressOffset>
          <size>0x20</size>
          <fields>
            <field>
              <name>GPIOARST</name>
              <bitOffset>0</bitOffset>
              <bitWidth>1</bitWidth>
            </field>
            <field>
              <name>GPIOBRST</name>
              <bitOffset>1</bitOffset>
              <bitWidth>1</bitWidth>
            </field>
            <field>
              <name>GPIOCRST</name>
              <bitOffset>2</bitOffset>
              <bitWidth>1</bitWidth>
            </field>
            <field>
              <name>GPIODRST</name>
              <bitOffset>3</bitOffset>
              <bitWidth>1</bitWidth>
            </field>
            <field>
              <name>GPIOERST</name>
              <bitOffset>4</bitOffset>
              <bitWidth>1</bitWidth>
            </field>
            <field>
              <name>GPIOHRST</name>
              <bitOffset>5</bitOffset>
              <bitWidth>1</bitWidth>
            </field>
            <field>
              <name>CRCRST</name>
              <bitOffset>12</bitOffset>
              <bitWidth>1</bitWidth>
            </field>
            <field>
              <name>FLITFRST</name>
              <bitOffset>15</bitOffset>
              <bitWidth>1</bitWidth>
            </field>
            <field>
              <name>DMA1RST</name>
              <bitOffset>24</bitOffset>
              <bitWidth>1</bitWidth>
            </field>
          </fields>
        </register>
        <register>
          <name>APB2RSTR</name>
          <addressOffset>0x14</addressOffset>
          <size>0x20</size>
          <fields>
            <field>
              <name>SYSCFGRST</name>
              <bitOffset>0</bitOffset>
              <bitWidth>1</bitWidth>
            </field>
            <field>
              <name>TIM9RST</name>
              <bitOffset>2</bitOffset>
              <bitWidth>1</bitWidth>
            </field>
            <field>
              <name>TIM10RST</name>
              <bitOffset>3</bitOffset>
              <bitWidth>1</bitWidth>
            </field>
            <field>
              <name>TIM11RST</name>
              <bitOffset>4</bitOffset>
              <bitWidth>1</bitWidth>
            </field>
            <field>
              <name>ADC1RST</name>
              <bitOffset>9</bitOffset>
              <bitWidth>1</bitWidth>
            </field>
            <field>
              <name>SPI1RST</name>
              <bitOffset>12</bitOffset>
              <bitWidth>1</bitWidth>
            </field>
            <field>
              <name>USART1RST</name>
              <bitOffset>14</bitOffset>
              <bitWidth>1</bitWidth>
            </field>
          </fields>
        </register>
        <register>
          <name>APB1RSTR</name>
          <addressOffset>0x18</addressOffset>
          <size>0x20</size>
          <fields>
            <field>
              <name>TIM2RST</name>
              <bitOffset>0</bitOffset>
              <bitWidth>1</bitWidth>
            </field>
            <field>
              <name>TIM3RST</name>
              <bitOffset>1</bitOffset>
              <bitWidth>1</bitWidth>
            </field>
            <field>
              <name>TIM4RST</name>
              <bitOffset>2</bitOffset>
              <bitWidth>1</bitWidth>
            </field>
            <field>
              <name>TIM6RST</name>
              <bitOffset>4</bitOffset>
              <bitWidth>1</bitWidth>
            </field>
            <field>
              <name>TIM7RST</name>
              <bitOffset>5</bitOffset>
              <bitWidth>1</bitWidth>
            </field>
            <field>
              <name>LCDRST</name>
              <bitOffset>9</bitOffset>
              <bitWidth>1</bitWidth>
            </field>
            <field>
              <name>WWDGRST</name>
              <bitOffset>11</bitOffset>
              <bitWidth>1</bitWidth>
            </field>
            <field>
              <name>SPI2RST</name>
              <bitOffset>14</bitOffset>
              <bitWidth>1</bitWidth>
            </field>
            <field>
              <name>USART2RST</name>
              <bitOffset>17</bitOffset>
              <bitWidth>1</bitWidth>
            </field>
            <field>
              <name>USART3RST</name>
              <bitOffset>18</bitOffset>
              <bitWidth>1</bitWidth>
            </field>
            <field>
              <name>I2C1RST</name>
              <bitOffset>21</bitOffset>
              <bitWidth>1</bitWidth>
            </field>
            <field>
              <name>I2C2RST</name>
              <bitOffset>22</bitOffset>
              <bitWidth>1</bitWidth>
            </field>
            <field>
              <name>USBRST</name>
              <bitOffset>23</bitOffset>
              <bitWidth>1</bitWidth>
            </field>
            <field>
              <name>PWRRST</name>
              <bitOffset>28</bitOffset>
              <bitWidth>1</bitWidth>
            </field>
            <field>
              <name>DACRST</name>
              <bitOffset>29</bitOffset>
              <bitWidth>1</bitWidth>
            </field>
            <field>
              <name>COMPRST</name>
              <bitOffset>31</bitOffset>
              <bitWidth>1</bitWidth>
            </field>
          </fields>
        </register>
        <register>
          <name>AHBENR</name>
          <addressOffset>0x1c</addressOffset>
          <size>0x20</size>
          <fields>
            <field>
              <name>GPIOAEN</name>
              <bitOffset>0</bitOffset>
              <bitWidth>1</bitWidth>
            </field>
            <field>
              <name>GPIOBEN</name>
              <bitOffset>1</bitOffset>
              <bitWidth>1</bitWidth>
            </field>
            <field>
              <name>GPIOCEN</name>
              <bitOffset>2</bitOffset>
              <bitWidth>1</bitWidth>
            </field>
            <field>
              <name>GPIODEN</name>
              <bitOffset>3</bitOffset>
              <bitWidth>1</bitWidth>
            </field>
            <field>
              <name>GPIOEEN</name>
              <bitOffset>4</bitOffset>
              <bitWidth>1</bitWidth>
            </field>
            <field>
              <name>GPIOHEN</name>
              <bitOffset>5</bitOffset>
              <bitWidth>1</bitWidth>
            </field>
            <field>
              <name>CRCEN</name>
              <bitOffset>12</bitOffset>
              <bitWidth>1</bitWidth>
            </field>
            <field>
              <name>FLITFEN</name>
              <bitOffset>15</bitOffset>
              <bitWidth>1</bitWidth>
            </field>
            <field>
              <name>DMA1EN</name>
              <bitOffset>24</bitOffset>
              <bitWidth>1</bitWidth>
            </field>
          </fields>
        </register>
        <register>
          <name>APB2ENR</name>
          <addressOffset>0x20</addressOffset>
          <size>0x20</size>
          <fields>
            <field>
              <name>SYSCFGEN</name>
              <bitOffset>0</bitOffset>
              <bitWidth>1</bitWidth>
            </field>
            <field>
              <name>TIM9EN</name>
              <bitOffset>2</bitOffset>
              <bitWidth>1</bitWidth>
            </field>
            <field>
              <name>TIM10EN</name>
              <bitOffset>3</bitOffset>
              <bitWidth>1</bitWidth>
            </field>
            <field>
              <name>TIM11EN</name>
              <bitOffset>4</bitOffset>
              <bitWidth>1</bitWidth>
            </field>
            <field>
              <name>ADC1EN</name>
              <bitOffset>9</bitOffset>
              <bitWidth>1</bitWidth>
            </field>
            <field>
              <name>SPI1EN</name>
              <bitOffset>12</bitOffset>
              <bitWidth>1</bitWidth>
            </field>
            <field>
              <name>USART1EN</name>
              <bitOffset>14</bitOffset>
              <bitWidth>1</bitWidth>
            </field>
          </fields>
        </register>
        <register>
          <name>APB1ENR</name>
          <addressOffset>0x24</addressOffset>
          <size>0x20</size>
          <fields>
            <field>
              <name>TIM2EN</name>
              <bitOffset>0</bitOffset>
              <bitWidth>1</bitWidth>
            </field>
            <field>
              <name>TIM3EN</name>
              <bitOffset>1</bitOffset>
              <bitWidth>1</bitWidth>
            </field>
            <field>
              <name>TIM4EN</name>
              <bitOffset>2</bitOffset>
              <bitWidth>1</bitWidth>
            </field>
            <field>
              <name>TIM6EN</name>
              <bitOffset>4</bitOffset>
              <bitWidth>1</bitWidth>
            </field>
            <field>
              <name>TIM7EN</name>
              <bitOffset>5</bitOffset>
              <bitWidth>1</bitWidth>
            </field>
            <field>
              <name>LCDEN</name>
              <bitOffset>9</bitOffset>
              <bitWidth>1</bitWidth>
            </field>
            <field>
              <name>WWDGEN</name>
              <bitOffset>11</bitOffset>
              <bitWidth>1</bitWidth>
            </field>
            <field>
              <name>SPI2EN</name>
              <bitOffset>14</bitOffset>
              <bitWidth>1</bitWidth>
            </field>
            <field>
              <name>USART2EN</name>
              <bitOffset>17</bitOffset>
              <bitWidth>1</bitWidth>
            </field>
            <field>
              <name>USART3EN</name>
              <bitOffset>18</bitOffset>
              <bitWidth>1</bitWidth>
            </field>
            <field>
              <name>I2C1EN</name>
              <bitOffset>21</bitOffset>
              <bitWidth>1</bitWidth>
            </field>
            <field>
              <name>I2C2EN</name>
              <bitOffset>22</bitOffset>
              <bitWidth>1</bitWidth>
            </field>
            <field>
              <name>USBEN</name>
              <bitOffset>23</bitOffset>
              <bitWidth>1</bitWidth>
            </field>
            <field>
              <name>PWREN</name>
              <bitOffset>28</bitOffset>
              <bitWidth>1</bitWidth>
            </field>
            <field>
              <name>DACEN</name>
              <bitOffset>29</bitOffset>
              <bitWidth>1</bitWidth>
            </field>
            <field>
              <name>COMPEN</name>
              <bitOffset>31</bitOffset>
              <bitWidth>1</bitWidth>
            </field>
          </fields>
        </register>
        <register>
          <name>AHBLPENR</name>
          <addressOffset>0x28</addressOffset>
          <size>0x20</size>
          <fields>
            <field>
              <name>GPIOALPEN</name>
              <bitOffset>0</bitOffset>
              <bitWidth>1</bitWidth>
            </field>
            <field>
              <name>GPIOBLPEN</name>
              <bitOffset>1</bitOffset>
              <bitWidth>1</bitWidth>
            </field>
            <field>
              <name>GPIOCLPEN</name>
              <bitOffset>2</bitOffset>
              <bitWidth>1</bitWidth>
            </field>
            <field>
              <name>GPIODLPEN</name>
              <bitOffset>3</bitOffset>
              <bitWidth>1</bitWidth>
            </field>
            <field>
              <name>GPIOELPEN</name>
              <bitOffset>4</bitOffset>
              <bitWidth>1</bitWidth>
            </field>
            <field>
              <name>GPIOHLPEN</name>
              <bitOffset>5</bitOffset>
              <bitWidth>1</bitWidth>
            </field>
            <field>
              <name>CRCLPEN</name>
              <bitOffset>12</bitOffset>
              <bitWidth>1</bitWidth>
            </field>
            <field>
              <name>FLITFLPEN</name>
              <bitOffset>15</bitOffset>
              <bitWidth>1</bitWidth>
            </field>
            <field>
              <name>SRAMLPEN</name>
              <bitOffset>16</bitOffset>
              <bitWidth>1</bitWidth>
            </field>
            <field>
              <name>DMA1LPEN</name>
              <bitOffset>24</bitOffset>
              <bitWidth>1</bitWidth>
            </field>
          </fields>
        </register>
        <register>
          <name>APB2LPENR</name>
          <addressOffset>0x2c</addressOffset>
          <size>0x20</size>
          <fields>
            <field>
              <name>SYSCFGLPEN</name>
              <bitOffset>0</bitOffset>
              <bitWidth>1</bitWidth>
            </field>
            <field>
              <name>TIM9LPEN</name>
              <bitOffset>2</bitOffset>
              <bitWidth>1</bitWidth>
            </field>
            <field>
              <name>TIM10LPEN</name>
              <bitOffset>3</bitOffset>
              <bitWidth>1</bitWidth>
            </field>
            <field>
              <name>TIM11LPEN</name>
              <bitOffset>4</bitOffset>
              <bitWidth>1</bitWidth>
            </field>
            <field>
              <name>ADC1LPEN</name>
              <bitOffset>9</bitOffset>
              <bitWidth>1</bitWidth>
            </field>
            <field>
              <name>SPI1LPEN</name>
              <bitOffset>12</bitOffset>
              <bitWidth>1</bitWidth>
            </field>
            <field>
              <name>USART1LPEN</name>
              <bitOffset>14</bitOffset>
              <bitWidth>1</bitWidth>
            </field>
          </fields>
        </register>
        <register>
          <name>APB1LPENR</name>
          <addressOffset>0x30</addressOffset>
          <size>0x20</size>
          <fields>
            <field>
              <name>TIM2LPEN</name>
              <bitOffset>0</bitOffset>
              <bitWidth>1</bitWidth>
            </field>
            <field>
              <name>TIM3LPEN</name>
              <bitOffset>1</bitOffset>
              <bitWidth>1</bitWidth>
            </field>
            <field>
              <name>TIM4LPEN</name>
              <bitOffset>2</bitOffset>
              <bitWidth>1</bitWidth>
            </field>
            <field>
              <name>TIM6LPEN</name>
              <bitOffset>4</bitOffset>
              <bitWidth>1</bitWidth>
            </field>
            <field>
              <name>TIM7LPEN</name>
              <bitOffset>5</bitOffset>
              <bitWidth>1</bitWidth>
            </field>
            <field>
              <name>LCDLPEN</name>
              <bitOffset>9</bitOffset>
              <bitWidth>1</bitWidth>
            </field>
            <field>
              <name>WWDGLPEN</name>
              <bitOffset>11</bitOffset>
              <bitWidth>1</bitWidth>
            </field>
            <field>
              <name>SPI2LPEN</name>
              <bitOffset>14</bitOffset>
              <bitWidth>1</bitWidth>
            </field>
            <field>
              <name>USART2LPEN</name>
              <bitOffset>17</bitOffset>
              <bitWidth>1</bitWidth>
            </field>
            <field>
              <name>USART3LPEN</name>
              <bitOffset>18</bitOffset>
              <bitWidth>1</bitWidth>
            </field>
            <field>
              <name>I2C1LPEN</name>
              <bitOffset>21</bitOffset>
              <bitWidth>1</bitWidth>
            </field>
            <field>
              <name>I2C2LPEN</name>
              <bitOffset>22</bitOffset>
              <bitWidth>1</bitWidth>
            </field>
            <field>
              <name>USBLPEN</name>
              <bitOffset>23</bitOffset>
              <bitWidth>1</bitWidth>
            </field>
            <field>
              <name>PWRLPEN</name>
              <bitOffset>28</bitOffset>
              <bitWidth>1</bitWidth>
            </field>
            <field>
              <name>DACLPEN</name>
              <bitOffset>29</bitOffset>
              <bitWidth>1</bitWidth>
            </field>
            <field>
              <name>COMPLPEN</name>
              <bitOffset>31</bitOffset>
              <bitWidth>1</bitWidth>
            </field>
          </fields>
        </register>
        <register>
          <name>CSR</name>
          <addressOffset>0x34</addressOffset>
          <size>0x20</size>
          <fields>
            <field>
              <name>LSION</name>
              <bitOffset>0</bitOffset>
              <bitWidth>1</bitWidth>
            </field>
            <field>
              <name>LSIRDY</name>
              <bitOffset>1</bitOffset>
              <bitWidth>1</bitWidth>
            </field>
            <field>
              <name>LSEON</name>
              <bitOffset>8</bitOffset>
              <bitWidth>1</bitWidth>
            </field>
            <field>
              <name>LSERDY</name>
              <bitOffset>9</bitOffset>
              <bitWidth>1</bitWidth>
            </field>
            <field>
              <name>LSEBYP</name>
              <bitOffset>10</bitOffset>
              <bitWidth>1</bitWidth>
            </field>
            <field>
              <name>RTCSEL_LSE</name>
              <bitOffset>16</bitOffset>
              <bitWidth>1</bitWidth>
            </field>
            <field>
              <name>RTCSEL_LSI</name>
              <bitOffset>17</bitOffset>
              <bitWidth>1</bitWidth>
            </field>
            <field>
              <name>RTCEN</name>
              <bitOffset>22</bitOffset>
              <bitWidth>1</bitWidth>
            </field>
            <field>
              <name>RTCRST</name>
              <bitOffset>23</bitOffset>
              <bitWidth>1</bitWidth>
            </field>
            <field>
              <name>RMVF</name>
              <bitOffset>24</bitOffset>
              <bitWidth>1</bitWidth>
            </field>
            <field>
              <name>OBLRSTF</name>
              <bitOffset>25</bitOffset>
              <bitWidth>1</bitWidth>
            </field>
            <field>
              <name>PINRSTF</name>
              <bitOffset>26</bitOffset>
              <bitWidth>1</bitWidth>
            </field>
            <field>
              <name>PORRSTF</name>
              <bitOffset>27</bitOffset>
              <bitWidth>1</bitWidth>
            </field>
            <field>
              <name>SFTRSTF</name>
              <bitOffset>28</bitOffset>
              <bitWidth>1</bitWidth>
            </field>
            <field>
              <name>IWDGRSTF</name>
              <bitOffset>29</bitOffset>
              <bitWidth>1</bitWidth>
            </field>
            <field>
              <name>WWDGRSTF</name>
              <bitOffset>30</bitOffset>
              <bitWidth>1</bitWidth>
            </field>
            <field>
              <name>LPWRRSTF</name>
              <bitOffset>31</bitOffset>
              <bitWidth>1</bitWidth>
            </field>
          </fields>
        </register>
      </registers>
    </peripheral>
    <peripheral>
      <name>FLASH</name>
      <baseAddress>0x40023c00</baseAddress>
      <registers>
        <register>
          <name>ACR</name>
          <addressOffset>0x0</addressOffset>
          <size>0x20</size>
          <fields>
            <field>
              <name>LATENCY</name>
              <bitOffset>0</bitOffset>
              <bitWidth>1</bitWidth>
            </field>
            <field>
              <name>PRFTEN</name>
              <bitOffset>1</bitOffset>
              <bitWidth>1</bitWidth>
            </field>
            <field>
              <name>ACC64</name>
              <bitOffset>2</bitOffset>
              <bitWidth>1</bitWidth>
            </field>
            <field>
              <name>SLEEP_PD</name>
              <bitOffset>3</bitOffset>
              <bitWidth>1</bitWidth>
            </field>
            <field>
              <name>RUN_PD</name>
              <bitOffset>4</bitOffset>
              <bitWidth>1</bitWidth>
            </field>
          </fields>
        </register>
        <register>
          <name>PECR</name>
          <addressOffset>0x4</addressOffset>
          <size>0x20</size>
          <fields>
            <field>
              <name>PELOCK</name>
              <bitOffset>0</bitOffset>
              <bitWidth>1</bitWidth>
            </field>
            <field>
              <name>PRGLOCK</name>
              <bitOffset>1</bitOffset>
              <bitWidth>1</bitWidth>
            </field>
            <field>
              <name>OPTLOCK</name>
              <bitOffset>2</bitOffset>
              <bitWidth>1</bitWidth>
            </field>
            <field>
              <name>PROG</name>
              <bitOffset>3</bitOffset>
              <bitWidth>1</bitWidth>
            </field>
            <field>
              <name>DATA</name>
              <bitOffset>4</bitOffset>
              <bitWidth>1</bitWidth>
            </field>
            <field>
              <name>FTDW</name>
              <bitOffset>8</bitOffset>
              <bitWidth>1</bitWidth>
            </field>
            <field>
              <name>ERASE</name>
              <bitOffset>9</bitOffset>
              <bitWidth>1</bitWidth>
            </field>
            <field>
              <name>FPRG</name>
              <bitOffset>10</bitOffset>
              <bitWidth>1</bitWidth>
            </field>
            <field>
              <name>EOPIE</name>
              <bitOffset>16</bitOffset>
              <bitWidth>1</bitWidth>
            </field>
            <field>
              <name>ERRIE</name>
              <bitOffset>17</bitOffset>
              <bitWidth>1</bitWidth>
            </field>
            <field>
              <name>OBL_LAUNCH</name>
              <bitOffset>18</bitOffset>
              <bitWidth>1</bitWidth>
            </field>
          </fields>
        </register>
        <register>
          <name>PDKEYR</name>
          <addressOffset>0x8</addressOffset>
          <size>0x20</size>
          <fields>
            <field>
              <name>PDKEYR</name>
              <bitOffset>0</bitOffset>
              <bitWidth>32</bitWidth>
            </field>
          </fields>
        </register>
        <register>
          <name>PEKEYR</name>
          <addressOffset>0xc</addressOffset>
          <size>0x20</size>
          <fields>
            <field>
              <name>PEKEYR</name>
              <bitOffset>0</bitOffset>
              <bitWidth>32</bitWidth>
            </field>
          </fields>
        </register>
        <register>
          <name>PRGKEYR</name>
          <addressOffset>0x10</addressOffset>
          <size>0x20</size>
          <fields>
            <field>
              <name>PRGKEYR</name>
              <bitOffset>0</bitOffset>
              <bitWidth>32</bitWidth>
            </field>
          </fields>
        </register>
        <register>
          <name>OPTKEYR</name>
          <addressOffset>0x14</addressOffset>
          <size>0x20</size>
          <fields>
            <field>
              <name>OPTKEYR</name>
              <bitOffset>0</bitOffset>
              <bitWidth>32</bitWidth>
            </field>
          </fields>
        </register>
        <register>
          <name>SR</name>
          <addressOffset>0x18</addressOffset>
          <size>0x20</size>
          <fields>
            <field>
              <name>BSY</name>
              <bitOffset>0</bitOffset>
              <bitWidth>1</bitWidth>
            </field>
            <field>
              <name>EOP</name>
              <bitOffset>1</bitOffset>
              <bitWidth>1</bitWidth>
            </field>
            <field>
              <name>ENDHV</name>
              <bitOffset>2</bitOffset>
              <bitWidth>1</bitWidth>
            </field>
            <field>
              <name>READY</name>
              <bitOffset>3</bitOffset>
              <bitWidth>1</bitWidth>
            </field>
            <field>
              <name>WRPERR</name>
              <bitOffset>8</bitOffset>
              <bitWidth>1</bitWidth>
            </field>
            <field>
              <name>PGAERR</name>
              <bitOffset>9</bitOffset>
              <bitWidth>1</bitWidth>
            </field>
            <field>
              <name>SIZERR</name>
              <bitOffset>10</bitOffset>
              <bitWidth>1</bitWidth>
            </field>
            <field>
              <name>OPTVERR</name>
              <bitOffset>11</bitOffset>
              <bitWidth>1</bitWidth>
            </field>
          </fields>
        </register>
        <register>
          <name>OBR</name>
          <addressOffset>0x1c</addressOffset>
          <size>0x20</size>
          <fields>
            <field>
              <name>RDPRT</name>
              <bitOffset>0</bitOffset>
              <bitWidth>8</bitWidth>
            </field>
            <field>
              <name>BOR_LEV</name>
              <bitOffset>16</bitOffset>
              <bitWidth>4</bitWidth>
            </field>
            <field>
              <name>USER</name>
              <bitOffset>20</bitOffset>
              <bitWidth>3</bitWidth>
            </field>
            <field>
              <name>nRST_STOP</name>
              <bitOffset>21</bitOffset>
              <bitWidth>1</bitWidth>
            </field>
            <field>
              <name>nRST_STDBY</name>
              <bitOffset>22</bitOffset>
              <bitWidth>1</bitWidth>
            </field>
          </fields>
        </register>
        <register>
          <name>WRPR1</name>
          <addressOffset>0x20</addressOffset>
          <size>0x20</size>
          <fields>
            <field>
              <name>WRP</name>
              <bitOffset>0</bitOffset>
              <bitWidth>32</bitWidth>
            </field>
          </fields>
        </register>
      </registers>
    </peripheral>
    <peripheral>
      <name>DMA1</name>
      <baseAddress>0x40026000</baseAddress>
      <registers>
        <register>
          <name>ISR</name>
          <addressOffset>0x0</addressOffset>
          <size>0x20</size>
          <fields>
            <field>
              <name>GIF1</name>
              <bitOffset>0</bitOffset>
              <bitWidth>1</bitWidth>
            </field>
            <field>
              <name>TCIF1</name>
              <bitOffset>1</bitOffset>
              <bitWidth>1</bitWidth>
            </field>
            <field>
              <name>HTIF1</name>
              <bitOffset>2</bitOffset>
              <bitWidth>1</bitWidth>
            </field>
            <field>
              <name>TEIF1</name>
              <bitOffset>3</bitOffset>
              <bitWidth>1</bitWidth>
            </field>
            <field>
              <name>GIF2</name>
              <bitOffset>4</bitOffset>
              <bitWidth>1</bitWidth>
            </field>
            <field>
              <name>TCIF2</name>
              <bitOffset>5</bitOffset>
              <bitWidth>1</bitWidth>
            </field>
            <field>
              <name>HTIF2</name>
              <bitOffset>6</bitOffset>
              <bitWidth>1</bitWidth>
            </field>
            <field>
              <name>TEIF2</name>
              <bitOffset>7</bitOffset>
              <bitWidth>1</bitWidth>
            </field>
            <field>
              <name>GIF3</name>
              <bitOffset>8</bitOffset>
              <bitWidth>1</bitWidth>
            </field>
            <field>
              <name>TCIF3</name>
              <bitOffset>9</bitOffset>
              <bitWidth>1</bitWidth>
            </field>
            <field>
              <name>HTIF3</name>
              <bitOffset>10</bitOffset>
              <bitWidth>1</bitWidth>
            </field>
            <field>
              <name>TEIF3</name>
              <bitOffset>11</bitOffset>
              <bitWidth>1</bitWidth>
            </field>
            <field>
              <name>GIF4</name>
              <bitOffset>12</bitOffset>
              <bitWidth>1</bitWidth>
            </field>
            <field>
              <name>TCIF4</name>
              <bitOffset>13</bitOffset>
              <bitWidth>1</bitWidth>
            </field>
            <field>
              <name>HTIF4</name>
              <bitOffset>14</bitOffset>
              <bitWidth>1</bitWidth>
            </field>
            <field>
              <name>TEIF4</name>
              <bitOffset>15</bitOffset>
              <bitWidth>1</bitWidth>
            </field>
            <field>
              <name>GIF5</name>
              <bitOffset>16</bitOffset>
              <bitWidth>1</bitWidth>
            </field>
            <field>
              <name>TCIF5</name>
              <bitOffset>17</bitOffset>
              <bitWidth>1</bitWidth>
            </field>
            <field>
              <name>HTIF5</name>
              <bitOffset>18</bitOffset>
              <bitWidth>1</bitWidth>
            </field>
            <field>
              <name>TEIF5</name>
              <bitOffset>19</bitOffset>
              <bitWidth>1</bitWidth>
            </field>
            <field>
              <name>GIF6</name>
              <bitOffset>20</bitOffset>
              <bitWidth>1</bitWidth>
            </field>
            <field>
              <name>TCIF6</name>
              <bitOffset>21</bitOffset>
              <bitWidth>1</bitWidth>
            </field>
            <field>
              <name>HTIF6</name>
              <bitOffset>22</bitOffset>
              <bitWidth>1</bitWidth>
            </field>
            <field>
              <name>TEIF6</name>
              <bitOffset>23</bitOffset>
              <bitWidth>1</bitWidth>
            </field>
            <field>
              <name>GIF7</name>
              <bitOffset>24</bitOffset>
              <bitWidth>1</bitWidth>
            </field>
            <field>
              <name>TCIF7</name>
              <bitOffset>25</bitOffset>
              <bitWidth>1</bitWidth>
            </field>
            <field>
              <name>HTIF7</name>
              <bitOffset>26</bitOffset>
              <bitWidth>1</bitWidth>
            </field>
            <field>
              <name>TEIF7</name>
              <bitOffset>27</bitOffset>
              <bitWidth>1</bitWidth>
            </field>
          </fields>
        </register>
        <register>
          <name>IFCR</name>
          <addressOffset>0x4</addressOffset>
          <size>0x20</size>
          <fields>
            <field>
              <name>CGIF1</name>
              <bitOffset>0</bitOffset>
              <bitWidth>1</bitWidth>
            </field>
            <field>
              <name>CTCIF1</name>
              <bitOffset>1</bitOffset>
              <bitWidth>1</bitWidth>
            </field>
            <field>
              <name>CHTIF1</name>
              <bitOffset>2</bitOffset>
              <bitWidth>1</bitWidth>
            </field>
            <field>
              <name>CTEIF1</name>
              <bitOffset>3</bitOffset>
              <bitWidth>1</bitWidth>
            </field>
            <field>
              <name>CGIF2</name>
              <bitOffset>4</bitOffset>
              <bitWidth>1</bitWidth>
            </field>
            <field>
              <name>CTCIF2</name>
              <bitOffset>5</bitOffset>
              <bitWidth>1</bitWidth>
            </field>
            <field>
              <name>CHTIF2</name>
              <bitOffset>6</bitOffset>
              <bitWidth>1</bitWidth>
            </field>
            <field>
              <name>CTEIF2</name>
              <bitOffset>7</bitOffset>
              <bitWidth>1</bitWidth>
            </field>
            <field>
              <name>CGIF3</name>
              <bitOffset>8</bitOffset>
              <bitWidth>1</bitWidth>
            </field>
            <field>
              <name>CTCIF3</name>
              <bitOffset>9</bitOffset>
              <bitWidth>1</bitWidth>
            </field>
            <field>
              <name>CHTIF3</name>
              <bitOffset>10</bitOffset>
              <bitWidth>1</bitWidth>
            </field>
            <field>
              <name>CTEIF3</name>
              <bitOffset>11</bitOffset>
              <bitWidth>1</bitWidth>
            </field>
            <field>
              <name>CGIF4</name>
              <bitOffset>12</bitOffset>
              <bitWidth>1</bitWidth>
            </field>
            <field>
              <name>CTCIF4</name>
              <bitOffset>13</bitOffset>
              <bitWidth>1</bitWidth>
            </field>
            <field>
              <name>CHTIF4</name>
              <bitOffset>14</bitOffset>
              <bitWidth>1</bitWidth>
            </field>
            <field>
              <name>CTEIF4</name>
              <bitOffset>15</bitOffset>
              <bitWidth>1</bitWidth>
            </field>
            <field>
              <name>CGIF5</name>
              <bitOffset>16</bitOffset>
              <bitWidth>1</bitWidth>
            </field>
            <field>
              <name>CTCIF5</name>
              <bitOffset>17</bitOffset>
              <bitWidth>1</bitWidth>
            </field>
            <field>
              <name>CHTIF5</name>
              <bitOffset>18</bitOffset>
              <bitWidth>1</bitWidth>
            </field>
            <field>
              <name>CTEIF5</name>
              <bitOffset>19</bitOffset>
              <bitWidth>1</bitWidth>
            </field>
            <field>
              <name>CGIF6</name>
              <bitOffset>20</bitOffset>
              <bitWidth>1</bitWidth>
            </field>
            <field>
              <name>CTCIF6</name>
              <bitOffset>21</bitOffset>
              <bitWidth>1</bitWidth>
            </field>
            <field>
              <name>CHTIF6</name>
              <bitOffset>22</bitOffset>
              <bitWidth>1</bitWidth>
            </field>
            <field>
              <name>CTEIF6</name>
              <bitOffset>23</bitOffset>
              <bitWidth>1</bitWidth>
            </field>
            <field>
              <name>CGIF7</name>
              <bitOffset>24</bitOffset>
              <bitWidth>1</bitWidth>
            </field>
            <field>
              <name>CTCIF7</name>
              <bitOffset>25</bitOffset>
              <bitWidth>1</bitWidth>
            </field>
            <field>
              <name>CHTIF7</name>
              <bitOffset>26</bitOffset>
              <bitWidth>1</bitWidth>
            </field>
            <field>
              <name>CTEIF7</name>
              <bitOffset>27</bitOffset>
              <bitWidth>1</bitWidth>
            </field>
          </fields>
        </register>
        <register>
          <name>CCR1</name>
          <addressOffset>0x8</addressOffset>
          <size>0x20</size>
          <fields>
            <field>
              <name>EN</name>
              <bitOffset>0</bitOffset>
              <bitWidth>1</bitWidth>
            </field>
            <field>
              <name>TCIE</name>
              <bitOffset>1</bitOffset>
              <bitWidth>1</bitWidth>
            </field>
            <field>
              <name>HTIE</name>
              <bitOffset>2</bitOffset>
              <bitWidth>1</bitWidth>
            </field>
            <field>
              <name>TEIE</name>
              <bitOffset>3</bitOffset>
              <bitWidth>1</bitWidth>
            </field>
            <field>
              <name>DIR</name>
              <bitOffset>4</bitOffset>
              <bitWidth>1</bitWidth>
            </field>
            <field>
              <name>CIRC</name>
              <bitOffset>5</bitOffset>
              <bitWidth>1</bitWidth>
            </field>
            <field>
              <name>PINC</name>
              <bitOffset>6</bitOffset>
              <bitWidth>1</bitWidth>
            </field>
            <field>
              <name>MINC</name>
              <bitOffset>7</bitOffset>
              <bitWidth>1</bitWidth>
            </field>
            <field>
              <name>PSIZE</name>
              <bitOffset>8</bitOffset>
              <bitWidth>2</bitWidth>
            </field>
            <field>
              <name>MSIZE</name>
              <bitOffset>10</bitOffset>
              <bitWidth>2</bitWidth>
            </field>
            <field>
              <name>PL</name>
              <bitOffset>12</bitOffset>
              <bitWidth>2</bitWidth>
            </field>
            <field>
              <name>MEM2MEM</name>
              <bitOffset>14</bitOffset>
              <bitWidth>1</bitWidth>
            </field>
          </fields>
        </register>
        <register>
          <name>CNDTR1</name>
          <addressOffset>0xc</addressOffset>
          <size>0x20</size>
          <fields>
            <field>
              <name>NDT</name>
              <bitOffset>0</bitOffset>
              <bitWidth>16</bitWidth>
            </field>
          </fields>
        </register>
        <register>
          <name>CPAR1</name>
          <addressOffset>0x10</addressOffset>
          <size>0x20</size>
          <fields>
            <field>
              <name>PA</name>
              <bitOffset>0</bitOffset>
              <bitWidth>32</bitWidth>
            </field>
          </fields>
        </register>
        <register>
          <name>CMAR1</name>
          <addressOffset>0x14</addressOffset>
          <size>0x20</size>
          <fields>
            <field>
              <name>MA</name>
              <bitOffset>0</bitOffset>
              <bitWidth>32</bitWidth>
            </field>
          </fields>
        </register>
        <register>
          <name>CCR2</name>
          <addressOffset>0x1c</addressOffset>
          <size>0x20</size>
          <fields>
            <field>
              <name>EN</name>
              <bitOffset>0</bitOffset>
              <bitWidth>1</bitWidth>
            </field>
            <field>
              <name>TCIE</name>
              <bitOffset>1</bitOffset>
              <bitWidth>1</bitWidth>
            </field>
            <field>
              <name>HTIE</name>
              <bitOffset>2</bitOffset>
              <bitWidth>1</bitWidth>
            </field>
            <field>
              <name>TEIE</name>
              <bitOffset>3</bitOffset>
              <bitWidth>1</bitWidth>
            </field>
            <field>
              <name>DIR</name>
              <bitOffset>4</bitOffset>
              <bitWidth>1</bitWidth>
            </field>
            <field>
              <name>CIRC</name>
              <bitOffset>5</bitOffset>
              <bitWidth>1</bitWidth>
            </field>
            <field>
              <name>PINC</name>
              <bitOffset>6</bitOffset>
              <bitWidth>1</bitWidth>
            </field>
            <field>
              <name>MINC</name>
              <bitOffset>7</bitOffset>
              <bitWidth>1</bitWidth>
            </field>
            <field>
              <name>PSIZE</name>
              <bitOffset>8</bitOffset>
              <bitWidth>2</bitWidth>
            </field>
            <field>
              <name>MSIZE</name>
              <bitOffset>10</bitOffset>
              <bitWidth>2</bitWidth>
            </field>
            <field>
              <name>PL</name>
              <bitOffset>12</bitOffset>
              <bitWidth>2</bitWidth>
            </field>
            <field>
              <name>MEM2MEM</name>
              <bitOffset>14</bitOffset>
              <bitWidth>1</bitWidth>
            </field>
          </fields>
        </register>
        <register>
          <name>CNDTR2</name>
          <addressOffset>0x20</addressOffset>
          <size>0x20</size>
          <fields>
            <field>
              <name>NDT</name>
              <bitOffset>0</bitOffset>
              <bitWidth>16</bitWidth>
            </field>
          </fields>
        </register>
        <register>
          <name>CPAR2</name>
          <addressOffset>0x24</addressOffset>
          <size>0x20</size>
          <fields>
            <field>
              <name>PA</name>
              <bitOffset>0</bitOffset>
              <bitWidth>32</bitWidth>
            </field>
          </fields>
        </register>
        <register>
          <name>CMAR2</name>
          <addressOffset>0x28</addressOffset>
          <size>0x20</size>
          <fields>
            <field>
              <name>MA</name>
              <bitOffset>0</bitOffset>
              <bitWidth>32</bitWidth>
            </field>
          </fields>
        </register>
        <register>
          <name>CCR3</name>
          <addressOffset>0x30</addressOffset>
          <size>0x20</size>
          <fields>
            <field>
              <name>EN</name>
              <bitOffset>0</bitOffset>
              <bitWidth>1</bitWidth>
            </field>
            <field>
              <name>TCIE</name>
              <bitOffset>1</bitOffset>
              <bitWidth>1</bitWidth>
            </field>
            <field>
              <name>HTIE</name>
              <bitOffset>2</bitOffset>
              <bitWidth>1</bitWidth>
            </field>
            <field>
              <name>TEIE</name>
              <bitOffset>3</bitOffset>
              <bitWidth>1</bitWidth>
            </field>
            <field>
              <name>DIR</name>
              <bitOffset>4</bitOffset>
              <bitWidth>1</bitWidth>
            </field>
            <field>
              <name>CIRC</name>
              <bitOffset>5</bitOffset>
              <bitWidth>1</bitWidth>
            </field>
            <field>
              <name>PINC</name>
              <bitOffset>6</bitOffset>
              <bitWidth>1</bitWidth>
            </field>
            <field>
              <name>MINC</name>
              <bitOffset>7</bitOffset>
              <bitWidth>1</bitWidth>
            </field>
            <field>
              <name>PSIZE</name>
              <bitOffset>8</bitOffset>
              <bitWidth>2</bitWidth>
            </field>
            <field>
              <name>MSIZE</name>
              <bitOffset>10</bitOffset>
              <bitWidth>2</bitWidth>
            </field>
            <field>
              <name>PL</name>
              <bitOffset>12</bitOffset>
              <bitWidth>2</bitWidth>
            </field>
            <field>
              <name>MEM2MEM</name>
              <bitOffset>14</bitOffset>
              <bitWidth>1</bitWidth>
            </field>
          </fields>
        </register>
        <register>
          <name>CNDTR3</name>
          <addressOffset>0x34</addressOffset>
          <size>0x20</size>
          <fields>
            <field>
              <name>NDT</name>
              <bitOffset>0</bitOffset>
              <bitWidth>16</bitWidth>
            </field>
          </fields>
        </register>
        <register>
          <name>CPAR3</name>
          <addressOffset>0x38</addressOffset>
          <size>0x20</size>
          <fields>
            <field>
              <name>PA</name>
              <bitOffset>0</bitOffset>
              <bitWidth>32</bitWidth>
            </field>
          </fields>
        </register>
        <register>
          <name>CMAR3</name>
          <addressOffset>0x3c</addressOffset>
          <size>0x20</size>
          <fields>
            <field>
              <name>MA</name>
              <bitOffset>0</bitOffset>
              <bitWidth>32</bitWidth>
            </field>
          </fields>
        </register>
        <register>
          <name>CCR4</name>
          <addressOffset>0x44</addressOffset>
          <size>0x20</size>
          <fields>
            <field>
              <name>EN</name>
              <bitOffset>0</bitOffset>
              <bitWidth>1</bitWidth>
            </field>
            <field>
              <name>TCIE</name>
              <bitOffset>1</bitOffset>
              <bitWidth>1</bitWidth>
            </field>
            <field>
              <name>HTIE</name>
              <bitOffset>2</bitOffset>
              <bitWidth>1</bitWidth>
            </field>
            <field>
              <name>TEIE</name>
              <bitOffset>3</bitOffset>
              <bitWidth>1</bitWidth>
            </field>
            <field>
              <name>DIR</name>
              <bitOffset>4</bitOffset>
              <bitWidth>1</bitWidth>
            </field>
            <field>
              <name>CIRC</name>
              <bitOffset>5</bitOffset>
              <bitWidth>1</bitWidth>
            </field>
            <field>
              <name>PINC</name>
              <bitOffset>6</bitOffset>
              <bitWidth>1</bitWidth>
            </field>
            <field>
              <name>MINC</name>
              <bitOffset>7</bitOffset>
              <bitWidth>1</bitWidth>
            </field>
            <field>
              <name>PSIZE</name>
              <bitOffset>8</bitOffset>
              <bitWidth>2</bitWidth>
            </field>
            <field>
              <name>MSIZE</name>
              <bitOffset>10</bitOffset>
              <bitWidth>2</bitWidth>
            </field>
            <field>
              <name>PL</name>
              <bitOffset>12</bitOffset>
              <bitWidth>2</bitWidth>
            </field>
            <field>
              <name>MEM2MEM</name>
              <bitOffset>14</bitOffset>
              <bitWidth>1</bitWidth>
            </field>
          </fields>
        </register>
        <register>
          <name>CNDTR4</name>
          <addressOffset>0x48</addressOffset>
          <size>0x20</size>
          <fields>
            <field>
              <name>NDT</name>
              <bitOffset>0</bitOffset>
              <bitWidth>16</bitWidth>
            </field>
          </fields>
        </register>
        <register>
          <name>CPAR4</name>
          <addressOffset>0x4c</addressOffset>
          <size>0x20</size>
          <fields>
            <field>
              <name>PA</name>
              <bitOffset>0</bitOffset>
              <bitWidth>32</bitWidth>
            </field>
          </fields>
        </register>
        <register>
          <name>CMAR4</name>
          <addressOffset>0x50</addressOffset>
          <size>0x20</size>
          <fields>
            <field>
              <name>MA</name>
              <bitOffset>0</bitOffset>
              <bitWidth>32</bitWidth>
            </field>
          </fields>
        </register>
        <register>
          <name>CCR5</name>
          <addressOffset>0x58</addressOffset>
          <size>0x20</size>
          <fields>
            <field>
              <name>EN</name>
              <bitOffset>0</bitOffset>
              <bitWidth>1</bitWidth>
            </field>
            <field>
              <name>TCIE</name>
              <bitOffset>1</bitOffset>
              <bitWidth>1</bitWidth>
            </field>
            <field>
              <name>HTIE</name>
              <bitOffset>2</bitOffset>
              <bitWidth>1</bitWidth>
            </field>
            <field>
              <name>TEIE</name>
              <bitOffset>3</bitOffset>
              <bitWidth>1</bitWidth>
            </field>
            <field>
              <name>DIR</name>
              <bitOffset>4</bitOffset>
              <bitWidth>1</bitWidth>
            </field>
            <field>
              <name>CIRC</name>
              <bitOffset>5</bitOffset>
              <bitWidth>1</bitWidth>
            </field>
            <field>
              <name>PINC</name>
              <bitOffset>6</bitOffset>
              <bitWidth>1</bitWidth>
            </field>
            <field>
              <name>MINC</name>
              <bitOffset>7</bitOffset>
              <bitWidth>1</bitWidth>
            </field>
            <field>
              <name>PSIZE</name>
              <bitOffset>8</bitOffset>
              <bitWidth>2</bitWidth>
            </field>
            <field>
              <name>MSIZE</name>
              <bitOffset>10</bitOffset>
              <bitWidth>2</bitWidth>
            </field>
            <field>
              <name>PL</name>
              <bitOffset>12</bitOffset>
              <bitWidth>2</bitWidth>
            </field>
            <field>
              <name>MEM2MEM</name>
              <bitOffset>14</bitOffset>
              <bitWidth>1</bitWidth>
            </field>
          </fields>
        </register>
        <register>
          <name>CNDTR5</name>
          <addressOffset>0x5c</addressOffset>
          <size>0x20</size>
          <fields>
            <field>
              <name>NDT</name>
              <bitOffset>0</bitOffset>
              <bitWidth>16</bitWidth>
            </field>
          </fields>
        </register>
        <register>
          <name>CPAR5</name>
          <addressOffset>0x60</addressOffset>
          <size>0x20</size>
          <fields>
            <field>
              <name>PA</name>
              <bitOffset>0</bitOffset>
              <bitWidth>32</bitWidth>
            </field>
          </fields>
        </register>
        <register>
          <name>CMAR5</name>
          <addressOffset>0x64</addressOffset>
          <size>0x20</size>
          <fields>
            <field>
              <name>MA</name>
              <bitOffset>0</bitOffset>
              <bitWidth>32</bitWidth>
            </field>
          </fields>
        </register>
        <register>
          <name>CCR6</name>
          <addressOffset>0x6c</addressOffset>
          <size>0x20</size>
          <fields>
            <field>
              <name>EN</name>
              <bitOffset>0</bitOffset>
              <bitWidth>1</bitWidth>
            </field>
            <field>
              <name>TCIE</name>
              <bitOffset>1</bitOffset>
              <bitWidth>1</bitWidth>
            </field>
            <field>
              <name>HTIE</name>
              <bitOffset>2</bitOffset>
              <bitWidth>1</bitWidth>
            </field>
            <field>
              <name>TEIE</name>
              <bitOffset>3</bitOffset>
              <bitWidth>1</bitWidth>
            </field>
            <field>
              <name>DIR</name>
              <bitOffset>4</bitOffset>
              <bitWidth>1</bitWidth>
            </field>
            <field>
              <name>CIRC</name>
              <bitOffset>5</bitOffset>
              <bitWidth>1</bitWidth>
            </field>
            <field>
              <name>PINC</name>
              <bitOffset>6</bitOffset>
              <bitWidth>1</bitWidth>
            </field>
            <field>
              <name>MINC</name>
              <bitOffset>7</bitOffset>
              <bitWidth>1</bitWidth>
            </field>
            <field>
              <name>PSIZE</name>
              <bitOffset>8</bitOffset>
              <bitWidth>2</bitWidth>
            </field>
            <field>
              <name>MSIZE</name>
              <bitOffset>10</bitOffset>
              <bitWidth>2</bitWidth>
            </field>
            <field>
              <name>PL</name>
              <bitOffset>12</bitOffset>
              <bitWidth>2</bitWidth>
            </field>
            <field>
              <name>MEM2MEM</name>
              <bitOffset>14</bitOffset>
              <bitWidth>1</bitWidth>
            </field>
          </fields>
        </register>
        <register>
          <name>CNDTR6</name>
          <addressOffset>0x70</addressOffset>
          <size>0x20</size>
          <fields>
            <field>
              <name>NDT</name>
              <bitOffset>0</bitOffset>
              <bitWidth>16</bitWidth>
            </field>
          </fields>
        </register>
        <register>
          <name>CPAR6</name>
          <addressOffset>0x74</addressOffset>
          <size>0x20</size>
          <fields>
            <field>
              <name>PA</name>
              <bitOffset>0</bitOffset>
              <bitWidth>32</bitWidth>
            </field>
          </fields>
        </register>
        <register>
          <name>CMAR6</name>
          <addressOffset>0x78</addressOffset>
          <size>0x20</size>
          <fields>
            <field>
              <name>MA</name>
              <bitOffset>0</bitOffset>
              <bitWidth>32</bitWidth>
            </field>
          </fields>
        </register>
        <register>
          <name>CCR7</name>
          <addressOffset>0x80</addressOffset>
          <size>0x20</size>
          <fields>
            <field>
              <name>EN</name>
              <bitOffset>0</bitOffset>
              <bitWidth>1</bitWidth>
            </field>
            <field>
              <name>TCIE</name>
              <bitOffset>1</bitOffset>
              <bitWidth>1</bitWidth>
            </field>
            <field>
              <name>HTIE</name>
              <bitOffset>2</bitOffset>
              <bitWidth>1</bitWidth>
            </field>
            <field>
              <name>TEIE</name>
              <bitOffset>3</bitOffset>
              <bitWidth>1</bitWidth>
            </field>
            <field>
              <name>DIR</name>
              <bitOffset>4</bitOffset>
              <bitWidth>1</bitWidth>
            </field>
            <field>
              <name>CIRC</name>
              <bitOffset>5</bitOffset>
              <bitWidth>1</bitWidth>
            </field>
            <field>
              <name>PINC</name>
              <bitOffset>6</bitOffset>
              <bitWidth>1</bitWidth>
            </field>
            <field>
              <name>MINC</name>
              <bitOffset>7</bitOffset>
              <bitWidth>1</bitWidth>
            </field>
            <field>
              <name>PSIZE</name>
              <bitOffset>8</bitOffset>
              <bitWidth>2</bitWidth>
            </field>
            <field>
              <name>MSIZE</name>
              <bitOffset>10</bitOffset>
              <bitWidth>2</bitWidth>
            </field>
            <field>
              <name>PL</name>
              <bitOffset>12</bitOffset>
              <bitWidth>2</bitWidth>
            </field>
            <field>
              <name>MEM2MEM</name>
              <bitOffset>14</bitOffset>
              <bitWidth>1</bitWidth>
            </field>
          </fields>
        </register>
        <register>
          <name>CNDTR7</name>
          <addressOffset>0x84</addressOffset>
          <size>0x20</size>
          <fields>
            <field>
              <name>NDT</name>
              <bitOffset>0</bitOffset>
              <bitWidth>16</bitWidth>
            </field>
          </fields>
        </register>
        <register>
          <name>CPAR7</name>
          <addressOffset>0x88</addressOffset>
          <size>0x20</size>
          <fields>
            <field>
              <name>PA</name>
              <bitOffset>0</bitOffset>
              <bitWidth>32</bitWidth>
            </field>
          </fields>
        </register>
        <register>
          <name>CMAR7</name>
          <addressOffset>0x8c</addressOffset>
          <size>0x20</size>
          <fields>
            <field>
              <name>MA</name>
              <bitOffset>0</bitOffset>
              <bitWidth>32</bitWidth>
            </field>
          </fields>
        </register>
      </registers>
    </peripheral>
    <peripheral>
      <name>DBGMCU</name>
      <baseAddress>0xe0042000</baseAddress>
      <registers>
        <register>
          <name>IDCODE</name>
          <addressOffset>0x0</addressOffset>
          <size>0x20</size>
          <fields>
            <field>
              <name>DEV_ID</name>
              <bitOffset>0</bitOffset>
              <bitWidth>12</bitWidth>
            </field>
            <field>
              <name>REV_ID</name>
              <bitOffset>16</bitOffset>
              <bitWidth>16</bitWidth>
            </field>
          </fields>
        </register>
        <register>
          <name>CR</name>
          <addressOffset>0x4</addressOffset>
          <size>0x20</size>
          <fields>
            <field>
              <name>DBG_SLEEP</name>
              <bitOffset>0</bitOffset>
              <bitWidth>1</bitWidth>
            </field>
            <field>
              <name>DBG_STOP</name>
              <bitOffset>1</bitOffset>
              <bitWidth>1</bitWidth>
            </field>
            <field>
              <name>DBG_STANDBY</name>
              <bitOffset>2</bitOffset>
              <bitWidth>1</bitWidth>
            </field>
            <field>
              <name>TRACE_IOEN</name>
              <bitOffset>5</bitOffset>
              <bitWidth>1</bitWidth>
            </field>
            <field>
              <name>TRACE_MODE</name>
              <bitOffset>6</bitOffset>
              <bitWidth>2</bitWidth>
            </field>
          </fields>
        </register>
        <register>
          <name>APB1FZ</name>
          <addressOffset>0x8</addressOffset>
          <size>0x20</size>
          <fields>
            <field>
              <name>DBG_TIM2_STOP</name>
              <bitOffset>0</bitOffset>
              <bitWidth>1</bitWidth>
            </field>
            <field>
              <name>DBG_TIM3_STOP</name>
              <bitOffset>1</bitOffset>
              <bitWidth>1</bitWidth>
            </field>
            <field>
              <name>DBG_TIM4_STOP</name>
              <bitOffset>2</bitOffset>
              <bitWidth>1</bitWidth>
            </field>
            <field>
              <name>DBG_TIM6_STOP</name>
              <bitOffset>4</bitOffset>
              <bitWidth>1</bitWidth>
            </field>
            <field>
              <name>DBG_TIM7_STOP</name>
              <bitOffset>5</bitOffset>
              <bitWidth>1</bitWidth>
            </field>
            <field>
              <name>DBG_WWDG_STOP</name>
              <bitOffset>11</bitOffset>
              <bitWidth>1</bitWidth>
            </field>
            <field>
              <name>DBG_IWDG_STOP</name>
              <bitOffset>12</bitOffset>
              <bitWidth>1</bitWidth>
            </field>
            <field>
              <name>DBG_I2C1_SMBUS_TIMEOUT</name>
              <bitOffset>21</bitOffset>
              <bitWidth>1</bitWidth>
            </field>
            <field>
              <name>DBG_I2C2_SMBUS_TIMEOUT</name>
              <bitOffset>22</bitOffset>
              <bitWidth>1</bitWidth>
            </field>
          </fields>
        </register>
        <register>
          <name>APB2FZ</name>
          <addressOffset>0xc</addressOffset>
          <size>0x20</size>
          <fields>
            <field>
              <name>DBG_TIM9_STOP</name>
              <bitOffset>2</bitOffset>
              <bitWidth>1</bitWidth>
            </field>
            <field>
              <name>DBG_TIM10_STOP</name>
              <bitOffset>3</bitOffset>
              <bitWidth>1</bitWidth>
            </field>
            <field>
              <name>DBG_TIM11_STOP</name>
              <bitOffset>4</bitOffset>
              <bitWidth>1</bitWidth>
            </field>
          </fields>
        </register>
      </registers>
    </peripheral>
  </peripherals>
</device>
